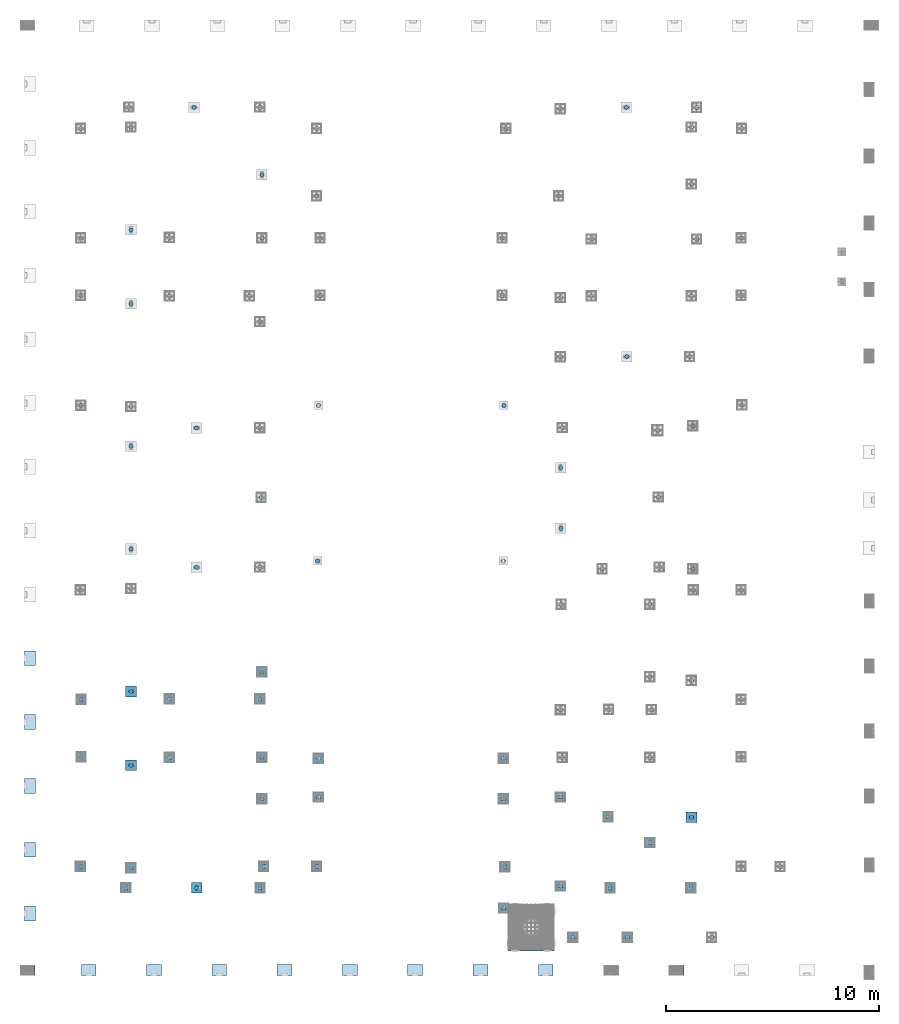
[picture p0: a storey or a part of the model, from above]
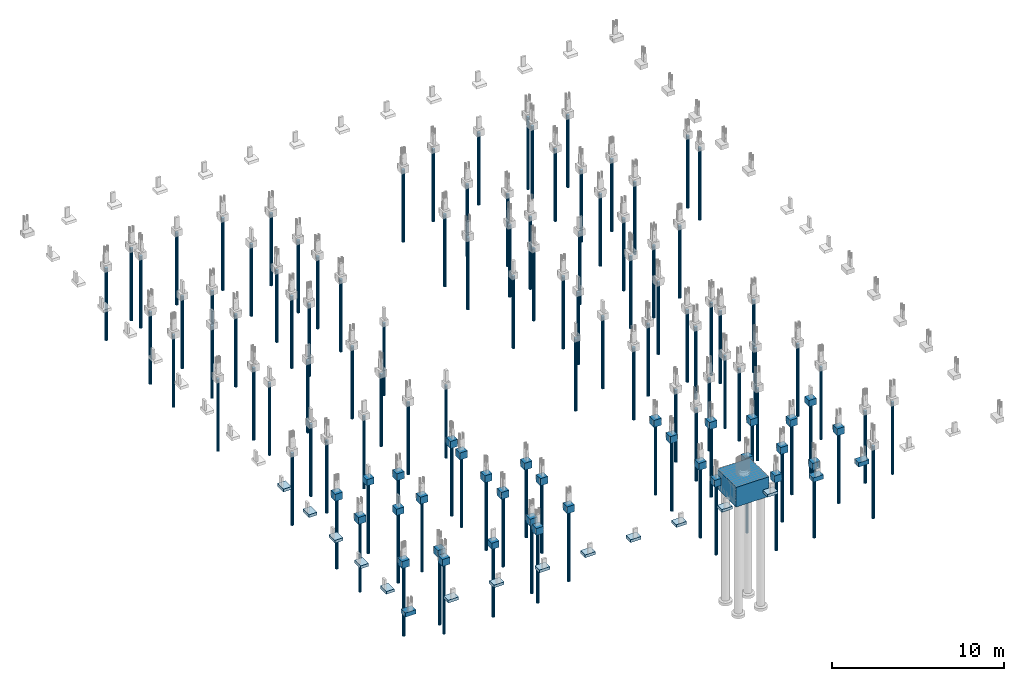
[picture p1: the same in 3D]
Properties of the parts of a building model (IFC4), part 1 of 9

# File
Description: ViewDefinition[]
File name: TIPO2-SCO-MOD_R03.IFC
Time: 2026-01-27T16:08:47+00:00
Organization: FUNDO NACIONAL DE DESENVOLVIMENTO DA EDUCAÇAO - FNDE
Written by: IfcOpenShell 0.8.3-post1
Made in: Bonsai 0.8.3-post1

# IfcProject, PROJETO PADRÃO - FNDE
Description: CRECHE PRÉ-ESCOLA TIPO 2; LongName: PROJETO DE ESTRUTURA DE CONCRETO; Phase: PROJETO PADRÃO

# IfcBuildingStorey (4)
In: CRECHE PRÉ-ESCOLA TIPO 2
Name | Elevation (cm)
FUNDAÇÃO | -14
VIGA BALDRAME | 16
TERREO | 326
COBERTURA | 456

# IfcBeam (614)
Material: Concreto
Pset_ConcreteElementGeneral - ConcreteCover: 2 cm; ConstructionMethod: InSitu; ExposureClass: 1; StrengthClass: C-30
AltoQi_Eberick_Elemento - Elemento: Viga; Tipo: retangular
AltoQi_Eberick_Padrão - Ambiente: Interno; Cobrimento: 2 cm; Classe de concreto: C-30
AltoQi_Eberick-Item_01 - Status_01: Dimensionado
AltoQi_Eberick-Item_02 - Status_02: Dimensionado
AltoQi_Eberick-Item_03 - Status_03: Dimensionado
AltoQi_Eberick_Cargas - Solo (S): 0; Acidental (Q): 0; Água (A): 0; Subpressão (AS): 0
Pset_BeamCommon - IsExternal: no; LoadBearing: yes
Name | In | Seção_bw (cm) | Seção_h (cm) | Elevação (cm) | Taxa de armadura | Descrição_01 | AltoQi_Eberick-Item_01, Quantidade_01 (m3) | Descrição_02 | AltoQi_Eberick-Item_02, Quantidade_02 (m2) | Descrição_03 | Quantidade_03 (kg) | Descrição_04 | AltoQi_Eberick-Item_04, Quantidade_04 (kg) | Status_04 | Cargas de parede (G2) | Adicional (G2) | Reference
V101 | VIGA BALDRAME | 15 | 30 | 0 | 0.22 % | Concreto - C-30 - Abatimento 12 cm | 0.137556 | Forma - Estrutura - Concreto | 2.29259 | Armadura - Aço CA50 - ø 8.0 mm | 5.03846 | Armadura - Aço CA60 - ø 5.0 mm | 1.91215 | Dimensionado | 567 | 0 | Viga C-30 - Seção Retangular 15 X 30
7 x V101 | VIGA BALDRAME | 15 | 30 | 0 | 0.22 % | Concreto - C-30 - Abatimento 12 cm | 0.137104 | Forma - Estrutura - Concreto | 2.28507 | Armadura - Aço CA50 - ø 8.0 mm | 5.02194 | Armadura - Aço CA60 - ø 5.0 mm | 1.90588 | Dimensionado | 567 | 0 | Viga C-30 - Seção Retangular 15 X 30
V101 | VIGA BALDRAME | 15 | 30 | 0 | 0.22 % | Concreto - C-30 - Abatimento 12 cm | 0.136653 | Forma - Estrutura - Concreto | 2.27756 | Armadura - Aço CA50 - ø 8.0 mm | 5.00541 | Armadura - Aço CA60 - ø 5.0 mm | 1.89961 | Dimensionado | 567 | 0 | Viga C-30 - Seção Retangular 15 X 30
V101 | VIGA BALDRAME | 15 | 30 | 0 | 0.22 % | Concreto - C-30 - Abatimento 12 cm | 0.139337 | Forma - Estrutura - Concreto | 2.32229 | Armadura - Aço CA50 - ø 8.0 mm | 5.10372 | Armadura - Aço CA60 - ø 5.0 mm | 1.93692 | Dimensionado | 567 | 0 | Viga C-30 - Seção Retangular 15 X 30
V101 | VIGA BALDRAME | 15 | 30 | 0 | 0.22 % | Concreto - C-30 - Abatimento 12 cm | 0.137105 | Forma - Estrutura - Concreto | 2.28508 | Armadura - Aço CA50 - ø 8.0 mm | 5.02194 | Armadura - Aço CA60 - ø 5.0 mm | 1.90588 | Dimensionado | 567 | 0 | Viga C-30 - Seção Retangular 15 X 30
V101 | VIGA BALDRAME | 15 | 30 | 0 | 0.22 % | Concreto - C-30 - Abatimento 12 cm | 0.137116 | Forma - Estrutura - Concreto | 2.28527 | Armadura - Aço CA50 - ø 8.0 mm | 5.02237 | Armadura - Aço CA60 - ø 5.0 mm | 1.90604 | Dimensionado | 567 | 0 | Viga C-30 - Seção Retangular 15 X 30
V101 | VIGA BALDRAME | 15 | 30 | 0 | 0.22 % | Concreto - C-30 - Abatimento 12 cm | 0.124377 | Forma - Estrutura - Concreto | 2.07294 | Armadura - Aço CA50 - ø 8.0 mm | 4.55573 | Armadura - Aço CA60 - ø 5.0 mm | 1.72895 | Dimensionado | 567 | 0 | Viga C-30 - Seção Retangular 15 X 30
V102 | VIGA BALDRAME | 20 | 30 | 0 | 0.17 % | Concreto - C-30 - Abatimento 12 cm | 0.183687 | Forma - Estrutura - Concreto | 2.44916 | Armadura - Aço CA50 - ø 8.0 mm | 2.60127 | Armadura - Aço CA50 - ø 10.0 mm | 4.11844 | Dimensionado | 1116 | 0 | Viga C-30 - Seção Retangular 20 X 30 | AltoQi_Eberick-Item_05 - Descrição_05: Armadura - Aço CA60 - ø 5.0 mm; Quantidade_05: 3.10681 kg; Status_05: Dimensionado
V102 | VIGA BALDRAME | 20 | 30 | 0 | 0.17 % | Concreto - C-30 - Abatimento 12 cm | 0.180913 | Forma - Estrutura - Concreto | 2.41217 | Armadura - Aço CA50 - ø 8.0 mm | 2.56198 | Armadura - Aço CA50 - ø 10.0 mm | 4.05624 | Dimensionado | 1116 | 0 | Viga C-30 - Seção Retangular 20 X 30 | AltoQi_Eberick-Item_05 - Descrição_05: Armadura - Aço CA60 - ø 5.0 mm; Quantidade_05: 3.05989 kg; Status_05: Dimensionado
V102 | VIGA BALDRAME | 20 | 30 | 0 | 0.17 % | Concreto - C-30 - Abatimento 12 cm | 0.013226 | Forma - Estrutura - Concreto | 0.176353 | Armadura - Aço CA50 - ø 8.0 mm | 0.187306 | Armadura - Aço CA50 - ø 10.0 mm | 0.29655 | Dimensionado | 1116 | 0 | Viga C-30 - Seção Retangular 20 X 30 | AltoQi_Eberick-Item_05 - Descrição_05: Armadura - Aço CA60 - ø 5.0 mm; Quantidade_05: 0.223708 kg; Status_05: Dimensionado
V103 | VIGA BALDRAME | 20 | 30 | 0 | 0.26 % | Concreto - C-30 - Abatimento 12 cm | 0.201368 | Forma - Estrutura - Concreto | 2.72628 | Armadura - Aço CA50 - ø 10.0 mm | 8.57005 | Armadura - Aço CA60 - ø 5.0 mm | 3.02885 | Dimensionado | 1116 | 0 | Viga C-30 - Seção Retangular 20 X 30
V103 | VIGA BALDRAME | 20 | 30 | 0 | 0.26 % | Concreto - C-30 - Abatimento 12 cm | 0.188032 | Forma - Estrutura - Concreto | 2.54572 | Armadura - Aço CA50 - ø 10.0 mm | 8.00248 | Armadura - Aço CA60 - ø 5.0 mm | 2.82826 | Dimensionado | 1116 | 0 | Viga C-30 - Seção Retangular 20 X 30
V104 | VIGA BALDRAME | 20 | 30 | 0 | 0.17 % | Concreto - C-30 - Abatimento 12 cm | 0.020966 | Forma - Estrutura - Concreto | 0.279542 | Armadura - Aço CA50 - ø 8.0 mm | 0.294816 | Armadura - Aço CA50 - ø 10.0 mm | 0.512554 | Dimensionado | 1116 | 0 | Viga C-30 - Seção Retangular 20 X 30 | AltoQi_Eberick-Item_05 - Descrição_05: Armadura - Aço CA60 - ø 5.0 mm; Quantidade_05: 0.465111 kg; Status_05: Dimensionado
V104 | VIGA BALDRAME | 20 | 30 | 0 | 0.17 % | Concreto - C-30 - Abatimento 12 cm | 0.138418 | Forma - Estrutura - Concreto | 1.84558 | Armadura - Aço CA50 - ø 8.0 mm | 1.94642 | Armadura - Aço CA50 - ø 10.0 mm | 3.38396 | Dimensionado | 1116 | 0 | Viga C-30 - Seção Retangular 20 X 30 | AltoQi_Eberick-Item_05 - Descrição_05: Armadura - Aço CA60 - ø 5.0 mm; Quantidade_05: 3.07073 kg; Status_05: Dimensionado
V105 | VIGA BALDRAME | 20 | 30 | 0 | 0.17 % | Concreto - C-30 - Abatimento 12 cm | 0.147504 | Forma - Estrutura - Concreto | 1.96672 | Armadura - Aço CA50 - ø 8.0 mm | 4.70344 | Armadura - Aço CA60 - ø 5.0 mm | 2.34284 | Dimensionado | 1116 | 0 | Viga C-30 - Seção Retangular 20 X 30
V106 | VIGA BALDRAME | 20 | 30 | 0 | 0.17 % | Concreto - C-30 - Abatimento 12 cm | 0.157662 | Forma - Estrutura - Concreto | 2.10216 | Armadura - Aço CA50 - ø 8.0 mm | 2.20178 | Armadura - Aço CA50 - ø 10.0 mm | 3.84719 | Dimensionado | 1116 | 0 | Viga C-30 - Seção Retangular 20 X 30 | AltoQi_Eberick-Item_05 - Descrição_05: Armadura - Aço CA60 - ø 5.0 mm; Quantidade_05: 2.34284 kg; Status_05: Dimensionado
V107 | VIGA BALDRAME | 20 | 30 | 0 | 0.17 % | Concreto - C-30 - Abatimento 12 cm | 0.138302 | Forma - Estrutura - Concreto | 1.84403 | Armadura - Aço CA50 - ø 8.0 mm | 1.88429 | Armadura - Aço CA50 - ø 10.0 mm | 3.37245 | Dimensionado | 1116 | 0 | Viga C-30 - Seção Retangular 20 X 30 | AltoQi_Eberick-Item_05 - Descrição_05: Armadura - Aço CA60 - ø 5.0 mm; Quantidade_05: 3.07 kg; Status_05: Dimensionado
V107 | VIGA BALDRAME | 20 | 30 | 0 | 0.17 % | Concreto - C-30 - Abatimento 12 cm | 0.020986 | Forma - Estrutura - Concreto | 0.279813 | Armadura - Aço CA50 - ø 8.0 mm | 0.285923 | Armadura - Aço CA50 - ø 10.0 mm | 0.511736 | Dimensionado | 1116 | 0 | Viga C-30 - Seção Retangular 20 X 30 | AltoQi_Eberick-Item_05 - Descrição_05: Armadura - Aço CA60 - ø 5.0 mm; Quantidade_05: 0.465843 kg; Status_05: Dimensionado
V108 | VIGA BALDRAME | 20 | 30 | 0 | 0.17 % | Concreto - C-30 - Abatimento 12 cm | 0.165504 | Forma - Estrutura - Concreto | 2.20672 | Armadura - Aço CA50 - ø 8.0 mm | 4.70344 | Armadura - Aço CA60 - ø 5.0 mm | 2.48927 | Dimensionado | 1116 | 0 | Viga C-30 - Seção Retangular 20 X 30
V109 | VIGA BALDRAME | 20 | 30 | 0 | 0.17 % | Concreto - C-30 - Abatimento 12 cm | 0.168445 | Forma - Estrutura - Concreto | 2.2461 | Armadura - Aço CA50 - ø 8.0 mm | 2.186 | Armadura - Aço CA50 - ø 12.5 mm | 6.53144 | Dimensionado | 1116 | 0 | Viga C-30 - Seção Retangular 20 X 30 | AltoQi_Eberick-Item_05 - Descrição_05: Armadura - Aço CA60 - ø 5.0 mm; Quantidade_05: 2.34284 kg; Status_05: Dimensionado
V110 | VIGA BALDRAME | 20 | 30 | 0 | 0.41 % | Concreto - C-30 - Abatimento 12 cm | 0.014043 | Forma - Estrutura - Concreto | 0.191987 | Armadura - Aço CA50 - ø 8.0 mm | 0.125344 | Armadura - Aço CA50 - ø 12.5 mm | 0.65757 | Dimensionado | 1116 | 0 | Viga C-30 - Seção Retangular 20 X 30 | AltoQi_Eberick-Item_05 - Descrição_05: Armadura - Aço CA50 - ø 16.0 mm; Quantidade_05: 0.282218 kg; Status_05: Dimensionado; AltoQi_Eberick-Item_06 - Descrição_06: Armadura - Aço CA60 - ø 5.0 mm; Quantidade_06: 0.258866 kg; Status_06: Dimensionado
V110 | VIGA BALDRAME | 20 | 30 | 0 | 0.17 % | Concreto - C-30 - Abatimento 12 cm | 0.252038 | Forma - Estrutura - Concreto | 3.4457 | Armadura - Aço CA50 - ø 8.0 mm | 2.24961 | Armadura - Aço CA50 - ø 12.5 mm | 11.8018 | Dimensionado | 1116 | 0 | Viga C-30 - Seção Retangular 20 X 30 | AltoQi_Eberick-Item_05 - Descrição_05: Armadura - Aço CA50 - ø 16.0 mm; Quantidade_05: 5.06513 kg; Status_05: Dimensionado; AltoQi_Eberick-Item_06 - Descrição_06: Armadura - Aço CA60 - ø 5.0 mm; Quantidade_06: 4.64602 kg; Status_06: Dimensionado
V110 | VIGA BALDRAME | 20 | 30 | 0 | 0.67 % | Concreto - C-30 - Abatimento 12 cm | 0.261612 | Forma - Estrutura - Concreto | 3.5766 | Armadura - Aço CA50 - ø 8.0 mm | 2.33507 | Armadura - Aço CA50 - ø 12.5 mm | 12.2501 | Dimensionado | 1116 | 0 | Viga C-30 - Seção Retangular 20 X 30 | AltoQi_Eberick-Item_05 - Descrição_05: Armadura - Aço CA50 - ø 16.0 mm; Quantidade_05: 5.25755 kg; Status_05: Dimensionado; AltoQi_Eberick-Item_06 - Descrição_06: Armadura - Aço CA60 - ø 5.0 mm; Quantidade_06: 4.82252 kg; Status_06: Dimensionado
V110 | VIGA BALDRAME | 20 | 30 | 0 | 0.17 % | Concreto - C-30 - Abatimento 12 cm | 0.165274 | Forma - Estrutura - Concreto | 2.25952 | Armadura - Aço CA50 - ø 8.0 mm | 1.47518 | Armadura - Aço CA50 - ø 12.5 mm | 7.73901 | Dimensionado | 1116 | 0 | Viga C-30 - Seção Retangular 20 X 30 | AltoQi_Eberick-Item_05 - Descrição_05: Armadura - Aço CA50 - ø 16.0 mm; Quantidade_05: 3.32146 kg; Status_05: Dimensionado; AltoQi_Eberick-Item_06 - Descrição_06: Armadura - Aço CA60 - ø 5.0 mm; Quantidade_06: 3.04663 kg; Status_06: Dimensionado
V110 | VIGA BALDRAME | 20 | 30 | 0 | 0.17 % | Concreto - C-30 - Abatimento 12 cm | 0.017008 | Forma - Estrutura - Concreto | 0.232517 | Armadura - Aço CA50 - ø 8.0 mm | 0.151804 | Armadura - Aço CA50 - ø 12.5 mm | 0.796387 | Dimensionado | 1116 | 0 | Viga C-30 - Seção Retangular 20 X 30 | AltoQi_Eberick-Item_05 - Descrição_05: Armadura - Aço CA50 - ø 16.0 mm; Quantidade_05: 0.341796 kg; Status_05: Dimensionado; AltoQi_Eberick-Item_06 - Descrição_06: Armadura - Aço CA60 - ø 5.0 mm; Quantidade_06: 0.313515 kg; Status_06: Dimensionado
V111 | VIGA BALDRAME | 20 | 30 | 0 | 0.67 % | Concreto - C-30 - Abatimento 12 cm | 0.302538 | Forma - Estrutura - Concreto | 4.06756 | Armadura - Aço CA50 - ø 8.0 mm | 0.931239 | Armadura - Aço CA50 - ø 12.5 mm | 17.6361 | Dimensionado | 1116 | 0 | Viga C-30 - Seção Retangular 20 X 30 | AltoQi_Eberick-Item_05 - Descrição_05: Armadura - Aço CA50 - ø 16.0 mm; Quantidade_05: 6.94438 kg; Status_05: Dimensionado; AltoQi_Eberick-Item_06 - Descrição_06: Armadura - Aço CA60 - ø 5.0 mm; Quantidade_06: 5.76243 kg; Status_06: Dimensionado
V111 | VIGA BALDRAME | 20 | 30 | 0 | 0.17 % | Concreto - C-30 - Abatimento 12 cm | 0.127486 | Forma - Estrutura - Concreto | 1.71402 | Armadura - Aço CA50 - ø 8.0 mm | 0.392414 | Armadura - Aço CA50 - ø 12.5 mm | 7.43167 | Dimensionado | 1116 | 0 | Viga C-30 - Seção Retangular 20 X 30 | AltoQi_Eberick-Item_05 - Descrição_05: Armadura - Aço CA50 - ø 16.0 mm; Quantidade_05: 2.92629 kg; Status_05: Dimensionado; AltoQi_Eberick-Item_06 - Descrição_06: Armadura - Aço CA60 - ø 5.0 mm; Quantidade_06: 2.42823 kg; Status_06: Dimensionado
V111 | VIGA BALDRAME | 20 | 30 | 0 | 0.17 % | Concreto - C-30 - Abatimento 12 cm | 0.017366 | Forma - Estrutura - Concreto | 0.233488 | Armadura - Aço CA50 - ø 8.0 mm | 0.053455 | Armadura - Aço CA50 - ø 12.5 mm | 1.01236 | Dimensionado | 1116 | 0 | Viga C-30 - Seção Retangular 20 X 30 | AltoQi_Eberick-Item_05 - Descrição_05: Armadura - Aço CA50 - ø 16.0 mm; Quantidade_05: 0.398624 kg; Status_05: Dimensionado; AltoQi_Eberick-Item_06 - Descrição_06: Armadura - Aço CA60 - ø 5.0 mm; Quantidade_06: 0.330777 kg; Status_06: Dimensionado
V111 | VIGA BALDRAME | 20 | 30 | 0 | 0.41 % | Concreto - C-30 - Abatimento 12 cm | 0.014775 | Forma - Estrutura - Concreto | 0.198645 | Armadura - Aço CA50 - ø 8.0 mm | 0.045478 | Armadura - Aço CA50 - ø 12.5 mm | 0.861284 | Dimensionado | 1116 | 0 | Viga C-30 - Seção Retangular 20 X 30 | AltoQi_Eberick-Item_05 - Descrição_05: Armadura - Aço CA50 - ø 16.0 mm; Quantidade_05: 0.339139 kg; Status_05: Dimensionado; AltoQi_Eberick-Item_06 - Descrição_06: Armadura - Aço CA60 - ø 5.0 mm; Quantidade_06: 0.281416 kg; Status_06: Dimensionado
V111 | VIGA BALDRAME | 20 | 30 | 0 | 0.41 % | Concreto - C-30 - Abatimento 12 cm | 0.255705 | Forma - Estrutura - Concreto | 3.4379 | Armadura - Aço CA50 - ø 8.0 mm | 0.787084 | Armadura - Aço CA50 - ø 12.5 mm | 14.9061 | Dimensionado | 1116 | 0 | Viga C-30 - Seção Retangular 20 X 30 | AltoQi_Eberick-Item_05 - Descrição_05: Armadura - Aço CA50 - ø 16.0 mm; Quantidade_05: 5.86939 kg; Status_05: Dimensionado; AltoQi_Eberick-Item_06 - Descrição_06: Armadura - Aço CA60 - ø 5.0 mm; Quantidade_06: 4.87041 kg; Status_06: Dimensionado
V112 | VIGA BALDRAME | 15 | 30 | 0 | 0.22 % | Concreto - C-30 - Abatimento 12 cm | 0.05985 | Forma - Estrutura - Concreto | 0.9975 | Armadura - Aço CA50 - ø 8.0 mm | 2.82522 | Armadura - Aço CA60 - ø 5.0 mm | 0.786085 | Dimensionado | 837 | 0 | Viga C-30 - Seção Retangular 15 X 30
V113 | VIGA BALDRAME | 20 | 30 | 0 | 0.17 % | Concreto - C-30 - Abatimento 12 cm | 0.25504 | Forma - Estrutura - Concreto | 3.48574 | Armadura - Aço CA50 - ø 8.0 mm | 1.33923 | Armadura - Aço CA50 - ø 10.0 mm | 10.2307 | Dimensionado | 1116 | 0 | Viga C-30 - Seção Retangular 20 X 30 | AltoQi_Eberick-Item_05 - Descrição_05: Armadura - Aço CA60 - ø 5.0 mm; Quantidade_05: 4.59441 kg; Status_05: Dimensionado
V113 | VIGA BALDRAME | 20 | 30 | 0 | 0.26 % | Concreto - C-30 - Abatimento 12 cm | 0.202747 | Forma - Estrutura - Concreto | 2.77102 | Armadura - Aço CA50 - ø 8.0 mm | 1.06463 | Armadura - Aço CA50 - ø 10.0 mm | 8.13301 | Dimensionado | 1116 | 0 | Viga C-30 - Seção Retangular 20 X 30 | AltoQi_Eberick-Item_05 - Descrição_05: Armadura - Aço CA60 - ø 5.0 mm; Quantidade_05: 3.65237 kg; Status_05: Dimensionado
V113 | VIGA BALDRAME | 20 | 30 | 0 | 0.26 % | Concreto - C-30 - Abatimento 12 cm | 0.016949 | Forma - Estrutura - Concreto | 0.23165 | Armadura - Aço CA50 - ø 8.0 mm | 0.089 | Armadura - Aço CA50 - ø 10.0 mm | 0.679896 | Dimensionado | 1116 | 0 | Viga C-30 - Seção Retangular 20 X 30 | AltoQi_Eberick-Item_05 - Descrição_05: Armadura - Aço CA60 - ø 5.0 mm; Quantidade_05: 0.305328 kg; Status_05: Dimensionado
V113 | VIGA BALDRAME | 20 | 30 | 0 | 0.17 % | Concreto - C-30 - Abatimento 12 cm | 0.014194 | Forma - Estrutura - Concreto | 0.194 | Armadura - Aço CA50 - ø 8.0 mm | 0.074535 | Armadura - Aço CA50 - ø 10.0 mm | 0.569394 | Dimensionado | 1116 | 0 | Viga C-30 - Seção Retangular 20 X 30 | AltoQi_Eberick-Item_05 - Descrição_05: Armadura - Aço CA60 - ø 5.0 mm; Quantidade_05: 0.255703 kg; Status_05: Dimensionado
V113 | VIGA BALDRAME | 20 | 30 | 0 | 0.26 % | Concreto - C-30 - Abatimento 12 cm | 0.229444 | Forma - Estrutura - Concreto | 3.13591 | Armadura - Aço CA50 - ø 8.0 mm | 1.20482 | Armadura - Aço CA50 - ø 10.0 mm | 9.20395 | Dimensionado | 1116 | 0 | Viga C-30 - Seção Retangular 20 X 30 | AltoQi_Eberick-Item_05 - Descrição_05: Armadura - Aço CA60 - ø 5.0 mm; Quantidade_05: 4.13331 kg; Status_05: Dimensionado
V114 | VIGA BALDRAME | 20 | 30 | 0 | 0.41 % | Concreto - C-30 - Abatimento 12 cm | 0.014778 | Forma - Estrutura - Concreto | 0.19539 | Armadura - Aço CA50 - ø 10.0 mm | 0.524931 | Armadura - Aço CA50 - ø 12.5 mm | 0.590365 | Dimensionado | 1116 | 0 | Viga C-30 - Seção Retangular 20 X 30 | AltoQi_Eberick-Item_05 - Descrição_05: Armadura - Aço CA60 - ø 5.0 mm; Quantidade_05: 0.305586 kg; Status_05: Dimensionado
V114 | VIGA BALDRAME | 20 | 30 | 0 | 0.41 % | Concreto - C-30 - Abatimento 12 cm | 0.167685 | Forma - Estrutura - Concreto | 2.21711 | Armadura - Aço CA50 - ø 10.0 mm | 5.95645 | Armadura - Aço CA50 - ø 12.5 mm | 6.69893 | Dimensionado | 1116 | 0 | Viga C-30 - Seção Retangular 20 X 30 | AltoQi_Eberick-Item_05 - Descrição_05: Armadura - Aço CA60 - ø 5.0 mm; Quantidade_05: 3.46751 kg; Status_05: Dimensionado
V114 | VIGA BALDRAME | 20 | 30 | 0 | 0.41 % | Concreto - C-30 - Abatimento 12 cm | 0.088265 | Forma - Estrutura - Concreto | 1.16702 | Armadura - Aço CA50 - ø 10.0 mm | 3.13531 | Armadura - Aço CA50 - ø 12.5 mm | 3.52614 | Dimensionado | 1116 | 0 | Viga C-30 - Seção Retangular 20 X 30 | AltoQi_Eberick-Item_05 - Descrição_05: Armadura - Aço CA60 - ø 5.0 mm; Quantidade_05: 1.8252 kg; Status_05: Dimensionado
V114 | VIGA BALDRAME | 20 | 30 | 0 | 0.61 % | Concreto - C-30 - Abatimento 12 cm | 0.286984 | Forma - Estrutura - Concreto | 3.79447 | Armadura - Aço CA50 - ø 10.0 mm | 10.1942 | Armadura - Aço CA50 - ø 12.5 mm | 11.4649 | Dimensionado | 1116 | 0 | Viga C-30 - Seção Retangular 20 X 30 | AltoQi_Eberick-Item_05 - Descrição_05: Armadura - Aço CA60 - ø 5.0 mm; Quantidade_05: 5.93447 kg; Status_05: Dimensionado
V114 | VIGA BALDRAME | 20 | 30 | 0 | 0.41 % | Concreto - C-30 - Abatimento 12 cm | 0.01737 | Forma - Estrutura - Concreto | 0.229661 | Armadura - Aço CA50 - ø 10.0 mm | 0.617005 | Armadura - Aço CA50 - ø 12.5 mm | 0.693916 | Dimensionado | 1116 | 0 | Viga C-30 - Seção Retangular 20 X 30 | AltoQi_Eberick-Item_05 - Descrição_05: Armadura - Aço CA60 - ø 5.0 mm; Quantidade_05: 0.359186 kg; Status_05: Dimensionado
V114 | VIGA BALDRAME | 20 | 30 | 0 | 0.41 % | Concreto - C-30 - Abatimento 12 cm | 0.14279 | Forma - Estrutura - Concreto | 1.88795 | Armadura - Aço CA50 - ø 10.0 mm | 5.07214 | Armadura - Aço CA50 - ø 12.5 mm | 5.70439 | Dimensionado | 1116 | 0 | Viga C-30 - Seção Retangular 20 X 30 | AltoQi_Eberick-Item_05 - Descrição_05: Armadura - Aço CA60 - ø 5.0 mm; Quantidade_05: 2.95272 kg; Status_05: Dimensionado
V115 | VIGA BALDRAME | 20 | 30 | 0 | 0.26 % | Concreto - C-30 - Abatimento 12 cm | 0.047112 | Forma - Estrutura - Concreto | 0.62816 | Armadura - Aço CA50 - ø 10.0 mm | 2.50314 | Armadura - Aço CA60 - ø 5.0 mm | 1.02499 | Dimensionado | 1116 | 0 | Viga C-30 - Seção Retangular 20 X 30
V116 | VIGA BALDRAME | 20 | 30 | 0 | 0.26 % | Concreto - C-30 - Abatimento 12 cm | 0.180244 | Forma - Estrutura - Concreto | 2.40325 | Armadura - Aço CA50 - ø 8.0 mm | 2.94893 | Armadura - Aço CA50 - ø 10.0 mm | 3.76446 | Dimensionado | 1116 | 0 | Viga C-30 - Seção Retangular 20 X 30 | AltoQi_Eberick-Item_05 - Descrição_05: Armadura - Aço CA60 - ø 5.0 mm; Quantidade_05: 2.64642 kg; Status_05: Dimensionado
V116 | VIGA BALDRAME | 20 | 30 | 0 | 0.26 % | Concreto - C-30 - Abatimento 12 cm | 0.188756 | Forma - Estrutura - Concreto | 2.51675 | Armadura - Aço CA50 - ø 8.0 mm | 3.08821 | Armadura - Aço CA50 - ø 10.0 mm | 3.94226 | Dimensionado | 1116 | 0 | Viga C-30 - Seção Retangular 20 X 30 | AltoQi_Eberick-Item_05 - Descrição_05: Armadura - Aço CA60 - ø 5.0 mm; Quantidade_05: 2.77141 kg; Status_05: Dimensionado
V117 | VIGA BALDRAME | 20 | 30 | 0 | 0.17 % | Concreto - C-30 - Abatimento 12 cm | 0.021576 | Forma - Estrutura - Concreto | 0.287681 | Armadura - Aço CA50 - ø 8.0 mm | 0.638849 | Armadura - Aço CA60 - ø 5.0 mm | 0.356798 | Dimensionado | 1116 | 0 | Viga C-30 - Seção Retangular 20 X 30
V117 | VIGA BALDRAME | 20 | 30 | 0 | 0.17 % | Concreto - C-30 - Abatimento 12 cm | 0.137808 | Forma - Estrutura - Concreto | 1.83744 | Armadura - Aço CA50 - ø 8.0 mm | 4.08038 | Armadura - Aço CA60 - ø 5.0 mm | 2.2789 | Dimensionado | 1116 | 0 | Viga C-30 - Seção Retangular 20 X 30
V118 | VIGA BALDRAME | 20 | 30 | 0 | 0.17 % | Concreto - C-30 - Abatimento 12 cm | 0.021 | Forma - Estrutura - Concreto | 0.28 | Armadura - Aço CA50 - ø 8.0 mm | 0.282797 | Armadura - Aço CA50 - ø 10.0 mm | 0.516308 | Dimensionado | 1116 | 0 | Viga C-30 - Seção Retangular 20 X 30 | AltoQi_Eberick-Item_05 - Descrição_05: Armadura - Aço CA60 - ø 5.0 mm; Quantidade_05: 0.433754 kg; Status_05: Dimensionado
V118 | VIGA BALDRAME | 20 | 30 | 0 | 0.17 % | Concreto - C-30 - Abatimento 12 cm | 0.1425 | Forma - Estrutura - Concreto | 1.9 | Armadura - Aço CA50 - ø 8.0 mm | 1.91898 | Armadura - Aço CA50 - ø 10.0 mm | 3.50352 | Dimensionado | 1116 | 0 | Viga C-30 - Seção Retangular 20 X 30 | AltoQi_Eberick-Item_05 - Descrição_05: Armadura - Aço CA60 - ø 5.0 mm; Quantidade_05: 2.94333 kg; Status_05: Dimensionado
V119 | VIGA BALDRAME | 15 | 30 | 0 | 0.22 % | Concreto - C-30 - Abatimento 12 cm | 0.02529 | Forma - Estrutura - Concreto | 0.4215 | Armadura - Aço CA50 - ø 8.0 mm | 1.59412 | Armadura - Aço CA60 - ø 5.0 mm | 0.393043 | Dimensionado | 1116 | 0 | Viga C-30 - Seção Retangular 15 X 30
V120 | VIGA BALDRAME | 20 | 30 | 0 | 0.26 % | Concreto - C-30 - Abatimento 12 cm | 0.18919 | Forma - Estrutura - Concreto | 2.52253 | Armadura - Aço CA50 - ø 10.0 mm | 8.045 | Armadura - Aço CA60 - ø 5.0 mm | 2.7508 | Dimensionado | 1116 | 0 | Viga C-30 - Seção Retangular 20 X 30
V120 | VIGA BALDRAME | 20 | 30 | 0 | 0.26 % | Concreto - C-30 - Abatimento 12 cm | 0.183428 | Forma - Estrutura - Concreto | 2.44571 | Armadura - Aço CA50 - ø 10.0 mm | 7.80002 | Armadura - Aço CA60 - ø 5.0 mm | 2.66703 | Dimensionado | 1116 | 0 | Viga C-30 - Seção Retangular 20 X 30
V121 | VIGA BALDRAME | 15 | 30 | 0 | 0.22 % | Concreto - C-30 - Abatimento 12 cm | 0.020281 | Forma - Estrutura - Concreto | 0.338025 | Armadura - Aço CA50 - ø 8.0 mm | 1.24689 | Armadura - Aço CA60 - ø 5.0 mm | 0.262028 | Dimensionado | 1116 | 0 | Viga C-30 - Seção Retangular 15 X 30
V122 | VIGA BALDRAME | 15 | 30 | 0 | 0.55 % | Concreto - C-30 - Abatimento 12 cm | 0.071582 | Forma - Estrutura - Concreto | 1.19304 | Armadura - Aço CA50 - ø 12.5 mm | 6.75122 | Armadura - Aço CA60 - ø 5.0 mm | 1.03045 | Dimensionado | 1116 | 0 | Viga C-30 - Seção Retangular 15 X 30
V122 | VIGA BALDRAME | 15 | 30 | 0 | 0.55 % | Concreto - C-30 - Abatimento 12 cm | 0.192352 | Forma - Estrutura - Concreto | 3.20586 | Armadura - Aço CA50 - ø 12.5 mm | 18.1415 | Armadura - Aço CA60 - ø 5.0 mm | 2.76896 | Dimensionado | 1116 | 0 | Viga C-30 - Seção Retangular 15 X 30
V123 | VIGA BALDRAME | 14 | 30 | 0 | 0.24 % | Concreto - C-30 - Abatimento 12 cm | 0.070778 | Forma - Estrutura - Concreto | 1.24705 | Armadura - Aço CA50 - ø 8.0 mm | 3.19613 | Armadura - Aço CA60 - ø 5.0 mm | 1.02345 | Dimensionado | 0 | 0 | Viga C-30 - Seção Retangular 14 X 30
V124 | VIGA BALDRAME | 15 | 30 | 0 | 0.22 % | Concreto - C-30 - Abatimento 12 cm | 0.020281 | Forma - Estrutura - Concreto | 0.338025 | Armadura - Aço CA50 - ø 8.0 mm | 1.24689 | Armadura - Aço CA60 - ø 5.0 mm | 0.262028 | Dimensionado | 1116 | 0 | Viga C-30 - Seção Retangular 15 X 30
V125 | VIGA BALDRAME | 20 | 30 | 0 | 0.26 % | Concreto - C-30 - Abatimento 12 cm | 0.183428 | Forma - Estrutura - Concreto | 2.44571 | Armadura - Aço CA50 - ø 10.0 mm | 7.80002 | Armadura - Aço CA60 - ø 5.0 mm | 2.66703 | Dimensionado | 1116 | 0 | Viga C-30 - Seção Retangular 20 X 30
V125 | VIGA BALDRAME | 20 | 30 | 0 | 0.26 % | Concreto - C-30 - Abatimento 12 cm | 0.18919 | Forma - Estrutura - Concreto | 2.52253 | Armadura - Aço CA50 - ø 10.0 mm | 8.045 | Armadura - Aço CA60 - ø 5.0 mm | 2.7508 | Dimensionado | 1116 | 0 | Viga C-30 - Seção Retangular 20 X 30
V126 | VIGA BALDRAME | 12 | 40 | 0 | 0.21 % | Concreto - C-30 - Abatimento 12 cm | 0.04176 | Forma - Estrutura - Concreto | 0.8004 | Armadura - Aço CA50 - ø 8.0 mm | 1.12851 | Armadura - Aço CA50 - ø 10.0 mm | 2.17021 | Dimensionado | 1116 | 0 | Viga C-30 - Seção Retangular 12 X 40 | AltoQi_Eberick-Item_05 - Descrição_05: Armadura - Aço CA60 - ø 5.0 mm; Quantidade_05: 1.77409 kg; Status_05: Dimensionado
V127 | VIGA BALDRAME | 15 | 30 | 0 | 0.22 % | Concreto - C-30 - Abatimento 12 cm | 0.109013 | Forma - Estrutura - Concreto | 1.76438 | Armadura - Aço CA50 - ø 8.0 mm | 4.64031 | Armadura - Aço CA60 - ø 5.0 mm | 1.44116 | Dimensionado | 1116 | 0 | Viga C-30 - Seção Retangular 15 X 30
V128 | VIGA BALDRAME | 20 | 30 | 0 | 0.17 % | Concreto - C-30 - Abatimento 12 cm | 0.026292 | Forma - Estrutura - Concreto | 0.35056 | Armadura - Aço CA50 - ø 8.0 mm | 0.855101 | Armadura - Aço CA60 - ø 5.0 mm | 0.449647 | Dimensionado | 1116 | 0 | Viga C-30 - Seção Retangular 20 X 30
V128 | VIGA BALDRAME | 20 | 30 | 0 | 0.17 % | Concreto - C-30 - Abatimento 12 cm | 0.093576 | Forma - Estrutura - Concreto | 1.24768 | Armadura - Aço CA50 - ø 8.0 mm | 3.04339 | Armadura - Aço CA60 - ø 5.0 mm | 1.60034 | Dimensionado | 1116 | 0 | Viga C-30 - Seção Retangular 20 X 30
V129 | VIGA BALDRAME | 15 | 30 | 0 | 0.22 % | Concreto - C-30 - Abatimento 12 cm | 0.025969 | Forma - Estrutura - Concreto | 0.432825 | Armadura - Aço CA50 - ø 8.0 mm | 1.62569 | Armadura - Aço CA60 - ø 5.0 mm | 0.393043 | Dimensionado | 1116 | 0 | Viga C-30 - Seção Retangular 15 X 30
V130 | VIGA BALDRAME | 20 | 30 | 0 | 0.26 % | Concreto - C-30 - Abatimento 12 cm | 0.020384 | Forma - Estrutura - Concreto | 0.271786 | Armadura - Aço CA50 - ø 10.0 mm | 0.949501 | Armadura - Aço CA60 - ø 5.0 mm | 0.450698 | Dimensionado | 1116 | 0 | Viga C-30 - Seção Retangular 20 X 30
V130 | VIGA BALDRAME | 20 | 30 | 0 | 0.26 % | Concreto - C-30 - Abatimento 12 cm | 0.138976 | Forma - Estrutura - Concreto | 1.85301 | Armadura - Aço CA50 - ø 10.0 mm | 6.47361 | Armadura - Aço CA60 - ø 5.0 mm | 3.07281 | Dimensionado | 1116 | 0 | Viga C-30 - Seção Retangular 20 X 30
V131 | VIGA BALDRAME | 20 | 30 | 0 | 0.17 % | Concreto - C-30 - Abatimento 12 cm | 0.023471 | Forma - Estrutura - Concreto | 0.312947 | Armadura - Aço CA50 - ø 8.0 mm | 0.644166 | Armadura - Aço CA60 - ø 5.0 mm | 0.372217 | Dimensionado | 1116 | 0 | Viga C-30 - Seção Retangular 20 X 30
V131 | VIGA BALDRAME | 20 | 30 | 0 | 0.17 % | Concreto - C-30 - Abatimento 12 cm | 0.142729 | Forma - Estrutura - Concreto | 1.90305 | Armadura - Aço CA50 - ø 8.0 mm | 3.91723 | Armadura - Aço CA60 - ø 5.0 mm | 2.26348 | Dimensionado | 1116 | 0 | Viga C-30 - Seção Retangular 20 X 30
V132 | VIGA BALDRAME | 12 | 40 | 0 | 0.21 % | Concreto - C-30 - Abatimento 12 cm | 0.02496 | Forma - Estrutura - Concreto | 0.4784 | Armadura - Aço CA50 - ø 8.0 mm | 1.38104 | Armadura - Aço CA60 - ø 5.0 mm | 0.457779 | Dimensionado | 1116 | 0 | Viga C-30 - Seção Retangular 12 X 40
V133 | VIGA BALDRAME | 15 | 30 | 0 | 0.55 % | Concreto - C-30 - Abatimento 12 cm | 0.027387 | Forma - Estrutura - Concreto | 0.449573 | Armadura - Aço CA50 - ø 12.5 mm | 2.52863 | Armadura - Aço CA60 - ø 5.0 mm | 0.407968 | Dimensionado | 1116 | 0 | Viga C-30 - Seção Retangular 15 X 30
V133 | VIGA BALDRAME | 15 | 30 | 0 | 0.55 % | Concreto - C-30 - Abatimento 12 cm | 0.085838 | Forma - Estrutura - Concreto | 1.4091 | Armadura - Aço CA50 - ø 12.5 mm | 7.9255 | Armadura - Aço CA60 - ø 5.0 mm | 1.2787 | Dimensionado | 1116 | 0 | Viga C-30 - Seção Retangular 15 X 30
V133 | VIGA BALDRAME | 15 | 30 | 0 | 0.55 % | Concreto - C-30 - Abatimento 12 cm | 0.185801 | Forma - Estrutura - Concreto | 3.05008 | Armadura - Aço CA50 - ø 12.5 mm | 17.1552 | Armadura - Aço CA60 - ø 5.0 mm | 2.76782 | Dimensionado | 1116 | 0 | Viga C-30 - Seção Retangular 15 X 30
V134 | VIGA BALDRAME | 20 | 30 | 0 | 0.17 % | Concreto - C-30 - Abatimento 12 cm | 0.039432 | Forma - Estrutura - Concreto | 0.52576 | Armadura - Aço CA50 - ø 8.0 mm | 1.74406 | Armadura - Aço CA60 - ø 5.0 mm | 0.585711 | Dimensionado | 1116 | 0 | Viga C-30 - Seção Retangular 20 X 30
V135 | VIGA BALDRAME | 20 | 30 | 0 | 0.17 % | Concreto - C-30 - Abatimento 12 cm | 0.108756 | Forma - Estrutura - Concreto | 1.45008 | Armadura - Aço CA50 - ø 8.0 mm | 3.64596 | Armadura - Aço CA60 - ø 5.0 mm | 2.05769 | Dimensionado | 1116 | 0 | Viga C-30 - Seção Retangular 20 X 30
V136 | VIGA BALDRAME | 20 | 30 | 0 | 0.61 % | Concreto - C-30 - Abatimento 12 cm | 0.253362 | Forma - Estrutura - Concreto | 3.45663 | Armadura - Aço CA50 - ø 12.5 mm | 19.8002 | Armadura - Aço CA60 - ø 5.0 mm | 4.46291 | Dimensionado | 1116 | 0 | Viga C-30 - Seção Retangular 20 X 30
V136 | VIGA BALDRAME | 20 | 30 | 0 | 0.41 % | Concreto - C-30 - Abatimento 12 cm | 0.01542 | Forma - Estrutura - Concreto | 0.210378 | Armadura - Aço CA50 - ø 12.5 mm | 1.20508 | Armadura - Aço CA60 - ø 5.0 mm | 0.271623 | Dimensionado | 1116 | 0 | Viga C-30 - Seção Retangular 20 X 30
V136 | VIGA BALDRAME | 20 | 30 | 0 | 0.41 % | Concreto - C-30 - Abatimento 12 cm | 0.247836 | Forma - Estrutura - Concreto | 3.38123 | Armadura - Aço CA50 - ø 12.5 mm | 19.3683 | Armadura - Aço CA60 - ø 5.0 mm | 4.36556 | Dimensionado | 1116 | 0 | Viga C-30 - Seção Retangular 20 X 30
V137 | VIGA BALDRAME | 20 | 30 | 0 | 0.17 % | Concreto - C-30 - Abatimento 12 cm | 0.140544 | Forma - Estrutura - Concreto | 1.87392 | Armadura - Aço CA50 - ø 8.0 mm | 4.26151 | Armadura - Aço CA60 - ø 5.0 mm | 2.04999 | Dimensionado | 1116 | 0 | Viga C-30 - Seção Retangular 20 X 30
V138 | VIGA BALDRAME | 20 | 30 | 0 | 0.17 % | Concreto - C-30 - Abatimento 12 cm | 0.113856 | Forma - Estrutura - Concreto | 1.51808 | Armadura - Aço CA50 - ø 8.0 mm | 1.62569 | Armadura - Aço CA50 - ø 12.5 mm | 4.62403 | Dimensionado | 1116 | 0 | Viga C-30 - Seção Retangular 20 X 30 | AltoQi_Eberick-Item_05 - Descrição_05: Armadura - Aço CA60 - ø 5.0 mm; Quantidade_05: 1.75713 kg; Status_05: Dimensionado
V139 | VIGA BALDRAME | 20 | 30 | 0 | 0.26 % | Concreto - C-30 - Abatimento 12 cm | 0.028458 | Forma - Estrutura - Concreto | 0.379442 | Armadura - Aço CA50 - ø 10.0 mm | 1.61605 | Armadura - Aço CA60 - ø 5.0 mm | 1.15628 | Dimensionado | 1116 | 0 | Viga C-30 - Seção Retangular 20 X 30
V139 | VIGA BALDRAME | 20 | 30 | 0 | 0.26 % | Concreto - C-30 - Abatimento 12 cm | 0.01953 | Forma - Estrutura - Concreto | 0.260398 | Armadura - Aço CA50 - ø 10.0 mm | 1.10904 | Armadura - Aço CA60 - ø 5.0 mm | 0.793517 | Dimensionado | 1116 | 0 | Viga C-30 - Seção Retangular 20 X 30
V140 | VIGA BALDRAME | 20 | 30 | 0 | 0.41 % | Concreto - C-30 - Abatimento 12 cm | 0.250151 | Forma - Estrutura - Concreto | 3.41132 | Armadura - Aço CA50 - ø 12.5 mm | 20.7626 | Armadura - Aço CA60 - ø 5.0 mm | 4.2515 | Dimensionado | 1116 | 0 | Viga C-30 - Seção Retangular 20 X 30
V140 | VIGA BALDRAME | 20 | 30 | 0 | 0.61 % | Concreto - C-30 - Abatimento 12 cm | 0.261127 | Forma - Estrutura - Concreto | 3.561 | Armadura - Aço CA50 - ø 12.5 mm | 21.6736 | Armadura - Aço CA60 - ø 5.0 mm | 4.43804 | Dimensionado | 1116 | 0 | Viga C-30 - Seção Retangular 20 X 30
V140 | VIGA BALDRAME | 20 | 30 | 0 | 0.41 % | Concreto - C-30 - Abatimento 12 cm | 0.01554 | Forma - Estrutura - Concreto | 0.211926 | Armadura - Aço CA50 - ø 12.5 mm | 1.28986 | Armadura - Aço CA60 - ø 5.0 mm | 0.264122 | Dimensionado | 1116 | 0 | Viga C-30 - Seção Retangular 20 X 30
V141 | VIGA BALDRAME | 20 | 30 | 0 | 0.17 % | Concreto - C-30 - Abatimento 12 cm | 0.01611 | Forma - Estrutura - Concreto | 0.2148 | Armadura - Aço CA50 - ø 8.0 mm | 0.947002 | Armadura - Aço CA60 - ø 5.0 mm | 0.439283 | Dimensionado | 1116 | 0 | Viga C-30 - Seção Retangular 20 X 30
V142 | VIGA BALDRAME | 20 | 30 | 0 | 0.17 % | Concreto - C-30 - Abatimento 12 cm | 0.171006 | Forma - Estrutura - Concreto | 2.28008 | Armadura - Aço CA50 - ø 8.0 mm | 2.39118 | Armadura - Aço CA50 - ø 10.0 mm | 3.95817 | Dimensionado | 1116 | 0 | Viga C-30 - Seção Retangular 20 X 30 | AltoQi_Eberick-Item_05 - Descrição_05: Armadura - Aço CA60 - ø 5.0 mm; Quantidade_05: 3.22912 kg; Status_05: Dimensionado
V143 | VIGA BALDRAME | 20 | 30 | 0 | 0.41 % | Concreto - C-30 - Abatimento 12 cm | 0.120439 | Forma - Estrutura - Concreto | 1.58034 | Armadura - Aço CA50 - ø 12.5 mm | 10.4013 | Armadura - Aço CA60 - ø 5.0 mm | 2.19452 | Dimensionado | 1116 | 0 | Viga C-30 - Seção Retangular 20 X 30
V143 | VIGA BALDRAME | 20 | 30 | 0 | 0.41 % | Concreto - C-30 - Abatimento 12 cm | 0.257261 | Forma - Estrutura - Concreto | 3.37566 | Armadura - Aço CA50 - ø 12.5 mm | 22.2174 | Armadura - Aço CA60 - ø 5.0 mm | 4.68758 | Dimensionado | 1116 | 0 | Viga C-30 - Seção Retangular 20 X 30
V144 | VIGA BALDRAME | 20 | 30 | 0 | 0.17 % | Concreto - C-30 - Abatimento 12 cm | 0.028452 | Forma - Estrutura - Concreto | 0.379356 | Armadura - Aço CA50 - ø 8.0 mm | 0.458593 | Armadura - Aço CA50 - ø 10.0 mm | 0.899345 | Dimensionado | 1116 | 0 | Viga C-30 - Seção Retangular 20 X 30 | AltoQi_Eberick-Item_05 - Descrição_05: Armadura - Aço CA60 - ø 5.0 mm; Quantidade_05: 1.06934 kg; Status_05: Dimensionado
V144 | VIGA BALDRAME | 20 | 30 | 0 | 0.17 % | Concreto - C-30 - Abatimento 12 cm | 0.01953 | Forma - Estrutura - Concreto | 0.260402 | Armadura - Aço CA50 - ø 8.0 mm | 0.314792 | Armadura - Aço CA50 - ø 10.0 mm | 0.617338 | Dimensionado | 1116 | 0 | Viga C-30 - Seção Retangular 20 X 30 | AltoQi_Eberick-Item_05 - Descrição_05: Armadura - Aço CA60 - ø 5.0 mm; Quantidade_05: 0.73403 kg; Status_05: Dimensionado
V145 | VIGA BALDRAME | 20 | 30 | 0 | 0.17 % | Concreto - C-30 - Abatimento 12 cm | 0.15134 | Forma - Estrutura - Concreto | 2.01787 | Armadura - Aço CA50 - ø 8.0 mm | 4.70344 | Armadura - Aço CA60 - ø 5.0 mm | 2.34284 | Dimensionado | 1116 | 0 | Viga C-30 - Seção Retangular 20 X 30
V146 | VIGA BALDRAME | 20 | 30 | 0 | 0.17 % | Concreto - C-30 - Abatimento 12 cm | 0.153006 | Forma - Estrutura - Concreto | 2.04008 | Armadura - Aço CA50 - ø 8.0 mm | 4.81393 | Armadura - Aço CA60 - ø 5.0 mm | 2.34284 | Dimensionado | 1116 | 0 | Viga C-30 - Seção Retangular 20 X 30
V147 | VIGA BALDRAME | 20 | 30 | 0 | 0.17 % | Concreto - C-30 - Abatimento 12 cm | 0.122712 | Forma - Estrutura - Concreto | 1.63616 | Armadura - Aço CA50 - ø 8.0 mm | 4.07211 | Armadura - Aço CA60 - ø 5.0 mm | 1.90356 | Dimensionado | 1116 | 0 | Viga C-30 - Seção Retangular 20 X 30
V148 | VIGA BALDRAME | 20 | 30 | 0 | 0.17 % | Concreto - C-30 - Abatimento 12 cm | 0.113975 | Forma - Estrutura - Concreto | 1.51967 | Armadura - Aço CA50 - ø 8.0 mm | 1.60416 | Armadura - Aço CA50 - ø 10.0 mm | 2.79809 | Dimensionado | 1116 | 0 | Viga C-30 - Seção Retangular 20 X 30 | AltoQi_Eberick-Item_05 - Descrição_05: Armadura - Aço CA60 - ø 5.0 mm; Quantidade_05: 1.62085 kg; Status_05: Dimensionado
V148 | VIGA BALDRAME | 20 | 30 | 0 | 0.17 % | Concreto - C-30 - Abatimento 12 cm | 0.112549 | Forma - Estrutura - Concreto | 1.50065 | Armadura - Aço CA50 - ø 8.0 mm | 1.58408 | Armadura - Aço CA50 - ø 10.0 mm | 2.76308 | Dimensionado | 1116 | 0 | Viga C-30 - Seção Retangular 20 X 30 | AltoQi_Eberick-Item_05 - Descrição_05: Armadura - Aço CA60 - ø 5.0 mm; Quantidade_05: 1.60056 kg; Status_05: Dimensionado
V149 | VIGA BALDRAME | 20 | 30 | 0 | 0.17 % | Concreto - C-30 - Abatimento 12 cm | 0.019546 | Forma - Estrutura - Concreto | 0.260611 | Armadura - Aço CA50 - ø 8.0 mm | 0.26675 | Armadura - Aço CA50 - ø 10.0 mm | 0.477642 | Dimensionado | 1116 | 0 | Viga C-30 - Seção Retangular 20 X 30 | AltoQi_Eberick-Item_05 - Descrição_05: Armadura - Aço CA60 - ø 5.0 mm; Quantidade_05: 0.413564 kg; Status_05: Dimensionado
V149 | VIGA BALDRAME | 20 | 30 | 0 | 0.17 % | Concreto - C-30 - Abatimento 12 cm | 0.138896 | Forma - Estrutura - Concreto | 1.85195 | Armadura - Aço CA50 - ø 8.0 mm | 1.89557 | Armadura - Aço CA50 - ø 10.0 mm | 3.39421 | Dimensionado | 1116 | 0 | Viga C-30 - Seção Retangular 20 X 30 | AltoQi_Eberick-Item_05 - Descrição_05: Armadura - Aço CA60 - ø 5.0 mm; Quantidade_05: 2.93886 kg; Status_05: Dimensionado
V150 | VIGA BALDRAME | 20 | 30 | 0 | 0.17 % | Concreto - C-30 - Abatimento 12 cm | 0.131472 | Forma - Estrutura - Concreto | 1.75296 | Armadura - Aço CA50 - ø 8.0 mm | 4.46669 | Armadura - Aço CA60 - ø 5.0 mm | 2.48927 | Dimensionado | 1116 | 0 | Viga C-30 - Seção Retangular 20 X 30
V151 | VIGA BALDRAME | 20 | 30 | 0 | 0.17 % | Concreto - C-30 - Abatimento 12 cm | 0.167112 | Forma - Estrutura - Concreto | 2.22816 | Armadura - Aço CA50 - ø 8.0 mm | 2.24913 | Armadura - Aço CA50 - ø 10.0 mm | 3.89652 | Dimensionado | 1116 | 0 | Viga C-30 - Seção Retangular 20 X 30 | AltoQi_Eberick-Item_05 - Descrição_05: Armadura - Aço CA60 - ø 5.0 mm; Quantidade_05: 2.34284 kg; Status_05: Dimensionado
V152 | VIGA BALDRAME | 20 | 30 | 0 | 0.17 % | Concreto - C-30 - Abatimento 12 cm | 0.1569 | Forma - Estrutura - Concreto | 2.092 | Armadura - Aço CA50 - ø 8.0 mm | 2.03605 | Armadura - Aço CA50 - ø 12.5 mm | 5.62591 | Dimensionado | 1116 | 0 | Viga C-30 - Seção Retangular 20 X 30 | AltoQi_Eberick-Item_05 - Descrição_05: Armadura - Aço CA60 - ø 5.0 mm; Quantidade_05: 2.34284 kg; Status_05: Dimensionado
V153 | VIGA BALDRAME | 15 | 30 | -20 | 0.35 % | Concreto - C-30 - Abatimento 12 cm | 0.079638 | Forma - Estrutura - Concreto | 1.3273 | Armadura - Aço CA50 - ø 10.0 mm | 4.82385 | Armadura - Aço CA60 - ø 5.0 mm | 1.08929 | Dimensionado | 567 | 0 | Viga C-30 - Seção Retangular 15 X 30
V153 | VIGA BALDRAME | 15 | 30 | -20 | 0.35 % | Concreto - C-30 - Abatimento 12 cm | 0.189687 | Forma - Estrutura - Concreto | 3.16145 | Armadura - Aço CA50 - ø 10.0 mm | 11.4897 | Armadura - Aço CA60 - ø 5.0 mm | 2.59453 | Dimensionado | 567 | 0 | Viga C-30 - Seção Retangular 15 X 30
V154 | VIGA BALDRAME | 20 | 30 | 0 | 0.26 % | Concreto - C-30 - Abatimento 12 cm | 0.199088 | Forma - Estrutura - Concreto | 2.69659 | Armadura - Aço CA50 - ø 8.0 mm | 3.25494 | Armadura - Aço CA50 - ø 10.0 mm | 4.26848 | Dimensionado | 1116 | 0 | Viga C-30 - Seção Retangular 20 X 30 | AltoQi_Eberick-Item_05 - Descrição_05: Armadura - Aço CA60 - ø 5.0 mm; Quantidade_05: 3.08135 kg; Status_05: Dimensionado
V154 | VIGA BALDRAME | 20 | 30 | 0 | 0.26 % | Concreto - C-30 - Abatimento 12 cm | 0.179344 | Forma - Estrutura - Concreto | 2.42916 | Armadura - Aço CA50 - ø 8.0 mm | 2.93214 | Armadura - Aço CA50 - ø 10.0 mm | 3.84516 | Dimensionado | 1116 | 0 | Viga C-30 - Seção Retangular 20 X 30 | AltoQi_Eberick-Item_05 - Descrição_05: Armadura - Aço CA60 - ø 5.0 mm; Quantidade_05: 2.77576 kg; Status_05: Dimensionado
V155 | VIGA BALDRAME | 20 | 30 | 0 | 0.41 % | Concreto - C-30 - Abatimento 12 cm | 0.139938 | Forma - Estrutura - Concreto | 1.86584 | Armadura - Aço CA50 - ø 12.5 mm | 10.2679 | Armadura - Aço CA60 - ø 5.0 mm | 2.76205 | Dimensionado | 1116 | 0 | Viga C-30 - Seção Retangular 20 X 30
V155 | VIGA BALDRAME | 20 | 30 | 0 | 0.41 % | Concreto - C-30 - Abatimento 12 cm | 0.016497 | Forma - Estrutura - Concreto | 0.219964 | Armadura - Aço CA50 - ø 12.5 mm | 1.21048 | Armadura - Aço CA60 - ø 5.0 mm | 0.325619 | Dimensionado | 1116 | 0 | Viga C-30 - Seção Retangular 20 X 30
V155 | VIGA BALDRAME | 20 | 30 | 0 | 0.41 % | Concreto - C-30 - Abatimento 12 cm | 0.227853 | Forma - Estrutura - Concreto | 3.03804 | Armadura - Aço CA50 - ø 12.5 mm | 16.7186 | Armadura - Aço CA60 - ø 5.0 mm | 4.49729 | Dimensionado | 1116 | 0 | Viga C-30 - Seção Retangular 20 X 30
V156 | VIGA BALDRAME | 30 | 30 | 0 | 0.17 % | Concreto - C-30 - Abatimento 12 cm | 0.089747 | Forma - Estrutura - Concreto | 0.897471 | Armadura - Aço CA50 - ø 10.0 mm | 4.14313 | Armadura - Aço CA60 - ø 5.0 mm | 1.41804 | Dimensionado | 1116 | 0 | Viga C-30 - Seção Retangular 30 X 30
V157 | VIGA BALDRAME | 15 | 30 | 0 | 0.22 % | Concreto - C-30 - Abatimento 12 cm | 0.108914 | Forma - Estrutura - Concreto | 1.81523 | Armadura - Aço CA50 - ø 8.0 mm | 4.57718 | Armadura - Aço CA60 - ø 5.0 mm | 1.44116 | Dimensionado | 0 | 0 | Viga C-30 - Seção Retangular 15 X 30
V158 | VIGA BALDRAME | 15 | 30 | 0 | 0.22 % | Concreto - C-30 - Abatimento 12 cm | 0.128879 | Forma - Estrutura - Concreto | 2.16157 | Armadura - Aço CA50 - ø 8.0 mm | 4.5249 | Armadura - Aço CA50 - ø 10.0 mm | 0.307282 | Dimensionado | 567 | 0 | Viga C-30 - Seção Retangular 15 X 30 | AltoQi_Eberick-Item_05 - Descrição_05: Armadura - Aço CA60 - ø 5.0 mm; Quantidade_05: 1.74632 kg; Status_05: Dimensionado
7 x V158 | VIGA BALDRAME | 15 | 30 | 0 | 0.22 % | Concreto - C-30 - Abatimento 12 cm | 0.137382 | Forma - Estrutura - Concreto | 2.30417 | Armadura - Aço CA50 - ø 8.0 mm | 4.82342 | Armadura - Aço CA50 - ø 10.0 mm | 0.327554 | Dimensionado | 567 | 0 | Viga C-30 - Seção Retangular 15 X 30 | AltoQi_Eberick-Item_05 - Descrição_05: Armadura - Aço CA60 - ø 5.0 mm; Quantidade_05: 1.86153 kg; Status_05: Dimensionado
V158 | VIGA BALDRAME | 15 | 30 | 0 | 0.22 % | Concreto - C-30 - Abatimento 12 cm | 0.137382 | Forma - Estrutura - Concreto | 2.30419 | Armadura - Aço CA50 - ø 8.0 mm | 4.82345 | Armadura - Aço CA50 - ø 10.0 mm | 0.327556 | Dimensionado | 567 | 0 | Viga C-30 - Seção Retangular 15 X 30 | AltoQi_Eberick-Item_05 - Descrição_05: Armadura - Aço CA60 - ø 5.0 mm; Quantidade_05: 1.86154 kg; Status_05: Dimensionado
V158 | VIGA BALDRAME | 15 | 30 | 0 | 0.22 % | Concreto - C-30 - Abatimento 12 cm | 0.137383 | Forma - Estrutura - Concreto | 2.3042 | Armadura - Aço CA50 - ø 8.0 mm | 4.82347 | Armadura - Aço CA50 - ø 10.0 mm | 0.327557 | Dimensionado | 567 | 0 | Viga C-30 - Seção Retangular 15 X 30 | AltoQi_Eberick-Item_05 - Descrição_05: Armadura - Aço CA60 - ø 5.0 mm; Quantidade_05: 1.86155 kg; Status_05: Dimensionado
V158 | VIGA BALDRAME | 15 | 30 | 0 | 0.35 % | Concreto - C-30 - Abatimento 12 cm | 0.137382 | Forma - Estrutura - Concreto | 2.30418 | Armadura - Aço CA50 - ø 8.0 mm | 4.82344 | Armadura - Aço CA50 - ø 10.0 mm | 0.327555 | Dimensionado | 567 | 0 | Viga C-30 - Seção Retangular 15 X 30 | AltoQi_Eberick-Item_05 - Descrição_05: Armadura - Aço CA60 - ø 5.0 mm; Quantidade_05: 1.86154 kg; Status_05: Dimensionado
V158 | VIGA BALDRAME | 15 | 30 | 0 | 0.22 % | Concreto - C-30 - Abatimento 12 cm | 0.137382 | Forma - Estrutura - Concreto | 2.30418 | Armadura - Aço CA50 - ø 8.0 mm | 4.82344 | Armadura - Aço CA50 - ø 10.0 mm | 0.327555 | Dimensionado | 567 | 0 | Viga C-30 - Seção Retangular 15 X 30 | AltoQi_Eberick-Item_05 - Descrição_05: Armadura - Aço CA60 - ø 5.0 mm; Quantidade_05: 1.86154 kg; Status_05: Dimensionado
V158 | VIGA BALDRAME | 15 | 30 | 0 | 0.22 % | Concreto - C-30 - Abatimento 12 cm | 0.138994 | Forma - Estrutura - Concreto | 2.33121 | Armadura - Aço CA50 - ø 8.0 mm | 4.88003 | Armadura - Aço CA50 - ø 10.0 mm | 0.331398 | Dimensionado | 567 | 0 | Viga C-30 - Seção Retangular 15 X 30 | AltoQi_Eberick-Item_05 - Descrição_05: Armadura - Aço CA60 - ø 5.0 mm; Quantidade_05: 1.88338 kg; Status_05: Dimensionado
13 x V159 | VIGA BALDRAME | 15 | 30 | 0 | 0.22 % | Concreto - C-30 - Abatimento 12 cm | 0.134571 | Forma - Estrutura - Concreto | 2.24286 | Armadura - Aço CA50 - ø 8.0 mm | 4.91552 | Armadura - Aço CA60 - ø 5.0 mm | 2.13204 | Dimensionado | 567 | 0 | Viga C-30 - Seção Retangular 15 X 30
V159 | VIGA BALDRAME | 15 | 30 | 0 | 0.22 % | Concreto - C-30 - Abatimento 12 cm | 0.131929 | Forma - Estrutura - Concreto | 2.19881 | Armadura - Aço CA50 - ø 8.0 mm | 4.81899 | Armadura - Aço CA60 - ø 5.0 mm | 2.09017 | Dimensionado | 567 | 0 | Viga C-30 - Seção Retangular 15 X 30
V159 | VIGA BALDRAME | 15 | 30 | 0 | 0.22 % | Concreto - C-30 - Abatimento 12 cm | 0.128117 | Forma - Estrutura - Concreto | 2.13529 | Armadura - Aço CA50 - ø 8.0 mm | 4.67977 | Armadura - Aço CA60 - ø 5.0 mm | 2.02979 | Dimensionado | 567 | 0 | Viga C-30 - Seção Retangular 15 X 30
V160 | VIGA BALDRAME | 20 | 30 | 0 | 0.61 % | Concreto - C-30 - Abatimento 12 cm | 0.3 | Forma - Estrutura - Concreto | 4 | Armadura - Aço CA50 - ø 12.5 mm | 25.0565 | Armadura - Aço CA60 - ø 5.0 mm | 4.68569 | Dimensionado | 1116 | 0 | Viga C-30 - Seção Retangular 20 X 30
V161 | VIGA BALDRAME | 20 | 30 | 0 | 0.17 % | Concreto - C-30 - Abatimento 12 cm | 0.1494 | Forma - Estrutura - Concreto | 1.992 | Armadura - Aço CA50 - ø 8.0 mm | 4.84549 | Armadura - Aço CA60 - ø 5.0 mm | 2.19642 | Dimensionado | 1116 | 0 | Viga C-30 - Seção Retangular 20 X 30
V162 | VIGA BALDRAME | 20 | 30 | 0 | 0.61 % | Concreto - C-30 - Abatimento 12 cm | 0.2988 | Forma - Estrutura - Concreto | 3.984 | Armadura - Aço CA50 - ø 12.5 mm | 24.9794 | Armadura - Aço CA60 - ø 5.0 mm | 4.68569 | Dimensionado | 1116 | 0 | Viga C-30 - Seção Retangular 20 X 30
V163 | VIGA BALDRAME | 20 | 30 | 0 | 0.61 % | Concreto - C-30 - Abatimento 12 cm | 0.299994 | Forma - Estrutura - Concreto | 4 | Armadura - Aço CA50 - ø 12.5 mm | 25.2106 | Armadura - Aço CA60 - ø 5.0 mm | 4.68569 | Dimensionado | 1116 | 0 | Viga C-30 - Seção Retangular 20 X 30
V164 | VIGA BALDRAME | 20 | 30 | 0 | 0.26 % | Concreto - C-30 - Abatimento 12 cm | 0.149388 | Forma - Estrutura - Concreto | 1.99184 | Armadura - Aço CA50 - ø 8.0 mm | 2.61215 | Armadura - Aço CA50 - ø 10.0 mm | 3.51426 | Dimensionado | 1116 | 0 | Viga C-30 - Seção Retangular 20 X 30 | AltoQi_Eberick-Item_05 - Descrição_05: Armadura - Aço CA60 - ø 5.0 mm; Quantidade_05: 3.07498 kg; Status_05: Dimensionado
V165 | VIGA BALDRAME | 20 | 30 | 0 | 0.61 % | Concreto - C-30 - Abatimento 12 cm | 0.2997 | Forma - Estrutura - Concreto | 3.996 | Armadura - Aço CA50 - ø 12.5 mm | 26.54 | Armadura - Aço CA60 - ø 5.0 mm | 4.68569 | Dimensionado | 1116 | 0 | Viga C-30 - Seção Retangular 20 X 30
V166 | VIGA BALDRAME | 20 | 30 | 0 | 0.41 % | Concreto - C-30 - Abatimento 12 cm | 0.022922 | Forma - Estrutura - Concreto | 0.305621 | Armadura - Aço CA50 - ø 12.5 mm | 1.64943 | Armadura - Aço CA60 - ø 5.0 mm | 0.358162 | Dimensionado | 1116 | 0 | Viga C-30 - Seção Retangular 20 X 30
V166 | VIGA BALDRAME | 20 | 30 | 0 | 0.41 % | Concreto - C-30 - Abatimento 12 cm | 0.052826 | Forma - Estrutura - Concreto | 0.704345 | Armadura - Aço CA50 - ø 12.5 mm | 3.80133 | Armadura - Aço CA60 - ø 5.0 mm | 0.825432 | Dimensionado | 1116 | 0 | Viga C-30 - Seção Retangular 20 X 30
V166 | VIGA BALDRAME | 20 | 30 | 0 | 0.41 % | Concreto - C-30 - Abatimento 12 cm | 0.280353 | Forma - Estrutura - Concreto | 3.73803 | Armadura - Aço CA50 - ø 12.5 mm | 20.1741 | Armadura - Aço CA60 - ø 5.0 mm | 4.38066 | Dimensionado | 1116 | 0 | Viga C-30 - Seção Retangular 20 X 30
V167 | VIGA BALDRAME | 15 | 30 | 0 | 0.22 % | Concreto - C-30 - Abatimento 12 cm | 0.042525 | Forma - Estrutura - Concreto | 0.70875 | Armadura - Aço CA50 - ø 8.0 mm | 2.13075 | Armadura - Aço CA60 - ø 5.0 mm | 0.655071 | Dimensionado | 1116 | 0 | Viga C-30 - Seção Retangular 15 X 30
V168 | VIGA BALDRAME | 20 | 30 | 0 | 0.26 % | Concreto - C-30 - Abatimento 12 cm | 0.1614 | Forma - Estrutura - Concreto | 2.152 | Armadura - Aço CA50 - ø 10.0 mm | 3.51426 | Armadura - Aço CA60 - ø 5.0 mm | 3.07498 | Dimensionado | 1116 | 0 | Viga C-30 - Seção Retangular 20 X 30
V169 | VIGA BALDRAME | 15 | 30 | 0 | 0.22 % | Concreto - C-30 - Abatimento 12 cm | 0.02655 | Forma - Estrutura - Concreto | 0.4425 | Armadura - Aço CA50 - ø 8.0 mm | 1.46785 | Armadura - Aço CA60 - ø 5.0 mm | 0.393043 | Dimensionado | 1116 | 0 | Viga C-30 - Seção Retangular 15 X 30
V170 | VIGA BALDRAME | 15 | 30 | 0 | 0.22 % | Concreto - C-30 - Abatimento 12 cm | 0.025875 | Forma - Estrutura - Concreto | 0.43125 | Armadura - Aço CA50 - ø 8.0 mm | 1.45207 | Armadura - Aço CA60 - ø 5.0 mm | 0.393043 | Dimensionado | 1116 | 0 | Viga C-30 - Seção Retangular 15 X 30
V171 | VIGA BALDRAME | 20 | 30 | 0 | 0.41 % | Concreto - C-30 - Abatimento 12 cm | 0.286744 | Forma - Estrutura - Concreto | 3.82325 | Armadura - Aço CA50 - ø 12.5 mm | 19.6152 | Armadura - Aço CA60 - ø 5.0 mm | 4.28056 | Dimensionado | 1116 | 0 | Viga C-30 - Seção Retangular 20 X 30
V171 | VIGA BALDRAME | 20 | 30 | 0 | 0.41 % | Concreto - C-30 - Abatimento 12 cm | 0.022863 | Forma - Estrutura - Concreto | 0.304837 | Armadura - Aço CA50 - ø 12.5 mm | 1.56397 | Armadura - Aço CA60 - ø 5.0 mm | 0.3413 | Dimensionado | 1116 | 0 | Viga C-30 - Seção Retangular 20 X 30
V171 | VIGA BALDRAME | 20 | 30 | 0 | 0.41 % | Concreto - C-30 - Abatimento 12 cm | 0.111019 | Forma - Estrutura - Concreto | 1.48025 | Armadura - Aço CA50 - ø 12.5 mm | 7.59444 | Armadura - Aço CA60 - ø 5.0 mm | 1.65731 | Dimensionado | 1116 | 0 | Viga C-30 - Seção Retangular 20 X 30
V171 | VIGA BALDRAME | 20 | 30 | 0 | 0.41 % | Concreto - C-30 - Abatimento 12 cm | 0.28675 | Forma - Estrutura - Concreto | 3.82333 | Armadura - Aço CA50 - ø 12.5 mm | 19.6156 | Armadura - Aço CA60 - ø 5.0 mm | 4.28065 | Dimensionado | 1116 | 0 | Viga C-30 - Seção Retangular 20 X 30
V171 | VIGA BALDRAME | 20 | 30 | 0 | 0.41 % | Concreto - C-30 - Abatimento 12 cm | 0.110134 | Forma - Estrutura - Concreto | 1.46846 | Armadura - Aço CA50 - ø 12.5 mm | 7.53392 | Armadura - Aço CA60 - ø 5.0 mm | 1.64411 | Dimensionado | 1116 | 0 | Viga C-30 - Seção Retangular 20 X 30
V171 | VIGA BALDRAME | 20 | 30 | 0 | 0.41 % | Concreto - C-30 - Abatimento 12 cm | 0.287634 | Forma - Estrutura - Concreto | 3.83512 | Armadura - Aço CA50 - ø 12.5 mm | 19.6761 | Armadura - Aço CA60 - ø 5.0 mm | 4.29386 | Dimensionado | 1116 | 0 | Viga C-30 - Seção Retangular 20 X 30
V171 | VIGA BALDRAME | 20 | 30 | 0 | 0.41 % | Concreto - C-30 - Abatimento 12 cm | 0.022869 | Forma - Estrutura - Concreto | 0.304916 | Armadura - Aço CA50 - ø 12.5 mm | 1.56437 | Armadura - Aço CA60 - ø 5.0 mm | 0.341389 | Dimensionado | 1116 | 0 | Viga C-30 - Seção Retangular 20 X 30
V172 | VIGA BALDRAME | 20 | 30 | 0 | 0.26 % | Concreto - C-30 - Abatimento 12 cm | 0.161388 | Forma - Estrutura - Concreto | 2.15184 | Armadura - Aço CA50 - ø 10.0 mm | 3.51426 | Armadura - Aço CA60 - ø 5.0 mm | 3.07498 | Dimensionado | 1116 | 0 | Viga C-30 - Seção Retangular 20 X 30
V173 | VIGA BALDRAME | 20 | 30 | 0 | 0.41 % | Concreto - C-30 - Abatimento 12 cm | 0.023113 | Forma - Estrutura - Concreto | 0.308177 | Armadura - Aço CA50 - ø 12.5 mm | 1.64547 | Armadura - Aço CA60 - ø 5.0 mm | 0.357841 | Dimensionado | 1116 | 0 | Viga C-30 - Seção Retangular 20 X 30
V173 | VIGA BALDRAME | 20 | 30 | 0 | 0.41 % | Concreto - C-30 - Abatimento 12 cm | 0.281535 | Forma - Estrutura - Concreto | 3.7538 | Armadura - Aço CA50 - ø 12.5 mm | 20.043 | Armadura - Aço CA60 - ø 5.0 mm | 4.35874 | Dimensionado | 1116 | 0 | Viga C-30 - Seção Retangular 20 X 30
V173 | VIGA BALDRAME | 20 | 30 | 0 | 0.41 % | Concreto - C-30 - Abatimento 12 cm | 0.054752 | Forma - Estrutura - Concreto | 0.730026 | Armadura - Aço CA50 - ø 12.5 mm | 3.89788 | Armadura - Aço CA60 - ø 5.0 mm | 0.847672 | Dimensionado | 1116 | 0 | Viga C-30 - Seção Retangular 20 X 30
V174 | VIGA BALDRAME | 15 | 30 | 0 | 0.22 % | Concreto - C-30 - Abatimento 12 cm | 0.039933 | Forma - Estrutura - Concreto | 0.66555 | Armadura - Aço CA50 - ø 8.0 mm | 2.06762 | Armadura - Aço CA60 - ø 5.0 mm | 0.524057 | Dimensionado | 1116 | 0 | Viga C-30 - Seção Retangular 15 X 30
V175 | VIGA BALDRAME | 20 | 30 | 0 | 0.26 % | Concreto - C-30 - Abatimento 12 cm | 0.156594 | Forma - Estrutura - Concreto | 2.08792 | Armadura - Aço CA50 - ø 8.0 mm | 2.59636 | Armadura - Aço CA50 - ø 10.0 mm | 3.51426 | Dimensionado | 1116 | 0 | Viga C-30 - Seção Retangular 20 X 30 | AltoQi_Eberick-Item_05 - Descrição_05: Armadura - Aço CA60 - ø 5.0 mm; Quantidade_05: 2.48927 kg; Status_05: Dimensionado
V176 | VIGA BALDRAME | 20 | 30 | 0 | 0.26 % | Concreto - C-30 - Abatimento 12 cm | 0.1566 | Forma - Estrutura - Concreto | 2.088 | Armadura - Aço CA50 - ø 8.0 mm | 2.59636 | Armadura - Aço CA50 - ø 10.0 mm | 3.51426 | Dimensionado | 1116 | 0 | Viga C-30 - Seção Retangular 20 X 30 | AltoQi_Eberick-Item_05 - Descrição_05: Armadura - Aço CA60 - ø 5.0 mm; Quantidade_05: 2.48927 kg; Status_05: Dimensionado
V177 | VIGA BALDRAME | 20 | 30 | 0 | 0.17 % | Concreto - C-30 - Abatimento 12 cm | 0.0276 | Forma - Estrutura - Concreto | 0.368 | Armadura - Aço CA50 - ø 8.0 mm | 1.34159 | Armadura - Aço CA60 - ø 5.0 mm | 0.439283 | Dimensionado | 1116 | 0 | Viga C-30 - Seção Retangular 20 X 30
V178 | VIGA BALDRAME | 20 | 30 | 0 | 0.26 % | Concreto - C-30 - Abatimento 12 cm | 0.1494 | Forma - Estrutura - Concreto | 1.992 | Armadura - Aço CA50 - ø 10.0 mm | 3.51426 | Armadura - Aço CA60 - ø 5.0 mm | 3.07498 | Dimensionado | 1116 | 0 | Viga C-30 - Seção Retangular 20 X 30
V179 | VIGA BALDRAME | 20 | 30 | 0 | 0.26 % | Concreto - C-30 - Abatimento 12 cm | 0.149388 | Forma - Estrutura - Concreto | 1.99184 | Armadura - Aço CA50 - ø 10.0 mm | 3.51426 | Armadura - Aço CA60 - ø 5.0 mm | 3.07498 | Dimensionado | 1116 | 0 | Viga C-30 - Seção Retangular 20 X 30
V180 | VIGA BALDRAME | 20 | 30 | 0 | 0.17 % | Concreto - C-30 - Abatimento 12 cm | 0.069 | Forma - Estrutura - Concreto | 0.92 | Armadura - Aço CA50 - ø 8.0 mm | 2.57269 | Armadura - Aço CA60 - ø 5.0 mm | 1.02499 | Dimensionado | 1116 | 0 | Viga C-30 - Seção Retangular 20 X 30
V181 | VIGA BALDRAME | 20 | 30 | 0 | 0.17 % | Concreto - C-30 - Abatimento 12 cm | 0.063294 | Forma - Estrutura - Concreto | 0.84392 | Armadura - Aço CA50 - ø 8.0 mm | 2.47799 | Armadura - Aço CA60 - ø 5.0 mm | 1.02499 | Dimensionado | 1116 | 0 | Viga C-30 - Seção Retangular 20 X 30
V182 | VIGA BALDRAME | 20 | 30 | 0 | 0.26 % | Concreto - C-30 - Abatimento 12 cm | 0.059786 | Forma - Estrutura - Concreto | 0.797141 | Armadura - Aço CA50 - ø 8.0 mm | 0.847123 | Armadura - Aço CA50 - ø 10.0 mm | 1.27581 | Dimensionado | 1116 | 0 | Viga C-30 - Seção Retangular 20 X 30 | AltoQi_Eberick-Item_05 - Descrição_05: Armadura - Aço CA60 - ø 5.0 mm; Quantidade_05: 0.901995 kg; Status_05: Dimensionado
V182 | VIGA BALDRAME | 20 | 30 | 0 | 0.26 % | Concreto - C-30 - Abatimento 12 cm | 0.187793 | Forma - Estrutura - Concreto | 2.50391 | Armadura - Aço CA50 - ø 8.0 mm | 2.6609 | Armadura - Aço CA50 - ø 10.0 mm | 4.00744 | Dimensionado | 1116 | 0 | Viga C-30 - Seção Retangular 20 X 30 | AltoQi_Eberick-Item_05 - Descrição_05: Armadura - Aço CA60 - ø 5.0 mm; Quantidade_05: 2.83326 kg; Status_05: Dimensionado
V182 | VIGA BALDRAME | 20 | 30 | 0 | 0.26 % | Concreto - C-30 - Abatimento 12 cm | 0.114933 | Forma - Estrutura - Concreto | 1.53244 | Armadura - Aço CA50 - ø 8.0 mm | 1.62853 | Armadura - Aço CA50 - ø 10.0 mm | 2.45263 | Dimensionado | 1116 | 0 | Viga C-30 - Seção Retangular 20 X 30 | AltoQi_Eberick-Item_05 - Descrição_05: Armadura - Aço CA60 - ø 5.0 mm; Quantidade_05: 1.73401 kg; Status_05: Dimensionado
V182 | VIGA BALDRAME | 20 | 30 | 0 | 0.26 % | Concreto - C-30 - Abatimento 12 cm | 0.161583 | Forma - Estrutura - Concreto | 2.15443 | Armadura - Aço CA50 - ø 8.0 mm | 2.28952 | Armadura - Aço CA50 - ø 10.0 mm | 3.44812 | Dimensionado | 1116 | 0 | Viga C-30 - Seção Retangular 20 X 30 | AltoQi_Eberick-Item_05 - Descrição_05: Armadura - Aço CA60 - ø 5.0 mm; Quantidade_05: 2.43782 kg; Status_05: Dimensionado
V183 | VIGA BALDRAME | 20 | 30 | 0 | 0.41 % | Concreto - C-30 - Abatimento 12 cm | 0.193767 | Forma - Estrutura - Concreto | 2.58356 | Armadura - Aço CA50 - ø 12.5 mm | 14.5285 | Armadura - Aço CA60 - ø 5.0 mm | 3.66125 | Dimensionado | 1116 | 0 | Viga C-30 - Seção Retangular 20 X 30
V183 | VIGA BALDRAME | 20 | 30 | 0 | 0.41 % | Concreto - C-30 - Abatimento 12 cm | 0.29109 | Forma - Estrutura - Concreto | 3.8812 | Armadura - Aço CA50 - ø 12.5 mm | 21.8257 | Armadura - Aço CA60 - ø 5.0 mm | 5.50016 | Dimensionado | 1116 | 0 | Viga C-30 - Seção Retangular 20 X 30
V183 | VIGA BALDRAME | 20 | 30 | 0 | 0.41 % | Concreto - C-30 - Abatimento 12 cm | 0.194361 | Forma - Estrutura - Concreto | 2.59148 | Armadura - Aço CA50 - ø 12.5 mm | 14.573 | Armadura - Aço CA60 - ø 5.0 mm | 3.67246 | Dimensionado | 1116 | 0 | Viga C-30 - Seção Retangular 20 X 30
V183 | VIGA BALDRAME | 20 | 30 | 0 | 0.61 % | Concreto - C-30 - Abatimento 12 cm | 0.295182 | Forma - Estrutura - Concreto | 3.93576 | Armadura - Aço CA50 - ø 12.5 mm | 22.1325 | Armadura - Aço CA60 - ø 5.0 mm | 5.57748 | Dimensionado | 1116 | 0 | Viga C-30 - Seção Retangular 20 X 30
V184 | VIGA BALDRAME | 15 | 30 | 0 | 0.22 % | Concreto - C-30 - Abatimento 12 cm | 0.0279 | Forma - Estrutura - Concreto | 0.465 | Armadura - Aço CA50 - ø 8.0 mm | 1.76774 | Armadura - Aço CA60 - ø 5.0 mm | 0.393043 | Dimensionado | 1116 | 0 | Viga C-30 - Seção Retangular 15 X 30
V185 | VIGA BALDRAME | 20 | 30 | 0 | 0.41 % | Concreto - C-30 - Abatimento 12 cm | 0.18674 | Forma - Estrutura - Concreto | 2.48987 | Armadura - Aço CA50 - ø 10.0 mm | 4.14734 | Armadura - Aço CA50 - ø 12.5 mm | 6.28678 | Dimensionado | 1116 | 0 | Viga C-30 - Seção Retangular 20 X 30 | AltoQi_Eberick-Item_05 - Descrição_05: Armadura - Aço CA60 - ø 5.0 mm; Quantidade_05: 3.00108 kg; Status_05: Dimensionado
V185 | VIGA BALDRAME | 20 | 30 | 0 | 0.41 % | Concreto - C-30 - Abatimento 12 cm | 0.175213 | Forma - Estrutura - Concreto | 2.33618 | Armadura - Aço CA50 - ø 10.0 mm | 3.89133 | Armadura - Aço CA50 - ø 12.5 mm | 5.89871 | Dimensionado | 1116 | 0 | Viga C-30 - Seção Retangular 20 X 30 | AltoQi_Eberick-Item_05 - Descrição_05: Armadura - Aço CA60 - ø 5.0 mm; Quantidade_05: 2.81582 kg; Status_05: Dimensionado
V185 | VIGA BALDRAME | 20 | 30 | 0 | 0.41 % | Concreto - C-30 - Abatimento 12 cm | 0.158834 | Forma - Estrutura - Concreto | 2.11779 | Armadura - Aço CA50 - ø 10.0 mm | 3.52757 | Armadura - Aço CA50 - ø 12.5 mm | 5.34729 | Dimensionado | 1116 | 0 | Viga C-30 - Seção Retangular 20 X 30 | AltoQi_Eberick-Item_05 - Descrição_05: Armadura - Aço CA60 - ø 5.0 mm; Quantidade_05: 2.5526 kg; Status_05: Dimensionado
V186 | VIGA BALDRAME | 20 | 30 | 0 | 0.26 % | Concreto - C-30 - Abatimento 12 cm | 0.198754 | Forma - Estrutura - Concreto | 2.65005 | Armadura - Aço CA50 - ø 8.0 mm | 2.81915 | Armadura - Aço CA50 - ø 10.0 mm | 4.16767 | Dimensionado | 1116 | 0 | Viga C-30 - Seção Retangular 20 X 30 | AltoQi_Eberick-Item_05 - Descrição_05: Armadura - Aço CA60 - ø 5.0 mm; Quantidade_05: 2.91124 kg; Status_05: Dimensionado
V186 | VIGA BALDRAME | 20 | 30 | 0 | 0.26 % | Concreto - C-30 - Abatimento 12 cm | 0.111146 | Forma - Estrutura - Concreto | 1.48195 | Armadura - Aço CA50 - ø 8.0 mm | 1.57652 | Armadura - Aço CA50 - ø 10.0 mm | 2.33063 | Dimensionado | 1116 | 0 | Viga C-30 - Seção Retangular 20 X 30 | AltoQi_Eberick-Item_05 - Descrição_05: Armadura - Aço CA60 - ø 5.0 mm; Quantidade_05: 1.62802 kg; Status_05: Dimensionado
V187 | VIGA BALDRAME | 20 | 30 | 0 | 0.26 % | Concreto - C-30 - Abatimento 12 cm | 0.149388 | Forma - Estrutura - Concreto | 1.99184 | Armadura - Aço CA50 - ø 8.0 mm | 2.61215 | Armadura - Aço CA50 - ø 10.0 mm | 3.51426 | Dimensionado | 1116 | 0 | Viga C-30 - Seção Retangular 20 X 30 | AltoQi_Eberick-Item_05 - Descrição_05: Armadura - Aço CA60 - ø 5.0 mm; Quantidade_05: 2.19642 kg; Status_05: Dimensionado
V188 | VIGA BALDRAME | 20 | 30 | 0 | 0.26 % | Concreto - C-30 - Abatimento 12 cm | 0.115154 | Forma - Estrutura - Concreto | 1.53538 | Armadura - Aço CA50 - ø 8.0 mm | 1.72843 | Armadura - Aço CA50 - ø 10.0 mm | 2.53958 | Dimensionado | 1116 | 0 | Viga C-30 - Seção Retangular 20 X 30 | AltoQi_Eberick-Item_05 - Descrição_05: Armadura - Aço CA60 - ø 5.0 mm; Quantidade_05: 1.85671 kg; Status_05: Dimensionado
V188 | VIGA BALDRAME | 20 | 30 | 0 | 0.26 % | Concreto - C-30 - Abatimento 12 cm | 0.184534 | Forma - Estrutura - Concreto | 2.46046 | Armadura - Aço CA50 - ø 8.0 mm | 2.76982 | Armadura - Aço CA50 - ø 10.0 mm | 4.0697 | Dimensionado | 1116 | 0 | Viga C-30 - Seção Retangular 20 X 30 | AltoQi_Eberick-Item_05 - Descrição_05: Armadura - Aço CA60 - ø 5.0 mm; Quantidade_05: 2.9754 kg; Status_05: Dimensionado
V189 | VIGA BALDRAME | 15 | 30 | -20 | 0.22 % | Concreto - C-30 - Abatimento 12 cm | 0.13732 | Forma - Estrutura - Concreto | 2.35774 | Armadura - Aço CA50 - ø 8.0 mm | 5.18443 | Armadura - Aço CA60 - ø 5.0 mm | 2.09141 | Dimensionado | 0 | 0 | Viga C-30 - Seção Retangular 15 X 30
V189 | VIGA BALDRAME | 15 | 30 | -20 | 0.22 % | Concreto - C-30 - Abatimento 12 cm | 0.086339 | Forma - Estrutura - Concreto | 1.48241 | Armadura - Aço CA50 - ø 8.0 mm | 3.25967 | Armadura - Aço CA60 - ø 5.0 mm | 1.31496 | Dimensionado | 1116 | 0 | Viga C-30 - Seção Retangular 15 X 30
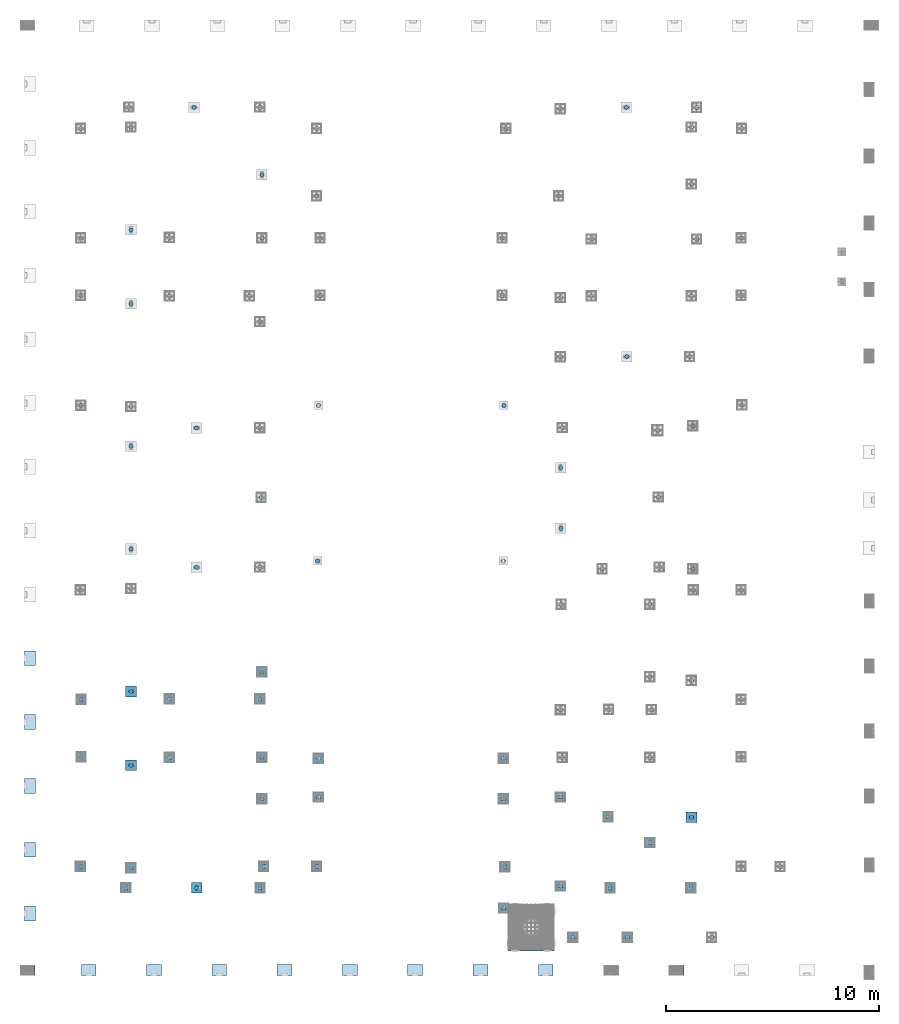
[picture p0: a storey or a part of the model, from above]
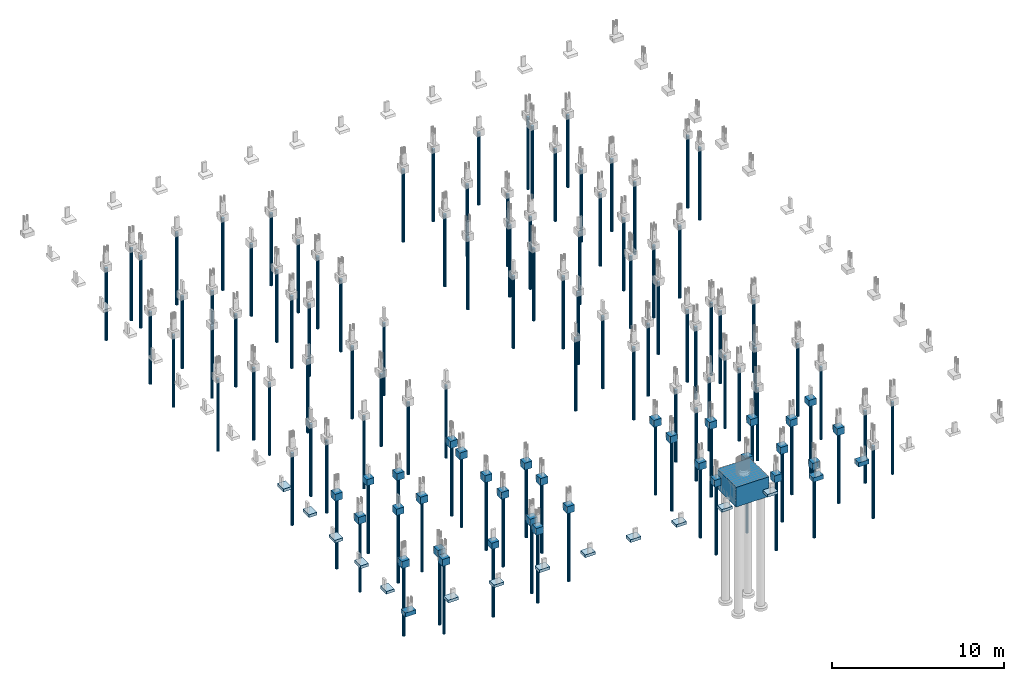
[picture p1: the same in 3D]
Properties of the parts of a building model (IFC4), part 2 of 9

# IfcBeam (614)
Name | In | Seção_bw (cm) | Seção_h (cm) | Elevação (cm) | Taxa de armadura | Descrição_01 | AltoQi_Eberick-Item_01, Quantidade_01 (m3) | Descrição_02 | AltoQi_Eberick-Item_02, Quantidade_02 (m2) | Descrição_03 | Quantidade_03 (kg) | Descrição_04 | AltoQi_Eberick-Item_04, Quantidade_04 (kg) | Status_04 | Cargas de parede (G2) | Adicional (G2) | Reference
V190 | VIGA BALDRAME | 20 | 30 | 0 | 0.26 % | Concreto - C-30 - Abatimento 12 cm | 0.194425 | Forma - Estrutura - Concreto | 2.59234 | Armadura - Aço CA50 - ø 8.0 mm | 2.75476 | Armadura - Aço CA50 - ø 10.0 mm | 4.0729 | Dimensionado | 1116 | 0 | Viga C-30 - Seção Retangular 20 X 30 | AltoQi_Eberick-Item_05 - Descrição_05: Armadura - Aço CA60 - ø 5.0 mm; Quantidade_05: 3.02285 kg; Status_05: Dimensionado
V190 | VIGA BALDRAME | 20 | 30 | 0 | 0.26 % | Concreto - C-30 - Abatimento 12 cm | 0.116369 | Forma - Estrutura - Concreto | 1.55158 | Armadura - Aço CA50 - ø 8.0 mm | 1.6488 | Armadura - Aço CA50 - ø 10.0 mm | 2.43774 | Dimensionado | 1116 | 0 | Viga C-30 - Seção Retangular 20 X 30 | AltoQi_Eberick-Item_05 - Descrição_05: Armadura - Aço CA60 - ø 5.0 mm; Quantidade_05: 1.80926 kg; Status_05: Dimensionado
V191 | VIGA BALDRAME | 20 | 30 | 0 | 0.26 % | Concreto - C-30 - Abatimento 12 cm | 0.15 | Forma - Estrutura - Concreto | 2 | Armadura - Aço CA50 - ø 8.0 mm | 2.62004 | Armadura - Aço CA50 - ø 10.0 mm | 3.52659 | Dimensionado | 1116 | 0 | Viga C-30 - Seção Retangular 20 X 30 | AltoQi_Eberick-Item_05 - Descrição_05: Armadura - Aço CA60 - ø 5.0 mm; Quantidade_05: 2.19642 kg; Status_05: Dimensionado
V192 | VIGA BALDRAME | 15 | 30 | 0 | 0.22 % | Concreto - C-30 - Abatimento 12 cm | 0.088978 | Forma - Estrutura - Concreto | 1.48297 | Armadura - Aço CA50 - ø 8.0 mm | 1.68882 | Armadura - Aço CA60 - ø 5.0 mm | 1.70781 | Dimensionado | 0 | 0 | Viga C-30 - Seção Retangular 15 X 30
V193 | VIGA BALDRAME | 15 | 30 | 0 | 0.89 % | Concreto - C-30 - Abatimento 12 cm | 0.224091 | Forma - Estrutura - Concreto | 3.65991 | Armadura - Aço CA50 - ø 16.0 mm | 36.649 | Armadura - Aço CA60 - ø 5.0 mm | 3.91964 | Dimensionado | 1116 | 0 | Viga C-30 - Seção Retangular 15 X 30
V194 | VIGA BALDRAME | 14 | 40 | 0 | 0.28 % | Concreto - C-30 - Abatimento 12 cm | 0.021745 | Forma - Estrutura - Concreto | 0.365002 | Armadura - Aço CA50 - ø 10.0 mm | 1.86194 | Armadura - Aço CA60 - ø 5.0 mm | 0.86007 | Dimensionado | 1116 | 0 | Viga C-30 - Seção Retangular 14 X 40
V195 | VIGA BALDRAME | 12 | 40 | 0 | 0.21 % | Concreto - C-30 - Abatimento 12 cm | 0.023198 | Forma - Estrutura - Concreto | 0.444636 | Armadura - Aço CA50 - ø 8.0 mm | 0.410367 | Armadura - Aço CA60 - ø 5.0 mm | 0.42387 | Dimensionado | 1116 | 0 | Viga C-30 - Seção Retangular 12 X 40
V196 | VIGA BALDRAME | 20 | 30 | 0 | 0.41 % | Concreto - C-30 - Abatimento 12 cm | 0.110748 | Forma - Estrutura - Concreto | 1.48549 | Armadura - Aço CA50 - ø 12.5 mm | 8.77927 | Armadura - Aço CA60 - ø 5.0 mm | 1.63607 | Dimensionado | 1116 | 0 | Viga C-30 - Seção Retangular 20 X 30
V196 | VIGA BALDRAME | 20 | 30 | 0 | 0.41 % | Concreto - C-30 - Abatimento 12 cm | 0.248992 | Forma - Estrutura - Concreto | 3.33979 | Armadura - Aço CA50 - ø 12.5 mm | 19.7383 | Armadura - Aço CA60 - ø 5.0 mm | 3.67835 | Dimensionado | 1116 | 0 | Viga C-30 - Seção Retangular 20 X 30
V196 | VIGA BALDRAME | 20 | 30 | 0 | 0.82 % | Concreto - C-30 - Abatimento 12 cm | 0.212777 | Forma - Estrutura - Concreto | 2.85403 | Armadura - Aço CA50 - ø 12.5 mm | 16.8674 | Armadura - Aço CA60 - ø 5.0 mm | 3.14334 | Dimensionado | 1116 | 0 | Viga C-30 - Seção Retangular 20 X 30
V196 | VIGA BALDRAME | 20 | 30 | 0 | 0.41 % | Concreto - C-30 - Abatimento 12 cm | 0.294915 | Forma - Estrutura - Concreto | 3.95577 | Armadura - Aço CA50 - ø 12.5 mm | 23.3787 | Armadura - Aço CA60 - ø 5.0 mm | 4.35677 | Dimensionado | 1116 | 0 | Viga C-30 - Seção Retangular 20 X 30
V196 | VIGA BALDRAME | 20 | 30 | 0 | 0.41 % | Concreto - C-30 - Abatimento 12 cm | 0.133668 | Forma - Estrutura - Concreto | 1.79292 | Armadura - Aço CA50 - ø 12.5 mm | 10.5962 | Armadura - Aço CA60 - ø 5.0 mm | 1.97467 | Dimensionado | 1116 | 0 | Viga C-30 - Seção Retangular 20 X 30
V197 | VIGA BALDRAME | 14 | 40 | 0 | 0.18 % | Concreto - C-30 - Abatimento 12 cm | 0.027065 | Forma - Estrutura - Concreto | 0.454302 | Armadura - Aço CA50 - ø 8.0 mm | 0.473501 | Armadura - Aço CA60 - ø 5.0 mm | 0.581087 | Dimensionado | 1116 | 0 | Viga C-30 - Seção Retangular 14 X 40
V198 | VIGA BALDRAME | 20 | 30 | 0 | 0.17 % | Concreto - C-30 - Abatimento 12 cm | 0.113024 | Forma - Estrutura - Concreto | 1.50699 | Armadura - Aço CA50 - ø 8.0 mm | 1.76292 | Armadura - Aço CA50 - ø 10.0 mm | 2.41064 | Dimensionado | 1116 | 0 | Viga C-30 - Seção Retangular 20 X 30 | AltoQi_Eberick-Item_05 - Descrição_05: Armadura - Aço CA60 - ø 5.0 mm; Quantidade_05: 1.70486 kg; Status_05: Dimensionado
V198 | VIGA BALDRAME | 20 | 30 | 0 | 0.17 % | Concreto - C-30 - Abatimento 12 cm | 0.170809 | Forma - Estrutura - Concreto | 2.27745 | Armadura - Aço CA50 - ø 8.0 mm | 2.66423 | Armadura - Aço CA50 - ø 10.0 mm | 3.64311 | Dimensionado | 1116 | 0 | Viga C-30 - Seção Retangular 20 X 30 | AltoQi_Eberick-Item_05 - Descrição_05: Armadura - Aço CA60 - ø 5.0 mm; Quantidade_05: 2.57649 kg; Status_05: Dimensionado
V198 | VIGA BALDRAME | 20 | 30 | 0 | 0.17 % | Concreto - C-30 - Abatimento 12 cm | 0.167059 | Forma - Estrutura - Concreto | 2.22745 | Armadura - Aço CA50 - ø 8.0 mm | 2.60574 | Armadura - Aço CA50 - ø 10.0 mm | 3.56312 | Dimensionado | 1116 | 0 | Viga C-30 - Seção Retangular 20 X 30 | AltoQi_Eberick-Item_05 - Descrição_05: Armadura - Aço CA60 - ø 5.0 mm; Quantidade_05: 2.51992 kg; Status_05: Dimensionado
V198 | VIGA BALDRAME | 20 | 30 | 0 | 0.25 % | Concreto - C-30 - Abatimento 12 cm | 0.199508 | Forma - Estrutura - Concreto | 2.66011 | Armadura - Aço CA50 - ø 8.0 mm | 3.11188 | Armadura - Aço CA50 - ø 10.0 mm | 4.25523 | Dimensionado | 1116 | 0 | Viga C-30 - Seção Retangular 20 X 30 | AltoQi_Eberick-Item_05 - Descrição_05: Armadura - Aço CA60 - ø 5.0 mm; Quantidade_05: 3.00939 kg; Status_05: Dimensionado
V199 | VIGA BALDRAME | 20 | 30 | 0 | 0.41 % | Concreto - C-30 - Abatimento 12 cm | 0.247517 | Forma - Estrutura - Concreto | 3.35415 | Armadura - Aço CA50 - ø 12.5 mm | 16.7533 | Armadura - Aço CA60 - ø 5.0 mm | 3.65197 | Dimensionado | 1116 | 0 | Viga C-30 - Seção Retangular 20 X 30
V199 | VIGA BALDRAME | 20 | 30 | 0 | 0.41 % | Concreto - C-30 - Abatimento 12 cm | 0.119683 | Forma - Estrutura - Concreto | 1.62185 | Armadura - Aço CA50 - ø 12.5 mm | 8.10084 | Armadura - Aço CA60 - ø 5.0 mm | 1.76586 | Dimensionado | 1116 | 0 | Viga C-30 - Seção Retangular 20 X 30
V200 | VIGA BALDRAME | 15 | 30 | -20 | 0.35 % | Concreto - C-30 - Abatimento 12 cm | 0.177516 | Forma - Estrutura - Concreto | 2.9586 | Armadura - Aço CA50 - ø 10.0 mm | 10.962 | Armadura - Aço CA60 - ø 5.0 mm | 2.62028 | Dimensionado | 567 | 0 | Viga C-30 - Seção Retangular 15 X 30
V201 | VIGA BALDRAME | 15 | 30 | 0 | 0.22 % | Concreto - C-30 - Abatimento 12 cm | 0.067725 | Forma - Estrutura - Concreto | 1.12875 | Armadura - Aço CA50 - ø 8.0 mm | 3.15667 | Armadura - Aço CA60 - ø 5.0 mm | 1.04811 | Dimensionado | 0 | 0 | Viga C-30 - Seção Retangular 15 X 30
V202 | VIGA BALDRAME | 20 | 30 | 0 | 0.17 % | Concreto - C-30 - Abatimento 12 cm | 0.165036 | Forma - Estrutura - Concreto | 2.20048 | Armadura - Aço CA50 - ø 8.0 mm | 4.73501 | Armadura - Aço CA60 - ø 5.0 mm | 2.48927 | Dimensionado | 1116 | 0 | Viga C-30 - Seção Retangular 20 X 30
V203 | VIGA BALDRAME | 20 | 30 | 0 | 0.41 % | Concreto - C-30 - Abatimento 12 cm | 0.197158 | Forma - Estrutura - Concreto | 2.69166 | Armadura - Aço CA50 - ø 10.0 mm | 4.53662 | Armadura - Aço CA50 - ø 12.5 mm | 6.66437 | Dimensionado | 1116 | 0 | Viga C-30 - Seção Retangular 20 X 30 | AltoQi_Eberick-Item_05 - Descrição_05: Armadura - Aço CA60 - ø 5.0 mm; Quantidade_05: 3.10802 kg; Status_05: Dimensionado
V203 | VIGA BALDRAME | 20 | 30 | 0 | 0.41 % | Concreto - C-30 - Abatimento 12 cm | 0.053636 | Forma - Estrutura - Concreto | 0.73226 | Armadura - Aço CA50 - ø 10.0 mm | 1.23418 | Armadura - Aço CA50 - ø 12.5 mm | 1.81303 | Dimensionado | 1116 | 0 | Viga C-30 - Seção Retangular 20 X 30 | AltoQi_Eberick-Item_05 - Descrição_05: Armadura - Aço CA60 - ø 5.0 mm; Quantidade_05: 0.845529 kg; Status_05: Dimensionado
V204 | VIGA BALDRAME | 20 | 30 | 0 | 0.17 % | Concreto - C-30 - Abatimento 12 cm | 0.0267 | Forma - Estrutura - Concreto | 0.356 | Armadura - Aço CA50 - ø 8.0 mm | 1.2311 | Armadura - Aço CA60 - ø 5.0 mm | 0.585711 | Dimensionado | 1116 | 0 | Viga C-30 - Seção Retangular 20 X 30
V205 | VIGA BALDRAME | 20 | 30 | 0 | 0.17 % | Concreto - C-30 - Abatimento 12 cm | 0.095508 | Forma - Estrutura - Concreto | 1.27344 | Armadura - Aço CA50 - ø 8.0 mm | 1.45996 | Armadura - Aço CA50 - ø 10.0 mm | 2.6881 | Dimensionado | 1116 | 0 | Viga C-30 - Seção Retangular 20 X 30 | AltoQi_Eberick-Item_05 - Descrição_05: Armadura - Aço CA60 - ø 5.0 mm; Quantidade_05: 1.6107 kg; Status_05: Dimensionado
V206 | VIGA BALDRAME | 15 | 30 | 0 | 0.22 % | Concreto - C-30 - Abatimento 12 cm | 0.067725 | Forma - Estrutura - Concreto | 1.12875 | Armadura - Aço CA50 - ø 8.0 mm | 3.15667 | Armadura - Aço CA60 - ø 5.0 mm | 1.04811 | Dimensionado | 0 | 0 | Viga C-30 - Seção Retangular 15 X 30
V207 | VIGA BALDRAME | 20 | 30 | 0 | 0.17 % | Concreto - C-30 - Abatimento 12 cm | 0.039 | Forma - Estrutura - Concreto | 0.52 | Armadura - Aço CA50 - ø 8.0 mm | 1.3258 | Armadura - Aço CA60 - ø 5.0 mm | 0.439283 | Dimensionado | 1116 | 0 | Viga C-30 - Seção Retangular 20 X 30
V208 | VIGA BALDRAME | 20 | 30 | 0 | 0.17 % | Concreto - C-30 - Abatimento 12 cm | 0.042 | Forma - Estrutura - Concreto | 0.56 | Armadura - Aço CA50 - ø 8.0 mm | 1.40472 | Armadura - Aço CA60 - ø 5.0 mm | 0.439283 | Dimensionado | 837 | 0 | Viga C-30 - Seção Retangular 20 X 30
V209 | VIGA BALDRAME | 20 | 30 | 0 | 0.17 % | Concreto - C-30 - Abatimento 12 cm | 0.123342 | Forma - Estrutura - Concreto | 1.64456 | Armadura - Aço CA50 - ø 8.0 mm | 3.93006 | Armadura - Aço CA60 - ø 5.0 mm | 1.75713 | Dimensionado | 1116 | 0 | Viga C-30 - Seção Retangular 20 X 30
V210 | VIGA BALDRAME | 20 | 30 | 0 | 0.17 % | Concreto - C-30 - Abatimento 12 cm | 0.1266 | Forma - Estrutura - Concreto | 1.688 | Armadura - Aço CA50 - ø 8.0 mm | 4.11946 | Armadura - Aço CA60 - ø 5.0 mm | 2.04999 | Dimensionado | 1116 | 0 | Viga C-30 - Seção Retangular 20 X 30
V211 | VIGA BALDRAME | 20 | 30 | 0 | 0.26 % | Concreto - C-30 - Abatimento 12 cm | 0.101497 | Forma - Estrutura - Concreto | 1.3533 | Armadura - Aço CA50 - ø 10.0 mm | 4.52315 | Armadura - Aço CA60 - ø 5.0 mm | 1.52201 | Dimensionado | 1116 | 0 | Viga C-30 - Seção Retangular 20 X 30
V211 | VIGA BALDRAME | 20 | 30 | 0 | 0.26 % | Concreto - C-30 - Abatimento 12 cm | 0.201209 | Forma - Estrutura - Concreto | 2.68278 | Armadura - Aço CA50 - ø 10.0 mm | 8.96669 | Armadura - Aço CA60 - ø 5.0 mm | 3.01724 | Dimensionado | 1116 | 0 | Viga C-30 - Seção Retangular 20 X 30
V212 | VIGA BALDRAME | 20 | 30 | 0 | 0.26 % | Concreto - C-30 - Abatimento 12 cm | 0.181368 | Forma - Estrutura - Concreto | 2.41825 | Armadura - Aço CA50 - ø 10.0 mm | 8.14115 | Armadura - Aço CA60 - ø 5.0 mm | 2.78874 | Dimensionado | 1116 | 0 | Viga C-30 - Seção Retangular 20 X 30
V212 | VIGA BALDRAME | 20 | 30 | 0 | 0.26 % | Concreto - C-30 - Abatimento 12 cm | 0.190032 | Forma - Estrutura - Concreto | 2.53375 | Armadura - Aço CA50 - ø 10.0 mm | 8.53002 | Armadura - Aço CA60 - ø 5.0 mm | 2.92194 | Dimensionado | 1116 | 0 | Viga C-30 - Seção Retangular 20 X 30
V213 | VIGA BALDRAME | 20 | 30 | 0 | 0.17 % | Concreto - C-30 - Abatimento 12 cm | 0.042 | Forma - Estrutura - Concreto | 0.56 | Armadura - Aço CA50 - ø 8.0 mm | 1.40472 | Armadura - Aço CA60 - ø 5.0 mm | 0.439283 | Dimensionado | 837 | 0 | Viga C-30 - Seção Retangular 20 X 30
V214 | VIGA BALDRAME | 15 | 30 | 0 | 0.22 % | Concreto - C-30 - Abatimento 12 cm | 0.04095 | Forma - Estrutura - Concreto | 0.6825 | Armadura - Aço CA50 - ø 8.0 mm | 2.0834 | Armadura - Aço CA60 - ø 5.0 mm | 0.655071 | Dimensionado | 837 | 0 | Viga C-30 - Seção Retangular 15 X 30
V215 | VIGA BALDRAME | 15 | 30 | 0 | 0.22 % | Concreto - C-30 - Abatimento 12 cm | 0.0405 | Forma - Estrutura - Concreto | 0.675 | Armadura - Aço CA50 - ø 8.0 mm | 2.14654 | Armadura - Aço CA60 - ø 5.0 mm | 0.524057 | Dimensionado | 837 | 0 | Viga C-30 - Seção Retangular 15 X 30
V216 | VIGA BALDRAME | 20 | 30 | 0 | 0.61 % | Concreto - C-30 - Abatimento 12 cm | 0.381228 | Forma - Estrutura - Concreto | 5.04633 | Armadura - Aço CA50 - ø 12.5 mm | 36.274 | Armadura - Aço CA60 - ø 5.0 mm | 5.64469 | Dimensionado | 1116 | 0 | Viga C-30 - Seção Retangular 20 X 30
V216 | VIGA BALDRAME | 20 | 30 | 0 | 0.41 % | Concreto - C-30 - Abatimento 12 cm | 0.25287 | Forma - Estrutura - Concreto | 3.34724 | Armadura - Aço CA50 - ø 12.5 mm | 24.0606 | Armadura - Aço CA60 - ø 5.0 mm | 3.74414 | Dimensionado | 1116 | 0 | Viga C-30 - Seção Retangular 20 X 30
V216 | VIGA BALDRAME | 20 | 30 | 0 | 0.41 % | Concreto - C-30 - Abatimento 12 cm | 0.196608 | Forma - Estrutura - Concreto | 2.60251 | Armadura - Aço CA50 - ø 12.5 mm | 18.7074 | Armadura - Aço CA60 - ø 5.0 mm | 2.9111 | Dimensionado | 1116 | 0 | Viga C-30 - Seção Retangular 20 X 30
V217 | VIGA BALDRAME | 20 | 30 | 0 | 0.17 % | Concreto - C-30 - Abatimento 12 cm | 0.045 | Forma - Estrutura - Concreto | 0.6 | Armadura - Aço CA50 - ø 8.0 mm | 2.09919 | Armadura - Aço CA60 - ø 5.0 mm | 0.732138 | Dimensionado | 1116 | 0 | Viga C-30 - Seção Retangular 20 X 30
V218 | VIGA BALDRAME | 12 | 30 | 0 | 0.28 % | Forma - Estrutura - Concreto |  | Armadura - Aço CA50 - ø 8.0 mm |  | Armadura - Aço CA60 - ø 5.0 mm | 0.400749 |  |  |  | 0 | 0 | Viga C-30 - Seção Retangular 12 X 30 | AltoQi_Eberick-Item_01 - Quantidade_01: 0.0792 m2; AltoQi_Eberick-Item_02 - Quantidade_02: 0.497176 kg
V219 | VIGA BALDRAME | 20 | 30 | 0 | 0.39 % | Concreto - C-30 - Abatimento 12 cm | 0.188619 | Forma - Estrutura - Concreto | 2.51491 | Armadura - Aço CA50 - ø 10.0 mm | 9.6086 | Armadura - Aço CA60 - ø 5.0 mm | 2.96978 | Dimensionado | 1116 | 0 | Viga C-30 - Seção Retangular 20 X 30
V219 | VIGA BALDRAME | 20 | 30 | 0 | 0.26 % | Concreto - C-30 - Abatimento 12 cm | 0.164781 | Forma - Estrutura - Concreto | 2.19709 | Armadura - Aço CA50 - ø 10.0 mm | 8.39429 | Armadura - Aço CA60 - ø 5.0 mm | 2.59447 | Dimensionado | 1116 | 0 | Viga C-30 - Seção Retangular 20 X 30
V220 | VIGA BALDRAME | 20 | 30 | 0 | 0.41 % | Concreto - C-30 - Abatimento 12 cm | 0.161736 | Forma - Estrutura - Concreto | 2.15648 | Armadura - Aço CA50 - ø 10.0 mm | 3.99516 | Armadura - Aço CA50 - ø 12.5 mm | 5.5103 | Dimensionado | 1116 | 0 | Viga C-30 - Seção Retangular 20 X 30 | AltoQi_Eberick-Item_05 - Descrição_05: Armadura - Aço CA60 - ø 5.0 mm; Quantidade_05: 4.39283 kg; Status_05: Dimensionado
V221 | VIGA BALDRAME | 20 | 30 | 0 | 0.17 % | Concreto - C-30 - Abatimento 12 cm | 0.158332 | Forma - Estrutura - Concreto | 2.1111 | Armadura - Aço CA50 - ø 8.0 mm | 4.50917 | Armadura - Aço CA60 - ø 5.0 mm | 2.29922 | Dimensionado | 1116 | 0 | Viga C-30 - Seção Retangular 20 X 30
V221 | VIGA BALDRAME | 20 | 30 | 0 | 0.17 % | Concreto - C-30 - Abatimento 12 cm | 0.149478 | Forma - Estrutura - Concreto | 1.99304 | Armadura - Aço CA50 - ø 8.0 mm | 4.257 | Armadura - Aço CA60 - ø 5.0 mm | 2.17064 | Dimensionado | 1116 | 0 | Viga C-30 - Seção Retangular 20 X 30
V221 | VIGA BALDRAME | 20 | 30 | 0 | 0.17 % | Concreto - C-30 - Abatimento 12 cm | 0.055196 | Forma - Estrutura - Concreto | 0.735945 | Armadura - Aço CA50 - ø 8.0 mm | 1.57193 | Armadura - Aço CA60 - ø 5.0 mm | 0.801528 | Dimensionado | 1116 | 0 | Viga C-30 - Seção Retangular 20 X 30
V222 | VIGA BALDRAME | 15 | 30 | 0 | 0.22 % | Concreto - C-30 - Abatimento 12 cm | 0.041405 | Forma - Estrutura - Concreto | 0.690075 | Armadura - Aço CA50 - ø 8.0 mm | 2.0834 | Armadura - Aço CA60 - ø 5.0 mm | 0.655071 | Dimensionado | 1116 | 0 | Viga C-30 - Seção Retangular 15 X 30
V223 | VIGA BALDRAME | 20 | 30 | -20 | 0.17 % | Concreto - C-30 - Abatimento 12 cm | 0.1173 | Forma - Estrutura - Concreto | 1.564 | Armadura - Aço CA50 - ø 8.0 mm | 3.28294 | Armadura - Aço CA60 - ø 5.0 mm | 1.6107 | Dimensionado | 567 | 0 | Viga C-30 - Seção Retangular 20 X 30
V224 | VIGA BALDRAME | 20 | 30 | 0 | 0.61 % | Concreto - C-30 - Abatimento 12 cm | 0.299742 | Forma - Estrutura - Concreto | 3.99656 | Armadura - Aço CA50 - ø 12.5 mm | 25.1335 | Armadura - Aço CA60 - ø 5.0 mm | 4.68569 | Dimensionado | 1116 | 0 | Viga C-30 - Seção Retangular 20 X 30
V225 | VIGA BALDRAME | 20 | 30 | 0 | 0.26 % | Concreto - C-30 - Abatimento 12 cm | 0.150006 | Forma - Estrutura - Concreto | 2.00008 | Armadura - Aço CA50 - ø 8.0 mm | 2.62004 | Armadura - Aço CA50 - ø 10.0 mm | 3.52659 | Dimensionado | 1116 | 0 | Viga C-30 - Seção Retangular 20 X 30 | AltoQi_Eberick-Item_05 - Descrição_05: Armadura - Aço CA60 - ø 5.0 mm; Quantidade_05: 2.92855 kg; Status_05: Dimensionado
V226 | VIGA BALDRAME | 20 | 30 | 0 | 0.61 % | Concreto - C-30 - Abatimento 12 cm | 0.298758 | Forma - Estrutura - Concreto | 3.98344 | Armadura - Aço CA50 - ø 12.5 mm | 25.1335 | Armadura - Aço CA60 - ø 5.0 mm | 4.68569 | Dimensionado | 1116 | 0 | Viga C-30 - Seção Retangular 20 X 30
V227 | VIGA BALDRAME | 20 | 30 | 0 | 0.61 % | Concreto - C-30 - Abatimento 12 cm | 0.2997 | Forma - Estrutura - Concreto | 3.996 | Armadura - Aço CA50 - ø 12.5 mm | 25.0565 | Armadura - Aço CA60 - ø 5.0 mm | 4.68569 | Dimensionado | 1116 | 0 | Viga C-30 - Seção Retangular 20 X 30
V228 | VIGA BALDRAME | 20 | 30 | 0 | 0.26 % | Concreto - C-30 - Abatimento 12 cm | 0.15 | Forma - Estrutura - Concreto | 2 | Armadura - Aço CA50 - ø 8.0 mm | 2.25702 | Armadura - Aço CA50 - ø 10.0 mm | 3.52659 | Dimensionado | 1116 | 0 | Viga C-30 - Seção Retangular 20 X 30 | AltoQi_Eberick-Item_05 - Descrição_05: Armadura - Aço CA60 - ø 5.0 mm; Quantidade_05: 2.92855 kg; Status_05: Dimensionado
V229 | VIGA BALDRAME | 20 | 30 | 0 | 0.61 % | Concreto - C-30 - Abatimento 12 cm | 0.299694 | Forma - Estrutura - Concreto | 3.99592 | Armadura - Aço CA50 - ø 12.5 mm | 25.0179 | Armadura - Aço CA60 - ø 5.0 mm | 4.68569 | Dimensionado | 1116 | 0 | Viga C-30 - Seção Retangular 20 X 30
2 x V230 | VIGA BALDRAME | 15 | 30 | -15 | 0.52 % | Concreto - C-30 - Abatimento 12 cm | 0.137019 | Forma - Estrutura - Concreto | 2.28365 | Armadura - Aço CA50 - ø 10.0 mm | 9.9459 | Armadura - Aço CA60 - ø 5.0 mm | 5.00333 | Dimensionado | 567 | 0 | Viga C-30 - Seção Retangular 15 X 30
V230 | VIGA BALDRAME | 15 | 30 | -15 | 0.35 % | Concreto - C-30 - Abatimento 12 cm | 0.111273 | Forma - Estrutura - Concreto | 1.85455 | Armadura - Aço CA50 - ø 10.0 mm | 8.07704 | Armadura - Aço CA60 - ø 5.0 mm | 4.06319 | Dimensionado | 567 | 0 | Viga C-30 - Seção Retangular 15 X 30
V230 | VIGA BALDRAME | 15 | 30 | -15 | 0.35 % | Concreto - C-30 - Abatimento 12 cm | 0.101233 | Forma - Estrutura - Concreto | 1.68722 | Armadura - Aço CA50 - ø 10.0 mm | 7.34826 | Armadura - Aço CA60 - ø 5.0 mm | 3.69658 | Dimensionado | 567 | 0 | Viga C-30 - Seção Retangular 15 X 30
V230 | VIGA BALDRAME | 15 | 30 | -15 | 0.35 % | Concreto - C-30 - Abatimento 12 cm | 0.101234 | Forma - Estrutura - Concreto | 1.68723 | Armadura - Aço CA50 - ø 10.0 mm | 7.34833 | Armadura - Aço CA60 - ø 5.0 mm | 3.69661 | Dimensionado | 567 | 0 | Viga C-30 - Seção Retangular 15 X 30
V230 | VIGA BALDRAME | 15 | 30 | -15 | 0.35 % | Concreto - C-30 - Abatimento 12 cm | 0.201378 | Forma - Estrutura - Concreto | 3.35631 | Armadura - Aço CA50 - ø 10.0 mm | 14.6176 | Armadura - Aço CA60 - ø 5.0 mm | 7.35344 | Dimensionado | 567 | 0 | Viga C-30 - Seção Retangular 15 X 30
V230 | VIGA BALDRAME | 15 | 30 | -15 | 0.35 % | Concreto - C-30 - Abatimento 12 cm | 0.1449 | Forma - Estrutura - Concreto | 2.415 | Armadura - Aço CA50 - ø 10.0 mm | 10.5179 | Armadura - Aço CA60 - ø 5.0 mm | 5.2911 | Dimensionado | 567 | 0 | Viga C-30 - Seção Retangular 15 X 30
2 x V230 | VIGA BALDRAME | 15 | 30 | -15 | 0.35 % | Concreto - C-30 - Abatimento 12 cm | 0.140377 | Forma - Estrutura - Concreto | 2.33962 | Armadura - Aço CA50 - ø 10.0 mm | 10.1897 | Armadura - Aço CA60 - ø 5.0 mm | 5.12596 | Dimensionado | 567 | 0 | Viga C-30 - Seção Retangular 15 X 30
V230 | VIGA BALDRAME | 15 | 30 | -15 | 0.35 % | Concreto - C-30 - Abatimento 12 cm | 0.137019 | Forma - Estrutura - Concreto | 2.28365 | Armadura - Aço CA50 - ø 10.0 mm | 9.9459 | Armadura - Aço CA60 - ø 5.0 mm | 5.00333 | Dimensionado | 567 | 0 | Viga C-30 - Seção Retangular 15 X 30
2 x V230 | VIGA BALDRAME | 15 | 30 | -15 | 0.52 % | Concreto - C-30 - Abatimento 12 cm | 0.140377 | Forma - Estrutura - Concreto | 2.33962 | Armadura - Aço CA50 - ø 10.0 mm | 10.1897 | Armadura - Aço CA60 - ø 5.0 mm | 5.12596 | Dimensionado | 567 | 0 | Viga C-30 - Seção Retangular 15 X 30
V230 | VIGA BALDRAME | 15 | 30 | -15 | 0.52 % | Concreto - C-30 - Abatimento 12 cm | 0.143109 | Forma - Estrutura - Concreto | 2.38515 | Armadura - Aço CA50 - ø 10.0 mm | 10.3879 | Armadura - Aço CA60 - ø 5.0 mm | 5.2257 | Dimensionado | 567 | 0 | Viga C-30 - Seção Retangular 15 X 30
V230 | VIGA BALDRAME | 15 | 30 | -15 | 0.35 % | Concreto - C-30 - Abatimento 12 cm | 0.226355 | Forma - Estrutura - Concreto | 3.77259 | Armadura - Aço CA50 - ø 10.0 mm | 16.4306 | Armadura - Aço CA60 - ø 5.0 mm | 8.26548 | Dimensionado | 567 | 0 | Viga C-30 - Seção Retangular 15 X 30
2 x VM1 | VIGA BALDRAME | 20 | 20 | 0 | 0.39 % | Concreto - C-30 - Abatimento 12 cm | 0.025862 | Forma - Estrutura - Concreto | 0.387931 | Armadura - Aço CA50 - ø 10.0 mm | 1.97717 | Armadura - Aço CA60 - ø 5.0 mm | 0.538142 | Dimensionado | 0 | 0 | Viga C-30 - Seção Retangular 20 X 20
VM1 | VIGA BALDRAME | 20 | 20 | 0 | 0.39 % | Concreto - C-30 - Abatimento 12 cm | 0.048276 | Forma - Estrutura - Concreto | 0.724138 | Armadura - Aço CA50 - ø 10.0 mm | 3.69072 | Armadura - Aço CA60 - ø 5.0 mm | 1.00453 | Dimensionado | 0 | 0 | Viga C-30 - Seção Retangular 20 X 20
V201 | TERREO | 14 | 40 | 0 | 0.18 % | Concreto - C-30 - Abatimento 12 cm | 0.323899 | Forma - Estrutura - Concreto | 5.43687 | Armadura - Aço CA50 - ø 8.0 mm | 8.1972 | Armadura - Aço CA50 - ø 10.0 mm | 6.24351 | Dimensionado | 405 | 0 | Viga C-30 - Seção Retangular 14 X 40 | AltoQi_Eberick-Item_05 - Descrição_05: Armadura - Aço CA60 - ø 5.0 mm; Quantidade_05: 5.54186 kg; Status_05: Dimensionado
V201 | TERREO | 14 | 40 | 0 | 0.18 % | Concreto - C-30 - Abatimento 12 cm | 0.011939 | Forma - Estrutura - Concreto | 0.2004 | Armadura - Aço CA50 - ø 8.0 mm | 0.302144 | Armadura - Aço CA50 - ø 10.0 mm | 0.230132 | Dimensionado | 405 | 0 | Viga C-30 - Seção Retangular 14 X 40 | AltoQi_Eberick-Item_05 - Descrição_05: Armadura - Aço CA60 - ø 5.0 mm; Quantidade_05: 0.20427 kg; Status_05: Dimensionado
V202 | TERREO | 14 | 40 | 0 | 0.28 % | Concreto - C-30 - Abatimento 12 cm | 0.34664 | Forma - Estrutura - Concreto | 5.8844 | Armadura - Aço CA50 - ø 8.0 mm | 3.33029 | Armadura - Aço CA50 - ø 10.0 mm | 14.1804 | Dimensionado | 405 | 0 | Viga C-30 - Seção Retangular 14 X 40 | AltoQi_Eberick-Item_05 - Descrição_05: Armadura - Aço CA60 - ø 5.0 mm; Quantidade_05: 5.21282 kg; Status_05: Dimensionado
V203 | TERREO | 14 | 40 | 0 | 0.18 % | Concreto - C-30 - Abatimento 12 cm | 0.12914 | Forma - Estrutura - Concreto | 2.22515 | Armadura - Aço CA50 - ø 8.0 mm | 1.94278 | Armadura - Aço CA50 - ø 10.0 mm | 3.47694 | Dimensionado | 405 | 0 | Viga C-30 - Seção Retangular 14 X 40 | AltoQi_Eberick-Item_05 - Descrição_05: Armadura - Aço CA60 - ø 5.0 mm; Quantidade_05: 2.5337 kg; Status_05: Dimensionado
V203 | TERREO | 14 | 40 | 0 | 0.18 % | Concreto - C-30 - Abatimento 12 cm | 0.01879 | Forma - Estrutura - Concreto | 0.323756 | Armadura - Aço CA50 - ø 8.0 mm | 0.282672 | Armadura - Aço CA50 - ø 10.0 mm | 0.50589 | Dimensionado | 405 | 0 | Viga C-30 - Seção Retangular 14 X 40 | AltoQi_Eberick-Item_05 - Descrição_05: Armadura - Aço CA60 - ø 5.0 mm; Quantidade_05: 0.36865 kg; Status_05: Dimensionado
V204 | TERREO | 14 | 40 | 0 | 0.18 % | Concreto - C-30 - Abatimento 12 cm | 0.136147 | Forma - Estrutura - Concreto | 2.28533 | Armadura - Aço CA50 - ø 8.0 mm | 4.68766 | Armadura - Aço CA60 - ø 5.0 mm | 1.74634 | Dimensionado | 405 | 0 | Viga C-30 - Seção Retangular 14 X 40
V205 | TERREO | 17 | 40 | 0 | 0.15 % | Concreto - C-30 - Abatimento 12 cm | 0.168463 | Forma - Estrutura - Concreto | 2.40308 | Armadura - Aço CA50 - ø 8.0 mm | 4.65609 | Armadura - Aço CA60 - ø 5.0 mm | 2.01608 | Dimensionado | 405 | 0 | Viga C-30 - Seção Retangular 17 X 40
V206 | TERREO | 14 | 40 | 0 | 0.18 % | Concreto - C-30 - Abatimento 12 cm | 0.114397 | Forma - Estrutura - Concreto | 1.97767 | Armadura - Aço CA50 - ø 8.0 mm | 1.88769 | Armadura - Aço CA50 - ø 10.0 mm | 3.47698 | Dimensionado | 405 | 0 | Viga C-30 - Seção Retangular 14 X 40 | AltoQi_Eberick-Item_05 - Descrição_05: Armadura - Aço CA60 - ø 5.0 mm; Quantidade_05: 2.25654 kg; Status_05: Dimensionado
V206 | TERREO | 14 | 40 | 0 | 0.18 % | Concreto - C-30 - Abatimento 12 cm | 0.016643 | Forma - Estrutura - Concreto | 0.287726 | Armadura - Aço CA50 - ø 8.0 mm | 0.274634 | Armadura - Aço CA50 - ø 10.0 mm | 0.505856 | Dimensionado | 405 | 0 | Viga C-30 - Seção Retangular 14 X 40 | AltoQi_Eberick-Item_05 - Descrição_05: Armadura - Aço CA60 - ø 5.0 mm; Quantidade_05: 0.328297 kg; Status_05: Dimensionado
V207 | TERREO | 14 | 40 | 0 | 0.18 % | Concreto - C-30 - Abatimento 12 cm | 0.136147 | Forma - Estrutura - Concreto | 2.28533 | Armadura - Aço CA50 - ø 8.0 mm | 4.78236 | Armadura - Aço CA60 - ø 5.0 mm | 1.74634 | Dimensionado | 405 | 0 | Viga C-30 - Seção Retangular 14 X 40
V208 | TERREO | 14 | 30 | 0 | 0.24 % | Forma - Estrutura - Concreto |  | Armadura - Aço CA50 - ø 8.0 mm |  | Armadura - Aço CA60 - ø 5.0 mm | 1.27931 | Concreto - C-30 - Abatimento 12 cm |  | Dimensionado | 0 | 0 | Viga C-30 - Seção Retangular 14 X 30 | AltoQi_Eberick-Item_01 - Quantidade_01: 1.84068 m2; AltoQi_Eberick-Item_02 - Quantidade_02: 4.6482 kg; AltoQi_Eberick-Item_04 - Quantidade_04: 0.091747 m3
V209 | TERREO | 17 | 40 | 0 | 0.15 % | Concreto - C-30 - Abatimento 12 cm | 0.011549 | Forma - Estrutura - Concreto | 0.164747 | Armadura - Aço CA50 - ø 8.0 mm | 0.285115 | Armadura - Aço CA50 - ø 10.0 mm | 0.640395 | Dimensionado | 405 | 0 | Viga C-30 - Seção Retangular 17 X 40 | AltoQi_Eberick-Item_05 - Descrição_05: Armadura - Aço CA60 - ø 5.0 mm; Quantidade_05: 0.50756 kg; Status_05: Dimensionado
V209 | TERREO | 17 | 40 | 0 | 0.15 % | Concreto - C-30 - Abatimento 12 cm | 0.019139 | Forma - Estrutura - Concreto | 0.273014 | Armadura - Aço CA50 - ø 8.0 mm | 0.472486 | Armadura - Aço CA50 - ø 10.0 mm | 1.06125 | Dimensionado | 405 | 0 | Viga C-30 - Seção Retangular 17 X 40 | AltoQi_Eberick-Item_05 - Descrição_05: Armadura - Aço CA60 - ø 5.0 mm; Quantidade_05: 0.841116 kg; Status_05: Dimensionado
V210 | TERREO | 14 | 40 | 0 | 0.18 % | Concreto - C-30 - Abatimento 12 cm | 0.109846 | Forma - Estrutura - Concreto | 1.86503 | Armadura - Aço CA50 - ø 8.0 mm | 1.70155 | Armadura - Aço CA50 - ø 10.0 mm | 2.77375 | Dimensionado | 405 | 0 | Viga C-30 - Seção Retangular 14 X 40 | AltoQi_Eberick-Item_05 - Descrição_05: Armadura - Aço CA60 - ø 5.0 mm; Quantidade_05: 1.77129 kg; Status_05: Dimensionado
V210 | TERREO | 14 | 40 | 0 | 0.18 % | Concreto - C-30 - Abatimento 12 cm | 0.231491 | Forma - Estrutura - Concreto | 3.9304 | Armadura - Aço CA50 - ø 8.0 mm | 3.58588 | Armadura - Aço CA50 - ø 10.0 mm | 5.84544 | Dimensionado | 405 | 0 | Viga C-30 - Seção Retangular 14 X 40 | AltoQi_Eberick-Item_05 - Descrição_05: Armadura - Aço CA60 - ø 5.0 mm; Quantidade_05: 3.73285 kg; Status_05: Dimensionado
V211 | TERREO | 17 | 40 | 0 | 0.15 % | Concreto - C-30 - Abatimento 12 cm | 0.018835 | Forma - Estrutura - Concreto | 0.268675 | Armadura - Aço CA50 - ø 8.0 mm | 0.455231 | Armadura - Aço CA50 - ø 10.0 mm | 1.01614 | Dimensionado | 405 | 0 | Viga C-30 - Seção Retangular 17 X 40 | AltoQi_Eberick-Item_05 - Descrição_05: Armadura - Aço CA60 - ø 5.0 mm; Quantidade_05: 0.943559 kg; Status_05: Dimensionado
V211 | TERREO | 17 | 40 | 0 | 0.15 % | Concreto - C-30 - Abatimento 12 cm | 0.013163 | Forma - Estrutura - Concreto | 0.187773 | Armadura - Aço CA50 - ø 8.0 mm | 0.318154 | Armadura - Aço CA50 - ø 10.0 mm | 0.710165 | Dimensionado | 405 | 0 | Viga C-30 - Seção Retangular 17 X 40 | AltoQi_Eberick-Item_05 - Descrição_05: Armadura - Aço CA60 - ø 5.0 mm; Quantidade_05: 0.659439 kg; Status_05: Dimensionado
V212 | TERREO | 17 | 40 | 0 | 0.15 % | Concreto - C-30 - Abatimento 12 cm | 0.013657 | Forma - Estrutura - Concreto | 0.194817 | Armadura - Aço CA50 - ø 8.0 mm | 0.426468 | Armadura - Aço CA50 - ø 10.0 mm | 0.759976 | Dimensionado | 405 | 0 | Viga C-30 - Seção Retangular 17 X 40 | AltoQi_Eberick-Item_05 - Descrição_05: Armadura - Aço CA60 - ø 5.0 mm; Quantidade_05: 0.607843 kg; Status_05: Dimensionado
V212 | TERREO | 17 | 40 | 0 | 0.15 % | Concreto - C-30 - Abatimento 12 cm | 0.016922 | Forma - Estrutura - Concreto | 0.241392 | Armadura - Aço CA50 - ø 8.0 mm | 0.528425 | Armadura - Aço CA50 - ø 10.0 mm | 0.941667 | Dimensionado | 405 | 0 | Viga C-30 - Seção Retangular 17 X 40 | AltoQi_Eberick-Item_05 - Descrição_05: Armadura - Aço CA60 - ø 5.0 mm; Quantidade_05: 0.753163 kg; Status_05: Dimensionado
V213 | TERREO | 14 | 40 | 0 | 0.28 % | Concreto - C-30 - Abatimento 12 cm | 0.27149 | Forma - Estrutura - Concreto | 4.55715 | Armadura - Aço CA50 - ø 8.0 mm | 5.42462 | Armadura - Aço CA50 - ø 10.0 mm | 4.90062 | Dimensionado | 405 | 0 | Viga C-30 - Seção Retangular 14 X 40 | AltoQi_Eberick-Item_05 - Descrição_05: Armadura - Aço CA60 - ø 5.0 mm; Quantidade_05: 3.55986 kg; Status_05: Dimensionado
V213 | TERREO | 14 | 40 | 0 | 0.18 % | Concreto - C-30 - Abatimento 12 cm | 0.07963 | Forma - Estrutura - Concreto | 1.33665 | Armadura - Aço CA50 - ø 8.0 mm | 1.59108 | Armadura - Aço CA50 - ø 10.0 mm | 1.43738 | Dimensionado | 405 | 0 | Viga C-30 - Seção Retangular 14 X 40 | AltoQi_Eberick-Item_05 - Descrição_05: Armadura - Aço CA60 - ø 5.0 mm; Quantidade_05: 1.04413 kg; Status_05: Dimensionado
V214 | TERREO | 17 | 40 | 0 | 0.15 % | Concreto - C-30 - Abatimento 12 cm | 0.01866 | Forma - Estrutura - Concreto | 0.266183 | Armadura - Aço CA50 - ø 8.0 mm | 0.451743 | Armadura - Aço CA50 - ø 10.0 mm | 1.00835 | Dimensionado | 405 | 0 | Viga C-30 - Seção Retangular 17 X 40 | AltoQi_Eberick-Item_05 - Descrição_05: Armadura - Aço CA60 - ø 5.0 mm; Quantidade_05: 0.93633 kg; Status_05: Dimensionado
V214 | TERREO | 17 | 40 | 0 | 0.15 % | Concreto - C-30 - Abatimento 12 cm | 0.013286 | Forma - Estrutura - Concreto | 0.189523 | Armadura - Aço CA50 - ø 8.0 mm | 0.321642 | Armadura - Aço CA50 - ø 10.0 mm | 0.71795 | Dimensionado | 405 | 0 | Viga C-30 - Seção Retangular 17 X 40 | AltoQi_Eberick-Item_05 - Descrição_05: Armadura - Aço CA60 - ø 5.0 mm; Quantidade_05: 0.666668 kg; Status_05: Dimensionado
V215 | TERREO | 17 | 40 | 0 | 0.15 % | Concreto - C-30 - Abatimento 12 cm | 0.019144 | Forma - Estrutura - Concreto | 0.273079 | Armadura - Aço CA50 - ø 8.0 mm | 0.472597 | Armadura - Aço CA50 - ø 10.0 mm | 1.0615 | Dimensionado | 405 | 0 | Viga C-30 - Seção Retangular 17 X 40 | AltoQi_Eberick-Item_05 - Descrição_05: Armadura - Aço CA60 - ø 5.0 mm; Quantidade_05: 0.841314 kg; Status_05: Dimensionado
V215 | TERREO | 17 | 40 | 0 | 0.15 % | Concreto - C-30 - Abatimento 12 cm | 0.011545 | Forma - Estrutura - Concreto | 0.164682 | Armadura - Aço CA50 - ø 8.0 mm | 0.285004 | Armadura - Aço CA50 - ø 10.0 mm | 0.640146 | Dimensionado | 405 | 0 | Viga C-30 - Seção Retangular 17 X 40 | AltoQi_Eberick-Item_05 - Descrição_05: Armadura - Aço CA60 - ø 5.0 mm; Quantidade_05: 0.507362 kg; Status_05: Dimensionado
V216 | TERREO | 14 | 40 | 0 | 0.18 % | Concreto - C-30 - Abatimento 12 cm | 0.195415 | Forma - Estrutura - Concreto | 3.31886 | Armadura - Aço CA50 - ø 8.0 mm | 3.20144 | Armadura - Aço CA50 - ø 10.0 mm | 5.19799 | Dimensionado | 405 | 0 | Viga C-30 - Seção Retangular 14 X 40 | AltoQi_Eberick-Item_05 - Descrição_05: Armadura - Aço CA60 - ø 5.0 mm; Quantidade_05: 3.23606 kg; Status_05: Dimensionado
V216 | TERREO | 14 | 40 | 0 | 0.18 % | Concreto - C-30 - Abatimento 12 cm | 0.029998 | Forma - Estrutura - Concreto | 0.509481 | Armadura - Aço CA50 - ø 8.0 mm | 0.491455 | Armadura - Aço CA50 - ø 10.0 mm | 0.797947 | Dimensionado | 405 | 0 | Viga C-30 - Seção Retangular 14 X 40 | AltoQi_Eberick-Item_05 - Descrição_05: Armadura - Aço CA60 - ø 5.0 mm; Quantidade_05: 0.496769 kg; Status_05: Dimensionado
V216 | TERREO | 14 | 40 | 0 | 0.18 % | Concreto - C-30 - Abatimento 12 cm | 0.106964 | Forma - Estrutura - Concreto | 1.81664 | Armadura - Aço CA50 - ø 8.0 mm | 1.75236 | Armadura - Aço CA50 - ø 10.0 mm | 2.84521 | Dimensionado | 405 | 0 | Viga C-30 - Seção Retangular 14 X 40 | AltoQi_Eberick-Item_05 - Descrição_05: Armadura - Aço CA60 - ø 5.0 mm; Quantidade_05: 1.77131 kg; Status_05: Dimensionado
V217 | TERREO | 17 | 40 | 0 | 0.15 % | Concreto - C-30 - Abatimento 12 cm | 0.019 | Forma - Estrutura - Concreto | 0.271029 | Armadura - Aço CA50 - ø 8.0 mm | 0.459673 | Armadura - Aço CA50 - ø 10.0 mm | 1.02606 | Dimensionado | 405 | 0 | Viga C-30 - Seção Retangular 17 X 40 | AltoQi_Eberick-Item_05 - Descrição_05: Armadura - Aço CA60 - ø 5.0 mm; Quantidade_05: 0.960096 kg; Status_05: Dimensionado
V217 | TERREO | 17 | 40 | 0 | 0.15 % | Concreto - C-30 - Abatimento 12 cm | 0.012967 | Forma - Estrutura - Concreto | 0.184968 | Armadura - Aço CA50 - ø 8.0 mm | 0.313711 | Armadura - Aço CA50 - ø 10.0 mm | 0.700248 | Dimensionado | 405 | 0 | Viga C-30 - Seção Retangular 17 X 40 | AltoQi_Eberick-Item_05 - Descrição_05: Armadura - Aço CA60 - ø 5.0 mm; Quantidade_05: 0.655232 kg; Status_05: Dimensionado
V218 | TERREO | 17 | 40 | 0 | 0.15 % | Concreto - C-30 - Abatimento 12 cm | 0.018329 | Forma - Estrutura - Concreto | 0.261456 | Armadura - Aço CA50 - ø 8.0 mm | 0.454093 | Armadura - Aço CA50 - ø 10.0 mm | 1.01994 | Dimensionado | 405 | 0 | Viga C-30 - Seção Retangular 17 X 40 | AltoQi_Eberick-Item_05 - Descrição_05: Armadura - Aço CA60 - ø 5.0 mm; Quantidade_05: 0.815763 kg; Status_05: Dimensionado
V218 | TERREO | 17 | 40 | 0 | 0.15 % | Concreto - C-30 - Abatimento 12 cm | 0.012251 | Forma - Estrutura - Concreto | 0.174753 | Armadura - Aço CA50 - ø 8.0 mm | 0.303509 | Armadura - Aço CA50 - ø 10.0 mm | 0.681709 | Dimensionado | 405 | 0 | Viga C-30 - Seção Retangular 17 X 40 | AltoQi_Eberick-Item_05 - Descrição_05: Armadura - Aço CA60 - ø 5.0 mm; Quantidade_05: 0.545244 kg; Status_05: Dimensionado
V219 | TERREO | 14 | 40 | 0 | 0.18 % | Concreto - C-30 - Abatimento 12 cm | 0.012683 | Forma - Estrutura - Concreto | 0.212895 | Armadura - Aço CA50 - ø 8.0 mm | 0.45269 | Armadura - Aço CA60 - ø 5.0 mm | 0.211019 | Dimensionado | 405 | 0 | Viga C-30 - Seção Retangular 14 X 40
V219 | TERREO | 14 | 40 | 0 | 0.18 % | Concreto - C-30 - Abatimento 12 cm | 0.073421 | Forma - Estrutura - Concreto | 1.23242 | Armadura - Aço CA50 - ø 8.0 mm | 2.62056 | Armadura - Aço CA60 - ø 5.0 mm | 1.22156 | Dimensionado | 405 | 0 | Viga C-30 - Seção Retangular 14 X 40
V219 | TERREO | 14 | 40 | 0 | 0.18 % | Concreto - C-30 - Abatimento 12 cm | 0.238696 | Forma - Estrutura - Concreto | 4.00669 | Armadura - Aço CA50 - ø 8.0 mm | 8.51963 | Armadura - Aço CA60 - ø 5.0 mm | 3.97138 | Dimensionado | 405 | 0 | Viga C-30 - Seção Retangular 14 X 40
V220 | TERREO | 17 | 40 | 0 | 0.15 % | Concreto - C-30 - Abatimento 12 cm | 0.018663 | Forma - Estrutura - Concreto | 0.266219 | Armadura - Aço CA50 - ø 8.0 mm | 0.451743 | Armadura - Aço CA50 - ø 10.0 mm | 1.00836 | Dimensionado | 405 | 0 | Viga C-30 - Seção Retangular 17 X 40 | AltoQi_Eberick-Item_05 - Descrição_05: Armadura - Aço CA60 - ø 5.0 mm; Quantidade_05: 0.93633 kg; Status_05: Dimensionado
V220 | TERREO | 17 | 40 | 0 | 0.15 % | Concreto - C-30 - Abatimento 12 cm | 0.013288 | Forma - Estrutura - Concreto | 0.189548 | Armadura - Aço CA50 - ø 8.0 mm | 0.321641 | Armadura - Aço CA50 - ø 10.0 mm | 0.71795 | Dimensionado | 405 | 0 | Viga C-30 - Seção Retangular 17 X 40 | AltoQi_Eberick-Item_05 - Descrição_05: Armadura - Aço CA60 - ø 5.0 mm; Quantidade_05: 0.666668 kg; Status_05: Dimensionado
V221 | TERREO | 14 | 40 | 0 | 0.18 % | Concreto - C-30 - Abatimento 12 cm | 0.024203 | Forma - Estrutura - Concreto | 0.406268 | Armadura - Aço CA50 - ø 8.0 mm | 1.67304 | Armadura - Aço CA60 - ø 5.0 mm | 0.317517 | Dimensionado | 405 | 0 | Viga C-30 - Seção Retangular 14 X 40
V222 | TERREO | 14 | 40 | 0 | 0.18 % | Concreto - C-30 - Abatimento 12 cm | 0.151815 | Forma - Estrutura - Concreto | 2.54832 | Armadura - Aço CA50 - ø 8.0 mm | 4.9727 | Armadura - Aço CA60 - ø 5.0 mm | 2.09379 | Dimensionado | 405 | 0 | Viga C-30 - Seção Retangular 14 X 40
V222 | TERREO | 14 | 40 | 0 | 0.18 % | Concreto - C-30 - Abatimento 12 cm | 0.158985 | Forma - Estrutura - Concreto | 2.66868 | Armadura - Aço CA50 - ø 8.0 mm | 5.20756 | Armadura - Aço CA60 - ø 5.0 mm | 2.19268 | Dimensionado | 405 | 0 | Viga C-30 - Seção Retangular 14 X 40
V223 | TERREO | 17 | 40 | 0 | 0.15 % | Concreto - C-30 - Abatimento 12 cm | 0.13841 | Forma - Estrutura - Concreto | 1.97437 | Armadura - Aço CA50 - ø 8.0 mm | 1.93423 | Armadura - Aço CA50 - ø 10.0 mm | 3.5045 | Dimensionado | 405 | 0 | Viga C-30 - Seção Retangular 17 X 40 | AltoQi_Eberick-Item_05 - Descrição_05: Armadura - Aço CA60 - ø 5.0 mm; Quantidade_05: 2.65383 kg; Status_05: Dimensionado
V223 | TERREO | 17 | 40 | 0 | 0.15 % | Concreto - C-30 - Abatimento 12 cm | 0.02084 | Forma - Estrutura - Concreto | 0.29727 | Armadura - Aço CA50 - ø 8.0 mm | 0.291226 | Armadura - Aço CA50 - ø 10.0 mm | 0.527653 | Dimensionado | 405 | 0 | Viga C-30 - Seção Retangular 17 X 40 | AltoQi_Eberick-Item_05 - Descrição_05: Armadura - Aço CA60 - ø 5.0 mm; Quantidade_05: 0.399572 kg; Status_05: Dimensionado
V224 | TERREO | 14 | 30 | 0 | 0.24 % | Concreto - C-30 - Abatimento 12 cm | 0.023394 | Forma - Estrutura - Concreto | 0.41218 | Armadura - Aço CA50 - ø 8.0 mm | 1.57834 | Armadura - Aço CA60 - ø 5.0 mm | 0.383795 | Dimensionado | 405 | 0 | Viga C-30 - Seção Retangular 14 X 30
V225 | TERREO | 14 | 40 | 0 | 0.18 % | Concreto - C-30 - Abatimento 12 cm | 0.017442 | Forma - Estrutura - Concreto | 0.29278 | Armadura - Aço CA50 - ø 8.0 mm | 0.279756 | Armadura - Aço CA50 - ø 10.0 mm | 0.543232 | Dimensionado | 405 | 0 | Viga C-30 - Seção Retangular 14 X 40 | AltoQi_Eberick-Item_05 - Descrição_05: Armadura - Aço CA60 - ø 5.0 mm; Quantidade_05: 0.333581 kg; Status_05: Dimensionado
V225 | TERREO | 14 | 40 | 0 | 0.18 % | Concreto - C-30 - Abatimento 12 cm | 0.118358 | Forma - Estrutura - Concreto | 1.98672 | Armadura - Aço CA50 - ø 8.0 mm | 1.89835 | Armadura - Aço CA50 - ø 10.0 mm | 3.68622 | Dimensionado | 405 | 0 | Viga C-30 - Seção Retangular 14 X 40 | AltoQi_Eberick-Item_05 - Descrição_05: Armadura - Aço CA60 - ø 5.0 mm; Quantidade_05: 2.26358 kg; Status_05: Dimensionado
V226 | TERREO | 14 | 40 | 0 | 0.18 % | Concreto - C-30 - Abatimento 12 cm | 0.159517 | Forma - Estrutura - Concreto | 2.67761 | Armadura - Aço CA50 - ø 8.0 mm | 5.21692 | Armadura - Aço CA60 - ø 5.0 mm | 2.09577 | Dimensionado | 405 | 0 | Viga C-30 - Seção Retangular 14 X 40
V226 | TERREO | 14 | 40 | 0 | 0.18 % | Concreto - C-30 - Abatimento 12 cm | 0.15466 | Forma - Estrutura - Concreto | 2.59607 | Armadura - Aço CA50 - ø 8.0 mm | 5.05805 | Armadura - Aço CA60 - ø 5.0 mm | 2.03195 | Dimensionado | 405 | 0 | Viga C-30 - Seção Retangular 14 X 40
V227 | TERREO | 14 | 30 | 0 | 0.24 % | Concreto - C-30 - Abatimento 12 cm | 0.017577 | Forma - Estrutura - Concreto | 0.30969 | Armadura - Aço CA50 - ø 8.0 mm | 1.1364 | Armadura - Aço CA60 - ø 5.0 mm | 0.255863 | Dimensionado | 405 | 0 | Viga C-30 - Seção Retangular 14 X 30
V228 | TERREO | 14 | 40 | 0 | 0.18 % | Concreto - C-30 - Abatimento 12 cm | 0.239371 | Forma - Estrutura - Concreto | 4.01802 | Armadura - Aço CA50 - ø 8.0 mm | 7.55728 | Armadura - Aço CA60 - ø 5.0 mm | 3.12393 | Dimensionado | 405 | 0 | Viga C-30 - Seção Retangular 14 X 40
V228 | TERREO | 14 | 40 | 0 | 0.18 % | Concreto - C-30 - Abatimento 12 cm | 0.08908 | Forma - Estrutura - Concreto | 1.49527 | Armadura - Aço CA50 - ø 8.0 mm | 2.81238 | Armadura - Aço CA60 - ø 5.0 mm | 1.16255 | Dimensionado | 405 | 0 | Viga C-30 - Seção Retangular 14 X 40
V229 | TERREO | 14 | 40 | 0 | 0.18 % | Concreto - C-30 - Abatimento 12 cm | 0.090171 | Forma - Estrutura - Concreto | 1.51359 | Armadura - Aço CA50 - ø 8.0 mm | 3.40921 | Armadura - Aço CA60 - ø 5.0 mm | 1.42883 | Dimensionado | 0 | 0 | Viga C-30 - Seção Retangular 14 X 40
V230 | TERREO | 14 | 30 | 0 | 0.24 % | Concreto - C-30 - Abatimento 12 cm | 0.017577 | Forma - Estrutura - Concreto | 0.30969 | Armadura - Aço CA50 - ø 8.0 mm | 1.1364 | Armadura - Aço CA60 - ø 5.0 mm | 0.255863 | Dimensionado | 405 | 0 | Viga C-30 - Seção Retangular 14 X 30
V231 | TERREO | 14 | 40 | 0 | 0.18 % | Concreto - C-30 - Abatimento 12 cm | 0.159517 | Forma - Estrutura - Concreto | 2.67761 | Armadura - Aço CA50 - ø 8.0 mm | 5.21692 | Armadura - Aço CA60 - ø 5.0 mm | 2.09577 | Dimensionado | 405 | 0 | Viga C-30 - Seção Retangular 14 X 40
V231 | TERREO | 14 | 40 | 0 | 0.18 % | Concreto - C-30 - Abatimento 12 cm | 0.15466 | Forma - Estrutura - Concreto | 2.59607 | Armadura - Aço CA50 - ø 8.0 mm | 5.05805 | Armadura - Aço CA60 - ø 5.0 mm | 2.03195 | Dimensionado | 405 | 0 | Viga C-30 - Seção Retangular 14 X 40
V232 | TERREO | 14 | 40 | 0 | 0.18 % | Concreto - C-30 - Abatimento 12 cm | 0.134541 | Forma - Estrutura - Concreto | 2.12678 | Armadura - Aço CA50 - ø 8.0 mm | 4.75079 | Armadura - Aço CA60 - ø 5.0 mm | 1.9051 | Dimensionado | 405 | 0 | Viga C-30 - Seção Retangular 14 X 40
V233 | TERREO | 14 | 40 | 0 | 0.18 % | Concreto - C-30 - Abatimento 12 cm | 0.0476 | Forma - Estrutura - Concreto | 0.7332 | Armadura - Aço CA50 - ø 8.0 mm | 2.57269 | Armadura - Aço CA60 - ø 5.0 mm | 0.793792 | Dimensionado | 0 | 0 | Viga C-30 - Seção Retangular 14 X 40
V234 | TERREO | 14 | 40 | 0 | 0.18 % | Concreto - C-30 - Abatimento 12 cm | 0.02046 | Forma - Estrutura - Concreto | 0.343441 | Armadura - Aço CA50 - ø 8.0 mm | 0.878241 | Armadura - Aço CA60 - ø 5.0 mm | 0.34779 | Dimensionado | 405 | 0 | Viga C-30 - Seção Retangular 14 X 40
V234 | TERREO | 14 | 40 | 0 | 0.18 % | Concreto - C-30 - Abatimento 12 cm | 0.072936 | Forma - Estrutura - Concreto | 1.22429 | Armadura - Aço CA50 - ø 8.0 mm | 3.13073 | Armadura - Aço CA60 - ø 5.0 mm | 1.23979 | Dimensionado | 405 | 0 | Viga C-30 - Seção Retangular 14 X 40
V235 | TERREO | 14 | 40 | 0 | 0.18 % | Concreto - C-30 - Abatimento 12 cm | 0.032038 | Forma - Estrutura - Concreto | 0.537774 | Armadura - Aço CA50 - ø 8.0 mm | 1.65725 | Armadura - Aço CA60 - ø 5.0 mm | 0.621162 | Dimensionado | 405 | 0 | Viga C-30 - Seção Retangular 14 X 40
V236 | TERREO | 17 | 40 | 0 | 0.15 % | Concreto - C-30 - Abatimento 12 cm | 0.019648 | Forma - Estrutura - Concreto | 0.280276 | Armadura - Aço CA50 - ø 8.0 mm | 0.274577 | Armadura - Aço CA50 - ø 10.0 mm | 0.497489 | Dimensionado | 405 | 0 | Viga C-30 - Seção Retangular 17 X 40 | AltoQi_Eberick-Item_05 - Descrição_05: Armadura - Aço CA60 - ø 5.0 mm; Quantidade_05: 0.352958 kg; Status_05: Dimensionado
V236 | TERREO | 17 | 40 | 0 | 0.15 % | Concreto - C-30 - Abatimento 12 cm | 0.139601 | Forma - Estrutura - Concreto | 1.99137 | Armadura - Aço CA50 - ø 8.0 mm | 1.95088 | Armadura - Aço CA50 - ø 10.0 mm | 3.53467 | Dimensionado | 405 | 0 | Viga C-30 - Seção Retangular 17 X 40 | AltoQi_Eberick-Item_05 - Descrição_05: Armadura - Aço CA60 - ø 5.0 mm; Quantidade_05: 2.50778 kg; Status_05: Dimensionado
V237 | TERREO | 17 | 40 | 0 | 0.15 % | Concreto - C-30 - Abatimento 12 cm | 0.020839 | Forma - Estrutura - Concreto | 0.297257 | Armadura - Aço CA50 - ø 8.0 mm | 0.304251 | Armadura - Aço CA50 - ø 10.0 mm | 0.546789 | Dimensionado | 405 | 0 | Viga C-30 - Seção Retangular 17 X 40 | AltoQi_Eberick-Item_05 - Descrição_05: Armadura - Aço CA60 - ø 5.0 mm; Quantidade_05: 0.410962 kg; Status_05: Dimensionado
V237 | TERREO | 17 | 40 | 0 | 0.15 % | Concreto - C-30 - Abatimento 12 cm | 0.126721 | Forma - Estrutura - Concreto | 1.80764 | Armadura - Aço CA50 - ø 8.0 mm | 1.85018 | Armadura - Aço CA50 - ø 10.0 mm | 3.32507 | Dimensionado | 405 | 0 | Viga C-30 - Seção Retangular 17 X 40 | AltoQi_Eberick-Item_05 - Descrição_05: Armadura - Aço CA60 - ø 5.0 mm; Quantidade_05: 2.4991 kg; Status_05: Dimensionado
V238 | TERREO | 14 | 40 | 0 | 0.18 % | Concreto - C-30 - Abatimento 12 cm | 0.208001 | Forma - Estrutura - Concreto | 3.45071 | Armadura - Aço CA50 - ø 8.0 mm | 7.11307 | Armadura - Aço CA60 - ø 5.0 mm | 2.85011 | Dimensionado | 405 | 0 | Viga C-30 - Seção Retangular 14 X 40
V238 | TERREO | 14 | 40 | 0 | 0.18 % | Concreto - C-30 - Abatimento 12 cm | 0.09734 | Forma - Estrutura - Concreto | 1.61486 | Armadura - Aço CA50 - ø 8.0 mm | 3.32877 | Armadura - Aço CA60 - ø 5.0 mm | 1.33379 | Dimensionado | 405 | 0 | Viga C-30 - Seção Retangular 14 X 40
V238 | TERREO | 14 | 40 | 0 | 0.18 % | Concreto - C-30 - Abatimento 12 cm | 0.030659 | Forma - Estrutura - Concreto | 0.508625 | Armadura - Aço CA50 - ø 8.0 mm | 1.04845 | Armadura - Aço CA60 - ø 5.0 mm | 0.420097 | Dimensionado | 405 | 0 | Viga C-30 - Seção Retangular 14 X 40
V239 | TERREO | 14 | 40 | 0 | 0.18 % | Concreto - C-30 - Abatimento 12 cm | 0.0252 | Forma - Estrutura - Concreto | 0.423 | Armadura - Aço CA50 - ø 8.0 mm | 1.40472 | Armadura - Aço CA60 - ø 5.0 mm | 0.476275 | Dimensionado | 0 | 0 | Viga C-30 - Seção Retangular 14 X 40
V240 | TERREO | 14 | 40 | 0 | 0.18 % | Concreto - C-30 - Abatimento 12 cm | 0.033723 | Forma - Estrutura - Concreto | 0.566068 | Armadura - Aço CA50 - ø 8.0 mm | 1.68882 | Armadura - Aço CA60 - ø 5.0 mm | 0.635034 | Dimensionado | 405 | 0 | Viga C-30 - Seção Retangular 14 X 40
V241 | TERREO | 14 | 40 | 0 | 0.18 % | Forma - Estrutura - Concreto |  | Armadura - Aço CA50 - ø 8.0 mm |  | Armadura - Aço CA50 - ø 10.0 mm | 1.02098 | Armadura - Aço CA60 - ø 5.0 mm | 0.797872 | Dimensionado | 405 | 0 | Viga C-30 - Seção Retangular 14 X 40 | AltoQi_Eberick-Item_01 - Quantidade_01: 0.160423 m2; AltoQi_Eberick-Item_02 - Quantidade_02: 0.432485 kg
V241 | TERREO | 14 | 40 | 0 | 0.18 % | Forma - Estrutura - Concreto |  | Armadura - Aço CA50 - ø 8.0 mm |  | Armadura - Aço CA50 - ø 10.0 mm | 0.692992 | Armadura - Aço CA60 - ø 5.0 mm | 0.541556 | Dimensionado | 405 | 0 | Viga C-30 - Seção Retangular 14 X 40 | AltoQi_Eberick-Item_01 - Quantidade_01: 0.108887 m2; AltoQi_Eberick-Item_02 - Quantidade_02: 0.293549 kg
V242 | TERREO | 14 | 40 | 0 | 0.18 % | Concreto - C-30 - Abatimento 12 cm | 0.223521 | Forma - Estrutura - Concreto | 3.84053 | Armadura - Aço CA50 - ø 8.0 mm | 3.55343 | Armadura - Aço CA50 - ø 10.0 mm | 5.79292 | Dimensionado | 405 | 0 | Viga C-30 - Seção Retangular 14 X 40 | AltoQi_Eberick-Item_05 - Descrição_05: Armadura - Aço CA60 - ø 5.0 mm; Quantidade_05: 3.60605 kg; Status_05: Dimensionado
V242 | TERREO | 14 | 40 | 0 | 0.18 % | Concreto - C-30 - Abatimento 12 cm | 0.108576 | Forma - Estrutura - Concreto | 1.86556 | Armadura - Aço CA50 - ø 8.0 mm | 1.7261 | Armadura - Aço CA50 - ø 10.0 mm | 2.81394 | Dimensionado | 405 | 0 | Viga C-30 - Seção Retangular 14 X 40 | AltoQi_Eberick-Item_05 - Descrição_05: Armadura - Aço CA60 - ø 5.0 mm; Quantidade_05: 1.75166 kg; Status_05: Dimensionado
V243 | TERREO | 14 | 40 | 0 | 0.18 % | Concreto - C-30 - Abatimento 12 cm | 0.092546 | Forma - Estrutura - Concreto | 1.55344 | Armadura - Aço CA50 - ø 8.0 mm | 3.66174 | Armadura - Aço CA60 - ø 5.0 mm | 1.27007 | Dimensionado | 405 | 0 | Viga C-30 - Seção Retangular 14 X 40
V244 | TERREO | 17 | 40 | 0 | 0.15 % | Concreto - C-30 - Abatimento 12 cm | 0.019732 | Forma - Estrutura - Concreto | 0.28147 | Armadura - Aço CA50 - ø 8.0 mm | 0.462759 | Armadura - Aço CA50 - ø 10.0 mm | 1.02374 | Dimensionado | 405 | 0 | Viga C-30 - Seção Retangular 17 X 40 | AltoQi_Eberick-Item_05 - Descrição_05: Armadura - Aço CA60 - ø 5.0 mm; Quantidade_05: 0.937831 kg; Status_05: Dimensionado
V244 | TERREO | 17 | 40 | 0 | 0.15 % | Concreto - C-30 - Abatimento 12 cm | 0.014255 | Forma - Estrutura - Concreto | 0.203336 | Armadura - Aço CA50 - ø 8.0 mm | 0.334301 | Armadura - Aço CA50 - ø 10.0 mm | 0.739559 | Dimensionado | 405 | 0 | Viga C-30 - Seção Retangular 17 X 40 | AltoQi_Eberick-Item_05 - Descrição_05: Armadura - Aço CA60 - ø 5.0 mm; Quantidade_05: 0.677498 kg; Status_05: Dimensionado
V245 | TERREO | 17 | 40 | 0 | 0.15 % | Concreto - C-30 - Abatimento 12 cm | 0.018491 | Forma - Estrutura - Concreto | 0.263771 | Armadura - Aço CA50 - ø 8.0 mm | 0.45599 | Armadura - Aço CA50 - ø 10.0 mm | 1.02098 | Dimensionado | 405 | 0 | Viga C-30 - Seção Retangular 17 X 40 | AltoQi_Eberick-Item_05 - Descrição_05: Armadura - Aço CA60 - ø 5.0 mm; Quantidade_05: 0.925495 kg; Status_05: Dimensionado
V245 | TERREO | 17 | 40 | 0 | 0.15 % | Concreto - C-30 - Abatimento 12 cm | 0.012551 | Forma - Estrutura - Concreto | 0.179034 | Armadura - Aço CA50 - ø 8.0 mm | 0.309503 | Armadura - Aço CA50 - ø 10.0 mm | 0.692992 | Dimensionado | 405 | 0 | Viga C-30 - Seção Retangular 17 X 40 | AltoQi_Eberick-Item_05 - Descrição_05: Armadura - Aço CA60 - ø 5.0 mm; Quantidade_05: 0.62818 kg; Status_05: Dimensionado
V246 | TERREO | 14 | 40 | 0 | 0.18 % | Concreto - C-30 - Abatimento 12 cm | 0.110118 | Forma - Estrutura - Concreto | 1.86962 | Armadura - Aço CA50 - ø 8.0 mm | 1.70437 | Armadura - Aço CA50 - ø 10.0 mm | 2.77834 | Dimensionado | 405 | 0 | Viga C-30 - Seção Retangular 14 X 40 | AltoQi_Eberick-Item_05 - Descrição_05: Armadura - Aço CA60 - ø 5.0 mm; Quantidade_05: 1.7782 kg; Status_05: Dimensionado
V246 | TERREO | 14 | 40 | 0 | 0.18 % | Concreto - C-30 - Abatimento 12 cm | 0.231499 | Forma - Estrutura - Concreto | 3.93046 | Armadura - Aço CA50 - ø 8.0 mm | 3.58306 | Armadura - Aço CA50 - ø 10.0 mm | 5.84085 | Dimensionado | 405 | 0 | Viga C-30 - Seção Retangular 14 X 40 | AltoQi_Eberick-Item_05 - Descrição_05: Armadura - Aço CA60 - ø 5.0 mm; Quantidade_05: 3.73827 kg; Status_05: Dimensionado
V247 | TERREO | 17 | 40 | 0 | 0.15 % | Concreto - C-30 - Abatimento 12 cm | 0.171442 | Forma - Estrutura - Concreto | 2.44556 | Armadura - Aço CA50 - ø 8.0 mm | 4.81393 | Armadura - Aço CA60 - ø 5.0 mm | 2.18408 | Dimensionado | 405 | 0 | Viga C-30 - Seção Retangular 17 X 40
V248 | TERREO | 14 | 40 | 0 | 0.18 % | Concreto - C-30 - Abatimento 12 cm | 0.100189 | Forma - Estrutura - Concreto | 1.68175 | Armadura - Aço CA50 - ø 8.0 mm | 1.6071 | Armadura - Aço CA50 - ø 10.0 mm | 2.56828 | Dimensionado | 405 | 0 | Viga C-30 - Seção Retangular 14 X 40 | AltoQi_Eberick-Item_05 - Descrição_05: Armadura - Aço CA60 - ø 5.0 mm; Quantidade_05: 1.36755 kg; Status_05: Dimensionado
V248 | TERREO | 14 | 40 | 0 | 0.18 % | Concreto - C-30 - Abatimento 12 cm | 0.211266 | Forma - Estrutura - Concreto | 3.54625 | Armadura - Aço CA50 - ø 8.0 mm | 3.38885 | Armadura - Aço CA50 - ø 10.0 mm | 5.41568 | Dimensionado | 405 | 0 | Viga C-30 - Seção Retangular 14 X 40 | AltoQi_Eberick-Item_05 - Descrição_05: Armadura - Aço CA60 - ø 5.0 mm; Quantidade_05: 2.88372 kg; Status_05: Dimensionado
V248 | TERREO | 14 | 40 | 0 | 0.18 % | Concreto - C-30 - Abatimento 12 cm | 0.14215 | Forma - Estrutura - Concreto | 2.3861 | Armadura - Aço CA50 - ø 8.0 mm | 2.28018 | Armadura - Aço CA50 - ø 10.0 mm | 3.64394 | Dimensionado | 405 | 0 | Viga C-30 - Seção Retangular 14 X 40 | AltoQi_Eberick-Item_05 - Descrição_05: Armadura - Aço CA60 - ø 5.0 mm; Quantidade_05: 1.94031 kg; Status_05: Dimensionado
V249 | TERREO | 17 | 40 | 0 | 0.15 % | Concreto - C-30 - Abatimento 12 cm | 0.014254 | Forma - Estrutura - Concreto | 0.203323 | Armadura - Aço CA50 - ø 8.0 mm | 0.334348 | Armadura - Aço CA50 - ø 10.0 mm | 0.739662 | Dimensionado | 405 | 0 | Viga C-30 - Seção Retangular 17 X 40 | AltoQi_Eberick-Item_05 - Descrição_05: Armadura - Aço CA60 - ø 5.0 mm; Quantidade_05: 0.677593 kg; Status_05: Dimensionado
V249 | TERREO | 17 | 40 | 0 | 0.15 % | Concreto - C-30 - Abatimento 12 cm | 0.019726 | Forma - Estrutura - Concreto | 0.281384 | Armadura - Aço CA50 - ø 8.0 mm | 0.462712 | Armadura - Aço CA50 - ø 10.0 mm | 1.02364 | Dimensionado | 405 | 0 | Viga C-30 - Seção Retangular 17 X 40 | AltoQi_Eberick-Item_05 - Descrição_05: Armadura - Aço CA60 - ø 5.0 mm; Quantidade_05: 0.937736 kg; Status_05: Dimensionado
V250 | TERREO | 14 | 40 | 0 | 0.18 % | Concreto - C-30 - Abatimento 12 cm | 0.142806 | Forma - Estrutura - Concreto | 2.39709 | Armadura - Aço CA50 - ø 8.0 mm | 4.78236 | Armadura - Aço CA60 - ø 5.0 mm | 1.9051 | Dimensionado | 0 | 0 | Viga C-30 - Seção Retangular 14 X 40
V251 | TERREO | 14 | 40 | 0 | 0.18 % | Concreto - C-30 - Abatimento 12 cm | 0.117611 | Forma - Estrutura - Concreto | 1.97419 | Armadura - Aço CA50 - ø 8.0 mm | 4.11946 | Armadura - Aço CA60 - ø 5.0 mm | 1.58758 | Dimensionado | 405 | 0 | Viga C-30 - Seção Retangular 14 X 40
V252 | TERREO | 14 | 40 | 0 | 0.18 % | Concreto - C-30 - Abatimento 12 cm | 0.098866 | Forma - Estrutura - Concreto | 1.65954 | Armadura - Aço CA50 - ø 8.0 mm | 3.42552 | Armadura - Aço CA60 - ø 5.0 mm | 1.27026 | Dimensionado | 405 | 0 | Viga C-30 - Seção Retangular 14 X 40
V252 | TERREO | 14 | 40 | 0 | 0.18 % | Concreto - C-30 - Abatimento 12 cm | 0.098836 | Forma - Estrutura - Concreto | 1.65903 | Armadura - Aço CA50 - ø 8.0 mm | 3.42446 | Armadura - Aço CA60 - ø 5.0 mm | 1.26987 | Dimensionado | 405 | 0 | Viga C-30 - Seção Retangular 14 X 40
V253 | TERREO | 14 | 40 | 0 | 0.18 % | Concreto - C-30 - Abatimento 12 cm | 0.114919 | Forma - Estrutura - Concreto | 1.98669 | Armadura - Aço CA50 - ø 8.0 mm | 1.89574 | Armadura - Aço CA50 - ø 10.0 mm | 3.49181 | Dimensionado | 405 | 0 | Viga C-30 - Seção Retangular 14 X 40 | AltoQi_Eberick-Item_05 - Descrição_05: Armadura - Aço CA60 - ø 5.0 mm; Quantidade_05: 2.25535 kg; Status_05: Dimensionado
V253 | TERREO | 14 | 40 | 0 | 0.18 % | Concreto - C-30 - Abatimento 12 cm | 0.01616 | Forma - Estrutura - Concreto | 0.279369 | Armadura - Aço CA50 - ø 8.0 mm | 0.26658 | Armadura - Aço CA50 - ø 10.0 mm | 0.49102 | Dimensionado | 405 | 0 | Viga C-30 - Seção Retangular 14 X 40 | AltoQi_Eberick-Item_05 - Descrição_05: Armadura - Aço CA60 - ø 5.0 mm; Quantidade_05: 0.317149 kg; Status_05: Dimensionado
V254 | TERREO | 14 | 40 | 0 | 0.18 % | Concreto - C-30 - Abatimento 12 cm | 0.122707 | Forma - Estrutura - Concreto | 2.05973 | Armadura - Aço CA50 - ø 8.0 mm | 4.46669 | Armadura - Aço CA60 - ø 5.0 mm | 1.58758 | Dimensionado | 405 | 0 | Viga C-30 - Seção Retangular 14 X 40
V255 | TERREO | 14 | 40 | 0 | 0.18 % | Concreto - C-30 - Abatimento 12 cm | 0.137772 | Forma - Estrutura - Concreto | 2.31259 | Armadura - Aço CA50 - ø 8.0 mm | 4.73501 | Armadura - Aço CA60 - ø 5.0 mm | 1.74634 | Dimensionado | 405 | 0 | Viga C-30 - Seção Retangular 14 X 40
V256 | TERREO | 14 | 40 | 0 | 0.18 % | Concreto - C-30 - Abatimento 12 cm | 0.119919 | Forma - Estrutura - Concreto | 2.06973 | Armadura - Aço CA50 - ø 8.0 mm | 1.8671 | Armadura - Aço CA50 - ø 10.0 mm | 3.6307 | Dimensionado | 405 | 0 | Viga C-30 - Seção Retangular 14 X 40 | AltoQi_Eberick-Item_05 - Descrição_05: Armadura - Aço CA60 - ø 5.0 mm; Quantidade_05: 2.26386 kg; Status_05: Dimensionado
V256 | TERREO | 14 | 40 | 0 | 0.18 % | Concreto - C-30 - Abatimento 12 cm | 0.018961 | Forma - Estrutura - Concreto | 0.327266 | Armadura - Aço CA50 - ø 8.0 mm | 0.295225 | Armadura - Aço CA50 - ø 10.0 mm | 0.574085 | Dimensionado | 405 | 0 | Viga C-30 - Seção Retangular 14 X 40 | AltoQi_Eberick-Item_05 - Descrição_05: Armadura - Aço CA60 - ø 5.0 mm; Quantidade_05: 0.357961 kg; Status_05: Dimensionado
V257 | TERREO | 14 | 40 | 0 | 0.28 % | Concreto - C-30 - Abatimento 12 cm | 0.336403 | Forma - Estrutura - Concreto | 5.71257 | Armadura - Aço CA50 - ø 10.0 mm | 11.8745 | Armadura - Aço CA60 - ø 5.0 mm | 5.85865 | Dimensionado | 405 | 0 | Viga C-30 - Seção Retangular 14 X 40
V258 | TERREO | 14 | 40 | 0 | 0.18 % | Concreto - C-30 - Abatimento 12 cm | 0.014198 | Forma - Estrutura - Concreto | 0.238322 | Armadura - Aço CA50 - ø 8.0 mm | 0.233694 | Armadura - Aço CA50 - ø 10.0 mm | 0.376457 | Dimensionado | 405 | 0 | Viga C-30 - Seção Retangular 14 X 40 | AltoQi_Eberick-Item_05 - Descrição_05: Armadura - Aço CA60 - ø 5.0 mm; Quantidade_05: 0.230708 kg; Status_05: Dimensionado
V258 | TERREO | 14 | 40 | 0 | 0.18 % | Concreto - C-30 - Abatimento 12 cm | 0.118281 | Forma - Estrutura - Concreto | 1.98543 | Armadura - Aço CA50 - ø 8.0 mm | 1.94688 | Armadura - Aço CA50 - ø 10.0 mm | 3.13621 | Dimensionado | 405 | 0 | Viga C-30 - Seção Retangular 14 X 40 | AltoQi_Eberick-Item_05 - Descrição_05: Armadura - Aço CA60 - ø 5.0 mm; Quantidade_05: 1.922 kg; Status_05: Dimensionado
V258 | TERREO | 14 | 40 | 0 | 0.18 % | Concreto - C-30 - Abatimento 12 cm | 0.19259 | Forma - Estrutura - Concreto | 3.23276 | Armadura - Aço CA50 - ø 8.0 mm | 3.16999 | Armadura - Aço CA50 - ø 10.0 mm | 5.10652 | Dimensionado | 405 | 0 | Viga C-30 - Seção Retangular 14 X 40 | AltoQi_Eberick-Item_05 - Descrição_05: Armadura - Aço CA60 - ø 5.0 mm; Quantidade_05: 3.12948 kg; Status_05: Dimensionado
V259 | TERREO | 14 | 40 | 0 | 0.18 % | Concreto - C-30 - Abatimento 12 cm | 0.28 | Forma - Estrutura - Concreto | 4.7 | Armadura - Aço CA50 - ø 8.0 mm | 8.6335 | Armadura - Aço CA60 - ø 5.0 mm | 3.8102 | Dimensionado | 405 | 0 | Viga C-30 - Seção Retangular 14 X 40
V260 | TERREO | 17 | 40 | 0 | 0.15 % | Concreto - C-30 - Abatimento 12 cm | 0.18326 | Forma - Estrutura - Concreto | 2.61415 | Armadura - Aço CA50 - ø 8.0 mm | 4.9323 | Armadura - Aço CA60 - ø 5.0 mm | 2.18408 | Dimensionado | 405 | 0 | Viga C-30 - Seção Retangular 17 X 40
V261 | TERREO | 14 | 40 | 0 | 0.18 % | Concreto - C-30 - Abatimento 12 cm | 0.27888 | Forma - Estrutura - Concreto | 4.6812 | Armadura - Aço CA50 - ø 8.0 mm | 8.60193 | Armadura - Aço CA60 - ø 5.0 mm | 3.8102 | Dimensionado | 405 | 0 | Viga C-30 - Seção Retangular 14 X 40
V262 | TERREO | 14 | 40 | 0 | 0.18 % | Concreto - C-30 - Abatimento 12 cm | 0.279994 | Forma - Estrutura - Concreto | 4.69991 | Armadura - Aço CA50 - ø 8.0 mm | 8.68085 | Armadura - Aço CA60 - ø 5.0 mm | 3.8102 | Dimensionado | 405 | 0 | Viga C-30 - Seção Retangular 14 X 40
V263 | TERREO | 14 | 40 | 0 | 0.18 % | Concreto - C-30 - Abatimento 12 cm | 0.1414 | Forma - Estrutura - Concreto | 2.3735 | Armadura - Aço CA50 - ø 8.0 mm | 4.89284 | Armadura - Aço CA60 - ø 5.0 mm | 1.9051 | Dimensionado | 405 | 0 | Viga C-30 - Seção Retangular 14 X 40
V264 | TERREO | 14 | 40 | 0 | 0.18 % | Concreto - C-30 - Abatimento 12 cm | 0.27972 | Forma - Estrutura - Concreto | 4.6953 | Armadura - Aço CA50 - ø 8.0 mm | 8.6335 | Armadura - Aço CA60 - ø 5.0 mm | 3.65144 | Dimensionado | 405 | 0 | Viga C-30 - Seção Retangular 14 X 40
V265 | TERREO | 14 | 40 | 0 | 0.18 % | Concreto - C-30 - Abatimento 12 cm | 0.237802 | Forma - Estrutura - Concreto | 3.99168 | Armadura - Aço CA50 - ø 8.0 mm | 4.12588 | Armadura - Aço CA50 - ø 10.0 mm | 6.70923 | Dimensionado | 405 | 0 | Viga C-30 - Seção Retangular 14 X 40 | AltoQi_Eberick-Item_05 - Descrição_05: Armadura - Aço CA60 - ø 5.0 mm; Quantidade_05: 4.12885 kg; Status_05: Dimensionado
V265 | TERREO | 14 | 40 | 0 | 0.18 % | Concreto - C-30 - Abatimento 12 cm | 0.017724 | Forma - Estrutura - Concreto | 0.297516 | Armadura - Aço CA50 - ø 8.0 mm | 0.307519 | Armadura - Aço CA50 - ø 10.0 mm | 0.500067 | Dimensionado | 405 | 0 | Viga C-30 - Seção Retangular 14 X 40 | AltoQi_Eberick-Item_05 - Descrição_05: Armadura - Aço CA60 - ø 5.0 mm; Quantidade_05: 0.30774 kg; Status_05: Dimensionado
V265 | TERREO | 14 | 40 | 0 | 0.18 % | Concreto - C-30 - Abatimento 12 cm | 0.046039 | Forma - Estrutura - Concreto | 0.772799 | Armadura - Aço CA50 - ø 8.0 mm | 0.798781 | Armadura - Aço CA50 - ø 10.0 mm | 1.29892 | Dimensionado | 405 | 0 | Viga C-30 - Seção Retangular 14 X 40 | AltoQi_Eberick-Item_05 - Descrição_05: Armadura - Aço CA60 - ø 5.0 mm; Quantidade_05: 0.799355 kg; Status_05: Dimensionado
V266 | TERREO | 14 | 40 | 0 | 0.18 % | Concreto - C-30 - Abatimento 12 cm | 0.0476 | Forma - Estrutura - Concreto | 0.799 | Armadura - Aço CA50 - ø 8.0 mm | 2.14654 | Armadura - Aço CA60 - ø 5.0 mm | 0.635034 | Dimensionado | 405 | 0 | Viga C-30 - Seção Retangular 14 X 40
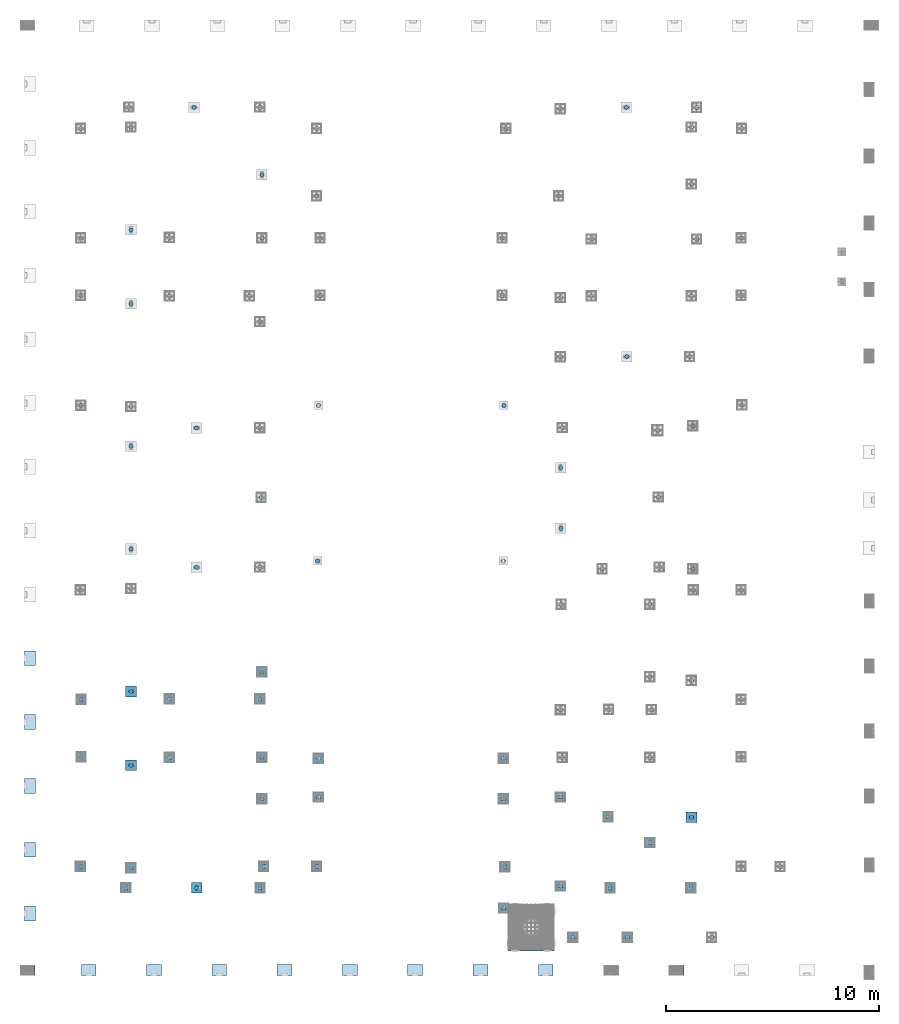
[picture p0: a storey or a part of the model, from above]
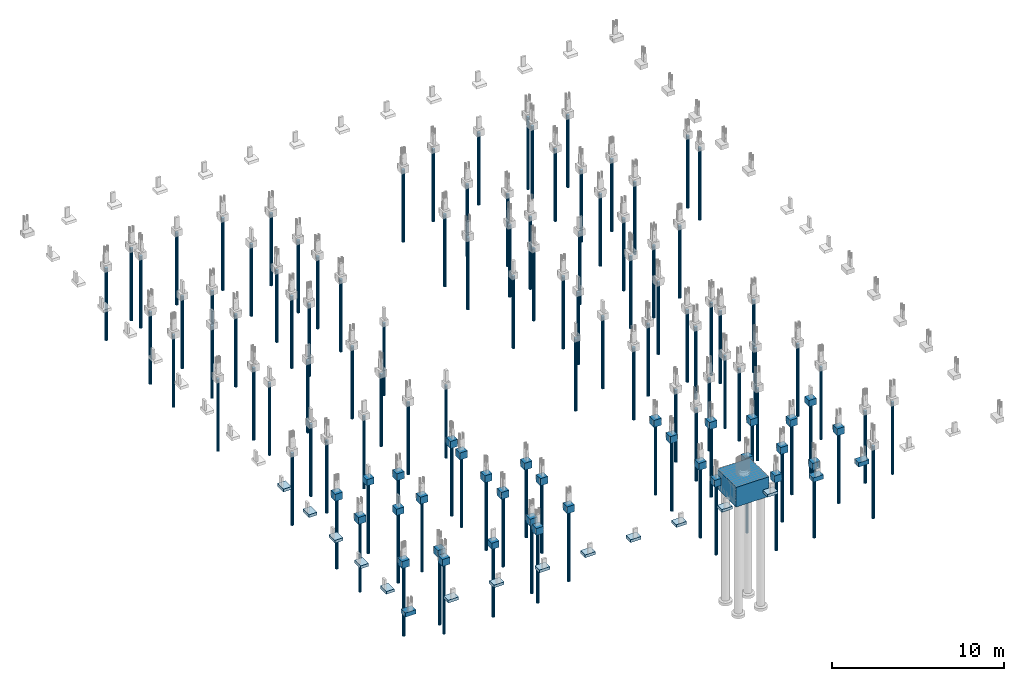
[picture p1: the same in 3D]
Properties of the parts of a building model (IFC4), part 3 of 9

# IfcBeam (614)
Name | In | Seção_bw (cm) | Seção_h (cm) | Elevação (cm) | Taxa de armadura | Descrição_01 | AltoQi_Eberick-Item_01, Quantidade_01 (m3) | Descrição_02 | AltoQi_Eberick-Item_02, Quantidade_02 (m2) | Descrição_03 | Quantidade_03 (kg) | Descrição_04 | AltoQi_Eberick-Item_04, Quantidade_04 (kg) | Status_04 | Cargas de parede (G2) | Adicional (G2) | Reference
V267 | TERREO | 14 | 40 | 0 | 0.18 % | Concreto - C-30 - Abatimento 12 cm | 0.146154 | Forma - Estrutura - Concreto | 2.45331 | Armadura - Aço CA50 - ø 8.0 mm | 2.24913 | Armadura - Aço CA60 - ø 5.0 mm | 2.78367 | Dimensionado | 405 | 0 | Viga C-30 - Seção Retangular 14 X 40
V268 | TERREO | 14 | 40 | 0 | 0.18 % | Concreto - C-30 - Abatimento 12 cm | 0.0322 | Forma - Estrutura - Concreto | 0.5405 | Armadura - Aço CA50 - ø 8.0 mm | 1.56255 | Armadura - Aço CA60 - ø 5.0 mm | 0.476275 | Dimensionado | 405 | 0 | Viga C-30 - Seção Retangular 14 X 40
V269 | TERREO | 14 | 30 | 0 | 0.24 % | Concreto - C-30 - Abatimento 12 cm | 0.02352 | Forma - Estrutura - Concreto | 0.4144 | Armadura - Aço CA50 - ø 8.0 mm | 1.12851 | Armadura - Aço CA60 - ø 5.0 mm | 0.255863 | Dimensionado | 405 | 0 | Viga C-30 - Seção Retangular 14 X 30
V270 | TERREO | 14 | 40 | 0 | 0.18 % | Concreto - C-30 - Abatimento 12 cm | 0.243539 | Forma - Estrutura - Concreto | 4.08797 | Armadura - Aço CA50 - ø 8.0 mm | 3.66003 | Armadura - Aço CA50 - ø 10.0 mm | 7.00505 | Dimensionado | 405 | 0 | Viga C-30 - Seção Retangular 14 X 40 | AltoQi_Eberick-Item_05 - Descrição_05: Armadura - Aço CA60 - ø 5.0 mm; Quantidade_05: 3.9762 kg; Status_05: Dimensionado
V270 | TERREO | 14 | 40 | 0 | 0.18 % | Concreto - C-30 - Abatimento 12 cm | 0.018091 | Forma - Estrutura - Concreto | 0.303672 | Armadura - Aço CA50 - ø 8.0 mm | 0.271883 | Armadura - Aço CA50 - ø 10.0 mm | 0.520366 | Dimensionado | 405 | 0 | Viga C-30 - Seção Retangular 14 X 40 | AltoQi_Eberick-Item_05 - Descrição_05: Armadura - Aço CA60 - ø 5.0 mm; Quantidade_05: 0.295369 kg; Status_05: Dimensionado
V270 | TERREO | 14 | 40 | 0 | 0.18 % | Concreto - C-30 - Abatimento 12 cm | 0.242785 | Forma - Estrutura - Concreto | 4.07531 | Armadura - Aço CA50 - ø 8.0 mm | 3.6487 | Armadura - Aço CA50 - ø 10.0 mm | 6.98337 | Dimensionado | 405 | 0 | Viga C-30 - Seção Retangular 14 X 40 | AltoQi_Eberick-Item_05 - Descrição_05: Armadura - Aço CA60 - ø 5.0 mm; Quantidade_05: 3.96389 kg; Status_05: Dimensionado
V270 | TERREO | 14 | 40 | 0 | 0.18 % | Concreto - C-30 - Abatimento 12 cm | 0.093999 | Forma - Estrutura - Concreto | 1.57784 | Armadura - Aço CA50 - ø 8.0 mm | 1.41267 | Armadura - Aço CA50 - ø 10.0 mm | 2.70376 | Dimensionado | 405 | 0 | Viga C-30 - Seção Retangular 14 X 40 | AltoQi_Eberick-Item_05 - Descrição_05: Armadura - Aço CA60 - ø 5.0 mm; Quantidade_05: 1.53471 kg; Status_05: Dimensionado
V270 | TERREO | 14 | 40 | 0 | 0.18 % | Concreto - C-30 - Abatimento 12 cm | 0.24279 | Forma - Estrutura - Concreto | 4.0754 | Armadura - Aço CA50 - ø 8.0 mm | 3.64877 | Armadura - Aço CA50 - ø 10.0 mm | 6.98351 | Dimensionado | 405 | 0 | Viga C-30 - Seção Retangular 14 X 40 | AltoQi_Eberick-Item_05 - Descrição_05: Armadura - Aço CA60 - ø 5.0 mm; Quantidade_05: 3.96398 kg; Status_05: Dimensionado
V270 | TERREO | 14 | 40 | 0 | 0.28 % | Concreto - C-30 - Abatimento 12 cm | 0.09325 | Forma - Estrutura - Concreto | 1.56527 | Armadura - Aço CA50 - ø 8.0 mm | 1.40142 | Armadura - Aço CA50 - ø 10.0 mm | 2.68222 | Dimensionado | 405 | 0 | Viga C-30 - Seção Retangular 14 X 40 | AltoQi_Eberick-Item_05 - Descrição_05: Armadura - Aço CA60 - ø 5.0 mm; Quantidade_05: 1.52248 kg; Status_05: Dimensionado
V270 | TERREO | 14 | 40 | 0 | 0.18 % | Concreto - C-30 - Abatimento 12 cm | 0.018101 | Forma - Estrutura - Concreto | 0.303841 | Armadura - Aço CA50 - ø 8.0 mm | 0.272034 | Armadura - Aço CA50 - ø 10.0 mm | 0.520655 | Dimensionado | 405 | 0 | Viga C-30 - Seção Retangular 14 X 40 | AltoQi_Eberick-Item_05 - Descrição_05: Armadura - Aço CA60 - ø 5.0 mm; Quantidade_05: 0.295534 kg; Status_05: Dimensionado
V271 | TERREO | 14 | 40 | 0 | 0.18 % | Concreto - C-30 - Abatimento 12 cm | 0.146167 | Forma - Estrutura - Concreto | 2.45352 | Armadura - Aço CA50 - ø 8.0 mm | 4.92441 | Armadura - Aço CA60 - ø 5.0 mm | 1.9051 | Dimensionado | 405 | 0 | Viga C-30 - Seção Retangular 14 X 40
V272 | TERREO | 14 | 40 | 0 | 0.18 % | Concreto - C-30 - Abatimento 12 cm | 0.046215 | Forma - Estrutura - Concreto | 0.775744 | Armadura - Aço CA50 - ø 8.0 mm | 0.801822 | Armadura - Aço CA50 - ø 10.0 mm | 1.30387 | Dimensionado | 405 | 0 | Viga C-30 - Seção Retangular 14 X 40 | AltoQi_Eberick-Item_05 - Descrição_05: Armadura - Aço CA60 - ø 5.0 mm; Quantidade_05: 0.802398 kg; Status_05: Dimensionado
V272 | TERREO | 14 | 40 | 0 | 0.18 % | Concreto - C-30 - Abatimento 12 cm | 0.237636 | Forma - Estrutura - Concreto | 3.98888 | Armadura - Aço CA50 - ø 8.0 mm | 4.12298 | Armadura - Aço CA50 - ø 10.0 mm | 6.7045 | Dimensionado | 405 | 0 | Viga C-30 - Seção Retangular 14 X 40 | AltoQi_Eberick-Item_05 - Descrição_05: Armadura - Aço CA60 - ø 5.0 mm; Quantidade_05: 4.12594 kg; Status_05: Dimensionado
V272 | TERREO | 14 | 40 | 0 | 0.18 % | Concreto - C-30 - Abatimento 12 cm | 0.017717 | Forma - Estrutura - Concreto | 0.297391 | Armadura - Aço CA50 - ø 8.0 mm | 0.307388 | Armadura - Aço CA50 - ø 10.0 mm | 0.499853 | Dimensionado | 405 | 0 | Viga C-30 - Seção Retangular 14 X 40 | AltoQi_Eberick-Item_05 - Descrição_05: Armadura - Aço CA60 - ø 5.0 mm; Quantidade_05: 0.307609 kg; Status_05: Dimensionado
V273 | TERREO | 14 | 40 | 0 | 0.18 % | Concreto - C-30 - Abatimento 12 cm | 0.0476 | Forma - Estrutura - Concreto | 0.799 | Armadura - Aço CA50 - ø 8.0 mm | 2.14654 | Armadura - Aço CA60 - ø 5.0 mm | 0.635034 | Dimensionado | 405 | 0 | Viga C-30 - Seção Retangular 14 X 40
V274 | TERREO | 14 | 40 | 0 | 0.18 % | Concreto - C-30 - Abatimento 12 cm | 0.0588 | Forma - Estrutura - Concreto | 0.987 | Armadura - Aço CA50 - ø 8.0 mm | 2.52534 | Armadura - Aço CA60 - ø 5.0 mm | 0.938678 | Dimensionado | 405 | 0 | Viga C-30 - Seção Retangular 14 X 40
V275 | TERREO | 14 | 40 | 0 | 0.18 % | Concreto - C-30 - Abatimento 12 cm | 0.059914 | Forma - Estrutura - Concreto | 1.00571 | Armadura - Aço CA50 - ø 8.0 mm | 2.44642 | Armadura - Aço CA60 - ø 5.0 mm | 0.793792 | Dimensionado | 405 | 0 | Viga C-30 - Seção Retangular 14 X 40
V276 | TERREO | 14 | 40 | 0 | 0.18 % | Concreto - C-30 - Abatimento 12 cm | 0.09969 | Forma - Estrutura - Concreto | 1.67337 | Armadura - Aço CA50 - ø 8.0 mm | 3.27766 | Armadura - Aço CA60 - ø 5.0 mm | 1.40495 | Dimensionado | 405 | 0 | Viga C-30 - Seção Retangular 14 X 40
V276 | TERREO | 14 | 40 | 0 | 0.18 % | Concreto - C-30 - Abatimento 12 cm | 0.162887 | Forma - Estrutura - Concreto | 2.73418 | Armadura - Aço CA50 - ø 8.0 mm | 5.35548 | Armadura - Aço CA60 - ø 5.0 mm | 2.29559 | Dimensionado | 405 | 0 | Viga C-30 - Seção Retangular 14 X 40
V276 | TERREO | 14 | 40 | 0 | 0.18 % | Concreto - C-30 - Abatimento 12 cm | 0.051857 | Forma - Estrutura - Concreto | 0.870452 | Armadura - Aço CA50 - ø 8.0 mm | 1.70497 | Armadura - Aço CA60 - ø 5.0 mm | 0.730823 | Dimensionado | 405 | 0 | Viga C-30 - Seção Retangular 14 X 40
V277 | TERREO | 14 | 40 | 0 | 0.18 % | Concreto - C-30 - Abatimento 12 cm | 0.144505 | Forma - Estrutura - Concreto | 2.42562 | Armadura - Aço CA50 - ø 8.0 mm | 4.71613 | Armadura - Aço CA60 - ø 5.0 mm | 1.94616 | Dimensionado | 405 | 0 | Viga C-30 - Seção Retangular 14 X 40
V277 | TERREO | 14 | 40 | 0 | 0.18 % | Concreto - C-30 - Abatimento 12 cm | 0.067636 | Forma - Estrutura - Concreto | 1.13532 | Armadura - Aço CA50 - ø 8.0 mm | 2.20741 | Armadura - Aço CA60 - ø 5.0 mm | 0.910909 | Dimensionado | 405 | 0 | Viga C-30 - Seção Retangular 14 X 40
V277 | TERREO | 14 | 40 | 0 | 0.18 % | Concreto - C-30 - Abatimento 12 cm | 0.259379 | Forma - Estrutura - Concreto | 4.35386 | Armadura - Aço CA50 - ø 8.0 mm | 8.46524 | Armadura - Aço CA60 - ø 5.0 mm | 3.49327 | Dimensionado | 405 | 0 | Viga C-30 - Seção Retangular 14 X 40
V278 | TERREO | 14 | 40 | 0 | 0.18 % | Concreto - C-30 - Abatimento 12 cm | 0.217049 | Forma - Estrutura - Concreto | 3.62661 | Armadura - Aço CA50 - ø 8.0 mm | 2.72087 | Armadura - Aço CA50 - ø 12.5 mm | 9.27634 | Dimensionado | 405 | 0 | Viga C-30 - Seção Retangular 14 X 40 | AltoQi_Eberick-Item_05 - Descrição_05: Armadura - Aço CA60 - ø 5.0 mm; Quantidade_05: 3.20261 kg; Status_05: Dimensionado
V278 | TERREO | 14 | 40 | 0 | 0.44 % | Concreto - C-30 - Abatimento 12 cm | 0.362223 | Forma - Estrutura - Concreto | 6.05227 | Armadura - Aço CA50 - ø 8.0 mm | 4.54072 | Armadura - Aço CA50 - ø 12.5 mm | 15.4808 | Dimensionado | 405 | 0 | Viga C-30 - Seção Retangular 14 X 40 | AltoQi_Eberick-Item_05 - Descrição_05: Armadura - Aço CA60 - ø 5.0 mm; Quantidade_05: 5.34469 kg; Status_05: Dimensionado
V278 | TERREO | 14 | 40 | 0 | 0.18 % | Concreto - C-30 - Abatimento 12 cm | 0.275008 | Forma - Estrutura - Concreto | 4.59502 | Armadura - Aço CA50 - ø 8.0 mm | 3.44742 | Armadura - Aço CA50 - ø 12.5 mm | 11.7534 | Dimensionado | 405 | 0 | Viga C-30 - Seção Retangular 14 X 40 | AltoQi_Eberick-Item_05 - Descrição_05: Armadura - Aço CA60 - ø 5.0 mm; Quantidade_05: 4.05781 kg; Status_05: Dimensionado
V279 | TERREO | 14 | 30 | 0 | 0.24 % | Concreto - C-30 - Abatimento 12 cm | 0.02667 | Forma - Estrutura - Concreto | 0.4699 | Armadura - Aço CA50 - ø 8.0 mm | 1.75985 | Armadura - Aço CA60 - ø 5.0 mm | 0.383795 | Dimensionado | 405 | 0 | Viga C-30 - Seção Retangular 14 X 30
V280 | TERREO | 14 | 40 | 0 | 0.18 % | Concreto - C-30 - Abatimento 12 cm | 0.162723 | Forma - Estrutura - Concreto | 2.73143 | Armadura - Aço CA50 - ø 8.0 mm | 5.31945 | Armadura - Aço CA60 - ø 5.0 mm | 2.21235 | Dimensionado | 405 | 0 | Viga C-30 - Seção Retangular 14 X 40
V280 | TERREO | 14 | 40 | 0 | 0.18 % | Concreto - C-30 - Abatimento 12 cm | 0.152557 | Forma - Estrutura - Concreto | 2.56077 | Armadura - Aço CA50 - ø 8.0 mm | 4.98709 | Armadura - Aço CA60 - ø 5.0 mm | 2.07412 | Dimensionado | 405 | 0 | Viga C-30 - Seção Retangular 14 X 40
V281 | TERREO | 14 | 40 | 0 | 0.18 % | Concreto - C-30 - Abatimento 12 cm | 0.17029 | Forma - Estrutura - Concreto | 2.85845 | Armadura - Aço CA50 - ø 8.0 mm | 5.65044 | Armadura - Aço CA60 - ø 5.0 mm | 2.22262 | Dimensionado | 405 | 0 | Viga C-30 - Seção Retangular 14 X 40
V282 | TERREO | 14 | 60 | 20 | 0.19 % | Concreto - C-30 - Abatimento 12 cm | 0.128024 | Forma - Estrutura - Concreto | 2.04229 | Armadura - Aço CA50 - ø 10.0 mm | 6.19004 | Armadura - Aço CA60 - ø 5.0 mm | 1.7633 | Dimensionado | 0 | 500 | Viga C-30 - Seção Retangular 14 X 60
V283 | TERREO | 14 | 60 | 20 | 0.29 % | Concreto - C-30 - Abatimento 12 cm | 0.759352 | Forma - Estrutura - Concreto | 12.1135 | Armadura - Aço CA50 - ø 8.0 mm | 4.53772 | Armadura - Aço CA50 - ø 10.0 mm | 2.73743 | Dimensionado | 0 | 500 | Viga C-30 - Seção Retangular 14 X 60 | AltoQi_Eberick-Item_05 - Descrição_05: Armadura - Aço CA50 - ø 12.5 mm; Quantidade_05: 27.3781 kg; Status_05: Dimensionado; AltoQi_Eberick-Item_06 - Descrição_06: Armadura - Aço CA60 - ø 5.0 mm; Quantidade_06: 8.79491 kg; Status_06: Dimensionado
V284 | TERREO | 14 | 60 | 20 | 0.19 % | Concreto - C-30 - Abatimento 12 cm | 0.60492 | Forma - Estrutura - Concreto | 9.64991 | Armadura - Aço CA50 - ø 8.0 mm | 1.99762 | Armadura - Aço CA50 - ø 10.0 mm | 11.0545 | Dimensionado | 0 | 500 | Viga C-30 - Seção Retangular 14 X 60 | AltoQi_Eberick-Item_05 - Descrição_05: Armadura - Aço CA50 - ø 12.5 mm; Quantidade_05: 10.3975 kg; Status_05: Dimensionado; AltoQi_Eberick-Item_06 - Descrição_06: Armadura - Aço CA60 - ø 5.0 mm; Quantidade_06: 6.83232 kg; Status_06: Dimensionado
V284 | TERREO | 14 | 60 | 20 | 0.19 % | Concreto - C-30 - Abatimento 12 cm | 0.427457 | Forma - Estrutura - Concreto | 6.81895 | Armadura - Aço CA50 - ø 8.0 mm | 1.41159 | Armadura - Aço CA50 - ø 10.0 mm | 7.81151 | Dimensionado | 0 | 500 | Viga C-30 - Seção Retangular 14 X 60 | AltoQi_Eberick-Item_05 - Descrição_05: Armadura - Aço CA50 - ø 12.5 mm; Quantidade_05: 7.34722 kg; Status_05: Dimensionado; AltoQi_Eberick-Item_06 - Descrição_06: Armadura - Aço CA60 - ø 5.0 mm; Quantidade_06: 4.82795 kg; Status_06: Dimensionado
V285 | TERREO | 17 | 40 | 0 | 0.15 % | Concreto - C-30 - Abatimento 12 cm | 0.172051 | Forma - Estrutura - Concreto | 2.45426 | Armadura - Aço CA50 - ø 8.0 mm | 4.86128 | Armadura - Aço CA60 - ø 5.0 mm | 2.18408 | Dimensionado | 405 | 0 | Viga C-30 - Seção Retangular 17 X 40
V286 | TERREO | 14 | 40 | 0 | 0.18 % | Concreto - C-30 - Abatimento 12 cm | 0.107477 | Forma - Estrutura - Concreto | 1.80407 | Armadura - Aço CA50 - ø 8.0 mm | 3.31131 | Armadura - Aço CA60 - ø 5.0 mm | 1.46405 | Dimensionado | 405 | 0 | Viga C-30 - Seção Retangular 14 X 40
V286 | TERREO | 14 | 40 | 0 | 0.18 % | Concreto - C-30 - Abatimento 12 cm | 0.172232 | Forma - Estrutura - Concreto | 2.89104 | Armadura - Aço CA50 - ø 8.0 mm | 5.3064 | Armadura - Aço CA60 - ø 5.0 mm | 2.34615 | Dimensionado | 405 | 0 | Viga C-30 - Seção Retangular 14 X 40
V287 | TERREO | 14 | 40 | 0 | 0.18 % | Concreto - C-30 - Abatimento 12 cm | 0.16632 | Forma - Estrutura - Concreto | 2.7918 | Armadura - Aço CA50 - ø 8.0 mm | 5.53996 | Armadura - Aço CA60 - ø 5.0 mm | 2.22262 | Dimensionado | 405 | 0 | Viga C-30 - Seção Retangular 14 X 40
V288 | TERREO | 14 | 60 | 20 | 0.19 % | Concreto - C-30 - Abatimento 12 cm | 0.135232 | Forma - Estrutura - Concreto | 2.15727 | Armadura - Aço CA50 - ø 10.0 mm | 6.41199 | Armadura - Aço CA60 - ø 5.0 mm | 1.7633 | Dimensionado | 0 | 500 | Viga C-30 - Seção Retangular 14 X 60
V289 | TERREO | 14 | 60 | 20 | 0.29 % | Concreto - C-30 - Abatimento 12 cm | 0.759352 | Forma - Estrutura - Concreto | 12.1135 | Armadura - Aço CA50 - ø 8.0 mm | 4.69555 | Armadura - Aço CA50 - ø 10.0 mm | 2.73743 | Dimensionado | 0 | 500 | Viga C-30 - Seção Retangular 14 X 60 | AltoQi_Eberick-Item_05 - Descrição_05: Armadura - Aço CA50 - ø 12.5 mm; Quantidade_05: 26.9928 kg; Status_05: Dimensionado; AltoQi_Eberick-Item_06 - Descrição_06: Armadura - Aço CA60 - ø 5.0 mm; Quantidade_06: 9.01532 kg; Status_06: Dimensionado
V290 | TERREO | 14 | 60 | 20 | 0.19 % | Concreto - C-30 - Abatimento 12 cm | 0.595075 | Forma - Estrutura - Concreto | 9.49286 | Armadura - Aço CA50 - ø 8.0 mm | 1.99762 | Armadura - Aço CA50 - ø 10.0 mm | 10.9606 | Dimensionado | 0 | 500 | Viga C-30 - Seção Retangular 14 X 60 | AltoQi_Eberick-Item_05 - Descrição_05: Armadura - Aço CA50 - ø 12.5 mm; Quantidade_05: 10.3975 kg; Status_05: Dimensionado; AltoQi_Eberick-Item_06 - Descrição_06: Armadura - Aço CA60 - ø 5.0 mm; Quantidade_06: 6.70315 kg; Status_06: Dimensionado
V290 | TERREO | 14 | 60 | 20 | 0.19 % | Concreto - C-30 - Abatimento 12 cm | 0.420502 | Forma - Estrutura - Concreto | 6.70801 | Armadura - Aço CA50 - ø 8.0 mm | 1.41159 | Armadura - Aço CA50 - ø 10.0 mm | 7.74516 | Dimensionado | 0 | 500 | Viga C-30 - Seção Retangular 14 X 60 | AltoQi_Eberick-Item_05 - Descrição_05: Armadura - Aço CA50 - ø 12.5 mm; Quantidade_05: 7.34725 kg; Status_05: Dimensionado; AltoQi_Eberick-Item_06 - Descrição_06: Armadura - Aço CA60 - ø 5.0 mm; Quantidade_06: 4.7367 kg; Status_06: Dimensionado
V291 | TERREO | 14 | 40 | 0 | 0.18 % | Concreto - C-30 - Abatimento 12 cm | 0.14168 | Forma - Estrutura - Concreto | 2.3782 | Armadura - Aço CA50 - ø 8.0 mm | 4.78236 | Armadura - Aço CA60 - ø 5.0 mm | 1.9051 | Dimensionado | 405 | 0 | Viga C-30 - Seção Retangular 14 X 40
V292 | TERREO | 14 | 30 | 0 | 0.24 % | Concreto - C-30 - Abatimento 12 cm | 0.076537 | Forma - Estrutura - Concreto | 1.3485 | Armadura - Aço CA50 - ø 8.0 mm | 1.64936 | Armadura - Aço CA60 - ø 5.0 mm | 1.66773 | Dimensionado | 0 | 0 | Viga C-30 - Seção Retangular 14 X 30
V293 | TERREO | 14 | 40 | 0 | 0.18 % | Concreto - C-30 - Abatimento 12 cm | 0.278869 | Forma - Estrutura - Concreto | 4.68101 | Armadura - Aço CA50 - ø 8.0 mm | 8.64928 | Armadura - Aço CA60 - ø 5.0 mm | 3.96896 | Dimensionado | 405 | 0 | Viga C-30 - Seção Retangular 14 X 40
V294 | TERREO | 14 | 40 | 0 | 0.18 % | Concreto - C-30 - Abatimento 12 cm | 0.021465 | Forma - Estrutura - Concreto | 0.360302 | Armadura - Aço CA50 - ø 8.0 mm | 0.852302 | Armadura - Aço CA60 - ø 5.0 mm | 0.158758 | Dimensionado | 0 | 0 | Viga C-30 - Seção Retangular 14 X 40
V295 | TERREO | 14 | 40 | 0 | 0.18 % | Concreto - C-30 - Abatimento 12 cm | 0.027384 | Forma - Estrutura - Concreto | 0.45966 | Armadura - Aço CA50 - ø 8.0 mm | 0.355126 | Armadura - Aço CA60 - ø 5.0 mm | 0.297479 | Dimensionado | 0 | 0 | Viga C-30 - Seção Retangular 14 X 40
V296 | TERREO | 14 | 40 | 0 | 0.18 % | Concreto - C-30 - Abatimento 12 cm | 0.257489 | Forma - Estrutura - Concreto | 4.37137 | Armadura - Aço CA50 - ø 8.0 mm | 8.17663 | Armadura - Aço CA60 - ø 5.0 mm | 3.44545 | Dimensionado | 405 | 0 | Viga C-30 - Seção Retangular 14 X 40
V296 | TERREO | 14 | 40 | 0 | 0.18 % | Concreto - C-30 - Abatimento 12 cm | 0.096669 | Forma - Estrutura - Concreto | 1.64115 | Armadura - Aço CA50 - ø 8.0 mm | 3.06976 | Armadura - Aço CA60 - ø 5.0 mm | 1.29353 | Dimensionado | 405 | 0 | Viga C-30 - Seção Retangular 14 X 40
V296 | TERREO | 14 | 40 | 0 | 0.18 % | Concreto - C-30 - Abatimento 12 cm | 0.217305 | Forma - Estrutura - Concreto | 3.68918 | Armadura - Aço CA50 - ø 8.0 mm | 6.90059 | Armadura - Aço CA60 - ø 5.0 mm | 2.90776 | Dimensionado | 405 | 0 | Viga C-30 - Seção Retangular 14 X 40
V296 | TERREO | 14 | 40 | 0 | 0.18 % | Concreto - C-30 - Abatimento 12 cm | 0.116676 | Forma - Estrutura - Concreto | 1.98081 | Armadura - Aço CA50 - ø 8.0 mm | 3.70509 | Armadura - Aço CA60 - ø 5.0 mm | 1.56124 | Dimensionado | 405 | 0 | Viga C-30 - Seção Retangular 14 X 40
V297 | TERREO | 14 | 40 | 0 | 0.18 % | Concreto - C-30 - Abatimento 12 cm | 0.145546 | Forma - Estrutura - Concreto | 2.46851 | Armadura - Aço CA50 - ø 8.0 mm | 4.59543 | Armadura - Aço CA60 - ø 5.0 mm | 1.93173 | Dimensionado | 405 | 0 | Viga C-30 - Seção Retangular 14 X 40
V297 | TERREO | 14 | 40 | 0 | 0.18 % | Concreto - C-30 - Abatimento 12 cm | 0.098469 | Forma - Estrutura - Concreto | 1.67007 | Armadura - Aço CA50 - ø 8.0 mm | 3.10905 | Armadura - Aço CA60 - ø 5.0 mm | 1.30692 | Dimensionado | 405 | 0 | Viga C-30 - Seção Retangular 14 X 40
V297 | TERREO | 14 | 40 | 0 | 0.18 % | Concreto - C-30 - Abatimento 12 cm | 0.148813 | Forma - Estrutura - Concreto | 2.52392 | Armadura - Aço CA50 - ø 8.0 mm | 4.69859 | Armadura - Aço CA60 - ø 5.0 mm | 1.97509 | Dimensionado | 405 | 0 | Viga C-30 - Seção Retangular 14 X 40
V297 | TERREO | 14 | 40 | 0 | 0.18 % | Concreto - C-30 - Abatimento 12 cm | 0.186937 | Forma - Estrutura - Concreto | 3.17051 | Armadura - Aço CA50 - ø 8.0 mm | 5.9023 | Armadura - Aço CA60 - ø 5.0 mm | 2.48109 | Dimensionado | 405 | 0 | Viga C-30 - Seção Retangular 14 X 40
V297 | TERREO | 14 | 40 | 0 | 0.18 % | Concreto - C-30 - Abatimento 12 cm | 0.173817 | Forma - Estrutura - Concreto | 2.94799 | Armadura - Aço CA50 - ø 8.0 mm | 5.48805 | Armadura - Aço CA60 - ø 5.0 mm | 2.30695 | Dimensionado | 405 | 0 | Viga C-30 - Seção Retangular 14 X 40
V298 | TERREO | 14 | 40 | 0 | 0.18 % | Concreto - C-30 - Abatimento 12 cm | 0.027379 | Forma - Estrutura - Concreto | 0.459582 | Armadura - Aço CA50 - ø 8.0 mm | 0.410367 | Armadura - Aço CA60 - ø 5.0 mm | 0.294397 | Dimensionado | 0 | 0 | Viga C-30 - Seção Retangular 14 X 40
V299 | TERREO | 14 | 40 | 0 | 0.18 % | Concreto - C-30 - Abatimento 12 cm | 0.215499 | Forma - Estrutura - Concreto | 3.56322 | Armadura - Aço CA50 - ø 8.0 mm | 6.87043 | Armadura - Aço CA60 - ø 5.0 mm | 2.90184 | Dimensionado | 405 | 0 | Viga C-30 - Seção Retangular 14 X 40
V299 | TERREO | 14 | 40 | 0 | 0.18 % | Concreto - C-30 - Abatimento 12 cm | 0.102827 | Forma - Estrutura - Concreto | 1.70021 | Armadura - Aço CA50 - ø 8.0 mm | 3.27827 | Armadura - Aço CA60 - ø 5.0 mm | 1.38463 | Dimensionado | 405 | 0 | Viga C-30 - Seção Retangular 14 X 40
V300 | TERREO | 14 | 40 | 0 | 0.18 % | Concreto - C-30 - Abatimento 12 cm | 0.137234 | Forma - Estrutura - Concreto | 2.30356 | Armadura - Aço CA50 - ø 8.0 mm | 4.81393 | Armadura - Aço CA60 - ø 5.0 mm | 1.9051 | Dimensionado | 405 | 0 | Viga C-30 - Seção Retangular 14 X 40
V301 | TERREO | 14 | 40 | 0 | 0.18 % | Concreto - C-30 - Abatimento 12 cm | 0.174759 | Forma - Estrutura - Concreto | 2.99926 | Armadura - Aço CA50 - ø 8.0 mm | 5.87141 | Armadura - Aço CA60 - ø 5.0 mm | 2.38138 | Dimensionado | 405 | 0 | Viga C-30 - Seção Retangular 14 X 40
V302 | TERREO | 14 | 40 | 0 | 0.18 % | Concreto - C-30 - Abatimento 12 cm | 0.088861 | Forma - Estrutura - Concreto | 1.49159 | Armadura - Aço CA50 - ø 8.0 mm | 3.34607 | Armadura - Aço CA60 - ø 5.0 mm | 1.11131 | Dimensionado | 405 | 0 | Viga C-30 - Seção Retangular 14 X 40
V303 | TERREO | 14 | 40 | 0 | 0.18 % | Concreto - C-30 - Abatimento 12 cm | 0.089325 | Forma - Estrutura - Concreto | 1.49938 | Armadura - Aço CA50 - ø 8.0 mm | 2.9125 | Armadura - Aço CA60 - ø 5.0 mm | 1.27549 | Dimensionado | 405 | 0 | Viga C-30 - Seção Retangular 14 X 40
V303 | TERREO | 14 | 40 | 0 | 0.18 % | Concreto - C-30 - Abatimento 12 cm | 0.174544 | Forma - Estrutura - Concreto | 2.92984 | Armadura - Aço CA50 - ø 8.0 mm | 5.69112 | Armadura - Aço CA60 - ø 5.0 mm | 2.49235 | Dimensionado | 405 | 0 | Viga C-30 - Seção Retangular 14 X 40
V303 | TERREO | 14 | 40 | 0 | 0.18 % | Concreto - C-30 - Abatimento 12 cm | 0.078851 | Forma - Estrutura - Concreto | 1.32357 | Armadura - Aço CA50 - ø 8.0 mm | 2.57099 | Armadura - Aço CA60 - ø 5.0 mm | 1.12593 | Dimensionado | 405 | 0 | Viga C-30 - Seção Retangular 14 X 40
V304 | TERREO | 14 | 40 | 0 | 0.18 % | Concreto - C-30 - Abatimento 12 cm | 0.04816 | Forma - Estrutura - Concreto | 0.8084 | Armadura - Aço CA50 - ø 8.0 mm | 2.22545 | Armadura - Aço CA60 - ø 5.0 mm | 0.635034 | Dimensionado | 405 | 0 | Viga C-30 - Seção Retangular 14 X 40
V305 | TERREO | 14 | 40 | 0 | 0.28 % | Concreto - C-30 - Abatimento 12 cm | 0.339121 | Forma - Estrutura - Concreto | 5.75345 | Armadura - Aço CA50 - ø 8.0 mm | 2.82196 | Armadura - Aço CA50 - ø 10.0 mm | 9.85444 | Dimensionado | 405 | 0 | Viga C-30 - Seção Retangular 14 X 40 | AltoQi_Eberick-Item_05 - Descrição_05: Armadura - Aço CA60 - ø 5.0 mm; Quantidade_05: 5.22721 kg; Status_05: Dimensionado
V305 | TERREO | 14 | 40 | 0 | 0.18 % | Concreto - C-30 - Abatimento 12 cm | 0.225646 | Forma - Estrutura - Concreto | 3.81303 | Armadura - Aço CA50 - ø 8.0 mm | 1.87022 | Armadura - Aço CA50 - ø 10.0 mm | 6.5309 | Dimensionado | 405 | 0 | Viga C-30 - Seção Retangular 14 X 40 | AltoQi_Eberick-Item_05 - Descrição_05: Armadura - Aço CA60 - ø 5.0 mm; Quantidade_05: 3.46427 kg; Status_05: Dimensionado
V305 | TERREO | 14 | 40 | 0 | 0.18 % | Concreto - C-30 - Abatimento 12 cm | 0.175603 | Forma - Estrutura - Concreto | 2.96739 | Armadura - Aço CA50 - ø 8.0 mm | 1.45545 | Armadura - Aço CA50 - ø 10.0 mm | 5.0825 | Dimensionado | 405 | 0 | Viga C-30 - Seção Retangular 14 X 40 | AltoQi_Eberick-Item_05 - Descrição_05: Armadura - Aço CA60 - ø 5.0 mm; Quantidade_05: 2.69597 kg; Status_05: Dimensionado
V306 | TERREO | 14 | 40 | 0 | 0.18 % | Concreto - C-30 - Abatimento 12 cm | 0.042 | Forma - Estrutura - Concreto | 0.705 | Armadura - Aço CA50 - ø 8.0 mm | 2.0834 | Armadura - Aço CA60 - ø 5.0 mm | 0.635034 | Dimensionado | 405 | 0 | Viga C-30 - Seção Retangular 14 X 40
V307 | TERREO | 15 | 40 | 95 | 0.17 % | Concreto - C-30 - Abatimento 12 cm | 0.3858 | Forma - Estrutura - Concreto | 6.1085 | Armadura - Aço CA50 - ø 8.0 mm | 11.1588 | Armadura - Aço CA60 - ø 5.0 mm | 4.85523 | Dimensionado | 0 | 0 | Viga C-30 - Seção Retangular 15 X 40
V308 | TERREO | 14 | 40 | 0 | 0.18 % | Concreto - C-30 - Abatimento 12 cm | 0.17186 | Forma - Estrutura - Concreto | 2.88478 | Armadura - Aço CA50 - ø 8.0 mm | 5.46716 | Armadura - Aço CA60 - ø 5.0 mm | 2.45727 | Dimensionado | 405 | 0 | Viga C-30 - Seção Retangular 14 X 40
V308 | TERREO | 14 | 40 | 0 | 0.18 % | Concreto - C-30 - Abatimento 12 cm | 0.15014 | Forma - Estrutura - Concreto | 2.52021 | Armadura - Aço CA50 - ø 8.0 mm | 4.77624 | Armadura - Aço CA60 - ø 5.0 mm | 2.14673 | Dimensionado | 405 | 0 | Viga C-30 - Seção Retangular 14 X 40
V309 | TERREO | 14 | 40 | 0 | 0.18 % | Concreto - C-30 - Abatimento 12 cm | 0.137234 | Forma - Estrutura - Concreto | 2.30356 | Armadura - Aço CA50 - ø 8.0 mm | 4.92441 | Armadura - Aço CA60 - ø 5.0 mm | 1.9051 | Dimensionado | 405 | 0 | Viga C-30 - Seção Retangular 14 X 40
V310 | TERREO | 14 | 40 | 0 | 0.28 % | Concreto - C-30 - Abatimento 12 cm | 0.273044 | Forma - Estrutura - Concreto | 4.58324 | Armadura - Aço CA50 - ø 8.0 mm | 1.82548 | Armadura - Aço CA50 - ø 10.0 mm | 6.66585 | Dimensionado | 405 | 0 | Viga C-30 - Seção Retangular 14 X 40 | AltoQi_Eberick-Item_05 - Descrição_05: Armadura - Aço CA60 - ø 5.0 mm; Quantidade_05: 4.68725 kg; Status_05: Dimensionado
V310 | TERREO | 14 | 40 | 0 | 0.28 % | Concreto - C-30 - Abatimento 12 cm | 0.049202 | Forma - Estrutura - Concreto | 0.82589 | Armadura - Aço CA50 - ø 8.0 mm | 0.328948 | Armadura - Aço CA50 - ø 10.0 mm | 1.20117 | Dimensionado | 405 | 0 | Viga C-30 - Seção Retangular 14 X 40 | AltoQi_Eberick-Item_05 - Descrição_05: Armadura - Aço CA60 - ø 5.0 mm; Quantidade_05: 0.844632 kg; Status_05: Dimensionado
V311 | TERREO | 14 | 40 | 0 | 0.18 % | Concreto - C-30 - Abatimento 12 cm | 0.047606 | Forma - Estrutura - Concreto | 0.799094 | Armadura - Aço CA50 - ø 8.0 mm | 2.20967 | Armadura - Aço CA60 - ø 5.0 mm | 0.77992 | Dimensionado | 405 | 0 | Viga C-30 - Seção Retangular 14 X 40
V312 | TERREO | 17 | 40 | 0 | 0.15 % | Concreto - C-30 - Abatimento 12 cm | 0.339708 | Forma - Estrutura - Concreto | 4.84583 | Armadura - Aço CA50 - ø 8.0 mm | 8.71242 | Armadura - Aço CA60 - ø 5.0 mm | 4.20016 | Dimensionado | 405 | 0 | Viga C-30 - Seção Retangular 17 X 40
V313 | TERREO | 17 | 40 | 0 | 0.15 % | Concreto - C-30 - Abatimento 12 cm | 0.17204 | Forma - Estrutura - Concreto | 2.4541 | Armadura - Aço CA50 - ø 8.0 mm | 4.86128 | Armadura - Aço CA60 - ø 5.0 mm | 2.18408 | Dimensionado | 405 | 0 | Viga C-30 - Seção Retangular 17 X 40
V314 | TERREO | 14 | 40 | 0 | 0.18 % | Concreto - C-30 - Abatimento 12 cm | 0.278841 | Forma - Estrutura - Concreto | 4.68054 | Armadura - Aço CA50 - ø 8.0 mm | 8.64928 | Armadura - Aço CA60 - ø 5.0 mm | 3.65144 | Dimensionado | 405 | 0 | Viga C-30 - Seção Retangular 14 X 40
V315 | TERREO | 14 | 40 | 0 | 0.18 % | Concreto - C-30 - Abatimento 12 cm | 0.27972 | Forma - Estrutura - Concreto | 4.6953 | Armadura - Aço CA50 - ø 8.0 mm | 8.6335 | Armadura - Aço CA60 - ø 5.0 mm | 3.8102 | Dimensionado | 405 | 0 | Viga C-30 - Seção Retangular 14 X 40
V316 | TERREO | 17 | 40 | 0 | 0.15 % | Concreto - C-30 - Abatimento 12 cm | 0.172051 | Forma - Estrutura - Concreto | 2.45426 | Armadura - Aço CA50 - ø 8.0 mm | 4.86128 | Armadura - Aço CA60 - ø 5.0 mm | 2.18408 | Dimensionado | 405 | 0 | Viga C-30 - Seção Retangular 17 X 40
V317 | TERREO | 14 | 40 | 0 | 0.18 % | Concreto - C-30 - Abatimento 12 cm | 0.279714 | Forma - Estrutura - Concreto | 4.69521 | Armadura - Aço CA50 - ø 8.0 mm | 8.61772 | Armadura - Aço CA60 - ø 5.0 mm | 3.8102 | Dimensionado | 405 | 0 | Viga C-30 - Seção Retangular 14 X 40
9 x V318 | TERREO | 14 | 20 | 0 | 0.36 % | Concreto - C-30 - Abatimento 12 cm | 0.080435 | Forma - Estrutura - Concreto | 1.55125 | Armadura - Aço CA50 - ø 8.0 mm | 5.07082 | Armadura - Aço CA60 - ø 5.0 mm | 1.84089 | Dimensionado | 0 | 0 | Viga C-30 - Seção Retangular 14 X 20
V318 | TERREO | 14 | 20 | 0 | 0.36 % | Concreto - C-30 - Abatimento 12 cm | 0.081745 | Forma - Estrutura - Concreto | 1.57651 | Armadura - Aço CA50 - ø 8.0 mm | 5.15341 | Armadura - Aço CA60 - ø 5.0 mm | 1.87087 | Dimensionado | 0 | 0 | Viga C-30 - Seção Retangular 14 X 20
V318 | TERREO | 14 | 20 | 0 | 0.36 % | Concreto - C-30 - Abatimento 12 cm | 0.080171 | Forma - Estrutura - Concreto | 1.54615 | Armadura - Aço CA50 - ø 8.0 mm | 5.05414 | Armadura - Aço CA60 - ø 5.0 mm | 1.83483 | Dimensionado | 0 | 0 | Viga C-30 - Seção Retangular 14 X 20
V318 | TERREO | 14 | 20 | 0 | 0.36 % | Concreto - C-30 - Abatimento 12 cm | 0.0807 | Forma - Estrutura - Concreto | 1.55635 | Armadura - Aço CA50 - ø 8.0 mm | 5.08751 | Armadura - Aço CA60 - ø 5.0 mm | 1.84695 | Dimensionado | 0 | 0 | Viga C-30 - Seção Retangular 14 X 20
V318 | TERREO | 14 | 20 | 0 | 0.36 % | Concreto - C-30 - Abatimento 12 cm | 0.072968 | Forma - Estrutura - Concreto | 1.40724 | Armadura - Aço CA50 - ø 8.0 mm | 4.60008 | Armadura - Aço CA60 - ø 5.0 mm | 1.66999 | Dimensionado | 0 | 0 | Viga C-30 - Seção Retangular 14 X 20
V319 | TERREO | 14 | 20 | -40 | 0.36 % | Concreto - C-30 - Abatimento 12 cm | 0.077114 | Forma - Estrutura - Concreto | 1.48721 | Armadura - Aço CA50 - ø 8.0 mm | 5.08273 | Armadura - Aço CA60 - ø 5.0 mm | 1.83095 | Dimensionado | 0 | 0 | Viga C-30 - Seção Retangular 14 X 20
V319 | TERREO | 14 | 20 | -40 | 0.36 % | Concreto - C-30 - Abatimento 12 cm | 0.078297 | Forma - Estrutura - Concreto | 1.51001 | Armadura - Aço CA50 - ø 8.0 mm | 5.16067 | Armadura - Aço CA60 - ø 5.0 mm | 1.85903 | Dimensionado | 0 | 0 | Viga C-30 - Seção Retangular 14 X 20
V320 | TERREO | 14 | 20 | -40 | 0.36 % | Concreto - C-30 - Abatimento 12 cm | 0.079638 | Forma - Estrutura - Concreto | 1.53588 | Armadura - Aço CA50 - ø 8.0 mm | 5.08363 | Armadura - Aço CA60 - ø 5.0 mm | 2.01631 | Dimensionado | 0 | 0 | Viga C-30 - Seção Retangular 14 X 20
V320 | TERREO | 14 | 20 | -40 | 0.36 % | Concreto - C-30 - Abatimento 12 cm | 0.085282 | Forma - Estrutura - Concreto | 1.64472 | Armadura - Aço CA50 - ø 8.0 mm | 5.44387 | Armadura - Aço CA60 - ø 5.0 mm | 2.15919 | Dimensionado | 0 | 0 | Viga C-30 - Seção Retangular 14 X 20
V321 | TERREO | 14 | 20 | -40 | 0.36 % | Concreto - C-30 - Abatimento 12 cm | 0.084064 | Forma - Estrutura - Concreto | 1.62123 | Armadura - Aço CA50 - ø 8.0 mm | 5.52139 | Armadura - Aço CA60 - ø 5.0 mm | 2.09436 | Dimensionado | 0 | 0 | Viga C-30 - Seção Retangular 14 X 20
V321 | TERREO | 14 | 20 | -40 | 0.36 % | Concreto - C-30 - Abatimento 12 cm | 0.075738 | Forma - Estrutura - Concreto | 1.46066 | Armadura - Aço CA50 - ø 8.0 mm | 4.97454 | Armadura - Aço CA60 - ø 5.0 mm | 1.88693 | Dimensionado | 0 | 0 | Viga C-30 - Seção Retangular 14 X 20
V322 | TERREO | 20 | 20 | 0 | 0.25 % | Concreto - C-30 - Abatimento 12 cm | 0.098018 | Forma - Estrutura - Concreto | 0.882158 | Armadura - Aço CA50 - ø 8.0 mm | 4.22971 | Armadura - Aço CA60 - ø 5.0 mm | 2.31324 | Dimensionado | 0 | 0 | Viga C-30 - Seção Retangular 20 X 20
V322 | TERREO | 20 | 20 | 0 | 0.25 % | Concreto - C-30 - Abatimento 12 cm | 0.151794 | Forma - Estrutura - Concreto | 1.36615 | Armadura - Aço CA50 - ø 8.0 mm | 6.55033 | Armadura - Aço CA60 - ø 5.0 mm | 3.5824 | Dimensionado | 0 | 0 | Viga C-30 - Seção Retangular 20 X 20
10 x V323 | TERREO | 14 | 20 | 0 | 0.36 % | Concreto - C-30 - Abatimento 12 cm | 0.077698 | Forma - Estrutura - Concreto | 1.43971 | Armadura - Aço CA50 - ø 8.0 mm | 5.03306 | Armadura - Aço CA60 - ø 5.0 mm | 1.85213 | Dimensionado | 0 | 0 | Viga C-30 - Seção Retangular 14 X 20
V323 | TERREO | 14 | 20 | 0 | 0.36 % | Concreto - C-30 - Abatimento 12 cm | 0.06884 | Forma - Estrutura - Concreto | 1.43971 | Armadura - Aço CA50 - ø 8.0 mm | 5.03306 | Armadura - Aço CA60 - ø 5.0 mm | 1.85213 | Dimensionado | 0 | 0 | Viga C-30 - Seção Retangular 14 X 20
V323 | TERREO | 14 | 20 | 0 | 0.36 % | Concreto - C-30 - Abatimento 12 cm | 0.07289 | Forma - Estrutura - Concreto | 1.35061 | Armadura - Aço CA50 - ø 8.0 mm | 4.72157 | Armadura - Aço CA60 - ø 5.0 mm | 1.73751 | Dimensionado | 0 | 0 | Viga C-30 - Seção Retangular 14 X 20
V323 | TERREO | 14 | 20 | 0 | 0.36 % | Concreto - C-30 - Abatimento 12 cm | 0.07861 | Forma - Estrutura - Concreto | 1.45661 | Armadura - Aço CA50 - ø 8.0 mm | 5.09213 | Armadura - Aço CA60 - ø 5.0 mm | 1.87387 | Dimensionado | 0 | 0 | Viga C-30 - Seção Retangular 14 X 20
13 x V324 | TERREO | 14 | 20 | 0 | 0.36 % | Concreto - C-30 - Abatimento 12 cm | 0.075858 | Forma - Estrutura - Concreto | 1.46297 | Armadura - Aço CA50 - ø 8.0 mm | 4.89597 | Armadura - Aço CA60 - ø 5.0 mm | 1.7623 | Dimensionado | 0 | 0 | Viga C-30 - Seção Retangular 14 X 20
V324 | TERREO | 14 | 20 | 0 | 0.36 % | Concreto - C-30 - Abatimento 12 cm | 0.074368 | Forma - Estrutura - Concreto | 1.43424 | Armadura - Aço CA50 - ø 8.0 mm | 4.79982 | Armadura - Aço CA60 - ø 5.0 mm | 1.72769 | Dimensionado | 0 | 0 | Viga C-30 - Seção Retangular 14 X 20
V324 | TERREO | 14 | 20 | 0 | 0.36 % | Concreto - C-30 - Abatimento 12 cm | 0.07222 | Forma - Estrutura - Concreto | 1.39281 | Armadura - Aço CA50 - ø 8.0 mm | 4.66116 | Armadura - Aço CA60 - ø 5.0 mm | 1.67778 | Dimensionado | 0 | 0 | Viga C-30 - Seção Retangular 14 X 20
V325 | TERREO | 20 | 20 | 0 | 0.25 % | Concreto - C-30 - Abatimento 12 cm | 0.0662 | Forma - Estrutura - Concreto | 0.5958 | Armadura - Aço CA50 - ø 8.0 mm | 3.25137 | Armadura - Aço CA60 - ø 5.0 mm | 1.50281 | Dimensionado | 0 | 0 | Viga C-30 - Seção Retangular 20 X 20
V326 | TERREO | 14 | 20 | 0 | 0.36 % | Concreto - C-30 - Abatimento 12 cm | 0.04242 | Forma - Estrutura - Concreto | 0.4545 | Armadura - Aço CA50 - ø 8.0 mm | 3.21191 | Armadura - Aço CA60 - ø 5.0 mm | 1.06815 | Dimensionado | 0 | 0 | Viga C-30 - Seção Retangular 14 X 20
V327 | TERREO | 14 | 20 | 0 | 0.36 % | Concreto - C-30 - Abatimento 12 cm | 0.04438 | Forma - Estrutura - Concreto | 0.6657 | Armadura - Aço CA50 - ø 8.0 mm | 3.21191 | Armadura - Aço CA60 - ø 5.0 mm | 1.06815 | Dimensionado | 0 | 0 | Viga C-30 - Seção Retangular 14 X 20
V328 | TERREO | 14 | 20 | 0 | 0.36 % | Concreto - C-30 - Abatimento 12 cm | 0.1162 | Forma - Estrutura - Concreto | 2.241 | Armadura - Aço CA50 - ø 8.0 mm | 7.32348 | Armadura - Aço CA60 - ø 5.0 mm | 2.71893 | Dimensionado | 0 | 0 | Viga C-30 - Seção Retangular 14 X 20
V329 | TERREO | 14 | 20 | 0 | 0.36 % | Concreto - C-30 - Abatimento 12 cm | 0.07756 | Forma - Estrutura - Concreto | 1.4958 | Armadura - Aço CA50 - ø 8.0 mm | 5.38213 | Armadura - Aço CA60 - ø 5.0 mm | 2.23341 | Dimensionado | 0 | 0 | Viga C-30 - Seção Retangular 14 X 20
V330 | TERREO | 14 | 20 | 0 | 0.36 % | Concreto - C-30 - Abatimento 12 cm | 0.082886 | Forma - Estrutura - Concreto | 1.59851 | Armadura - Aço CA50 - ø 8.0 mm | 5.37423 | Armadura - Aço CA60 - ø 5.0 mm | 1.94209 | Dimensionado | 0 | 0 | Viga C-30 - Seção Retangular 14 X 20
V331 | TERREO | 14 | 20 | 0 | 0.56 % | Concreto - C-30 - Abatimento 12 cm | 0.062693 | Forma - Estrutura - Concreto | 1.20908 | Armadura - Aço CA50 - ø 8.0 mm | 4.07657 | Armadura - Aço CA50 - ø 10.0 mm | 0.600463 | Dimensionado | 0 | 0 | Viga C-30 - Seção Retangular 14 X 20 | AltoQi_Eberick-Item_05 - Descrição_05: Armadura - Aço CA60 - ø 5.0 mm; Quantidade_05: 2.93111 kg; Status_05: Dimensionado
3 x V331 | TERREO | 14 | 20 | 0 | 0.36 % | Concreto - C-30 - Abatimento 12 cm | 0.077199 | Forma - Estrutura - Concreto | 1.48883 | Armadura - Aço CA50 - ø 8.0 mm | 5.0198 | Armadura - Aço CA50 - ø 10.0 mm | 0.739397 | Dimensionado | 0 | 0 | Viga C-30 - Seção Retangular 14 X 20 | AltoQi_Eberick-Item_05 - Descrição_05: Armadura - Aço CA60 - ø 5.0 mm; Quantidade_05: 3.60931 kg; Status_05: Dimensionado
V331 | TERREO | 14 | 20 | 0 | 0.36 % | Concreto - C-30 - Abatimento 12 cm | 0.081639 | Forma - Estrutura - Concreto | 1.57447 | Armadura - Aço CA50 - ø 8.0 mm | 5.30852 | Armadura - Aço CA50 - ø 10.0 mm | 0.781925 | Dimensionado | 0 | 0 | Viga C-30 - Seção Retangular 14 X 20 | AltoQi_Eberick-Item_05 - Descrição_05: Armadura - Aço CA60 - ø 5.0 mm; Quantidade_05: 3.8169 kg; Status_05: Dimensionado
V332 | TERREO | 14 | 20 | 0 | 0.36 % | Concreto - C-30 - Abatimento 12 cm | 0.081987 | Forma - Estrutura - Concreto | 1.58118 | Armadura - Aço CA50 - ø 8.0 mm | 5.21681 | Armadura - Aço CA60 - ø 5.0 mm | 3.45114 | Dimensionado | 0 | 0 | Viga C-30 - Seção Retangular 14 X 20
4 x V332 | TERREO | 14 | 20 | 0 | 0.36 % | Concreto - C-30 - Abatimento 12 cm | 0.080422 | Forma - Estrutura - Concreto | 1.551 | Armadura - Aço CA50 - ø 8.0 mm | 5.11724 | Armadura - Aço CA60 - ø 5.0 mm | 3.38527 | Dimensionado | 0 | 0 | Viga C-30 - Seção Retangular 14 X 20
V332 | TERREO | 14 | 20 | 0 | 0.36 % | Concreto - C-30 - Abatimento 12 cm | 0.115369 | Forma - Estrutura - Concreto | 2.22498 | Armadura - Aço CA50 - ø 8.0 mm | 7.34093 | Armadura - Aço CA60 - ø 5.0 mm | 4.85633 | Dimensionado | 0 | 0 | Viga C-30 - Seção Retangular 14 X 20
V301 | COBERTURA | 14 | 30 | 0 | 0.24 % | Forma - Estrutura - Concreto |  | Armadura - Aço CA50 - ø 8.0 mm |  | Armadura - Aço CA60 - ø 5.0 mm | 0.167739 |  |  |  | 0 | 0 | Viga C-30 - Seção Retangular 14 X 30 | AltoQi_Eberick-Item_01 - Quantidade_01: 0.13998 m2; AltoQi_Eberick-Item_02 - Quantidade_02: 0.279268 kg
V301 | COBERTURA | 14 | 30 | 0 | 0.24 % | Concreto - C-30 - Abatimento 12 cm | 0.115594 | Forma - Estrutura - Concreto | 2.03665 | Armadura - Aço CA50 - ø 8.0 mm | 4.06323 | Armadura - Aço CA60 - ø 5.0 mm | 2.44053 | Dimensionado | 0 | 0 | Viga C-30 - Seção Retangular 14 X 30
V301 | COBERTURA | 14 | 30 | 0 | 0.24 % | Concreto - C-30 - Abatimento 12 cm | 0.115114 | Forma - Estrutura - Concreto | 2.02819 | Armadura - Aço CA50 - ø 8.0 mm | 4.04636 | Armadura - Aço CA60 - ø 5.0 mm | 2.43039 | Dimensionado | 0 | 0 | Viga C-30 - Seção Retangular 14 X 30
V302 | COBERTURA | 14 | 30 | 0 | 0.24 % | Concreto - C-30 - Abatimento 12 cm | 0.121237 | Forma - Estrutura - Concreto | 2.13609 | Armadura - Aço CA50 - ø 8.0 mm | 3.90024 | Armadura - Aço CA60 - ø 5.0 mm | 2.17219 | Dimensionado | 0 | 0 | Viga C-30 - Seção Retangular 14 X 30
V302 | COBERTURA | 14 | 30 | 0 | 0.24 % | Concreto - C-30 - Abatimento 12 cm | 0.128243 | Forma - Estrutura - Concreto | 2.25951 | Armadura - Aço CA50 - ø 8.0 mm | 4.1256 | Armadura - Aço CA60 - ø 5.0 mm | 2.29771 | Dimensionado | 0 | 0 | Viga C-30 - Seção Retangular 14 X 30
V303 | COBERTURA | 14 | 30 | 0 | 0.24 % | Concreto - C-30 - Abatimento 12 cm | 0.014483 | Forma - Estrutura - Concreto | 0.255185 | Armadura - Aço CA50 - ø 8.0 mm | 0.640425 | Armadura - Aço CA60 - ø 5.0 mm | 0.331368 | Dimensionado | 0 | 0 | Viga C-30 - Seção Retangular 14 X 30
V303 | COBERTURA | 14 | 30 | 0 | 0.24 % | Concreto - C-30 - Abatimento 12 cm | 0.084212 | Forma - Estrutura - Concreto | 1.48374 | Armadura - Aço CA50 - ø 8.0 mm | 3.72368 | Armadura - Aço CA60 - ø 5.0 mm | 1.9267 | Dimensionado | 0 | 0 | Viga C-30 - Seção Retangular 14 X 30
V304 | COBERTURA | 14 | 30 | 0 | 0.24 % | Concreto - C-30 - Abatimento 12 cm | 0.099595 | Forma - Estrutura - Concreto | 1.75476 | Armadura - Aço CA50 - ø 8.0 mm | 4.67977 | Armadura - Aço CA60 - ø 5.0 mm | 1.27931 | Dimensionado | 0 | 0 | Viga C-30 - Seção Retangular 14 X 30
V305 | COBERTURA | 17 | 30 | 0 | 0.20 % | Concreto - C-30 - Abatimento 12 cm | 0.126347 | Forma - Estrutura - Concreto | 1.9076 | Armadura - Aço CA50 - ø 8.0 mm | 4.60874 | Armadura - Aço CA60 - ø 5.0 mm | 1.64616 | Dimensionado | 0 | 0 | Viga C-30 - Seção Retangular 17 X 30
V306 | COBERTURA | 14 | 30 | 0 | 0.24 % | Concreto - C-30 - Abatimento 12 cm | 0.072183 | Forma - Estrutura - Concreto | 1.27179 | Armadura - Aço CA50 - ø 8.0 mm | 3.67751 | Armadura - Aço CA60 - ø 5.0 mm | 1.81081 | Dimensionado | 0 | 0 | Viga C-30 - Seção Retangular 14 X 30
V306 | COBERTURA | 14 | 30 | 0 | 0.24 % | Concreto - C-30 - Abatimento 12 cm | 0.012237 | Forma - Estrutura - Concreto | 0.215611 | Armadura - Aço CA50 - ø 8.0 mm | 0.623459 | Armadura - Aço CA60 - ø 5.0 mm | 0.306993 | Dimensionado | 0 | 0 | Viga C-30 - Seção Retangular 14 X 30
V307 | COBERTURA | 14 | 40 | 20 | 0.18 % | Concreto - C-30 - Abatimento 12 cm | 0.012046 | Forma - Estrutura - Concreto | 0.202194 | Armadura - Aço CA50 - ø 8.0 mm | 1.34159 | Armadura - Aço CA60 - ø 5.0 mm | 0.158758 | Dimensionado | 0 | 0 | Viga C-30 - Seção Retangular 14 X 40
V308 | COBERTURA | 17 | 40 | 20 | 0.15 % | Concreto - C-30 - Abatimento 12 cm | 0.01476 | Forma - Estrutura - Concreto | 0.210553 | Armadura - Aço CA50 - ø 8.0 mm | 0.576093 | Armadura - Aço CA50 - ø 10.0 mm | 1.36871 | Dimensionado | 0 | 0 | Viga C-30 - Seção Retangular 17 X 40 | AltoQi_Eberick-Item_05 - Descrição_05: Armadura - Aço CA60 - ø 5.0 mm; Quantidade_05: 1.07586 kg; Status_05: Dimensionado
V309 | COBERTURA | 17 | 40 | 20 | 0.15 % | Concreto - C-30 - Abatimento 12 cm | 0.013076 | Forma - Estrutura - Concreto | 0.186531 | Armadura - Aço CA50 - ø 8.0 mm | 1.37315 | Armadura - Aço CA60 - ø 5.0 mm | 0.168006 | Dimensionado | 0 | 0 | Viga C-30 - Seção Retangular 17 X 40
V310 | COBERTURA | 14 | 40 | 20 | 0.18 % | Concreto - C-30 - Abatimento 12 cm | 0.011469 | Forma - Estrutura - Concreto | 0.192512 | Armadura - Aço CA50 - ø 8.0 mm | 1.31002 | Armadura - Aço CA60 - ø 5.0 mm | 0.158758 | Dimensionado | 0 | 0 | Viga C-30 - Seção Retangular 14 X 40
V311 | COBERTURA | 14 | 40 | 20 | 0.18 % | Concreto - C-30 - Abatimento 12 cm | 0.01204 | Forma - Estrutura - Concreto | 0.2021 | Armadura - Aço CA50 - ø 8.0 mm | 1.34159 | Armadura - Aço CA60 - ø 5.0 mm | 0.158758 | Dimensionado | 0 | 0 | Viga C-30 - Seção Retangular 14 X 40
V312 | COBERTURA | 17 | 40 | 20 | 0.15 % | Concreto - C-30 - Abatimento 12 cm | 0.014477 | Forma - Estrutura - Concreto | 0.206513 | Armadura - Aço CA50 - ø 8.0 mm | 0.568201 | Armadura - Aço CA50 - ø 10.0 mm | 1.35638 | Dimensionado | 0 | 0 | Viga C-30 - Seção Retangular 17 X 40 | AltoQi_Eberick-Item_05 - Descrição_05: Armadura - Aço CA60 - ø 5.0 mm; Quantidade_05: 1.06353 kg; Status_05: Dimensionado
V313 | COBERTURA | 17 | 40 | 20 | 0.15 % | Concreto - C-30 - Abatimento 12 cm | 0.013076 | Forma - Estrutura - Concreto | 0.186531 | Armadura - Aço CA50 - ø 8.0 mm | 1.37315 | Armadura - Aço CA60 - ø 5.0 mm | 0.168006 | Dimensionado | 0 | 0 | Viga C-30 - Seção Retangular 17 X 40
V314 | COBERTURA | 14 | 40 | 20 | 0.18 % | Concreto - C-30 - Abatimento 12 cm | 0.011472 | Forma - Estrutura - Concreto | 0.192561 | Armadura - Aço CA50 - ø 8.0 mm | 1.31002 | Armadura - Aço CA60 - ø 5.0 mm | 0.158758 | Dimensionado | 0 | 0 | Viga C-30 - Seção Retangular 14 X 40
V315 | COBERTURA | 17 | 30 | 55 | 0.20 % | Concreto - C-30 - Abatimento 12 cm | 0.103868 | Forma - Estrutura - Concreto | 1.5682 | Armadura - Aço CA50 - ø 8.0 mm | 4.10027 | Armadura - Aço CA60 - ø 5.0 mm | 1.67374 | Dimensionado | 0 | 0 | Viga C-30 - Seção Retangular 17 X 30
V315 | COBERTURA | 17 | 30 | 55 | 0.20 % | Concreto - C-30 - Abatimento 12 cm | 0.016079 | Forma - Estrutura - Concreto | 0.242766 | Armadura - Aço CA50 - ø 8.0 mm | 0.634744 | Armadura - Aço CA60 - ø 5.0 mm | 0.259104 | Dimensionado | 0 | 0 | Viga C-30 - Seção Retangular 17 X 30
V316 | COBERTURA | 14 | 40 | 55 | 0.18 % | Concreto - C-30 - Abatimento 12 cm | 0.108504 | Forma - Estrutura - Concreto | 1.82131 | Armadura - Aço CA50 - ø 8.0 mm | 3.9725 | Armadura - Aço CA60 - ø 5.0 mm | 1.52088 | Dimensionado | 0 | 0 | Viga C-30 - Seção Retangular 14 X 40
V316 | COBERTURA | 14 | 40 | 55 | 0.18 % | Concreto - C-30 - Abatimento 12 cm | 0.016085 | Forma - Estrutura - Concreto | 0.269997 | Armadura - Aço CA50 - ø 8.0 mm | 0.588896 | Armadura - Aço CA60 - ø 5.0 mm | 0.22546 | Dimensionado | 0 | 0 | Viga C-30 - Seção Retangular 14 X 40
V317 | COBERTURA | 14 | 40 | 55 | 0.18 % | Concreto - C-30 - Abatimento 12 cm | 0.087653 | Forma - Estrutura - Concreto | 1.47131 | Armadura - Aço CA50 - ø 8.0 mm | 3.34607 | Armadura - Aço CA60 - ø 5.0 mm | 1.41495 | Dimensionado | 0 | 0 | Viga C-30 - Seção Retangular 14 X 40
V318 | COBERTURA | 14 | 40 | 55 | 0.18 % | Concreto - C-30 - Abatimento 12 cm | 0.078691 | Forma - Estrutura - Concreto | 1.32089 | Armadura - Aço CA50 - ø 8.0 mm | 3.23559 | Armadura - Aço CA60 - ø 5.0 mm | 1.27007 | Dimensionado | 0 | 0 | Viga C-30 - Seção Retangular 14 X 40
V319 | COBERTURA | 17 | 30 | 55 | 0.20 % | Concreto - C-30 - Abatimento 12 cm | 0.104773 | Forma - Estrutura - Concreto | 1.58187 | Armadura - Aço CA50 - ø 8.0 mm | 4.14259 | Armadura - Aço CA60 - ø 5.0 mm | 1.56578 | Dimensionado | 0 | 0 | Viga C-30 - Seção Retangular 17 X 30
V319 | COBERTURA | 17 | 30 | 55 | 0.20 % | Concreto - C-30 - Abatimento 12 cm | 0.015383 | Forma - Estrutura - Concreto | 0.232246 | Armadura - Aço CA50 - ø 8.0 mm | 0.608203 | Armadura - Aço CA60 - ø 5.0 mm | 0.229884 | Dimensionado | 0 | 0 | Viga C-30 - Seção Retangular 17 X 30
V320 | COBERTURA | 17 | 40 | 55 | 0.15 % | Concreto - C-30 - Abatimento 12 cm | 0.020549 | Forma - Estrutura - Concreto | 0.293124 | Armadura - Aço CA50 - ø 8.0 mm | 0.300714 | Armadura - Aço CA50 - ø 10.0 mm | 0.561085 | Dimensionado | 0 | 0 | Viga C-30 - Seção Retangular 17 X 40 | AltoQi_Eberick-Item_05 - Descrição_05: Armadura - Aço CA60 - ø 5.0 mm; Quantidade_05: 0.404463 kg; Status_05: Dimensionado
V320 | COBERTURA | 17 | 40 | 55 | 0.15 % | Concreto - C-30 - Abatimento 12 cm | 0.126671 | Forma - Estrutura - Concreto | 1.80693 | Armadura - Aço CA50 - ø 8.0 mm | 1.85372 | Armadura - Aço CA50 - ø 10.0 mm | 3.45874 | Dimensionado | 0 | 0 | Viga C-30 - Seção Retangular 17 X 40 | AltoQi_Eberick-Item_05 - Descrição_05: Armadura - Aço CA60 - ø 5.0 mm; Quantidade_05: 2.49326 kg; Status_05: Dimensionado
V321 | COBERTURA | 14 | 40 | 20 | 0.18 % | Concreto - C-30 - Abatimento 12 cm | 0.01204 | Forma - Estrutura - Concreto | 0.2021 | Armadura - Aço CA50 - ø 8.0 mm | 1.34159 | Armadura - Aço CA60 - ø 5.0 mm | 0.158758 | Dimensionado | 0 | 0 | Viga C-30 - Seção Retangular 14 X 40
V322 | COBERTURA | 14 | 40 | 20 | 0.18 % | Concreto - C-30 - Abatimento 12 cm | 0.012326 | Forma - Estrutura - Concreto | 0.206894 | Armadura - Aço CA50 - ø 8.0 mm | 1.34159 | Armadura - Aço CA60 - ø 5.0 mm | 0.317517 | Dimensionado | 0 | 0 | Viga C-30 - Seção Retangular 14 X 40
V323 | COBERTURA | 17 | 40 | 20 | 0.15 % | Concreto - C-30 - Abatimento 12 cm | 0.01462 | Forma - Estrutura - Concreto | 0.20855 | Armadura - Aço CA50 - ø 8.0 mm | 1.4205 | Armadura - Aço CA60 - ø 5.0 mm | 0.336013 | Dimensionado | 0 | 0 | Viga C-30 - Seção Retangular 17 X 40
V324 | COBERTURA | 14 | 40 | 20 | 0.18 % | Concreto - C-30 - Abatimento 12 cm | 0.012326 | Forma - Estrutura - Concreto | 0.206893 | Armadura - Aço CA50 - ø 8.0 mm | 1.34159 | Armadura - Aço CA60 - ø 5.0 mm | 0.317517 | Dimensionado | 0 | 0 | Viga C-30 - Seção Retangular 14 X 40
V325 | COBERTURA | 14 | 30 | 0 | 0.24 % | Concreto - C-30 - Abatimento 12 cm | 0.073209 | Forma - Estrutura - Concreto | 1.28988 | Armadura - Aço CA50 - ø 8.0 mm | 3.72454 | Armadura - Aço CA60 - ø 5.0 mm | 1.81401 | Dimensionado | 0 | 0 | Viga C-30 - Seção Retangular 14 X 30
V325 | COBERTURA | 14 | 30 | 0 | 0.24 % | Concreto - C-30 - Abatimento 12 cm | 0.012261 | Forma - Estrutura - Concreto | 0.216023 | Armadura - Aço CA50 - ø 8.0 mm | 0.623771 | Armadura - Aço CA60 - ø 5.0 mm | 0.303802 | Dimensionado | 0 | 0 | Viga C-30 - Seção Retangular 14 X 30
V326 | COBERTURA | 14 | 30 | 0 | 0.24 % | Concreto - C-30 - Abatimento 12 cm | 0.09203 | Forma - Estrutura - Concreto | 1.62149 | Armadura - Aço CA50 - ø 8.0 mm | 4.57718 | Armadura - Aço CA60 - ø 5.0 mm | 1.27931 | Dimensionado | 0 | 0 | Viga C-30 - Seção Retangular 14 X 30
V327 | COBERTURA | 14 | 30 | 0 | 0.24 % | Concreto - C-30 - Abatimento 12 cm | 0.100389 | Forma - Estrutura - Concreto | 1.76875 | Armadura - Aço CA50 - ø 8.0 mm | 4.71133 | Armadura - Aço CA60 - ø 5.0 mm | 1.27931 | Dimensionado | 0 | 0 | Viga C-30 - Seção Retangular 14 X 30
V328 | COBERTURA | 14 | 30 | 0 | 0.24 % | Concreto - C-30 - Abatimento 12 cm | 0.013088 | Forma - Estrutura - Concreto | 0.230606 | Armadura - Aço CA50 - ø 8.0 mm | 0.666887 | Armadura - Aço CA60 - ø 5.0 mm | 0.198364 | Dimensionado | 0 | 0 | Viga C-30 - Seção Retangular 14 X 30
V328 | COBERTURA | 14 | 30 | 0 | 0.24 % | Concreto - C-30 - Abatimento 12 cm | 0.071323 | Forma - Estrutura - Concreto | 1.25665 | Armadura - Aço CA50 - ø 8.0 mm | 3.63408 | Armadura - Aço CA60 - ø 5.0 mm | 1.08095 | Dimensionado | 0 | 0 | Viga C-30 - Seção Retangular 14 X 30
V329 | COBERTURA | 14 | 30 | 0 | 0.24 % | Concreto - C-30 - Abatimento 12 cm | 0.252302 | Forma - Estrutura - Concreto | 4.44533 | Armadura - Aço CA50 - ø 8.0 mm | 8.15211 | Armadura - Aço CA60 - ø 5.0 mm | 4.53618 | Dimensionado | 0 | 0 | Viga C-30 - Seção Retangular 14 X 30
V330 | COBERTURA | 14 | 30 | 0 | 0.24 % | Concreto - C-30 - Abatimento 12 cm | 0.013496 | Forma - Estrutura - Concreto | 0.237785 | Armadura - Aço CA50 - ø 8.0 mm | 0.594366 | Armadura - Aço CA60 - ø 5.0 mm | 0.233016 | Dimensionado | 0 | 0 | Viga C-30 - Seção Retangular 14 X 30
V330 | COBERTURA | 14 | 30 | 0 | 0.24 % | Concreto - C-30 - Abatimento 12 cm | 0.088816 | Forma - Estrutura - Concreto | 1.56486 | Armadura - Aço CA50 - ø 8.0 mm | 3.9115 | Armadura - Aço CA60 - ø 5.0 mm | 1.53347 | Dimensionado | 0 | 0 | Viga C-30 - Seção Retangular 14 X 30
V330 | COBERTURA | 14 | 30 | 0 | 0.24 % | Concreto - C-30 - Abatimento 12 cm | 0.144614 | Forma - Estrutura - Concreto | 2.54797 | Armadura - Aço CA50 - ø 8.0 mm | 6.36887 | Armadura - Aço CA60 - ø 5.0 mm | 2.49687 | Dimensionado | 0 | 0 | Viga C-30 - Seção Retangular 14 X 30
V331 | COBERTURA | 14 | 30 | 0 | 0.24 % | Concreto - C-30 - Abatimento 12 cm | 0.21 | Forma - Estrutura - Concreto | 3.7 | Armadura - Aço CA50 - ø 8.0 mm | 8.55458 | Armadura - Aço CA60 - ø 5.0 mm | 2.81449 | Dimensionado | 0 | 0 | Viga C-30 - Seção Retangular 14 X 30
V332 | COBERTURA | 14 | 40 | 20 | 0.18 % | Concreto - C-30 - Abatimento 12 cm | 0.14336 | Forma - Estrutura - Concreto | 2.4064 | Armadura - Aço CA50 - ø 8.0 mm | 4.78236 | Armadura - Aço CA60 - ø 5.0 mm | 1.9051 | Dimensionado | 0 | 0 | Viga C-30 - Seção Retangular 14 X 40
V333 | COBERTURA | 14 | 30 | 0 | 0.24 % | Concreto - C-30 - Abatimento 12 cm | 0.20916 | Forma - Estrutura - Concreto | 3.6852 | Armadura - Aço CA50 - ø 8.0 mm | 8.52301 | Armadura - Aço CA60 - ø 5.0 mm | 2.81449 | Dimensionado | 0 | 0 | Viga C-30 - Seção Retangular 14 X 30
V334 | COBERTURA | 14 | 30 | 0 | 0.24 % | Concreto - C-30 - Abatimento 12 cm | 0.209996 | Forma - Estrutura - Concreto | 3.69993 | Armadura - Aço CA50 - ø 8.0 mm | 8.60193 | Armadura - Aço CA60 - ø 5.0 mm | 2.94243 | Dimensionado | 0 | 0 | Viga C-30 - Seção Retangular 14 X 30
V335 | COBERTURA | 14 | 40 | 20 | 0.18 % | Concreto - C-30 - Abatimento 12 cm | 0.14308 | Forma - Estrutura - Concreto | 2.4017 | Armadura - Aço CA50 - ø 8.0 mm | 4.73501 | Armadura - Aço CA60 - ø 5.0 mm | 1.9051 | Dimensionado | 0 | 0 | Viga C-30 - Seção Retangular 14 X 40
V336 | COBERTURA | 14 | 30 | 0 | 0.24 % | Concreto - C-30 - Abatimento 12 cm | 0.20979 | Forma - Estrutura - Concreto | 3.6963 | Armadura - Aço CA50 - ø 8.0 mm | 8.55458 | Armadura - Aço CA60 - ø 5.0 mm | 2.94243 | Dimensionado | 0 | 0 | Viga C-30 - Seção Retangular 14 X 30
V337 | COBERTURA | 14 | 30 | 0 | 0.24 % | Concreto - C-30 - Abatimento 12 cm | 0.04158 | Forma - Estrutura - Concreto | 0.7326 | Armadura - Aço CA50 - ø 8.0 mm | 2.14654 | Armadura - Aço CA60 - ø 5.0 mm | 0.639658 | Dimensionado | 0 | 0 | Viga C-30 - Seção Retangular 14 X 30
V338 | COBERTURA | 14 | 30 | 55 | 0.24 % | Concreto - C-30 - Abatimento 12 cm | 0.069718 | Forma - Estrutura - Concreto | 1.22836 | Armadura - Aço CA50 - ø 8.0 mm | 3.15211 | Armadura - Aço CA60 - ø 5.0 mm | 0.97093 | Dimensionado | 0 | 0 | Viga C-30 - Seção Retangular 14 X 30
V338 | COBERTURA | 14 | 30 | 55 | 0.24 % | Concreto - C-30 - Abatimento 12 cm | 0.181519 | Forma - Estrutura - Concreto | 3.19819 | Armadura - Aço CA50 - ø 8.0 mm | 8.20694 | Armadura - Aço CA60 - ø 5.0 mm | 2.52795 | Dimensionado | 0 | 0 | Viga C-30 - Seção Retangular 14 X 30
V338 | COBERTURA | 14 | 30 | 55 | 0.24 % | Concreto - C-30 - Abatimento 12 cm | 0.070278 | Forma - Estrutura - Concreto | 1.23822 | Armadura - Aço CA50 - ø 8.0 mm | 3.17743 | Armadura - Aço CA60 - ø 5.0 mm | 0.978728 | Dimensionado | 0 | 0 | Viga C-30 - Seção Retangular 14 X 30
V339 | COBERTURA | 14 | 30 | 0 | 0.24 % | Concreto - C-30 - Abatimento 12 cm | 0.04158 | Forma - Estrutura - Concreto | 0.7326 | Armadura - Aço CA50 - ø 8.0 mm | 2.14654 | Armadura - Aço CA60 - ø 5.0 mm | 0.639658 | Dimensionado | 0 | 0 | Viga C-30 - Seção Retangular 14 X 30
V340 | COBERTURA | 14 | 30 | 0 | 0.24 % | Concreto - C-30 - Abatimento 12 cm | 0.03612 | Forma - Estrutura - Concreto | 0.6364 | Armadura - Aço CA50 - ø 8.0 mm | 2.16232 | Armadura - Aço CA60 - ø 5.0 mm | 0.639658 | Dimensionado | 0 | 0 | Viga C-30 - Seção Retangular 14 X 30
V341 | COBERTURA | 14 | 30 | 0 | 0.24 % | Concreto - C-30 - Abatimento 12 cm | 0.042 | Forma - Estrutura - Concreto | 0.74 | Armadura - Aço CA50 - ø 8.0 mm | 2.16232 | Armadura - Aço CA60 - ø 5.0 mm | 0.639658 | Dimensionado | 0 | 0 | Viga C-30 - Seção Retangular 14 X 30
V342 | COBERTURA | 14 | 30 | 0 | 0.24 % | Concreto - C-30 - Abatimento 12 cm | 0.125455 | Forma - Estrutura - Concreto | 2.21041 | Armadura - Aço CA50 - ø 8.0 mm | 5.40547 | Armadura - Aço CA60 - ø 5.0 mm | 1.71315 | Dimensionado | 0 | 0 | Viga C-30 - Seção Retangular 14 X 30
V342 | COBERTURA | 14 | 30 | 0 | 0.24 % | Concreto - C-30 - Abatimento 12 cm | 0.070157 | Forma - Estrutura - Concreto | 1.2361 | Armadura - Aço CA50 - ø 8.0 mm | 3.02283 | Armadura - Aço CA60 - ø 5.0 mm | 0.958024 | Dimensionado | 0 | 0 | Viga C-30 - Seção Retangular 14 X 30
V342 | COBERTURA | 14 | 30 | 0 | 0.24 % | Concreto - C-30 - Abatimento 12 cm | 0.179129 | Forma - Estrutura - Concreto | 3.15607 | Armadura - Aço CA50 - ø 8.0 mm | 7.71807 | Armadura - Aço CA60 - ø 5.0 mm | 2.44609 | Dimensionado | 0 | 0 | Viga C-30 - Seção Retangular 14 X 30
V343 | COBERTURA | 14 | 30 | 0 | 0.24 % | Concreto - C-30 - Abatimento 12 cm | 0.187522 | Forma - Estrutura - Concreto | 3.30396 | Armadura - Aço CA50 - ø 8.0 mm | 7.88721 | Armadura - Aço CA60 - ø 5.0 mm | 2.57434 | Dimensionado | 0 | 0 | Viga C-30 - Seção Retangular 14 X 30
V343 | COBERTURA | 14 | 30 | 0 | 0.24 % | Concreto - C-30 - Abatimento 12 cm | 0.147957 | Forma - Estrutura - Concreto | 2.60687 | Armadura - Aço CA50 - ø 8.0 mm | 6.22311 | Armadura - Aço CA60 - ø 5.0 mm | 2.03119 | Dimensionado | 0 | 0 | Viga C-30 - Seção Retangular 14 X 30
V344 | COBERTURA | 14 | 30 | 0 | 0.24 % | Concreto - C-30 - Abatimento 12 cm | 0.145929 | Forma - Estrutura - Concreto | 2.57113 | Armadura - Aço CA50 - ø 8.0 mm | 6.07573 | Armadura - Aço CA60 - ø 5.0 mm | 1.96138 | Dimensionado | 0 | 0 | Viga C-30 - Seção Retangular 14 X 30
V344 | COBERTURA | 14 | 30 | 0 | 0.24 % | Concreto - C-30 - Abatimento 12 cm | 0.206245 | Forma - Estrutura - Concreto | 3.63385 | Armadura - Aço CA50 - ø 8.0 mm | 8.58701 | Armadura - Aço CA60 - ø 5.0 mm | 2.77208 | Dimensionado | 0 | 0 | Viga C-30 - Seção Retangular 14 X 30
V345 | COBERTURA | 17 | 40 | 20 | 0.15 % | Concreto - C-30 - Abatimento 12 cm | 0.172051 | Forma - Estrutura - Concreto | 2.45426 | Armadura - Aço CA50 - ø 8.0 mm | 4.98754 | Armadura - Aço CA60 - ø 5.0 mm | 2.5016 | Dimensionado | 0 | 0 | Viga C-30 - Seção Retangular 17 X 40
V346 | COBERTURA | 14 | 30 | 0 | 0.24 % | Concreto - C-30 - Abatimento 12 cm | 0.125687 | Forma - Estrutura - Concreto | 2.21448 | Armadura - Aço CA50 - ø 8.0 mm | 5.2634 | Armadura - Aço CA60 - ø 5.0 mm | 1.65602 | Dimensionado | 0 | 0 | Viga C-30 - Seção Retangular 14 X 30
V346 | COBERTURA | 14 | 30 | 0 | 0.24 % | Concreto - C-30 - Abatimento 12 cm | 0.078215 | Forma - Estrutura - Concreto | 1.37807 | Armadura - Aço CA50 - ø 8.0 mm | 3.2754 | Armadura - Aço CA60 - ø 5.0 mm | 1.03054 | Dimensionado | 0 | 0 | Viga C-30 - Seção Retangular 14 X 30
V347 | COBERTURA | 14 | 30 | 0 | 0.24 % | Concreto - C-30 - Abatimento 12 cm | 0.191181 | Forma - Estrutura - Concreto | 3.36843 | Armadura - Aço CA50 - ø 8.0 mm | 7.72135 | Armadura - Aço CA60 - ø 5.0 mm | 2.56447 | Dimensionado | 0 | 0 | Viga C-30 - Seção Retangular 14 X 30
V347 | COBERTURA | 14 | 30 | 0 | 0.24 % | Concreto - C-30 - Abatimento 12 cm | 0.130987 | Forma - Estrutura - Concreto | 2.30786 | Armadura - Aço CA50 - ø 8.0 mm | 5.29024 | Armadura - Aço CA60 - ø 5.0 mm | 1.75703 | Dimensionado | 0 | 0 | Viga C-30 - Seção Retangular 14 X 30
V347 | COBERTURA | 14 | 30 | 0 | 0.24 % | Concreto - C-30 - Abatimento 12 cm | 0.078399 | Forma - Estrutura - Concreto | 1.38132 | Armadura - Aço CA50 - ø 8.0 mm | 3.16635 | Armadura - Aço CA60 - ø 5.0 mm | 1.05163 | Dimensionado | 0 | 0 | Viga C-30 - Seção Retangular 14 X 30
V348 | COBERTURA | 14 | 30 | 0 | 0.24 % | Concreto - C-30 - Abatimento 12 cm | 0.182827 | Forma - Estrutura - Concreto | 3.22123 | Armadura - Aço CA50 - ø 8.0 mm | 7.88722 | Armadura - Aço CA60 - ø 5.0 mm | 2.57435 | Dimensionado | 0 | 0 | Viga C-30 - Seção Retangular 14 X 30
V348 | COBERTURA | 14 | 30 | 0 | 0.24 % | Concreto - C-30 - Abatimento 12 cm | 0.144253 | Forma - Estrutura - Concreto | 2.54159 | Armadura - Aço CA50 - ø 8.0 mm | 6.22311 | Armadura - Aço CA60 - ø 5.0 mm | 2.03119 | Dimensionado | 0 | 0 | Viga C-30 - Seção Retangular 14 X 30
V349 | COBERTURA | 14 | 30 | 0 | 0.24 % | Concreto - C-30 - Abatimento 12 cm | 0.145935 | Forma - Estrutura - Concreto | 2.57124 | Armadura - Aço CA50 - ø 8.0 mm | 6.07601 | Armadura - Aço CA60 - ø 5.0 mm | 1.96147 | Dimensionado | 0 | 0 | Viga C-30 - Seção Retangular 14 X 30
V349 | COBERTURA | 14 | 30 | 0 | 0.24 % | Concreto - C-30 - Abatimento 12 cm | 0.206239 | Forma - Estrutura - Concreto | 3.63373 | Armadura - Aço CA50 - ø 8.0 mm | 8.58673 | Armadura - Aço CA60 - ø 5.0 mm | 2.77199 | Dimensionado | 0 | 0 | Viga C-30 - Seção Retangular 14 X 30
V350 | COBERTURA | 14 | 40 | 20 | 0.18 % | Concreto - C-30 - Abatimento 12 cm | 0.14168 | Forma - Estrutura - Concreto | 2.3782 | Armadura - Aço CA50 - ø 8.0 mm | 4.84549 | Armadura - Aço CA60 - ø 5.0 mm | 1.9051 | Dimensionado | 0 | 0 | Viga C-30 - Seção Retangular 14 X 40
V351 | COBERTURA | 14 | 30 | 0 | 0.24 % | Concreto - C-30 - Abatimento 12 cm | 0.209152 | Forma - Estrutura - Concreto | 3.68505 | Armadura - Aço CA50 - ø 8.0 mm | 8.57037 | Armadura - Aço CA60 - ø 5.0 mm | 2.81449 | Dimensionado | 0 | 0 | Viga C-30 - Seção Retangular 14 X 30
V352 | COBERTURA | 14 | 30 | 0 | 0.24 % | Concreto - C-30 - Abatimento 12 cm | 0.03423 | Forma - Estrutura - Concreto | 0.6031 | Armadura - Aço CA50 - ø 8.0 mm | 2.13075 | Armadura - Aço CA60 - ø 5.0 mm | 0.511726 | Dimensionado | 0 | 0 | Viga C-30 - Seção Retangular 14 X 30
V353 | COBERTURA | 14 | 30 | 0 | 0.24 % | Concreto - C-30 - Abatimento 12 cm | 0.028778 | Forma - Estrutura - Concreto | 0.507048 | Armadura - Aço CA50 - ø 8.0 mm | 2.19389 | Armadura - Aço CA60 - ø 5.0 mm | 0.511726 | Dimensionado | 0 | 0 | Viga C-30 - Seção Retangular 14 X 30
V354 | COBERTURA | 14 | 30 | 0 | 0.24 % | Concreto - C-30 - Abatimento 12 cm | 0.042 | Forma - Estrutura - Concreto | 0.74 | Armadura - Aço CA50 - ø 8.0 mm | 0.931218 | Armadura - Aço CA60 - ø 5.0 mm | 0.850822 | Dimensionado | 0 | 0 | Viga C-30 - Seção Retangular 14 X 30
V355 | COBERTURA | 14 | 40 | 55 | 0.18 % | Concreto - C-30 - Abatimento 12 cm | 0.051276 | Forma - Estrutura - Concreto | 0.868152 | Armadura - Aço CA50 - ø 8.0 mm | 1.33437 | Armadura - Aço CA60 - ø 5.0 mm | 0.865125 | Dimensionado | 0 | 0 | Viga C-30 - Seção Retangular 14 X 40
V355 | COBERTURA | 14 | 40 | 55 | 0.18 % | Concreto - C-30 - Abatimento 12 cm | 0.350225 | Forma - Estrutura - Concreto | 5.9297 | Armadura - Aço CA50 - ø 8.0 mm | 9.11411 | Armadura - Aço CA60 - ø 5.0 mm | 5.90902 | Dimensionado | 0 | 0 | Viga C-30 - Seção Retangular 14 X 40
V355 | COBERTURA | 14 | 40 | 55 | 0.18 % | Concreto - C-30 - Abatimento 12 cm | 0.051254 | Forma - Estrutura - Concreto | 0.86778 | Armadura - Aço CA50 - ø 8.0 mm | 1.3338 | Armadura - Aço CA60 - ø 5.0 mm | 0.864754 | Dimensionado | 0 | 0 | Viga C-30 - Seção Retangular 14 X 40
V356 | COBERTURA | 14 | 30 | 0 | 0.24 % | Concreto - C-30 - Abatimento 12 cm | 0.041584 | Forma - Estrutura - Concreto | 0.732674 | Armadura - Aço CA50 - ø 8.0 mm | 2.14654 | Armadura - Aço CA60 - ø 5.0 mm | 0.639658 | Dimensionado | 0 | 0 | Viga C-30 - Seção Retangular 14 X 30
V357 | COBERTURA | 14 | 30 | 0 | 0.24 % | Concreto - C-30 - Abatimento 12 cm | 0.209819 | Forma - Estrutura - Concreto | 3.69682 | Armadura - Aço CA50 - ø 8.0 mm | 8.55458 | Armadura - Aço CA60 - ø 5.0 mm | 2.68656 | Dimensionado | 0 | 0 | Viga C-30 - Seção Retangular 14 X 30
V358 | COBERTURA | 14 | 40 | 20 | 0.18 % | Concreto - C-30 - Abatimento 12 cm | 0.14336 | Forma - Estrutura - Concreto | 2.4064 | Armadura - Aço CA50 - ø 8.0 mm | 4.73501 | Armadura - Aço CA60 - ø 5.0 mm | 1.9051 | Dimensionado | 0 | 0 | Viga C-30 - Seção Retangular 14 X 40
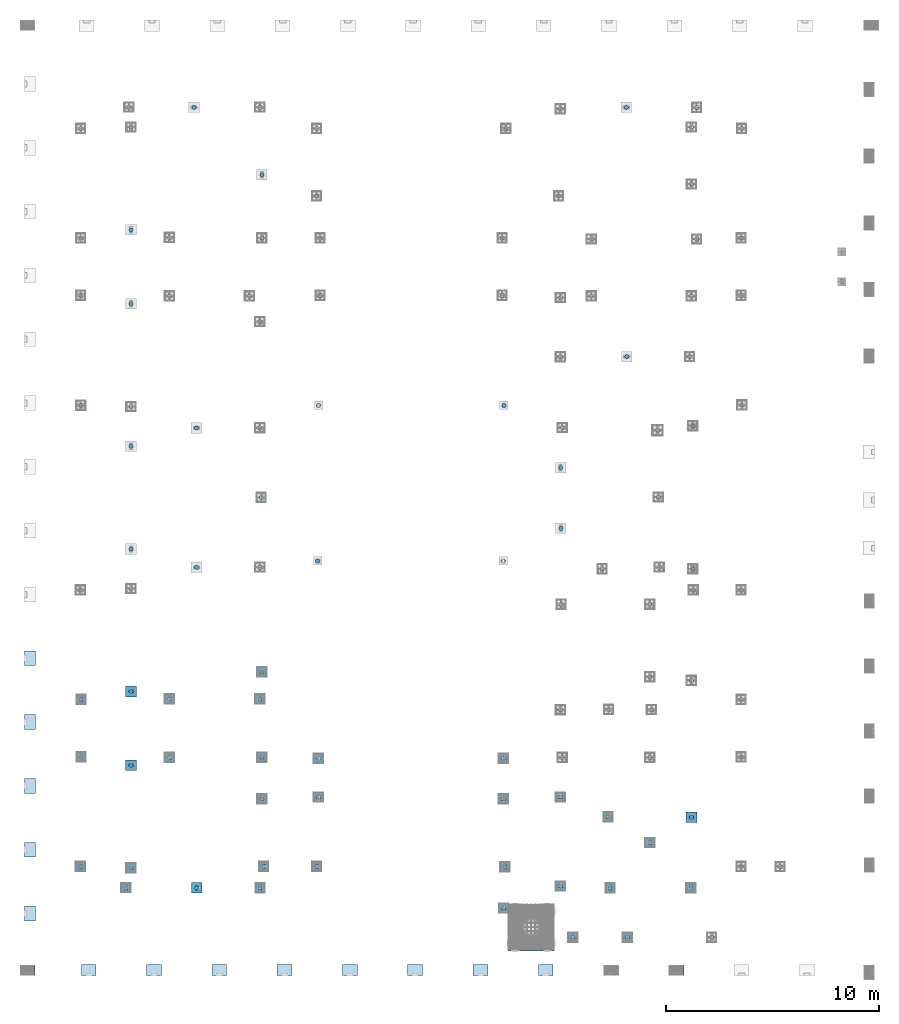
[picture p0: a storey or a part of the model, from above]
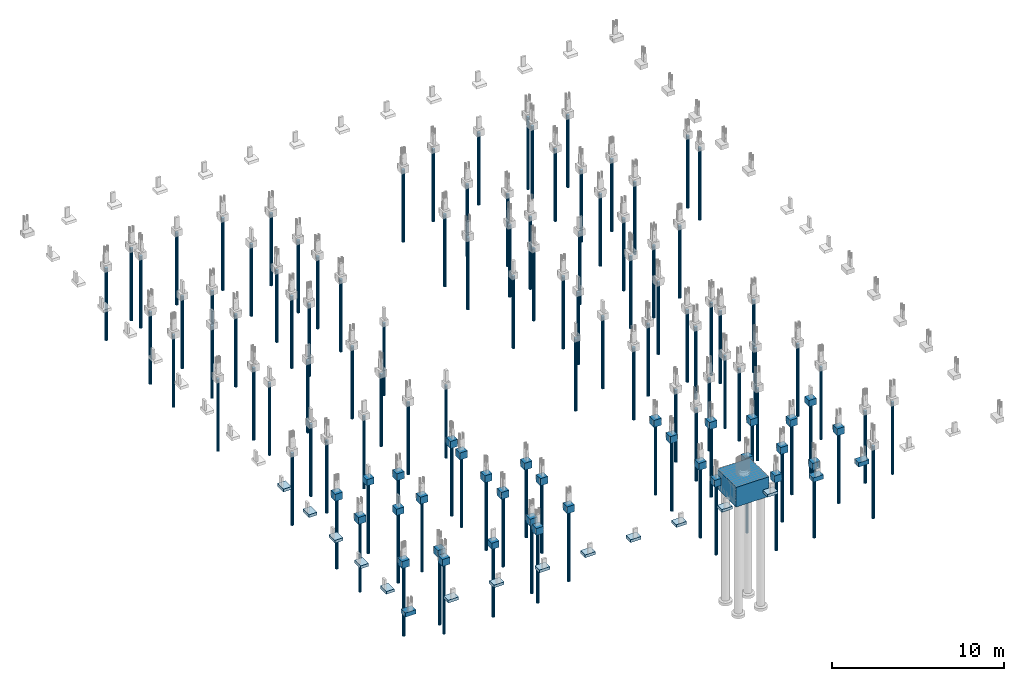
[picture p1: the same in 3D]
Properties of the parts of a building model (IFC4), part 4 of 9

# IfcBeam (614)
Name | In | Seção_bw (cm) | Seção_h (cm) | Elevação (cm) | Taxa de armadura | Descrição_01 | AltoQi_Eberick-Item_01, Quantidade_01 (m3) | Descrição_02 | AltoQi_Eberick-Item_02, Quantidade_02 (m2) | Descrição_03 | Quantidade_03 (kg) | Descrição_04 | AltoQi_Eberick-Item_04, Quantidade_04 (kg) | Status_04 | Cargas de parede (G2) | Adicional (G2) | Reference
V359 | COBERTURA | 14 | 30 | 0 | 0.24 % | Concreto - C-30 - Abatimento 12 cm | 0.209131 | Forma - Estrutura - Concreto | 3.68468 | Armadura - Aço CA50 - ø 8.0 mm | 8.57037 | Armadura - Aço CA60 - ø 5.0 mm | 2.68656 | Dimensionado | 0 | 0 | Viga C-30 - Seção Retangular 14 X 30
V360 | COBERTURA | 14 | 30 | 0 | 0.24 % | Concreto - C-30 - Abatimento 12 cm | 0.20979 | Forma - Estrutura - Concreto | 3.6963 | Armadura - Aço CA50 - ø 8.0 mm | 8.55458 | Armadura - Aço CA60 - ø 5.0 mm | 2.81449 | Dimensionado | 0 | 0 | Viga C-30 - Seção Retangular 14 X 30
V361 | COBERTURA | 14 | 40 | 20 | 0.18 % | Concreto - C-30 - Abatimento 12 cm | 0.143368 | Forma - Estrutura - Concreto | 2.40654 | Armadura - Aço CA50 - ø 8.0 mm | 4.73501 | Armadura - Aço CA60 - ø 5.0 mm | 1.9051 | Dimensionado | 0 | 0 | Viga C-30 - Seção Retangular 14 X 40
V362 | COBERTURA | 14 | 30 | 0 | 0.24 % | Concreto - C-30 - Abatimento 12 cm | 0.209786 | Forma - Estrutura - Concreto | 3.69623 | Armadura - Aço CA50 - ø 8.0 mm | 8.5388 | Armadura - Aço CA60 - ø 5.0 mm | 2.81449 | Dimensionado | 0 | 0 | Viga C-30 - Seção Retangular 14 X 30

# IfcColumn (561)
Material: Concreto
Pset_ConcreteElementGeneral - ConcreteCover: 2 cm; ConstructionMethod: InSitu; ExposureClass: 1; StrengthClass: C-30
AltoQi_Eberick_Elemento - Elemento: Pilar
AltoQi_Eberick_Padrão - Ambiente: Externo; Cobrimento: 2 cm; Classe de concreto: C-30
Pset_ColumnCommon - IsExternal: yes; LoadBearing: yes
Name | In | Tipo | Seção_b (cm) | Seção_h (cm) | Elevação (cm) | Taxa de armadura | Taxa de compressão bruta | Taxa de compressão homogeneizada | Descrição_01 | Quantidade_01 (m3) | Status_01 | Descrição_02 | Quantidade_02 (m2) | Status_02 = Status_03 = Status_04 | Descrição_03 | Quantidade_03 (kg) | Descrição_04 | Quantidade_04 (kg) | Reference
P1 | FUNDAÇÃO | retangular | 14 | 30 | 0 | 0.75 % | 0.04 | 0.03 | Concreto - C-30 - Abatimento 12 cm | 0.02478 | Dimensionado | Forma - Estrutura - Concreto | 0.5192 | Dimensionado | Armadura - Aço CA50 - ø 10.0 mm | 3.6499 | Armadura - Aço CA60 - ø 5.0 mm | 1.02345 | Pilar C-30 - Retangular 14x30
P10 | FUNDAÇÃO | retangular | 14 | 30 | 0 | Não calculado | Não calculado | Não calculado |  |  | Não dimensionado |  |  |  |  |  |  |  | Pilar C-30 - Retangular 14x30
P100 | FUNDAÇÃO | retangular | 14 | 30 | 0 | 0.75 % | 0.04 | 0.03 | Concreto - C-30 - Abatimento 12 cm | 0.02478 | Dimensionado | Forma - Estrutura - Concreto | 0.5192 | Dimensionado | Armadura - Aço CA50 - ø 10.0 mm | 3.6499 | Armadura - Aço CA60 - ø 5.0 mm | 1.02345 | Pilar C-30 - Retangular 14x30
P101 | FUNDAÇÃO | retangular | 14 | 30 | 0 | Não calculado | Não calculado | Não calculado |  |  | Não dimensionado |  |  |  |  |  |  |  | Pilar C-30 - Retangular 14x30
P102 | FUNDAÇÃO | retangular | 14 | 30 | 0 | 0.75 % | 0.11 | 0.1 | Concreto - C-30 - Abatimento 12 cm | 0.0336 | Dimensionado | Forma - Estrutura - Concreto | 0.704 | Dimensionado | Armadura - Aço CA50 - ø 10.0 mm | 4.40208 | Armadura - Aço CA60 - ø 5.0 mm | 1.27931 | Pilar C-30 - Retangular 14x30
P103 | FUNDAÇÃO | retangular | 14 | 30 | 0 | 0.75 % | 0.04 | 0.03 | Concreto - C-30 - Abatimento 12 cm | 0.02478 | Dimensionado | Forma - Estrutura - Concreto | 0.5192 | Dimensionado | Armadura - Aço CA50 - ø 10.0 mm | 3.6499 | Armadura - Aço CA60 - ø 5.0 mm | 1.02345 | Pilar C-30 - Retangular 14x30
P104 | FUNDAÇÃO | retangular | 14 | 30 | 0 | 0.75 % | 0.08 | 0.07 | Concreto - C-30 - Abatimento 12 cm | 0.0336 | Dimensionado | Forma - Estrutura - Concreto | 0.704 | Dimensionado | Armadura - Aço CA50 - ø 10.0 mm | 3.57592 | Armadura - Aço CA60 - ø 5.0 mm | 1.27931 | Pilar C-30 - Retangular 14x30
P105 | FUNDAÇÃO | retangular | 14 | 30 | 0 | 0.75 % | 0.19 | 0.17 | Concreto - C-30 - Abatimento 12 cm | 0.0336 | Dimensionado | Forma - Estrutura - Concreto | 0.704 | Dimensionado | Armadura - Aço CA50 - ø 10.0 mm | 3.57592 | Armadura - Aço CA60 - ø 5.0 mm | 1.27931 | Pilar C-30 - Retangular 14x30
P106 | FUNDAÇÃO | retangular | 14 | 30 | 0 | 0.75 % | 0.16 | 0.14 | Concreto - C-30 - Abatimento 12 cm | 0.0336 | Dimensionado | Forma - Estrutura - Concreto | 0.704 | Dimensionado | Armadura - Aço CA50 - ø 10.0 mm | 4.40208 | Armadura - Aço CA60 - ø 5.0 mm | 1.27931 | Pilar C-30 - Retangular 14x30
P107 | FUNDAÇÃO | retangular | 14 | 30 | 0 | Não calculado | Não calculado | Não calculado |  |  | Não dimensionado |  |  |  |  |  |  |  | Pilar C-30 - Retangular 14x30
P108 | FUNDAÇÃO | retangular | 14 | 30 | 0 | 0.75 % | 0.13 | 0.11 | Concreto - C-30 - Abatimento 12 cm | 0.0336 | Dimensionado | Forma - Estrutura - Concreto | 0.704 | Dimensionado | Armadura - Aço CA50 - ø 10.0 mm | 3.57592 | Armadura - Aço CA60 - ø 5.0 mm | 1.27931 | Pilar C-30 - Retangular 14x30
P109 | FUNDAÇÃO | retangular | 14 | 30 | 0 | 0.75 % | 0.14 | 0.12 | Concreto - C-30 - Abatimento 12 cm | 0.0336 | Dimensionado | Forma - Estrutura - Concreto | 0.704 | Dimensionado | Armadura - Aço CA50 - ø 10.0 mm | 3.57592 | Armadura - Aço CA60 - ø 5.0 mm | 1.27931 | Pilar C-30 - Retangular 14x30
P11 | FUNDAÇÃO | retangular | 14 | 30 | 0 | Não calculado | Não calculado | Não calculado |  |  | Não dimensionado |  |  |  |  |  |  |  | Pilar C-30 - Retangular 14x30
P110 | FUNDAÇÃO | retangular | 14 | 30 | 0 | 0.75 % | 0.13 | 0.12 | Concreto - C-30 - Abatimento 12 cm | 0.0336 | Dimensionado | Forma - Estrutura - Concreto | 0.704 | Dimensionado | Armadura - Aço CA50 - ø 10.0 mm | 3.57592 | Armadura - Aço CA60 - ø 5.0 mm | 1.27931 | Pilar C-30 - Retangular 14x30
P111 | FUNDAÇÃO | retangular | 14 | 30 | 0 | 0.75 % | 0.04 | 0.03 | Concreto - C-30 - Abatimento 12 cm | 0.0336 | Dimensionado | Forma - Estrutura - Concreto | 0.704 | Dimensionado | Armadura - Aço CA50 - ø 10.0 mm | 3.57592 | Armadura - Aço CA60 - ø 5.0 mm | 1.27931 | Pilar C-30 - Retangular 14x30
P112 | FUNDAÇÃO | retangular | 14 | 30 | 0 | 0.75 % | 0.07 | 0.07 | Concreto - C-30 - Abatimento 12 cm | 0.0336 | Dimensionado | Forma - Estrutura - Concreto | 0.704 | Dimensionado | Armadura - Aço CA50 - ø 10.0 mm | 3.57592 | Armadura - Aço CA60 - ø 5.0 mm | 1.27931 | Pilar C-30 - Retangular 14x30
P113 | FUNDAÇÃO | retangular | 17 | 30 | 0 | 0.62 % | 0.12 | 0.11 | Concreto - C-30 - Abatimento 12 cm | 0.0408 | Dimensionado | Forma - Estrutura - Concreto | 0.752 | Dimensionado | Armadura - Aço CA50 - ø 10.0 mm | 3.57592 | Armadura - Aço CA60 - ø 5.0 mm | 1.3718 | Pilar C-30 - Retangular 17x30
P114 | FUNDAÇÃO | retangular | 14 | 30 | 0 | Não calculado | Não calculado | Não calculado |  |  | Não dimensionado |  |  |  |  |  |  |  | Pilar C-30 - Retangular 14x30
P115 | FUNDAÇÃO | retangular | 14 | 30 | 0 | 0.75 % | 0.04 | 0.03 | Concreto - C-30 - Abatimento 12 cm | 0.02478 | Dimensionado | Forma - Estrutura - Concreto | 0.5192 | Dimensionado | Armadura - Aço CA50 - ø 10.0 mm | 3.6499 | Armadura - Aço CA60 - ø 5.0 mm | 1.02345 | Pilar C-30 - Retangular 14x30
P116 | FUNDAÇÃO | retangular | 17 | 30 | 0 | 0.62 % | 0.14 | 0.12 | Concreto - C-30 - Abatimento 12 cm | 0.0408 | Dimensionado | Forma - Estrutura - Concreto | 0.752 | Dimensionado | Armadura - Aço CA50 - ø 10.0 mm | 3.57592 | Armadura - Aço CA60 - ø 5.0 mm | 1.3718 | Pilar C-30 - Retangular 17x30
P117 | FUNDAÇÃO | retangular | 14 | 30 | 0 | Não calculado | Não calculado | Não calculado |  |  | Não dimensionado |  |  |  |  |  |  |  | Pilar C-30 - Retangular 14x30
P118 | FUNDAÇÃO | retangular | 14 | 30 | 0 | 0.75 % | 0.13 | 0.12 | Concreto - C-30 - Abatimento 12 cm | 0.0336 | Dimensionado | Forma - Estrutura - Concreto | 0.704 | Dimensionado | Armadura - Aço CA50 - ø 10.0 mm | 3.57592 | Armadura - Aço CA60 - ø 5.0 mm | 1.27931 | Pilar C-30 - Retangular 14x30
P119 | FUNDAÇÃO | retangular | 14 | 30 | 0 | 0.75 % | 0.16 | 0.14 | Concreto - C-30 - Abatimento 12 cm | 0.0336 | Dimensionado | Forma - Estrutura - Concreto | 0.704 | Dimensionado | Armadura - Aço CA50 - ø 10.0 mm | 4.40208 | Armadura - Aço CA60 - ø 5.0 mm | 1.27931 | Pilar C-30 - Retangular 14x30
P12 | FUNDAÇÃO | retangular | 14 | 30 | 0 | Não calculado | Não calculado | Não calculado |  |  | Não dimensionado |  |  |  |  |  |  |  | Pilar C-30 - Retangular 14x30
P120 | FUNDAÇÃO | retangular | 14 | 30 | 0 | 0.75 % | 0.13 | 0.11 | Concreto - C-30 - Abatimento 12 cm | 0.0336 | Dimensionado | Forma - Estrutura - Concreto | 0.704 | Dimensionado | Armadura - Aço CA50 - ø 10.0 mm | 3.57592 | Armadura - Aço CA60 - ø 5.0 mm | 1.27931 | Pilar C-30 - Retangular 14x30
P121 | FUNDAÇÃO | retangular | 14 | 30 | 0 | 0.75 % | 0.14 | 0.12 | Concreto - C-30 - Abatimento 12 cm | 0.0336 | Dimensionado | Forma - Estrutura - Concreto | 0.704 | Dimensionado | Armadura - Aço CA50 - ø 10.0 mm | 3.57592 | Armadura - Aço CA60 - ø 5.0 mm | 1.27931 | Pilar C-30 - Retangular 14x30
P122 | FUNDAÇÃO | retangular | 14 | 30 | 0 | 0.75 % | 0.15 | 0.13 | Concreto - C-30 - Abatimento 12 cm | 0.0336 | Dimensionado | Forma - Estrutura - Concreto | 0.704 | Dimensionado | Armadura - Aço CA50 - ø 10.0 mm | 3.57592 | Armadura - Aço CA60 - ø 5.0 mm | 1.27931 | Pilar C-30 - Retangular 14x30
P123 | FUNDAÇÃO | retangular | 14 | 30 | 0 | 0.75 % | 0.16 | 0.14 | Concreto - C-30 - Abatimento 12 cm | 0.0336 | Dimensionado | Forma - Estrutura - Concreto | 0.704 | Dimensionado | Armadura - Aço CA50 - ø 10.0 mm | 3.57592 | Armadura - Aço CA60 - ø 5.0 mm | 1.27931 | Pilar C-30 - Retangular 14x30
P124 | FUNDAÇÃO | retangular | 17 | 30 | 0 | 0.62 % | 0.12 | 0.11 | Concreto - C-30 - Abatimento 12 cm | 0.0408 | Dimensionado | Forma - Estrutura - Concreto | 0.751997 | Dimensionado | Armadura - Aço CA50 - ø 10.0 mm | 4.40208 | Armadura - Aço CA60 - ø 5.0 mm | 1.3718 | Pilar C-30 - Retangular 17x30
P125 | FUNDAÇÃO | retangular | 14 | 30 | 0 | Não calculado | Não calculado | Não calculado |  |  | Não dimensionado |  |  |  |  |  |  |  | Pilar C-30 - Retangular 14x30
P126 | FUNDAÇÃO | retangular | 14 | 30 | 0 | 0.75 % | 0.11 | 0.09 | Concreto - C-30 - Abatimento 12 cm | 0.0336 | Dimensionado | Forma - Estrutura - Concreto | 0.704 | Dimensionado | Armadura - Aço CA50 - ø 10.0 mm | 3.57592 | Armadura - Aço CA60 - ø 5.0 mm | 1.27931 | Pilar C-30 - Retangular 14x30
P127 | FUNDAÇÃO | retangular | 14 | 30 | 0 | 0.75 % | 0.1 | 0.09 | Concreto - C-30 - Abatimento 12 cm | 0.0336 | Dimensionado | Forma - Estrutura - Concreto | 0.704 | Dimensionado | Armadura - Aço CA50 - ø 10.0 mm | 3.57592 | Armadura - Aço CA60 - ø 5.0 mm | 1.27931 | Pilar C-30 - Retangular 14x30
P128 | FUNDAÇÃO | retangular | 14 | 30 | 0 | 0.75 % | 0.1 | 0.09 | Concreto - C-30 - Abatimento 12 cm | 0.0336 | Dimensionado | Forma - Estrutura - Concreto | 0.704 | Dimensionado | Armadura - Aço CA50 - ø 10.0 mm | 3.57592 | Armadura - Aço CA60 - ø 5.0 mm | 1.27931 | Pilar C-30 - Retangular 14x30
P129 | FUNDAÇÃO | retangular | 14 | 30 | 0 | 0.75 % | 0.16 | 0.14 | Concreto - C-30 - Abatimento 12 cm | 0.0336 | Dimensionado | Forma - Estrutura - Concreto | 0.704 | Dimensionado | Armadura - Aço CA50 - ø 10.0 mm | 3.57592 | Armadura - Aço CA60 - ø 5.0 mm | 1.27931 | Pilar C-30 - Retangular 14x30
P13 | FUNDAÇÃO | retangular | 14 | 30 | 0 | Não calculado | Não calculado | Não calculado |  |  | Não dimensionado |  |  |  |  |  |  |  | Pilar C-30 - Retangular 14x30
P130 | FUNDAÇÃO | retangular | 14 | 30 | 0 | 0.75 % | 0.04 | 0.03 | Concreto - C-30 - Abatimento 12 cm | 0.02478 | Dimensionado | Forma - Estrutura - Concreto | 0.5192 | Dimensionado | Armadura - Aço CA50 - ø 10.0 mm | 3.6499 | Armadura - Aço CA60 - ø 5.0 mm | 1.02345 | Pilar C-30 - Retangular 14x30
P131 | FUNDAÇÃO | retangular | 14 | 30 | 0 | 0.75 % | 0.12 | 0.1 | Concreto - C-30 - Abatimento 12 cm | 0.0336 | Dimensionado | Forma - Estrutura - Concreto | 0.704 | Dimensionado | Armadura - Aço CA50 - ø 10.0 mm | 3.57592 | Armadura - Aço CA60 - ø 5.0 mm | 1.27931 | Pilar C-30 - Retangular 14x30
P132 | FUNDAÇÃO | retangular | 14 | 30 | 0 | Não calculado | Não calculado | Não calculado |  |  | Não dimensionado |  |  |  |  |  |  |  | Pilar C-30 - Retangular 14x30
P133 | FUNDAÇÃO | retangular | 14 | 30 | 0 | Não calculado | Não calculado | Não calculado |  |  | Não dimensionado |  |  |  |  |  |  |  | Pilar C-30 - Retangular 14x30
P134 | FUNDAÇÃO | retangular | 14 | 30 | 0 | 0.75 % | 0.1 | 0.09 | Concreto - C-30 - Abatimento 12 cm | 0.0336 | Dimensionado | Forma - Estrutura - Concreto | 0.704 | Dimensionado | Armadura - Aço CA50 - ø 10.0 mm | 3.57592 | Armadura - Aço CA60 - ø 5.0 mm | 1.27931 | Pilar C-30 - Retangular 14x30
P135 | FUNDAÇÃO | retangular | 14 | 30 | 0 | 0.75 % | 0.13 | 0.11 | Concreto - C-30 - Abatimento 12 cm | 0.0336 | Dimensionado | Forma - Estrutura - Concreto | 0.704 | Dimensionado | Armadura - Aço CA50 - ø 10.0 mm | 5.22824 | Armadura - Aço CA60 - ø 5.0 mm | 1.27931 | Pilar C-30 - Retangular 14x30
P136 | FUNDAÇÃO | retangular | 14 | 30 | 0 | 0.75 % | 0.15 | 0.13 | Concreto - C-30 - Abatimento 12 cm | 0.0336 | Dimensionado | Forma - Estrutura - Concreto | 0.704 | Dimensionado | Armadura - Aço CA50 - ø 10.0 mm | 3.57592 | Armadura - Aço CA60 - ø 5.0 mm | 1.27931 | Pilar C-30 - Retangular 14x30
P137 | FUNDAÇÃO | retangular | 14 | 30 | 0 | 0.75 % | 0.11 | 0.1 | Concreto - C-30 - Abatimento 12 cm | 0.0336 | Dimensionado | Forma - Estrutura - Concreto | 0.704 | Dimensionado | Armadura - Aço CA50 - ø 10.0 mm | 3.57592 | Armadura - Aço CA60 - ø 5.0 mm | 1.27931 | Pilar C-30 - Retangular 14x30
P138 | FUNDAÇÃO | retangular | 14 | 30 | 0 | 0.75 % | 0.09 | 0.08 | Concreto - C-30 - Abatimento 12 cm | 0.0336 | Dimensionado | Forma - Estrutura - Concreto | 0.704 | Dimensionado | Armadura - Aço CA50 - ø 10.0 mm | 3.57592 | Armadura - Aço CA60 - ø 5.0 mm | 1.27931 | Pilar C-30 - Retangular 14x30
P139 | FUNDAÇÃO | retangular | 14 | 30 | 0 | 0.75 % | 0.12 | 0.1 | Concreto - C-30 - Abatimento 12 cm | 0.0336 | Dimensionado | Forma - Estrutura - Concreto | 0.704002 | Dimensionado | Armadura - Aço CA50 - ø 10.0 mm | 3.57592 | Armadura - Aço CA60 - ø 5.0 mm | 1.27931 | Pilar C-30 - Retangular 14x30
P14 | FUNDAÇÃO | retangular | 14 | 30 | 0 | 0.75 % | 0.04 | 0.03 | Concreto - C-30 - Abatimento 12 cm | 0.02478 | Dimensionado | Forma - Estrutura - Concreto | 0.5192 | Dimensionado | Armadura - Aço CA50 - ø 10.0 mm | 3.6499 | Armadura - Aço CA60 - ø 5.0 mm | 1.02345 | Pilar C-30 - Retangular 14x30
P140 | FUNDAÇÃO | retangular | 14 | 30 | 0 | 0.75 % | 0.15 | 0.13 | Concreto - C-30 - Abatimento 12 cm | 0.0336 | Dimensionado | Forma - Estrutura - Concreto | 0.704 | Dimensionado | Armadura - Aço CA50 - ø 10.0 mm | 5.22824 | Armadura - Aço CA60 - ø 5.0 mm | 1.27931 | Pilar C-30 - Retangular 14x30
P141 | FUNDAÇÃO | retangular | 14 | 30 | 0 | 0.75 % | 0.03 | 0.03 | Concreto - C-30 - Abatimento 12 cm | 0.0336 | Dimensionado | Forma - Estrutura - Concreto | 0.704002 | Dimensionado | Armadura - Aço CA50 - ø 10.0 mm | 3.57592 | Armadura - Aço CA60 - ø 5.0 mm | 1.27931 | Pilar C-30 - Retangular 14x30
P142 | FUNDAÇÃO | retangular | 14 | 30 | 0 | 0.75 % | 0.07 | 0.06 | Concreto - C-30 - Abatimento 12 cm | 0.02478 | Dimensionado | Forma - Estrutura - Concreto | 0.5192 | Dimensionado | Armadura - Aço CA50 - ø 10.0 mm | 3.6499 | Armadura - Aço CA60 - ø 5.0 mm | 1.02345 | Pilar C-30 - Retangular 14x30
P143 | FUNDAÇÃO | retangular | 14 | 30 | 0 | 0.75 % | 0.08 | 0.07 | Concreto - C-30 - Abatimento 12 cm | 0.0336 | Dimensionado | Forma - Estrutura - Concreto | 0.704 | Dimensionado | Armadura - Aço CA50 - ø 10.0 mm | 3.57592 | Armadura - Aço CA60 - ø 5.0 mm | 1.27931 | Pilar C-30 - Retangular 14x30
P144 | FUNDAÇÃO | retangular | 14 | 30 | 0 | Não calculado | Não calculado | Não calculado |  |  | Não dimensionado |  |  |  |  |  |  |  | Pilar C-30 - Retangular 14x30
P145 | FUNDAÇÃO | retangular | 14 | 30 | 0 | 0.75 % | 0.08 | 0.07 | Concreto - C-30 - Abatimento 12 cm | 0.0336 | Dimensionado | Forma - Estrutura - Concreto | 0.704 | Dimensionado | Armadura - Aço CA50 - ø 10.0 mm | 3.57592 | Armadura - Aço CA60 - ø 5.0 mm | 1.27931 | Pilar C-30 - Retangular 14x30
P146 | FUNDAÇÃO | retangular | 14 | 30 | 0 | 0.75 % | 0.13 | 0.11 | Concreto - C-30 - Abatimento 12 cm | 0.0336 | Dimensionado | Forma - Estrutura - Concreto | 0.704 | Dimensionado | Armadura - Aço CA50 - ø 10.0 mm | 3.57592 | Armadura - Aço CA60 - ø 5.0 mm | 1.27931 | Pilar C-30 - Retangular 14x30
P147 | FUNDAÇÃO | retangular | 14 | 30 | 0 | 0.75 % | 0.16 | 0.14 | Concreto - C-30 - Abatimento 12 cm | 0.0336 | Dimensionado | Forma - Estrutura - Concreto | 0.704 | Dimensionado | Armadura - Aço CA50 - ø 10.0 mm | 3.57592 | Armadura - Aço CA60 - ø 5.0 mm | 1.27931 | Pilar C-30 - Retangular 14x30
P148 | FUNDAÇÃO | retangular | 14 | 30 | 0 | 0.75 % | 0.16 | 0.14 | Concreto - C-30 - Abatimento 12 cm | 0.0336 | Dimensionado | Forma - Estrutura - Concreto | 0.704 | Dimensionado | Armadura - Aço CA50 - ø 10.0 mm | 3.57592 | Armadura - Aço CA60 - ø 5.0 mm | 1.27931 | Pilar C-30 - Retangular 14x30
P149 | FUNDAÇÃO | retangular | 14 | 30 | 0 | Não calculado | Não calculado | Não calculado |  |  | Não dimensionado |  |  |  |  |  |  |  | Pilar C-30 - Retangular 14x30
P15 | FUNDAÇÃO | retangular | 14 | 30 | 0 | Não calculado | Não calculado | Não calculado |  |  | Não dimensionado |  |  |  |  |  |  |  | Pilar C-30 - Retangular 14x30
P150 | FUNDAÇÃO | retangular | 14 | 30 | 0 | 0.75 % | 0.05 | 0.05 | Concreto - C-30 - Abatimento 12 cm | 0.0336 | Dimensionado | Forma - Estrutura - Concreto | 0.704 | Dimensionado | Armadura - Aço CA50 - ø 10.0 mm | 3.57592 | Armadura - Aço CA60 - ø 5.0 mm | 1.27931 | Pilar C-30 - Retangular 14x30
P151 | FUNDAÇÃO | seção circular | 0 | 80 | 0 | 1.60 % | 0.16 | 0.12 | Concreto - C-30 - Abatimento 12 cm | 0.195233 | Dimensionado | Forma - Estrutura - Concreto | 0.976167 | Dimensionado | Armadura - Aço CA50 - ø 16.0 mm | 135.737 | Armadura - Aço CA60 - ø 5.0 mm | 3.55126 | Pilar C-30 - Seção Circular 80
P152 | FUNDAÇÃO | retangular | 14 | 30 | 0 | 0.75 % | 0.02 | 0.02 | Concreto - C-30 - Abatimento 12 cm | 0.0336 | Dimensionado | Forma - Estrutura - Concreto | 0.704 | Dimensionado | Armadura - Aço CA50 - ø 10.0 mm | 3.57592 | Armadura - Aço CA60 - ø 5.0 mm | 1.27931 | Pilar C-30 - Retangular 14x30
P153 | FUNDAÇÃO | retangular | 14 | 30 | 0 | 0.75 % | 0.04 | 0.03 | Concreto - C-30 - Abatimento 12 cm | 0.0336 | Dimensionado | Forma - Estrutura - Concreto | 0.704 | Dimensionado | Armadura - Aço CA50 - ø 10.0 mm | 3.57592 | Armadura - Aço CA60 - ø 5.0 mm | 1.27931 | Pilar C-30 - Retangular 14x30
P154 | FUNDAÇÃO | retangular | 14 | 30 | 0 | 0.75 % | 0.03 | 0.02 | Concreto - C-30 - Abatimento 12 cm | 0.0336 | Dimensionado | Forma - Estrutura - Concreto | 0.704 | Dimensionado | Armadura - Aço CA50 - ø 10.0 mm | 3.57592 | Armadura - Aço CA60 - ø 5.0 mm | 1.27931 | Pilar C-30 - Retangular 14x30
P155 | FUNDAÇÃO | retangular | 14 | 30 | 0 | 0.75 % | 0.04 | 0.03 | Concreto - C-30 - Abatimento 12 cm | 0.02478 | Dimensionado | Forma - Estrutura - Concreto | 0.5192 | Dimensionado | Armadura - Aço CA50 - ø 10.0 mm | 3.6499 | Armadura - Aço CA60 - ø 5.0 mm | 1.02345 | Pilar C-30 - Retangular 14x30
P156 | FUNDAÇÃO | retangular | 14 | 30 | 0 | Não calculado | Não calculado | Não calculado |  |  | Não dimensionado |  |  |  |  |  |  |  | Pilar C-30 - Retangular 14x30
P157 | FUNDAÇÃO | retangular | 14 | 30 | 0 | Não calculado | Não calculado | Não calculado |  |  | Não dimensionado |  |  |  |  |  |  |  | Pilar C-30 - Retangular 14x30
P158 | FUNDAÇÃO | retangular | 14 | 30 | 0 | Não calculado | Não calculado | Não calculado |  |  | Não dimensionado |  |  |  |  |  |  |  | Pilar C-30 - Retangular 14x30
P159 | FUNDAÇÃO | retangular | 14 | 30 | 0 | Não calculado | Não calculado | Não calculado |  |  | Não dimensionado |  |  |  |  |  |  |  | Pilar C-30 - Retangular 14x30
P16 | FUNDAÇÃO | retangular | 14 | 30 | 0 | 0.75 % | 0.04 | 0.03 | Concreto - C-30 - Abatimento 12 cm | 0.02478 | Dimensionado | Forma - Estrutura - Concreto | 0.5192 | Dimensionado | Armadura - Aço CA50 - ø 10.0 mm | 3.6499 | Armadura - Aço CA60 - ø 5.0 mm | 1.02345 | Pilar C-30 - Retangular 14x30
P160 | FUNDAÇÃO | retangular | 14 | 30 | 0 | Não calculado | Não calculado | Não calculado |  |  | Não dimensionado |  |  |  |  |  |  |  | Pilar C-30 - Retangular 14x30
P161 | FUNDAÇÃO | retangular | 14 | 30 | 0 | Não calculado | Não calculado | Não calculado |  |  | Não dimensionado |  |  |  |  |  |  |  | Pilar C-30 - Retangular 14x30
P162 | FUNDAÇÃO | retangular | 14 | 30 | 0 | Não calculado | Não calculado | Não calculado |  |  | Não dimensionado |  |  |  |  |  |  |  | Pilar C-30 - Retangular 14x30
P163 | FUNDAÇÃO | retangular | 14 | 30 | 0 | Não calculado | Não calculado | Não calculado |  |  | Não dimensionado |  |  |  |  |  |  |  | Pilar C-30 - Retangular 14x30
P164 | FUNDAÇÃO | retangular | 14 | 30 | 0 | 0.75 % | 0.06 | 0.05 | Concreto - C-30 - Abatimento 12 cm | 0.02478 | Dimensionado | Forma - Estrutura - Concreto | 0.5192 | Dimensionado | Armadura - Aço CA50 - ø 10.0 mm | 3.6499 | Armadura - Aço CA60 - ø 5.0 mm | 1.02345 | Pilar C-30 - Retangular 14x30
P165 | FUNDAÇÃO | retangular | 14 | 30 | 0 | 0.75 % | 0.06 | 0.06 | Concreto - C-30 - Abatimento 12 cm | 0.02478 | Dimensionado | Forma - Estrutura - Concreto | 0.5192 | Dimensionado | Armadura - Aço CA50 - ø 10.0 mm | 3.6499 | Armadura - Aço CA60 - ø 5.0 mm | 1.02345 | Pilar C-30 - Retangular 14x30
P166 | FUNDAÇÃO | retangular | 14 | 30 | 0 | Não calculado | Não calculado | Não calculado |  |  | Não dimensionado |  |  |  |  |  |  |  | Pilar C-30 - Retangular 14x30
P167 | FUNDAÇÃO | retangular | 14 | 30 | 0 | Não calculado | Não calculado | Não calculado |  |  | Não dimensionado |  |  |  |  |  |  |  | Pilar C-30 - Retangular 14x30
P168 | FUNDAÇÃO | retangular | 14 | 30 | 0 | 0.75 % | 0.05 | 0.04 | Concreto - C-30 - Abatimento 12 cm | 0.02478 | Dimensionado | Forma - Estrutura - Concreto | 0.5192 | Dimensionado | Armadura - Aço CA50 - ø 10.0 mm | 3.6499 | Armadura - Aço CA60 - ø 5.0 mm | 1.02345 | Pilar C-30 - Retangular 14x30
P17 | FUNDAÇÃO | retangular | 14 | 30 | 0 | 0.75 % | 0.09 | 0.08 | Concreto - C-30 - Abatimento 12 cm | 0.0336 | Dimensionado | Forma - Estrutura - Concreto | 0.704 | Dimensionado | Armadura - Aço CA50 - ø 10.0 mm | 3.57592 | Armadura - Aço CA60 - ø 5.0 mm | 1.27931 | Pilar C-30 - Retangular 14x30
P18 | FUNDAÇÃO | retangular | 14 | 30 | 0 | Não calculado | Não calculado | Não calculado |  |  | Não dimensionado |  |  |  |  |  |  |  | Pilar C-30 - Retangular 14x30
P19 | FUNDAÇÃO | retangular | 14 | 30 | 0 | 0.75 % | 0.13 | 0.12 | Concreto - C-30 - Abatimento 12 cm | 0.0336 | Dimensionado | Forma - Estrutura - Concreto | 0.704 | Dimensionado | Armadura - Aço CA50 - ø 10.0 mm | 3.57592 | Armadura - Aço CA60 - ø 5.0 mm | 1.27931 | Pilar C-30 - Retangular 14x30
P2 | FUNDAÇÃO | retangular | 14 | 30 | 0 | Não calculado | Não calculado | Não calculado |  |  | Não dimensionado |  |  |  |  |  |  |  | Pilar C-30 - Retangular 14x30
P20 | FUNDAÇÃO | retangular | 14 | 30 | 0 | 0.75 % | 0.18 | 0.15 | Concreto - C-30 - Abatimento 12 cm | 0.0336 | Dimensionado | Forma - Estrutura - Concreto | 0.704 | Dimensionado | Armadura - Aço CA50 - ø 10.0 mm | 3.57592 | Armadura - Aço CA60 - ø 5.0 mm | 1.27931 | Pilar C-30 - Retangular 14x30
P21 | FUNDAÇÃO | retangular | 14 | 30 | 0 | Não calculado | Não calculado | Não calculado |  |  | Não dimensionado |  |  |  |  |  |  |  | Pilar C-30 - Retangular 14x30
P22 | FUNDAÇÃO | retangular | 14 | 30 | 0 | 0.75 % | 0.08 | 0.07 | Concreto - C-30 - Abatimento 12 cm | 0.0336 | Dimensionado | Forma - Estrutura - Concreto | 0.704 | Dimensionado | Armadura - Aço CA50 - ø 10.0 mm | 3.57592 | Armadura - Aço CA60 - ø 5.0 mm | 1.27931 | Pilar C-30 - Retangular 14x30
P23 | FUNDAÇÃO | retangular | 14 | 30 | 0 | 0.75 % | 0.13 | 0.11 | Concreto - C-30 - Abatimento 12 cm | 0.0336 | Dimensionado | Forma - Estrutura - Concreto | 0.704 | Dimensionado | Armadura - Aço CA50 - ø 10.0 mm | 3.57592 | Armadura - Aço CA60 - ø 5.0 mm | 1.27931 | Pilar C-30 - Retangular 14x30
P24 | FUNDAÇÃO | retangular | 14 | 30 | 0 | 0.75 % | 0.15 | 0.13 | Concreto - C-30 - Abatimento 12 cm | 0.0336 | Dimensionado | Forma - Estrutura - Concreto | 0.704 | Dimensionado | Armadura - Aço CA50 - ø 10.0 mm | 3.57592 | Armadura - Aço CA60 - ø 5.0 mm | 1.27931 | Pilar C-30 - Retangular 14x30
P25 | FUNDAÇÃO | retangular | 14 | 30 | 0 | 0.75 % | 0.1 | 0.09 | Concreto - C-30 - Abatimento 12 cm | 0.0336 | Dimensionado | Forma - Estrutura - Concreto | 0.704 | Dimensionado | Armadura - Aço CA50 - ø 10.0 mm | 3.57592 | Armadura - Aço CA60 - ø 5.0 mm | 1.27931 | Pilar C-30 - Retangular 14x30
P26 | FUNDAÇÃO | retangular | 17 | 30 | 0 | 0.62 % | 0.11 | 0.1 | Concreto - C-30 - Abatimento 12 cm | 0.0408 | Dimensionado | Forma - Estrutura - Concreto | 0.752 | Dimensionado | Armadura - Aço CA50 - ø 10.0 mm | 5.22824 | Armadura - Aço CA60 - ø 5.0 mm | 1.3718 | Pilar C-30 - Retangular 17x30
P27 | FUNDAÇÃO | retangular | 14 | 30 | 0 | 0.75 % | 0.13 | 0.12 | Concreto - C-30 - Abatimento 12 cm | 0.0336 | Dimensionado | Forma - Estrutura - Concreto | 0.704 | Dimensionado | Armadura - Aço CA50 - ø 10.0 mm | 3.57592 | Armadura - Aço CA60 - ø 5.0 mm | 1.27931 | Pilar C-30 - Retangular 14x30
P28 | FUNDAÇÃO | retangular | 14 | 30 | 0 | 0.75 % | 0.13 | 0.11 | Concreto - C-30 - Abatimento 12 cm | 0.0336 | Dimensionado | Forma - Estrutura - Concreto | 0.704 | Dimensionado | Armadura - Aço CA50 - ø 10.0 mm | 3.57592 | Armadura - Aço CA60 - ø 5.0 mm | 1.27931 | Pilar C-30 - Retangular 14x30
P29 | FUNDAÇÃO | retangular | 14 | 30 | 0 | Não calculado | Não calculado | Não calculado |  |  | Não dimensionado |  |  |  |  |  |  |  | Pilar C-30 - Retangular 14x30
P3 | FUNDAÇÃO | retangular | 14 | 30 | 0 | Não calculado | Não calculado | Não calculado |  |  | Não dimensionado |  |  |  |  |  |  |  | Pilar C-30 - Retangular 14x30
P30 | FUNDAÇÃO | retangular | 14 | 30 | 0 | 0.75 % | 0.04 | 0.03 | Concreto - C-30 - Abatimento 12 cm | 0.02478 | Dimensionado | Forma - Estrutura - Concreto | 0.5192 | Dimensionado | Armadura - Aço CA50 - ø 10.0 mm | 3.6499 | Armadura - Aço CA60 - ø 5.0 mm | 1.02345 | Pilar C-30 - Retangular 14x30
P31 | FUNDAÇÃO | retangular | 14 | 30 | 0 | Não calculado | Não calculado | Não calculado |  |  | Não dimensionado |  |  |  |  |  |  |  | Pilar C-30 - Retangular 14x30
P32 | FUNDAÇÃO | retangular | 14 | 30 | 0 | 0.75 % | 0.06 | 0.05 | Concreto - C-30 - Abatimento 12 cm | 0.0336 | Dimensionado | Forma - Estrutura - Concreto | 0.704 | Dimensionado | Armadura - Aço CA50 - ø 10.0 mm | 3.57592 | Armadura - Aço CA60 - ø 5.0 mm | 1.27931 | Pilar C-30 - Retangular 14x30
P33 | FUNDAÇÃO | retangular | 14 | 30 | 0 | 0.75 % | 0.13 | 0.11 | Concreto - C-30 - Abatimento 12 cm | 0.0336 | Dimensionado | Forma - Estrutura - Concreto | 0.704 | Dimensionado | Armadura - Aço CA50 - ø 10.0 mm | 3.57592 | Armadura - Aço CA60 - ø 5.0 mm | 1.27931 | Pilar C-30 - Retangular 14x30
P34 | FUNDAÇÃO | retangular | 14 | 30 | 0 | 0.75 % | 0.15 | 0.13 | Concreto - C-30 - Abatimento 12 cm | 0.0336 | Dimensionado | Forma - Estrutura - Concreto | 0.704 | Dimensionado | Armadura - Aço CA50 - ø 10.0 mm | 3.57592 | Armadura - Aço CA60 - ø 5.0 mm | 1.27931 | Pilar C-30 - Retangular 14x30
P35 | FUNDAÇÃO | retangular | 14 | 30 | 0 | Não calculado | Não calculado | Não calculado |  |  | Não dimensionado |  |  |  |  |  |  |  | Pilar C-30 - Retangular 14x30
P36 | FUNDAÇÃO | retangular | 17 | 30 | 0 | 0.62 % | 0.14 | 0.12 | Concreto - C-30 - Abatimento 12 cm | 0.0408 | Dimensionado | Forma - Estrutura - Concreto | 0.752 | Dimensionado | Armadura - Aço CA50 - ø 10.0 mm | 3.57592 | Armadura - Aço CA60 - ø 5.0 mm | 1.3718 | Pilar C-30 - Retangular 17x30
P37 | FUNDAÇÃO | retangular | 14 | 30 | 0 | Não calculado | Não calculado | Não calculado |  |  | Não dimensionado |  |  |  |  |  |  |  | Pilar C-30 - Retangular 14x30
P38 | FUNDAÇÃO | retangular | 14 | 30 | 0 | 0.75 % | 0.04 | 0.03 | Concreto - C-30 - Abatimento 12 cm | 0.02478 | Dimensionado | Forma - Estrutura - Concreto | 0.5192 | Dimensionado | Armadura - Aço CA50 - ø 10.0 mm | 3.6499 | Armadura - Aço CA60 - ø 5.0 mm | 1.02345 | Pilar C-30 - Retangular 14x30
P39 | FUNDAÇÃO | retangular | 14 | 30 | 0 | 0.75 % | 0.14 | 0.13 | Concreto - C-30 - Abatimento 12 cm | 0.0336 | Dimensionado | Forma - Estrutura - Concreto | 0.704 | Dimensionado | Armadura - Aço CA50 - ø 10.0 mm | 3.57592 | Armadura - Aço CA60 - ø 5.0 mm | 1.27931 | Pilar C-30 - Retangular 14x30
P4 | FUNDAÇÃO | retangular | 14 | 30 | 0 | Não calculado | Não calculado | Não calculado |  |  | Não dimensionado |  |  |  |  |  |  |  | Pilar C-30 - Retangular 14x30
P40 | FUNDAÇÃO | retangular | 14 | 30 | 0 | 0.75 % | 0.21 | 0.18 | Concreto - C-30 - Abatimento 12 cm | 0.0336 | Dimensionado | Forma - Estrutura - Concreto | 0.704 | Dimensionado | Armadura - Aço CA50 - ø 10.0 mm | 3.57592 | Armadura - Aço CA60 - ø 5.0 mm | 1.27931 | Pilar C-30 - Retangular 14x30
P41 | FUNDAÇÃO | retangular | 17 | 30 | 0 | 0.62 % | 0.09 | 0.08 | Concreto - C-30 - Abatimento 12 cm | 0.0408 | Dimensionado | Forma - Estrutura - Concreto | 0.752 | Dimensionado | Armadura - Aço CA50 - ø 10.0 mm | 3.57592 | Armadura - Aço CA60 - ø 5.0 mm | 1.3718 | Pilar C-30 - Retangular 17x30
P42 | FUNDAÇÃO | retangular | 17 | 30 | 0 | 0.62 % | 0.16 | 0.14 | Concreto - C-30 - Abatimento 12 cm | 0.0408 | Dimensionado | Forma - Estrutura - Concreto | 0.752 | Dimensionado | Armadura - Aço CA50 - ø 10.0 mm | 4.40208 | Armadura - Aço CA60 - ø 5.0 mm | 1.3718 | Pilar C-30 - Retangular 17x30
P43 | FUNDAÇÃO | retangular | 14 | 30 | 0 | 0.75 % | 0.19 | 0.17 | Concreto - C-30 - Abatimento 12 cm | 0.0336 | Dimensionado | Forma - Estrutura - Concreto | 0.704 | Dimensionado | Armadura - Aço CA50 - ø 10.0 mm | 3.57592 | Armadura - Aço CA60 - ø 5.0 mm | 1.27931 | Pilar C-30 - Retangular 14x30
P44 | FUNDAÇÃO | retangular | 14 | 30 | 0 | 0.75 % | 0.2 | 0.18 | Concreto - C-30 - Abatimento 12 cm | 0.0336 | Dimensionado | Forma - Estrutura - Concreto | 0.704 | Dimensionado | Armadura - Aço CA50 - ø 10.0 mm | 3.57592 | Armadura - Aço CA60 - ø 5.0 mm | 1.27931 | Pilar C-30 - Retangular 14x30
P45 | FUNDAÇÃO | retangular | 17 | 30 | 0 | 0.62 % | 0.12 | 0.11 | Concreto - C-30 - Abatimento 12 cm | 0.0408 | Dimensionado | Forma - Estrutura - Concreto | 0.752 | Dimensionado | Armadura - Aço CA50 - ø 10.0 mm | 4.40208 | Armadura - Aço CA60 - ø 5.0 mm | 1.3718 | Pilar C-30 - Retangular 17x30
P46 | FUNDAÇÃO | retangular | 14 | 30 | 0 | Não calculado | Não calculado | Não calculado |  |  | Não dimensionado |  |  |  |  |  |  |  | Pilar C-30 - Retangular 14x30
P47 | FUNDAÇÃO | retangular | 17 | 30 | 0 | 0.62 % | 0.13 | 0.12 | Concreto - C-30 - Abatimento 12 cm | 0.0408 | Dimensionado | Forma - Estrutura - Concreto | 0.752 | Dimensionado | Armadura - Aço CA50 - ø 10.0 mm | 4.40208 | Armadura - Aço CA60 - ø 5.0 mm | 1.3718 | Pilar C-30 - Retangular 17x30
P48 | FUNDAÇÃO | retangular | 14 | 30 | 0 | Não calculado | Não calculado | Não calculado |  |  | Não dimensionado |  |  |  |  |  |  |  | Pilar C-30 - Retangular 14x30
P49 | FUNDAÇÃO | retangular | 14 | 30 | 0 | 0.75 % | 0.11 | 0.1 | Concreto - C-30 - Abatimento 12 cm | 0.0336 | Dimensionado | Forma - Estrutura - Concreto | 0.704 | Dimensionado | Armadura - Aço CA50 - ø 10.0 mm | 3.57592 | Armadura - Aço CA60 - ø 5.0 mm | 1.27931 | Pilar C-30 - Retangular 14x30
P5 | FUNDAÇÃO | retangular | 14 | 30 | 0 | Não calculado | Não calculado | Não calculado |  |  | Não dimensionado |  |  |  |  |  |  |  | Pilar C-30 - Retangular 14x30
P50 | FUNDAÇÃO | retangular | 14 | 30 | 0 | 0.75 % | 0.17 | 0.15 | Concreto - C-30 - Abatimento 12 cm | 0.0336 | Dimensionado | Forma - Estrutura - Concreto | 0.704 | Dimensionado | Armadura - Aço CA50 - ø 10.0 mm | 3.57592 | Armadura - Aço CA60 - ø 5.0 mm | 1.27931 | Pilar C-30 - Retangular 14x30
P51 | FUNDAÇÃO | retangular | 17 | 30 | 0 | 0.62 % | 0.1 | 0.09 | Concreto - C-30 - Abatimento 12 cm | 0.0408 | Dimensionado | Forma - Estrutura - Concreto | 0.752 | Dimensionado | Armadura - Aço CA50 - ø 10.0 mm | 3.57592 | Armadura - Aço CA60 - ø 5.0 mm | 1.3718 | Pilar C-30 - Retangular 17x30
P52 | FUNDAÇÃO | retangular | 17 | 30 | 0 | 0.62 % | 0.09 | 0.08 | Concreto - C-30 - Abatimento 12 cm | 0.0408 | Dimensionado | Forma - Estrutura - Concreto | 0.752 | Dimensionado | Armadura - Aço CA50 - ø 10.0 mm | 3.57592 | Armadura - Aço CA60 - ø 5.0 mm | 1.3718 | Pilar C-30 - Retangular 17x30
P53 | FUNDAÇÃO | retangular | 14 | 30 | 0 | 0.75 % | 0.08 | 0.07 | Concreto - C-30 - Abatimento 12 cm | 0.0336 | Dimensionado | Forma - Estrutura - Concreto | 0.704 | Dimensionado | Armadura - Aço CA50 - ø 10.0 mm | 3.57592 | Armadura - Aço CA60 - ø 5.0 mm | 1.27931 | Pilar C-30 - Retangular 14x30
P54 | FUNDAÇÃO | retangular | 14 | 30 | 0 | 0.75 % | 0.14 | 0.12 | Concreto - C-30 - Abatimento 12 cm | 0.0336 | Dimensionado | Forma - Estrutura - Concreto | 0.704 | Dimensionado | Armadura - Aço CA50 - ø 10.0 mm | 3.57592 | Armadura - Aço CA60 - ø 5.0 mm | 1.27931 | Pilar C-30 - Retangular 14x30
P55 | FUNDAÇÃO | retangular | 14 | 30 | 0 | 0.75 % | 0.18 | 0.16 | Concreto - C-30 - Abatimento 12 cm | 0.0336 | Dimensionado | Forma - Estrutura - Concreto | 0.704 | Dimensionado | Armadura - Aço CA50 - ø 10.0 mm | 3.57592 | Armadura - Aço CA60 - ø 5.0 mm | 1.27931 | Pilar C-30 - Retangular 14x30
P56 | FUNDAÇÃO | retangular | 17 | 30 | 0 | 0.62 % | 0.13 | 0.12 | Concreto - C-30 - Abatimento 12 cm | 0.0408 | Dimensionado | Forma - Estrutura - Concreto | 0.752 | Dimensionado | Armadura - Aço CA50 - ø 10.0 mm | 3.57592 | Armadura - Aço CA60 - ø 5.0 mm | 1.3718 | Pilar C-30 - Retangular 17x30
P57 | FUNDAÇÃO | retangular | 14 | 30 | 0 | 0.75 % | 0.04 | 0.03 | Concreto - C-30 - Abatimento 12 cm | 0.02478 | Dimensionado | Forma - Estrutura - Concreto | 0.5192 | Dimensionado | Armadura - Aço CA50 - ø 10.0 mm | 3.6499 | Armadura - Aço CA60 - ø 5.0 mm | 1.02345 | Pilar C-30 - Retangular 14x30
P58 | FUNDAÇÃO | retangular | 14 | 30 | 0 | 0.75 % | 0.11 | 0.1 | Concreto - C-30 - Abatimento 12 cm | 0.0336 | Dimensionado | Forma - Estrutura - Concreto | 0.704 | Dimensionado | Armadura - Aço CA50 - ø 10.0 mm | 4.40208 | Armadura - Aço CA60 - ø 5.0 mm | 1.27931 | Pilar C-30 - Retangular 14x30
P59 | FUNDAÇÃO | retangular | 14 | 30 | 0 | Não calculado | Não calculado | Não calculado |  |  | Não dimensionado |  |  |  |  |  |  |  | Pilar C-30 - Retangular 14x30
P6 | FUNDAÇÃO | retangular | 14 | 30 | 0 | Não calculado | Não calculado | Não calculado |  |  | Não dimensionado |  |  |  |  |  |  |  | Pilar C-30 - Retangular 14x30
P60 | FUNDAÇÃO | retangular | 14 | 30 | 0 | 0.75 % | 0.13 | 0.12 | Concreto - C-30 - Abatimento 12 cm | 0.0336 | Dimensionado | Forma - Estrutura - Concreto | 0.704 | Dimensionado | Armadura - Aço CA50 - ø 10.0 mm | 3.57592 | Armadura - Aço CA60 - ø 5.0 mm | 1.27931 | Pilar C-30 - Retangular 14x30
P61 | FUNDAÇÃO | retangular | 14 | 30 | 0 | Não calculado | Não calculado | Não calculado |  |  | Não dimensionado |  |  |  |  |  |  |  | Pilar C-30 - Retangular 14x30
P62 | FUNDAÇÃO | retangular | 14 | 30 | 0 | 0.75 % | 0.14 | 0.12 | Concreto - C-30 - Abatimento 12 cm | 0.0336 | Dimensionado | Forma - Estrutura - Concreto | 0.704 | Dimensionado | Armadura - Aço CA50 - ø 10.0 mm | 3.57592 | Armadura - Aço CA60 - ø 5.0 mm | 1.27931 | Pilar C-30 - Retangular 14x30
P63 | FUNDAÇÃO | retangular | 14 | 30 | 0 | 0.75 % | 0.05 | 0.04 | Concreto - C-30 - Abatimento 12 cm | 0.02478 | Dimensionado | Forma - Estrutura - Concreto | 0.5192 | Dimensionado | Armadura - Aço CA50 - ø 10.0 mm | 3.6499 | Armadura - Aço CA60 - ø 5.0 mm | 1.02345 | Pilar C-30 - Retangular 14x30
P64 | FUNDAÇÃO | retangular | 14 | 30 | 0 | Não calculado | Não calculado | Não calculado |  |  | Não dimensionado |  |  |  |  |  |  |  | Pilar C-30 - Retangular 14x30
P65 | FUNDAÇÃO | retangular | 17 | 30 | 0 | 0.62 % | 0.11 | 0.1 | Concreto - C-30 - Abatimento 12 cm | 0.0408 | Dimensionado | Forma - Estrutura - Concreto | 0.752 | Dimensionado | Armadura - Aço CA50 - ø 10.0 mm | 4.40208 | Armadura - Aço CA60 - ø 5.0 mm | 1.3718 | Pilar C-30 - Retangular 17x30
P66 | FUNDAÇÃO | retangular | 14 | 30 | 0 | 0.75 % | 0.17 | 0.15 | Concreto - C-30 - Abatimento 12 cm | 0.0336 | Dimensionado | Forma - Estrutura - Concreto | 0.704 | Dimensionado | Armadura - Aço CA50 - ø 10.0 mm | 3.57592 | Armadura - Aço CA60 - ø 5.0 mm | 1.27931 | Pilar C-30 - Retangular 14x30
P67 | FUNDAÇÃO | retangular | 14 | 20 | 0 | Não calculado | Não calculado | Não calculado |  |  | Não dimensionado |  |  |  |  |  |  |  | Pilar C-30 - Retangular 14x20
P68 | FUNDAÇÃO | retangular | 20 | 20 | 30 | Não calculado | Não calculado | Não calculado |  |  | Não dimensionado |  |  |  |  |  |  |  | Pilar C-30 - Retangular 20x20
P69 | FUNDAÇÃO | retangular | 14 | 30 | 0 | 0.75 % | 0.13 | 0.12 | Concreto - C-30 - Abatimento 12 cm | 0.0336 | Dimensionado | Forma - Estrutura - Concreto | 0.704 | Dimensionado | Armadura - Aço CA50 - ø 10.0 mm | 5.22824 | Armadura - Aço CA60 - ø 5.0 mm | 1.27931 | Pilar C-30 - Retangular 14x30
P7 | FUNDAÇÃO | retangular | 14 | 30 | 0 | Não calculado | Não calculado | Não calculado |  |  | Não dimensionado |  |  |  |  |  |  |  | Pilar C-30 - Retangular 14x30
P70 | FUNDAÇÃO | retangular | 14 | 30 | 0 | Não calculado | Não calculado | Não calculado |  |  | Não dimensionado |  |  |  |  |  |  |  | Pilar C-30 - Retangular 14x30
P71 | FUNDAÇÃO | retangular | 14 | 30 | 0 | 0.75 % | 0.22 | 0.19 | Concreto - C-30 - Abatimento 12 cm | 0.0336 | Dimensionado | Forma - Estrutura - Concreto | 0.704 | Dimensionado | Armadura - Aço CA50 - ø 10.0 mm | 3.57592 | Armadura - Aço CA60 - ø 5.0 mm | 1.27931 | Pilar C-30 - Retangular 14x30
P72 | FUNDAÇÃO | retangular | 14 | 30 | 0 | 0.75 % | 0.14 | 0.12 | Concreto - C-30 - Abatimento 12 cm | 0.0336 | Dimensionado | Forma - Estrutura - Concreto | 0.704 | Dimensionado | Armadura - Aço CA50 - ø 10.0 mm | 3.57592 | Armadura - Aço CA60 - ø 5.0 mm | 1.27931 | Pilar C-30 - Retangular 14x30
P73 | FUNDAÇÃO | retangular | 14 | 35 | 0 | 0.96 % | 0.12 | 0.1 | Concreto - C-30 - Abatimento 12 cm | 0.0392 | Dimensionado | Forma - Estrutura - Concreto | 0.784 | Dimensionado | Armadura - Aço CA50 - ø 10.0 mm | 5.54884 | Armadura - Aço CA60 - ø 5.0 mm | 1.81879 | Pilar C-30 - Retangular 14x35
P74 | FUNDAÇÃO | retangular | 24 | 30 | 0 | 0.44 % | 0.07 | 0.06 | Concreto - C-30 - Abatimento 12 cm | 0.0576 | Dimensionado | Forma - Estrutura - Concreto | 0.864 | Dimensionado | Armadura - Aço CA50 - ø 10.0 mm | 3.57592 | Armadura - Aço CA60 - ø 5.0 mm | 1.58758 | Pilar C-30 - Retangular 24x30
P75 | FUNDAÇÃO | retangular | 14 | 30 | 0 | Não calculado | Não calculado | Não calculado |  |  | Não dimensionado |  |  |  |  |  |  |  | Pilar C-30 - Retangular 14x30
P76 | FUNDAÇÃO | retangular | 14 | 25 | 0 | Não calculado | Não calculado | Não calculado |  |  | Não dimensionado |  |  |  |  |  |  |  | Pilar C-30 - Retangular 14x25
P77 | FUNDAÇÃO | retangular | 14 | 30 | 0 | Não calculado | Não calculado | Não calculado |  |  | Não dimensionado |  |  |  |  |  |  |  | Pilar C-30 - Retangular 14x30
P78 | FUNDAÇÃO | retangular | 14 | 30 | 0 | Não calculado | Não calculado | Não calculado |  |  | Não dimensionado |  |  |  |  |  |  |  | Pilar C-30 - Retangular 14x30
P79 | FUNDAÇÃO | retangular | 14 | 30 | 0 | 0.75 % | 0.06 | 0.06 | Concreto - C-30 - Abatimento 12 cm | 0.0336 | Dimensionado | Forma - Estrutura - Concreto | 0.704 | Dimensionado | Armadura - Aço CA50 - ø 10.0 mm | 3.57592 | Armadura - Aço CA60 - ø 5.0 mm | 1.27931 | Pilar C-30 - Retangular 14x30
P8 | FUNDAÇÃO | retangular | 14 | 30 | 0 | Não calculado | Não calculado | Não calculado |  |  | Não dimensionado |  |  |  |  |  |  |  | Pilar C-30 - Retangular 14x30
P80 | FUNDAÇÃO | retangular | 14 | 30 | 0 | 0.75 % | 0.07 | 0.06 | Concreto - C-30 - Abatimento 12 cm | 0.0336 | Dimensionado | Forma - Estrutura - Concreto | 0.704 | Dimensionado | Armadura - Aço CA50 - ø 10.0 mm | 3.57592 | Armadura - Aço CA60 - ø 5.0 mm | 1.27931 | Pilar C-30 - Retangular 14x30
P81 | FUNDAÇÃO | retangular | 14 | 30 | 0 | Não calculado | Não calculado | Não calculado |  |  | Não dimensionado |  |  |  |  |  |  |  | Pilar C-30 - Retangular 14x30
P82 | FUNDAÇÃO | retangular | 14 | 30 | 0 | Não calculado | Não calculado | Não calculado |  |  | Não dimensionado |  |  |  |  |  |  |  | Pilar C-30 - Retangular 14x30
P83 | FUNDAÇÃO | retangular | 14 | 30 | 0 | Não calculado | Não calculado | Não calculado |  |  | Não dimensionado |  |  |  |  |  |  |  | Pilar C-30 - Retangular 14x30
P84 | FUNDAÇÃO | retangular | 14 | 30 | 0 | Não calculado | Não calculado | Não calculado |  |  | Não dimensionado |  |  |  |  |  |  |  | Pilar C-30 - Retangular 14x30
P85 | FUNDAÇÃO | retangular | 14 | 25 | 0 | Não calculado | Não calculado | Não calculado |  |  | Não dimensionado |  |  |  |  |  |  |  | Pilar C-30 - Retangular 14x25
P86 | FUNDAÇÃO | retangular | 14 | 30 | 0 | Não calculado | Não calculado | Não calculado |  |  | Não dimensionado |  |  |  |  |  |  |  | Pilar C-30 - Retangular 14x30
P87 | FUNDAÇÃO | retangular | 14 | 30 | 0 | 0.75 % | 0.18 | 0.16 | Concreto - C-30 - Abatimento 12 cm | 0.0336 | Dimensionado | Forma - Estrutura - Concreto | 0.704 | Dimensionado | Armadura - Aço CA50 - ø 10.0 mm | 3.57592 | Armadura - Aço CA60 - ø 5.0 mm | 1.27931 | Pilar C-30 - Retangular 14x30
P88 | FUNDAÇÃO | retangular | 20 | 20 | 0 | Não calculado | Não calculado | Não calculado |  |  | Não dimensionado |  |  |  |  |  |  |  | Pilar C-30 - Retangular 20x20
P89 | FUNDAÇÃO | retangular | 14 | 20 | 30 | Não calculado | Não calculado | Não calculado |  |  | Não dimensionado |  |  |  |  |  |  |  | Pilar C-30 - Retangular 14x20
P9 | FUNDAÇÃO | retangular | 14 | 30 | 0 | Não calculado | Não calculado | Não calculado |  |  | Não dimensionado |  |  |  |  |  |  |  | Pilar C-30 - Retangular 14x30
P90 | FUNDAÇÃO | retangular | 14 | 30 | 0 | 0.75 % | 0.07 | 0.06 | Concreto - C-30 - Abatimento 12 cm | 0.0336 | Dimensionado | Forma - Estrutura - Concreto | 0.704 | Dimensionado | Armadura - Aço CA50 - ø 10.0 mm | 3.57592 | Armadura - Aço CA60 - ø 5.0 mm | 1.27931 | Pilar C-30 - Retangular 14x30
P91 | FUNDAÇÃO | retangular | 14 | 30 | 0 | 0.75 % | 0.1 | 0.08 | Concreto - C-30 - Abatimento 12 cm | 0.0336 | Dimensionado | Forma - Estrutura - Concreto | 0.704 | Dimensionado | Armadura - Aço CA50 - ø 10.0 mm | 3.57592 | Armadura - Aço CA60 - ø 5.0 mm | 1.27931 | Pilar C-30 - Retangular 14x30
P92 | FUNDAÇÃO | retangular | 24 | 30 | 0 | 0.44 % | 0.03 | 0.03 | Concreto - C-30 - Abatimento 12 cm | 0.0576 | Dimensionado | Forma - Estrutura - Concreto | 0.864 | Dimensionado | Armadura - Aço CA50 - ø 10.0 mm | 3.57592 | Armadura - Aço CA60 - ø 5.0 mm | 1.58758 | Pilar C-30 - Retangular 24x30
P93 | FUNDAÇÃO | retangular | 14 | 30 | 0 | Não calculado | Não calculado | Não calculado |  |  | Não dimensionado |  |  |  |  |  |  |  | Pilar C-30 - Retangular 14x30
P94 | FUNDAÇÃO | retangular | 17 | 30 | 0 | 0.62 % | 0.11 | 0.1 | Concreto - C-30 - Abatimento 12 cm | 0.0408 | Dimensionado | Forma - Estrutura - Concreto | 0.752 | Dimensionado | Armadura - Aço CA50 - ø 10.0 mm | 4.40208 | Armadura - Aço CA60 - ø 5.0 mm | 1.3718 | Pilar C-30 - Retangular 17x30
P95 | FUNDAÇÃO | retangular | 14 | 30 | 0 | 0.75 % | 0.17 | 0.15 | Concreto - C-30 - Abatimento 12 cm | 0.0336 | Dimensionado | Forma - Estrutura - Concreto | 0.704 | Dimensionado | Armadura - Aço CA50 - ø 10.0 mm | 3.57592 | Armadura - Aço CA60 - ø 5.0 mm | 1.27931 | Pilar C-30 - Retangular 14x30
P96 | FUNDAÇÃO | retangular | 17 | 30 | 0 | 0.62 % | 0.11 | 0.1 | Concreto - C-30 - Abatimento 12 cm | 0.0408 | Dimensionado | Forma - Estrutura - Concreto | 0.752 | Dimensionado | Armadura - Aço CA50 - ø 10.0 mm | 3.57592 | Armadura - Aço CA60 - ø 5.0 mm | 1.3718 | Pilar C-30 - Retangular 17x30
P97 | FUNDAÇÃO | retangular | 17 | 30 | 0 | 0.62 % | 0.1 | 0.09 | Concreto - C-30 - Abatimento 12 cm | 0.0408 | Dimensionado | Forma - Estrutura - Concreto | 0.752 | Dimensionado | Armadura - Aço CA50 - ø 10.0 mm | 3.57592 | Armadura - Aço CA60 - ø 5.0 mm | 1.3718 | Pilar C-30 - Retangular 17x30
P98 | FUNDAÇÃO | retangular | 14 | 30 | 0 | 0.75 % | 0.26 | 0.23 | Concreto - C-30 - Abatimento 12 cm | 0.0336 | Dimensionado | Forma - Estrutura - Concreto | 0.704 | Dimensionado | Armadura - Aço CA50 - ø 10.0 mm | 3.57592 | Armadura - Aço CA60 - ø 5.0 mm | 1.27931 | Pilar C-30 - Retangular 14x30
P99 | FUNDAÇÃO | retangular | 14 | 30 | 0 | 0.75 % | 0.18 | 0.16 | Concreto - C-30 - Abatimento 12 cm | 0.0336 | Dimensionado | Forma - Estrutura - Concreto | 0.704 | Dimensionado | Armadura - Aço CA50 - ø 10.0 mm | 3.57592 | Armadura - Aço CA60 - ø 5.0 mm | 1.27931 | Pilar C-30 - Retangular 14x30
PM1 | FUNDAÇÃO | retangular | 20 | 20 | 0 | 0.79 % | 0.01 | 0.01 | Concreto - C-30 - Abatimento 12 cm | 0.016 | Dimensionado | Forma - Estrutura - Concreto | 0.32 | Dimensionado | Armadura - Aço CA50 - ø 10.0 mm | 2.58946 | Armadura - Aço CA60 - ø 5.0 mm | 0.809206 | Pilar C-30 - Retangular 20x20
PM2 | FUNDAÇÃO | retangular | 20 | 20 | 0 | 0.79 % | 0.01 | 0.01 | Concreto - C-30 - Abatimento 12 cm | 0.016 | Dimensionado | Forma - Estrutura - Concreto | 0.32 | Dimensionado | Armadura - Aço CA50 - ø 10.0 mm | 2.58946 | Armadura - Aço CA60 - ø 5.0 mm | 0.809206 | Pilar C-30 - Retangular 20x20
P1 | VIGA BALDRAME | retangular | 14 | 30 | 0 | 0.75 % | 0.03 | 0.03 | Concreto - C-30 - Abatimento 12 cm | 0.0126 | Dimensionado | Forma - Estrutura - Concreto | 0.264 | Dimensionado | Armadura - Aço CA50 - ø 10.0 mm | 1.55367 | Armadura - Aço CA60 - ø 5.0 mm | 0.383795 | Pilar C-30 - Retangular 14x30
P10 | VIGA BALDRAME | retangular | 14 | 30 | 0 | Não calculado | Não calculado | Não calculado |  |  | Não dimensionado |  |  |  |  |  |  |  | Pilar C-30 - Retangular 14x30
P100 | VIGA BALDRAME | retangular | 14 | 30 | 0 | 0.75 % | 0.04 | 0.03 | Concreto - C-30 - Abatimento 12 cm | 0.0126 | Dimensionado | Forma - Estrutura - Concreto | 0.264 | Dimensionado | Armadura - Aço CA50 - ø 10.0 mm | 1.55367 | Armadura - Aço CA60 - ø 5.0 mm | 0.383795 | Pilar C-30 - Retangular 14x30
P101 | VIGA BALDRAME | retangular | 14 | 30 | 0 | Não calculado | Não calculado | Não calculado |  |  | Não dimensionado |  |  |  |  |  |  |  | Pilar C-30 - Retangular 14x30
P102 | VIGA BALDRAME | retangular | 14 | 30 | 0 | 1.12 % | 0.11 | 0.1 | Concreto - C-30 - Abatimento 12 cm | 0.0126 | Dimensionado | Forma - Estrutura - Concreto | 0.264 | Dimensionado | Armadura - Aço CA50 - ø 10.0 mm | 2.33051 | Armadura - Aço CA60 - ø 5.0 mm | 0.499395 | Pilar C-30 - Retangular 14x30
P103 | VIGA BALDRAME | retangular | 14 | 30 | 0 | 0.75 % | 0.04 | 0.03 | Concreto - C-30 - Abatimento 12 cm | 0.0126 | Dimensionado | Forma - Estrutura - Concreto | 0.264 | Dimensionado | Armadura - Aço CA50 - ø 10.0 mm | 1.55367 | Armadura - Aço CA60 - ø 5.0 mm | 0.383795 | Pilar C-30 - Retangular 14x30
P104 | VIGA BALDRAME | retangular | 14 | 30 | 0 | 0.75 % | 0.08 | 0.07 | Concreto - C-30 - Abatimento 12 cm | 0.0126 | Dimensionado | Forma - Estrutura - Concreto | 0.264 | Dimensionado | Armadura - Aço CA50 - ø 10.0 mm | 1.55367 | Armadura - Aço CA60 - ø 5.0 mm | 0.383795 | Pilar C-30 - Retangular 14x30
P105 | VIGA BALDRAME | retangular | 14 | 30 | 0 | 0.75 % | 0.19 | 0.16 | Concreto - C-30 - Abatimento 12 cm | 0.0126 | Dimensionado | Forma - Estrutura - Concreto | 0.264 | Dimensionado | Armadura - Aço CA50 - ø 10.0 mm | 1.55367 | Armadura - Aço CA60 - ø 5.0 mm | 0.383795 | Pilar C-30 - Retangular 14x30
P106 | VIGA BALDRAME | retangular | 14 | 30 | 0 | 1.12 % | 0.16 | 0.14 | Concreto - C-30 - Abatimento 12 cm | 0.0126 | Dimensionado | Forma - Estrutura - Concreto | 0.264 | Dimensionado | Armadura - Aço CA50 - ø 10.0 mm | 1.89894 | Armadura - Aço CA60 - ø 5.0 mm | 0.499395 | Pilar C-30 - Retangular 14x30
P107 | VIGA BALDRAME | retangular | 14 | 30 | 0 | Não calculado | Não calculado | Não calculado |  |  | Não dimensionado |  |  |  |  |  |  |  | Pilar C-30 - Retangular 14x30
P108 | VIGA BALDRAME | retangular | 14 | 30 | 0 | 0.75 % | 0.13 | 0.11 | Concreto - C-30 - Abatimento 12 cm | 0.0126 | Dimensionado | Forma - Estrutura - Concreto | 0.264 | Dimensionado | Armadura - Aço CA50 - ø 10.0 mm | 1.55367 | Armadura - Aço CA60 - ø 5.0 mm | 0.383795 | Pilar C-30 - Retangular 14x30
P109 | VIGA BALDRAME | retangular | 14 | 30 | 0 | 0.75 % | 0.14 | 0.12 | Concreto - C-30 - Abatimento 12 cm | 0.0126 | Dimensionado | Forma - Estrutura - Concreto | 0.264 | Dimensionado | Armadura - Aço CA50 - ø 10.0 mm | 1.55367 | Armadura - Aço CA60 - ø 5.0 mm | 0.383795 | Pilar C-30 - Retangular 14x30
P11 | VIGA BALDRAME | retangular | 14 | 30 | 0 | Não calculado | Não calculado | Não calculado |  |  | Não dimensionado |  |  |  |  |  |  |  | Pilar C-30 - Retangular 14x30
P110 | VIGA BALDRAME | retangular | 14 | 30 | 0 | 0.75 % | 0.13 | 0.11 | Concreto - C-30 - Abatimento 12 cm | 0.0126 | Dimensionado | Forma - Estrutura - Concreto | 0.264 | Dimensionado | Armadura - Aço CA50 - ø 10.0 mm | 1.55367 | Armadura - Aço CA60 - ø 5.0 mm | 0.383795 | Pilar C-30 - Retangular 14x30
P111 | VIGA BALDRAME | retangular | 14 | 30 | 0 | 0.75 % | 0.03 | 0.03 | Concreto - C-30 - Abatimento 12 cm | 0.0126 | Dimensionado | Forma - Estrutura - Concreto | 0.264 | Dimensionado | Armadura - Aço CA50 - ø 10.0 mm | 0.690522 | Armadura - Aço CA60 - ø 5.0 mm | 0.383795 | Pilar C-30 - Retangular 14x30
P112 | VIGA BALDRAME | retangular | 14 | 30 | 0 | 0.75 % | 0.07 | 0.06 | Concreto - C-30 - Abatimento 12 cm | 0.0126 | Dimensionado | Forma - Estrutura - Concreto | 0.264 | Dimensionado | Armadura - Aço CA50 - ø 10.0 mm | 1.55367 | Armadura - Aço CA60 - ø 5.0 mm | 0.383795 | Pilar C-30 - Retangular 14x30
P113 | VIGA BALDRAME | retangular | 17 | 30 | 0 | 0.62 % | 0.12 | 0.11 | Concreto - C-30 - Abatimento 12 cm | 0.0153 | Dimensionado | Forma - Estrutura - Concreto | 0.282 | Dimensionado | Armadura - Aço CA50 - ø 10.0 mm | 1.55367 | Armadura - Aço CA60 - ø 5.0 mm | 0.411539 | Pilar C-30 - Retangular 17x30
P114 | VIGA BALDRAME | retangular | 14 | 30 | 0 | Não calculado | Não calculado | Não calculado |  |  | Não dimensionado |  |  |  |  |  |  |  | Pilar C-30 - Retangular 14x30
P115 | VIGA BALDRAME | retangular | 14 | 30 | 0 | 0.75 % | 0.04 | 0.03 | Concreto - C-30 - Abatimento 12 cm | 0.0126 | Dimensionado | Forma - Estrutura - Concreto | 0.264 | Dimensionado | Armadura - Aço CA50 - ø 10.0 mm | 1.55367 | Armadura - Aço CA60 - ø 5.0 mm | 0.383795 | Pilar C-30 - Retangular 14x30
P116 | VIGA BALDRAME | retangular | 17 | 30 | 0 | 0.62 % | 0.14 | 0.12 | Concreto - C-30 - Abatimento 12 cm | 0.0153 | Dimensionado | Forma - Estrutura - Concreto | 0.282 | Dimensionado | Armadura - Aço CA50 - ø 10.0 mm | 1.55367 | Armadura - Aço CA60 - ø 5.0 mm | 0.411539 | Pilar C-30 - Retangular 17x30
P117 | VIGA BALDRAME | retangular | 14 | 30 | 0 | Não calculado | Não calculado | Não calculado |  |  | Não dimensionado |  |  |  |  |  |  |  | Pilar C-30 - Retangular 14x30
P118 | VIGA BALDRAME | retangular | 14 | 30 | 0 | 0.75 % | 0.13 | 0.12 | Concreto - C-30 - Abatimento 12 cm | 0.0126 | Dimensionado | Forma - Estrutura - Concreto | 0.264 | Dimensionado | Armadura - Aço CA50 - ø 10.0 mm | 1.55367 | Armadura - Aço CA60 - ø 5.0 mm | 0.383795 | Pilar C-30 - Retangular 14x30
P119 | VIGA BALDRAME | retangular | 14 | 30 | 0 | 1.12 % | 0.16 | 0.14 | Concreto - C-30 - Abatimento 12 cm | 0.0126 | Dimensionado | Forma - Estrutura - Concreto | 0.264 | Dimensionado | Armadura - Aço CA50 - ø 10.0 mm | 1.89894 | Armadura - Aço CA60 - ø 5.0 mm | 0.499395 | Pilar C-30 - Retangular 14x30
P12 | VIGA BALDRAME | retangular | 14 | 30 | 0 | Não calculado | Não calculado | Não calculado |  |  | Não dimensionado |  |  |  |  |  |  |  | Pilar C-30 - Retangular 14x30
P120 | VIGA BALDRAME | retangular | 14 | 30 | 0 | 0.75 % | 0.13 | 0.11 | Concreto - C-30 - Abatimento 12 cm | 0.0126 | Dimensionado | Forma - Estrutura - Concreto | 0.264 | Dimensionado | Armadura - Aço CA50 - ø 10.0 mm | 1.55367 | Armadura - Aço CA60 - ø 5.0 mm | 0.383795 | Pilar C-30 - Retangular 14x30
P121 | VIGA BALDRAME | retangular | 14 | 30 | 0 | 0.75 % | 0.14 | 0.12 | Concreto - C-30 - Abatimento 12 cm | 0.0126 | Dimensionado | Forma - Estrutura - Concreto | 0.264 | Dimensionado | Armadura - Aço CA50 - ø 10.0 mm | 1.55367 | Armadura - Aço CA60 - ø 5.0 mm | 0.383795 | Pilar C-30 - Retangular 14x30
P122 | VIGA BALDRAME | retangular | 14 | 30 | 0 | 0.75 % | 0.15 | 0.13 | Concreto - C-30 - Abatimento 12 cm | 0.0126 | Dimensionado | Forma - Estrutura - Concreto | 0.264 | Dimensionado | Armadura - Aço CA50 - ø 10.0 mm | 1.55367 | Armadura - Aço CA60 - ø 5.0 mm | 0.383795 | Pilar C-30 - Retangular 14x30
P123 | VIGA BALDRAME | retangular | 14 | 30 | 0 | 0.75 % | 0.16 | 0.14 | Concreto - C-30 - Abatimento 12 cm | 0.0126 | Dimensionado | Forma - Estrutura - Concreto | 0.264 | Dimensionado | Armadura - Aço CA50 - ø 10.0 mm | 1.55367 | Armadura - Aço CA60 - ø 5.0 mm | 0.383795 | Pilar C-30 - Retangular 14x30
P124 | VIGA BALDRAME | retangular | 17 | 30 | 0 | 0.92 % | 0.12 | 0.11 | Concreto - C-30 - Abatimento 12 cm | 0.0153 | Dimensionado | Forma - Estrutura - Concreto | 0.281999 | Dimensionado | Armadura - Aço CA50 - ø 10.0 mm | 1.89894 | Armadura - Aço CA60 - ø 5.0 mm | 0.541012 | Pilar C-30 - Retangular 17x30
P125 | VIGA BALDRAME | retangular | 14 | 30 | 0 | Não calculado | Não calculado | Não calculado |  |  | Não dimensionado |  |  |  |  |  |  |  | Pilar C-30 - Retangular 14x30
P126 | VIGA BALDRAME | retangular | 14 | 30 | 0 | 0.75 % | 0.11 | 0.09 | Concreto - C-30 - Abatimento 12 cm | 0.0126 | Dimensionado | Forma - Estrutura - Concreto | 0.264 | Dimensionado | Armadura - Aço CA50 - ø 10.0 mm | 1.55367 | Armadura - Aço CA60 - ø 5.0 mm | 0.383795 | Pilar C-30 - Retangular 14x30
P127 | VIGA BALDRAME | retangular | 14 | 30 | 0 | 0.75 % | 0.1 | 0.09 | Concreto - C-30 - Abatimento 12 cm | 0.0126 | Dimensionado | Forma - Estrutura - Concreto | 0.264 | Dimensionado | Armadura - Aço CA50 - ø 10.0 mm | 1.55367 | Armadura - Aço CA60 - ø 5.0 mm | 0.383795 | Pilar C-30 - Retangular 14x30
P128 | VIGA BALDRAME | retangular | 14 | 30 | 0 | 0.75 % | 0.1 | 0.09 | Concreto - C-30 - Abatimento 12 cm | 0.0126 | Dimensionado | Forma - Estrutura - Concreto | 0.264 | Dimensionado | Armadura - Aço CA50 - ø 10.0 mm | 1.55367 | Armadura - Aço CA60 - ø 5.0 mm | 0.383795 | Pilar C-30 - Retangular 14x30
P129 | VIGA BALDRAME | retangular | 14 | 30 | 0 | 0.75 % | 0.15 | 0.14 | Concreto - C-30 - Abatimento 12 cm | 0.0126 | Dimensionado | Forma - Estrutura - Concreto | 0.264 | Dimensionado | Armadura - Aço CA50 - ø 10.0 mm | 1.55367 | Armadura - Aço CA60 - ø 5.0 mm | 0.383795 | Pilar C-30 - Retangular 14x30
P13 | VIGA BALDRAME | retangular | 14 | 30 | 0 | Não calculado | Não calculado | Não calculado |  |  | Não dimensionado |  |  |  |  |  |  |  | Pilar C-30 - Retangular 14x30
P130 | VIGA BALDRAME | retangular | 14 | 30 | 0 | 0.75 % | 0.04 | 0.03 | Concreto - C-30 - Abatimento 12 cm | 0.0126 | Dimensionado | Forma - Estrutura - Concreto | 0.264 | Dimensionado | Armadura - Aço CA50 - ø 10.0 mm | 1.55367 | Armadura - Aço CA60 - ø 5.0 mm | 0.383795 | Pilar C-30 - Retangular 14x30
P131 | VIGA BALDRAME | retangular | 14 | 30 | 0 | 0.75 % | 0.12 | 0.1 | Concreto - C-30 - Abatimento 12 cm | 0.0126 | Dimensionado | Forma - Estrutura - Concreto | 0.264 | Dimensionado | Armadura - Aço CA50 - ø 10.0 mm | 1.55367 | Armadura - Aço CA60 - ø 5.0 mm | 0.383795 | Pilar C-30 - Retangular 14x30
P132 | VIGA BALDRAME | retangular | 14 | 30 | 0 | Não calculado | Não calculado | Não calculado |  |  | Não dimensionado |  |  |  |  |  |  |  | Pilar C-30 - Retangular 14x30
P133 | VIGA BALDRAME | retangular | 14 | 30 | 0 | Não calculado | Não calculado | Não calculado |  |  | Não dimensionado |  |  |  |  |  |  |  | Pilar C-30 - Retangular 14x30
P134 | VIGA BALDRAME | retangular | 14 | 30 | 0 | 0.75 % | 0.1 | 0.09 | Concreto - C-30 - Abatimento 12 cm | 0.0126 | Dimensionado | Forma - Estrutura - Concreto | 0.264 | Dimensionado | Armadura - Aço CA50 - ø 10.0 mm | 1.55367 | Armadura - Aço CA60 - ø 5.0 mm | 0.383795 | Pilar C-30 - Retangular 14x30
P135 | VIGA BALDRAME | retangular | 14 | 30 | 0 | 1.50 % | 0.13 | 0.1 | Concreto - C-30 - Abatimento 12 cm | 0.0126 | Dimensionado | Forma - Estrutura - Concreto | 0.264 | Dimensionado | Armadura - Aço CA50 - ø 10.0 mm | 2.67577 | Armadura - Aço CA60 - ø 5.0 mm | 0.383795 | Pilar C-30 - Retangular 14x30
P136 | VIGA BALDRAME | retangular | 14 | 30 | 0 | 0.75 % | 0.15 | 0.13 | Concreto - C-30 - Abatimento 12 cm | 0.0126 | Dimensionado | Forma - Estrutura - Concreto | 0.264 | Dimensionado | Armadura - Aço CA50 - ø 10.0 mm | 1.55367 | Armadura - Aço CA60 - ø 5.0 mm | 0.383795 | Pilar C-30 - Retangular 14x30
P137 | VIGA BALDRAME | retangular | 14 | 30 | 0 | 0.75 % | 0.11 | 0.1 | Concreto - C-30 - Abatimento 12 cm | 0.0126 | Dimensionado | Forma - Estrutura - Concreto | 0.264 | Dimensionado | Armadura - Aço CA50 - ø 10.0 mm | 1.55367 | Armadura - Aço CA60 - ø 5.0 mm | 0.383795 | Pilar C-30 - Retangular 14x30
P138 | VIGA BALDRAME | retangular | 14 | 30 | 0 | 0.75 % | 0.09 | 0.08 | Concreto - C-30 - Abatimento 12 cm | 0.0126 | Dimensionado | Forma - Estrutura - Concreto | 0.264 | Dimensionado | Armadura - Aço CA50 - ø 10.0 mm | 1.55367 | Armadura - Aço CA60 - ø 5.0 mm | 0.383795 | Pilar C-30 - Retangular 14x30
P139 | VIGA BALDRAME | retangular | 14 | 30 | 0 | 0.75 % | 0.12 | 0.1 | Concreto - C-30 - Abatimento 12 cm | 0.0126 | Dimensionado | Forma - Estrutura - Concreto | 0.264001 | Dimensionado | Armadura - Aço CA50 - ø 10.0 mm | 1.55367 | Armadura - Aço CA60 - ø 5.0 mm | 0.383795 | Pilar C-30 - Retangular 14x30
P14 | VIGA BALDRAME | retangular | 14 | 30 | 0 | 0.75 % | 0.04 | 0.03 | Concreto - C-30 - Abatimento 12 cm | 0.0126 | Dimensionado | Forma - Estrutura - Concreto | 0.264 | Dimensionado | Armadura - Aço CA50 - ø 10.0 mm | 1.55367 | Armadura - Aço CA60 - ø 5.0 mm | 0.383795 | Pilar C-30 - Retangular 14x30
P140 | VIGA BALDRAME | retangular | 14 | 30 | 0 | 1.50 % | 0.15 | 0.12 | Concreto - C-30 - Abatimento 12 cm | 0.0126 | Dimensionado | Forma - Estrutura - Concreto | 0.264 | Dimensionado | Armadura - Aço CA50 - ø 10.0 mm | 2.67577 | Armadura - Aço CA60 - ø 5.0 mm | 0.383795 | Pilar C-30 - Retangular 14x30
P141 | VIGA BALDRAME | retangular | 14 | 30 | 0 | 0.75 % | 0.03 | 0.03 | Concreto - C-30 - Abatimento 12 cm | 0.0126 | Dimensionado | Forma - Estrutura - Concreto | 0.264001 | Dimensionado | Armadura - Aço CA50 - ø 10.0 mm | 1.55367 | Armadura - Aço CA60 - ø 5.0 mm | 0.383795 | Pilar C-30 - Retangular 14x30
P142 | VIGA BALDRAME | retangular | 14 | 30 | 0 | 0.75 % | 0.07 | 0.06 | Concreto - C-30 - Abatimento 12 cm | 0.0126 | Dimensionado | Forma - Estrutura - Concreto | 0.264 | Dimensionado | Armadura - Aço CA50 - ø 10.0 mm | 1.55367 | Armadura - Aço CA50 - ø 12.5 mm | 1.59914 | Pilar C-30 - Retangular 14x30 | AltoQi_Eberick-Item_05 - Descrição_05: Armadura - Aço CA60 - ø 5.0 mm; Quantidade_05: 0.383795 kg; Status_05: Dimensionado
P143 | VIGA BALDRAME | retangular | 14 | 30 | 0 | 0.75 % | 0.08 | 0.07 | Concreto - C-30 - Abatimento 12 cm | 0.0126 | Dimensionado | Forma - Estrutura - Concreto | 0.264 | Dimensionado | Armadura - Aço CA50 - ø 10.0 mm | 1.55367 | Armadura - Aço CA60 - ø 5.0 mm | 0.383795 | Pilar C-30 - Retangular 14x30
P144 | VIGA BALDRAME | retangular | 14 | 30 | 0 | Não calculado | Não calculado | Não calculado |  |  | Não dimensionado |  |  |  |  |  |  |  | Pilar C-30 - Retangular 14x30
P145 | VIGA BALDRAME | retangular | 14 | 30 | 0 | 0.75 % | 0.07 | 0.07 | Concreto - C-30 - Abatimento 12 cm | 0.0126 | Dimensionado | Forma - Estrutura - Concreto | 0.264 | Dimensionado | Armadura - Aço CA50 - ø 10.0 mm | 1.55367 | Armadura - Aço CA60 - ø 5.0 mm | 0.383795 | Pilar C-30 - Retangular 14x30
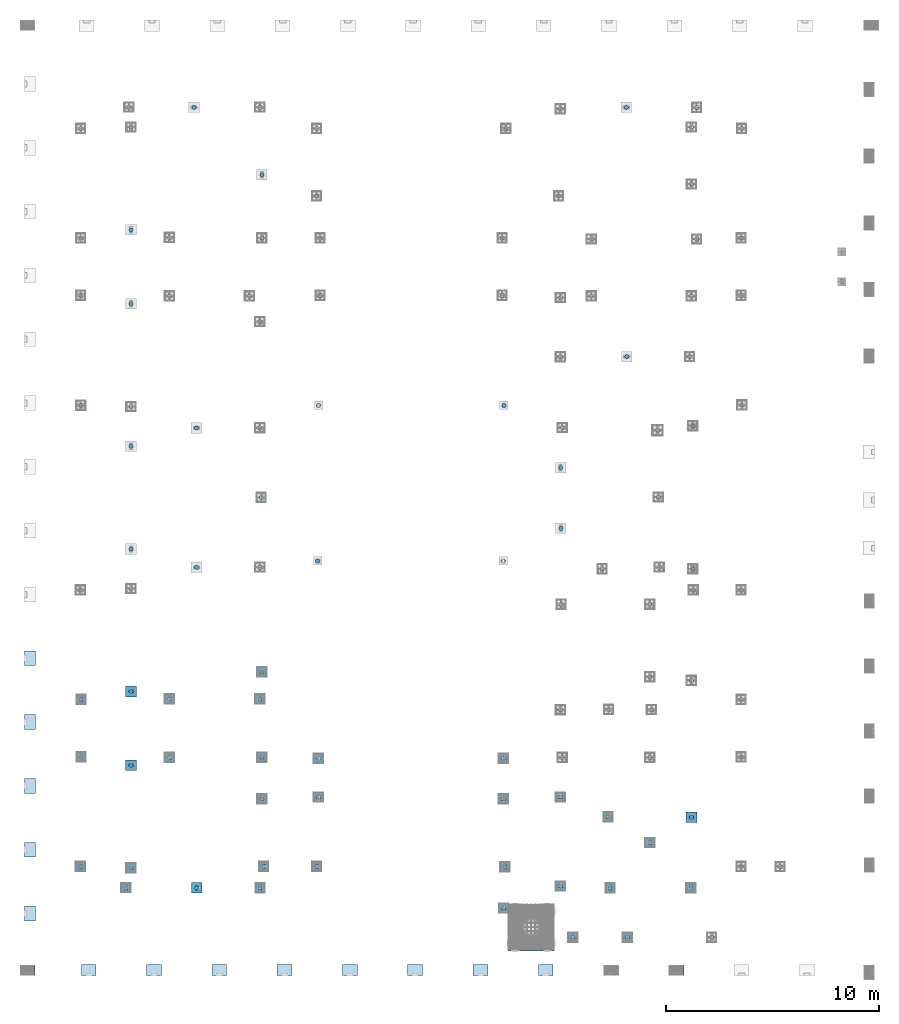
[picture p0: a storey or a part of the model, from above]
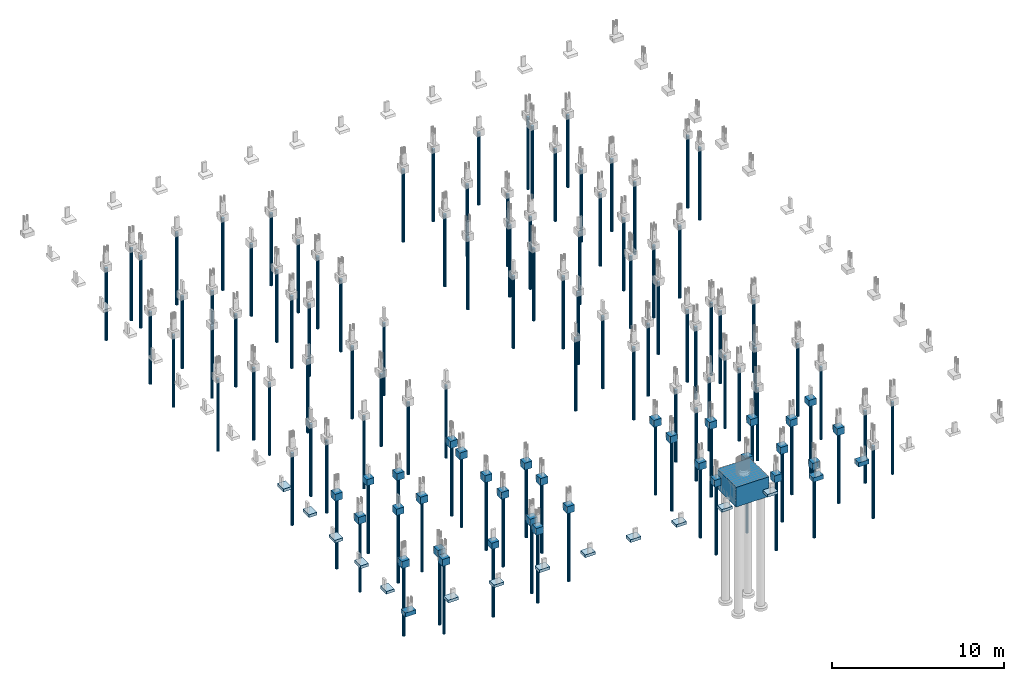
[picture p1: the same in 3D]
Properties of the parts of a building model (IFC4), part 5 of 9

# IfcColumn (561)
Name | In | Tipo | Seção_b (cm) | Seção_h (cm) | Elevação (cm) | Taxa de armadura | Taxa de compressão bruta | Taxa de compressão homogeneizada | Descrição_01 | Quantidade_01 (m3) | Status_01 | Descrição_02 | Quantidade_02 (m2) | Status_02 = Status_03 = Status_04 | Descrição_03 | Quantidade_03 (kg) | Descrição_04 | Quantidade_04 (kg) | Reference
P146 | VIGA BALDRAME | retangular | 14 | 30 | 0 | 0.75 % | 0.13 | 0.11 | Concreto - C-30 - Abatimento 12 cm | 0.0126 | Dimensionado | Forma - Estrutura - Concreto | 0.264 | Dimensionado | Armadura - Aço CA50 - ø 10.0 mm | 1.55367 | Armadura - Aço CA60 - ø 5.0 mm | 0.383795 | Pilar C-30 - Retangular 14x30
P147 | VIGA BALDRAME | retangular | 14 | 30 | 0 | 0.75 % | 0.16 | 0.14 | Concreto - C-30 - Abatimento 12 cm | 0.0126 | Dimensionado | Forma - Estrutura - Concreto | 0.264 | Dimensionado | Armadura - Aço CA50 - ø 10.0 mm | 1.55367 | Armadura - Aço CA60 - ø 5.0 mm | 0.383795 | Pilar C-30 - Retangular 14x30
P148 | VIGA BALDRAME | retangular | 14 | 30 | 0 | 0.75 % | 0.16 | 0.14 | Concreto - C-30 - Abatimento 12 cm | 0.0126 | Dimensionado | Forma - Estrutura - Concreto | 0.264 | Dimensionado | Armadura - Aço CA50 - ø 10.0 mm | 1.55367 | Armadura - Aço CA60 - ø 5.0 mm | 0.383795 | Pilar C-30 - Retangular 14x30
P149 | VIGA BALDRAME | retangular | 14 | 30 | 0 | Não calculado | Não calculado | Não calculado |  |  | Não dimensionado |  |  |  |  |  |  |  | Pilar C-30 - Retangular 14x30
P15 | VIGA BALDRAME | retangular | 14 | 30 | 0 | Não calculado | Não calculado | Não calculado |  |  | Não dimensionado |  |  |  |  |  |  |  | Pilar C-30 - Retangular 14x30
P150 | VIGA BALDRAME | retangular | 14 | 30 | 0 | 0.75 % | 0.05 | 0.05 | Concreto - C-30 - Abatimento 12 cm | 0.0126 | Dimensionado | Forma - Estrutura - Concreto | 0.264 | Dimensionado | Armadura - Aço CA50 - ø 10.0 mm | 1.55367 | Armadura - Aço CA60 - ø 5.0 mm | 0.383795 | Pilar C-30 - Retangular 14x30
P151 | VIGA BALDRAME | seção circular | 0 | 80 | 0 | 1.60 % | 0.08 | 0.06 | Concreto - C-30 - Abatimento 12 cm | 0.146425 | Dimensionado | Forma - Estrutura - Concreto | 0.732125 | Dimensionado | Armadura - Aço CA50 - ø 16.0 mm | 17.6774 | Armadura - Aço CA60 - ø 5.0 mm | 0.789168 | Pilar C-30 - Seção Circular 80
P152 | VIGA BALDRAME | retangular | 14 | 30 | 0 | 0.75 % | 0.02 | 0.02 | Concreto - C-30 - Abatimento 12 cm | 0.0126 | Dimensionado | Forma - Estrutura - Concreto | 0.264 | Dimensionado | Armadura - Aço CA50 - ø 10.0 mm | 1.55367 | Armadura - Aço CA60 - ø 5.0 mm | 0.383795 | Pilar C-30 - Retangular 14x30
P153 | VIGA BALDRAME | retangular | 14 | 30 | 0 | 0.75 % | 0.04 | 0.03 | Concreto - C-30 - Abatimento 12 cm | 0.0126 | Dimensionado | Forma - Estrutura - Concreto | 0.264 | Dimensionado | Armadura - Aço CA50 - ø 10.0 mm | 1.55367 | Armadura - Aço CA60 - ø 5.0 mm | 0.383795 | Pilar C-30 - Retangular 14x30
P154 | VIGA BALDRAME | retangular | 14 | 30 | 0 | 0.75 % | 0.03 | 0.02 | Concreto - C-30 - Abatimento 12 cm | 0.0126 | Dimensionado | Forma - Estrutura - Concreto | 0.264 | Dimensionado | Armadura - Aço CA50 - ø 10.0 mm | 1.55367 | Armadura - Aço CA60 - ø 5.0 mm | 0.383795 | Pilar C-30 - Retangular 14x30
P155 | VIGA BALDRAME | retangular | 14 | 30 | 0 | 0.75 % | 0.03 | 0.03 | Concreto - C-30 - Abatimento 12 cm | 0.0126 | Dimensionado | Forma - Estrutura - Concreto | 0.264 | Dimensionado | Armadura - Aço CA50 - ø 10.0 mm | 2.37983 | Armadura - Aço CA60 - ø 5.0 mm | 0.383795 | Pilar C-30 - Retangular 14x30
P156 | VIGA BALDRAME | retangular | 14 | 30 | 0 | Não calculado | Não calculado | Não calculado |  |  | Não dimensionado |  |  |  |  |  |  |  | Pilar C-30 - Retangular 14x30
P157 | VIGA BALDRAME | retangular | 14 | 30 | 0 | Não calculado | Não calculado | Não calculado |  |  | Não dimensionado |  |  |  |  |  |  |  | Pilar C-30 - Retangular 14x30
P158 | VIGA BALDRAME | retangular | 14 | 30 | 0 | Não calculado | Não calculado | Não calculado |  |  | Não dimensionado |  |  |  |  |  |  |  | Pilar C-30 - Retangular 14x30
P159 | VIGA BALDRAME | retangular | 14 | 30 | 0 | Não calculado | Não calculado | Não calculado |  |  | Não dimensionado |  |  |  |  |  |  |  | Pilar C-30 - Retangular 14x30
P16 | VIGA BALDRAME | retangular | 14 | 30 | 0 | 0.75 % | 0.04 | 0.03 | Concreto - C-30 - Abatimento 12 cm | 0.0126 | Dimensionado | Forma - Estrutura - Concreto | 0.264 | Dimensionado | Armadura - Aço CA50 - ø 10.0 mm | 1.55367 | Armadura - Aço CA60 - ø 5.0 mm | 0.383795 | Pilar C-30 - Retangular 14x30
P160 | VIGA BALDRAME | retangular | 14 | 30 | 0 | Não calculado | Não calculado | Não calculado |  |  | Não dimensionado |  |  |  |  |  |  |  | Pilar C-30 - Retangular 14x30
P161 | VIGA BALDRAME | retangular | 14 | 30 | 0 | Não calculado | Não calculado | Não calculado |  |  | Não dimensionado |  |  |  |  |  |  |  | Pilar C-30 - Retangular 14x30
P162 | VIGA BALDRAME | retangular | 14 | 30 | 0 | Não calculado | Não calculado | Não calculado |  |  | Não dimensionado |  |  |  |  |  |  |  | Pilar C-30 - Retangular 14x30
P163 | VIGA BALDRAME | retangular | 14 | 30 | 0 | Não calculado | Não calculado | Não calculado |  |  | Não dimensionado |  |  |  |  |  |  |  | Pilar C-30 - Retangular 14x30
P164 | VIGA BALDRAME | retangular | 14 | 30 | 0 | 0.75 % | 0.06 | 0.05 | Concreto - C-30 - Abatimento 12 cm | 0.0126 | Dimensionado | Forma - Estrutura - Concreto | 0.264 | Dimensionado | Armadura - Aço CA50 - ø 10.0 mm | 1.55367 | Armadura - Aço CA60 - ø 5.0 mm | 0.383795 | Pilar C-30 - Retangular 14x30
P165 | VIGA BALDRAME | retangular | 14 | 30 | 0 | 0.75 % | 0.06 | 0.05 | Concreto - C-30 - Abatimento 12 cm | 0.0126 | Dimensionado | Forma - Estrutura - Concreto | 0.264 | Dimensionado | Armadura - Aço CA50 - ø 10.0 mm | 1.55367 | Armadura - Aço CA60 - ø 5.0 mm | 0.383795 | Pilar C-30 - Retangular 14x30
P166 | VIGA BALDRAME | retangular | 14 | 30 | 0 | Não calculado | Não calculado | Não calculado |  |  | Não dimensionado |  |  |  |  |  |  |  | Pilar C-30 - Retangular 14x30
P167 | VIGA BALDRAME | retangular | 14 | 30 | 0 | Não calculado | Não calculado | Não calculado |  |  | Não dimensionado |  |  |  |  |  |  |  | Pilar C-30 - Retangular 14x30
P168 | VIGA BALDRAME | retangular | 14 | 30 | 0 | 0.75 % | 0.05 | 0.04 | Concreto - C-30 - Abatimento 12 cm | 0.0126 | Dimensionado | Forma - Estrutura - Concreto | 0.264 | Dimensionado | Armadura - Aço CA50 - ø 10.0 mm | 1.55367 | Armadura - Aço CA60 - ø 5.0 mm | 0.383795 | Pilar C-30 - Retangular 14x30
P17 | VIGA BALDRAME | retangular | 14 | 30 | 0 | 0.75 % | 0.09 | 0.08 | Concreto - C-30 - Abatimento 12 cm | 0.0126 | Dimensionado | Forma - Estrutura - Concreto | 0.264 | Dimensionado | Armadura - Aço CA50 - ø 10.0 mm | 1.55367 | Armadura - Aço CA60 - ø 5.0 mm | 0.383795 | Pilar C-30 - Retangular 14x30
P18 | VIGA BALDRAME | retangular | 14 | 30 | 0 | Não calculado | Não calculado | Não calculado |  |  | Não dimensionado |  |  |  |  |  |  |  | Pilar C-30 - Retangular 14x30
P19 | VIGA BALDRAME | retangular | 14 | 30 | 0 | 0.75 % | 0.13 | 0.11 | Concreto - C-30 - Abatimento 12 cm | 0.0126 | Dimensionado | Forma - Estrutura - Concreto | 0.264 | Dimensionado | Armadura - Aço CA50 - ø 10.0 mm | 1.55367 | Armadura - Aço CA60 - ø 5.0 mm | 0.383795 | Pilar C-30 - Retangular 14x30
P2 | VIGA BALDRAME | retangular | 14 | 30 | 0 | Não calculado | Não calculado | Não calculado |  |  | Não dimensionado |  |  |  |  |  |  |  | Pilar C-30 - Retangular 14x30
P20 | VIGA BALDRAME | retangular | 14 | 30 | 0 | 0.75 % | 0.18 | 0.15 | Concreto - C-30 - Abatimento 12 cm | 0.0126 | Dimensionado | Forma - Estrutura - Concreto | 0.264 | Dimensionado | Armadura - Aço CA50 - ø 10.0 mm | 1.55367 | Armadura - Aço CA60 - ø 5.0 mm | 0.383795 | Pilar C-30 - Retangular 14x30
P21 | VIGA BALDRAME | retangular | 14 | 30 | 0 | Não calculado | Não calculado | Não calculado |  |  | Não dimensionado |  |  |  |  |  |  |  | Pilar C-30 - Retangular 14x30
P22 | VIGA BALDRAME | retangular | 14 | 30 | 0 | 0.75 % | 0.08 | 0.07 | Concreto - C-30 - Abatimento 12 cm | 0.0126 | Dimensionado | Forma - Estrutura - Concreto | 0.264 | Dimensionado | Armadura - Aço CA50 - ø 10.0 mm | 1.55367 | Armadura - Aço CA60 - ø 5.0 mm | 0.383795 | Pilar C-30 - Retangular 14x30
P23 | VIGA BALDRAME | retangular | 14 | 30 | 0 | 1.17 % | 0.13 | 0.11 | Concreto - C-30 - Abatimento 12 cm | 0.0126 | Dimensionado | Forma - Estrutura - Concreto | 0.264 | Dimensionado | Armadura - Aço CA50 - ø 10.0 mm | 0.82616 | Armadura - Aço CA50 - ø 12.5 mm | 2.77442 | Pilar C-30 - Retangular 14x30 | AltoQi_Eberick-Item_05 - Descrição_05: Armadura - Aço CA60 - ø 5.0 mm; Quantidade_05: 0.383795 kg; Status_05: Dimensionado
P24 | VIGA BALDRAME | retangular | 14 | 30 | 0 | 0.75 % | 0.15 | 0.13 | Concreto - C-30 - Abatimento 12 cm | 0.0126 | Dimensionado | Forma - Estrutura - Concreto | 0.264 | Dimensionado | Armadura - Aço CA50 - ø 10.0 mm | 1.55367 | Armadura - Aço CA60 - ø 5.0 mm | 0.383795 | Pilar C-30 - Retangular 14x30
P25 | VIGA BALDRAME | retangular | 14 | 30 | 0 | 0.75 % | 0.1 | 0.09 | Concreto - C-30 - Abatimento 12 cm | 0.0126 | Dimensionado | Forma - Estrutura - Concreto | 0.264 | Dimensionado | Armadura - Aço CA50 - ø 10.0 mm | 1.55367 | Armadura - Aço CA60 - ø 5.0 mm | 0.383795 | Pilar C-30 - Retangular 14x30
P26 | VIGA BALDRAME | retangular | 17 | 30 | 0 | 1.23 % | 0.11 | 0.1 | Concreto - C-30 - Abatimento 12 cm | 0.0153 | Dimensionado | Forma - Estrutura - Concreto | 0.282 | Dimensionado | Armadura - Aço CA50 - ø 10.0 mm | 2.67577 | Armadura - Aço CA60 - ø 5.0 mm | 0.411539 | Pilar C-30 - Retangular 17x30
P27 | VIGA BALDRAME | retangular | 14 | 30 | 0 | 0.75 % | 0.13 | 0.11 | Concreto - C-30 - Abatimento 12 cm | 0.0126 | Dimensionado | Forma - Estrutura - Concreto | 0.264 | Dimensionado | Armadura - Aço CA50 - ø 10.0 mm | 1.55367 | Armadura - Aço CA60 - ø 5.0 mm | 0.383795 | Pilar C-30 - Retangular 14x30
P28 | VIGA BALDRAME | retangular | 14 | 30 | 0 | 1.17 % | 0.13 | 0.1 | Concreto - C-30 - Abatimento 12 cm | 0.0126 | Dimensionado | Forma - Estrutura - Concreto | 0.264 | Dimensionado | Armadura - Aço CA50 - ø 10.0 mm | 0.82616 | Armadura - Aço CA50 - ø 12.5 mm | 2.77442 | Pilar C-30 - Retangular 14x30 | AltoQi_Eberick-Item_05 - Descrição_05: Armadura - Aço CA60 - ø 5.0 mm; Quantidade_05: 0.383795 kg; Status_05: Dimensionado
P29 | VIGA BALDRAME | retangular | 14 | 30 | 0 | Não calculado | Não calculado | Não calculado |  |  | Não dimensionado |  |  |  |  |  |  |  | Pilar C-30 - Retangular 14x30
P3 | VIGA BALDRAME | retangular | 14 | 30 | 0 | Não calculado | Não calculado | Não calculado |  |  | Não dimensionado |  |  |  |  |  |  |  | Pilar C-30 - Retangular 14x30
P30 | VIGA BALDRAME | retangular | 14 | 30 | 0 | 0.75 % | 0.04 | 0.03 | Concreto - C-30 - Abatimento 12 cm | 0.0126 | Dimensionado | Forma - Estrutura - Concreto | 0.264 | Dimensionado | Armadura - Aço CA50 - ø 10.0 mm | 1.55367 | Armadura - Aço CA60 - ø 5.0 mm | 0.383795 | Pilar C-30 - Retangular 14x30
P31 | VIGA BALDRAME | retangular | 14 | 30 | 0 | Não calculado | Não calculado | Não calculado |  |  | Não dimensionado |  |  |  |  |  |  |  | Pilar C-30 - Retangular 14x30
P32 | VIGA BALDRAME | retangular | 14 | 30 | 0 | 0.75 % | 0.06 | 0.05 | Concreto - C-30 - Abatimento 12 cm | 0.0126 | Dimensionado | Forma - Estrutura - Concreto | 0.264 | Dimensionado | Armadura - Aço CA50 - ø 10.0 mm | 0.690522 | Armadura - Aço CA60 - ø 5.0 mm | 0.383795 | Pilar C-30 - Retangular 14x30
P33 | VIGA BALDRAME | retangular | 14 | 30 | 0 | 0.75 % | 0.13 | 0.11 | Concreto - C-30 - Abatimento 12 cm | 0.0126 | Dimensionado | Forma - Estrutura - Concreto | 0.264 | Dimensionado | Armadura - Aço CA50 - ø 10.0 mm | 1.55367 | Armadura - Aço CA60 - ø 5.0 mm | 0.383795 | Pilar C-30 - Retangular 14x30
P34 | VIGA BALDRAME | retangular | 14 | 30 | 0 | 0.75 % | 0.15 | 0.13 | Concreto - C-30 - Abatimento 12 cm | 0.0126 | Dimensionado | Forma - Estrutura - Concreto | 0.264 | Dimensionado | Armadura - Aço CA50 - ø 10.0 mm | 1.55367 | Armadura - Aço CA60 - ø 5.0 mm | 0.383795 | Pilar C-30 - Retangular 14x30
P35 | VIGA BALDRAME | retangular | 14 | 30 | 0 | Não calculado | Não calculado | Não calculado |  |  | Não dimensionado |  |  |  |  |  |  |  | Pilar C-30 - Retangular 14x30
P36 | VIGA BALDRAME | retangular | 17 | 30 | 0 | 0.62 % | 0.14 | 0.12 | Concreto - C-30 - Abatimento 12 cm | 0.0153 | Dimensionado | Forma - Estrutura - Concreto | 0.282 | Dimensionado | Armadura - Aço CA50 - ø 10.0 mm | 1.55367 | Armadura - Aço CA60 - ø 5.0 mm | 0.411539 | Pilar C-30 - Retangular 17x30
P37 | VIGA BALDRAME | retangular | 14 | 30 | 0 | Não calculado | Não calculado | Não calculado |  |  | Não dimensionado |  |  |  |  |  |  |  | Pilar C-30 - Retangular 14x30
P38 | VIGA BALDRAME | retangular | 14 | 30 | 0 | 0.75 % | 0.04 | 0.03 | Concreto - C-30 - Abatimento 12 cm | 0.0126 | Dimensionado | Forma - Estrutura - Concreto | 0.264 | Dimensionado | Armadura - Aço CA50 - ø 10.0 mm | 1.55367 | Armadura - Aço CA60 - ø 5.0 mm | 0.383795 | Pilar C-30 - Retangular 14x30
P39 | VIGA BALDRAME | retangular | 14 | 30 | 0 | 0.75 % | 0.14 | 0.13 | Concreto - C-30 - Abatimento 12 cm | 0.0126 | Dimensionado | Forma - Estrutura - Concreto | 0.264 | Dimensionado | Armadura - Aço CA50 - ø 10.0 mm | 1.55367 | Armadura - Aço CA60 - ø 5.0 mm | 0.383795 | Pilar C-30 - Retangular 14x30
P4 | VIGA BALDRAME | retangular | 14 | 30 | 0 | Não calculado | Não calculado | Não calculado |  |  | Não dimensionado |  |  |  |  |  |  |  | Pilar C-30 - Retangular 14x30
P40 | VIGA BALDRAME | retangular | 14 | 30 | 0 | 0.75 % | 0.21 | 0.18 | Concreto - C-30 - Abatimento 12 cm | 0.0126 | Dimensionado | Forma - Estrutura - Concreto | 0.264 | Dimensionado | Armadura - Aço CA50 - ø 10.0 mm | 1.55367 | Armadura - Aço CA60 - ø 5.0 mm | 0.383795 | Pilar C-30 - Retangular 14x30
P41 | VIGA BALDRAME | retangular | 17 | 30 | 0 | 0.62 % | 0.09 | 0.08 | Concreto - C-30 - Abatimento 12 cm | 0.0153 | Dimensionado | Forma - Estrutura - Concreto | 0.282 | Dimensionado | Armadura - Aço CA50 - ø 10.0 mm | 1.55367 | Armadura - Aço CA60 - ø 5.0 mm | 0.411539 | Pilar C-30 - Retangular 17x30
P42 | VIGA BALDRAME | retangular | 17 | 30 | 0 | 0.92 % | 0.16 | 0.14 | Concreto - C-30 - Abatimento 12 cm | 0.0153 | Dimensionado | Forma - Estrutura - Concreto | 0.282 | Dimensionado | Armadura - Aço CA50 - ø 10.0 mm | 2.33051 | Armadura - Aço CA60 - ø 5.0 mm | 0.541012 | Pilar C-30 - Retangular 17x30
P43 | VIGA BALDRAME | retangular | 14 | 30 | 0 | 0.75 % | 0.19 | 0.17 | Concreto - C-30 - Abatimento 12 cm | 0.0126 | Dimensionado | Forma - Estrutura - Concreto | 0.264 | Dimensionado | Armadura - Aço CA50 - ø 10.0 mm | 1.55367 | Armadura - Aço CA60 - ø 5.0 mm | 0.383795 | Pilar C-30 - Retangular 14x30
P44 | VIGA BALDRAME | retangular | 14 | 30 | 0 | 0.75 % | 0.2 | 0.18 | Concreto - C-30 - Abatimento 12 cm | 0.0126 | Dimensionado | Forma - Estrutura - Concreto | 0.264 | Dimensionado | Armadura - Aço CA50 - ø 10.0 mm | 1.55367 | Armadura - Aço CA60 - ø 5.0 mm | 0.383795 | Pilar C-30 - Retangular 14x30
P45 | VIGA BALDRAME | retangular | 17 | 30 | 0 | 0.92 % | 0.12 | 0.11 | Concreto - C-30 - Abatimento 12 cm | 0.0153 | Dimensionado | Forma - Estrutura - Concreto | 0.282 | Dimensionado | Armadura - Aço CA50 - ø 10.0 mm | 1.89894 | Armadura - Aço CA60 - ø 5.0 mm | 0.541012 | Pilar C-30 - Retangular 17x30
P46 | VIGA BALDRAME | retangular | 14 | 30 | 0 | Não calculado | Não calculado | Não calculado |  |  | Não dimensionado |  |  |  |  |  |  |  | Pilar C-30 - Retangular 14x30
P47 | VIGA BALDRAME | retangular | 17 | 30 | 0 | 0.92 % | 0.13 | 0.11 | Concreto - C-30 - Abatimento 12 cm | 0.0153 | Dimensionado | Forma - Estrutura - Concreto | 0.282 | Dimensionado | Armadura - Aço CA50 - ø 10.0 mm | 1.89894 | Armadura - Aço CA60 - ø 5.0 mm | 0.541012 | Pilar C-30 - Retangular 17x30
P48 | VIGA BALDRAME | retangular | 14 | 30 | 0 | Não calculado | Não calculado | Não calculado |  |  | Não dimensionado |  |  |  |  |  |  |  | Pilar C-30 - Retangular 14x30
P49 | VIGA BALDRAME | retangular | 14 | 30 | 0 | 0.75 % | 0.11 | 0.1 | Concreto - C-30 - Abatimento 12 cm | 0.0126 | Dimensionado | Forma - Estrutura - Concreto | 0.264 | Dimensionado | Armadura - Aço CA50 - ø 10.0 mm | 1.55367 | Armadura - Aço CA60 - ø 5.0 mm | 0.383795 | Pilar C-30 - Retangular 14x30
P5 | VIGA BALDRAME | retangular | 14 | 30 | 0 | Não calculado | Não calculado | Não calculado |  |  | Não dimensionado |  |  |  |  |  |  |  | Pilar C-30 - Retangular 14x30
P50 | VIGA BALDRAME | retangular | 14 | 30 | 0 | 0.75 % | 0.16 | 0.14 | Concreto - C-30 - Abatimento 12 cm | 0.0126 | Dimensionado | Forma - Estrutura - Concreto | 0.264 | Dimensionado | Armadura - Aço CA50 - ø 10.0 mm | 1.55367 | Armadura - Aço CA60 - ø 5.0 mm | 0.383795 | Pilar C-30 - Retangular 14x30
P51 | VIGA BALDRAME | retangular | 17 | 30 | 0 | 0.62 % | 0.1 | 0.09 | Concreto - C-30 - Abatimento 12 cm | 0.0153 | Dimensionado | Forma - Estrutura - Concreto | 0.282 | Dimensionado | Armadura - Aço CA50 - ø 10.0 mm | 1.55367 | Armadura - Aço CA60 - ø 5.0 mm | 0.411539 | Pilar C-30 - Retangular 17x30
P52 | VIGA BALDRAME | retangular | 17 | 30 | 0 | 0.62 % | 0.09 | 0.08 | Concreto - C-30 - Abatimento 12 cm | 0.0153 | Dimensionado | Forma - Estrutura - Concreto | 0.282 | Dimensionado | Armadura - Aço CA50 - ø 10.0 mm | 1.55367 | Armadura - Aço CA60 - ø 5.0 mm | 0.411539 | Pilar C-30 - Retangular 17x30
P53 | VIGA BALDRAME | retangular | 14 | 30 | 0 | 0.75 % | 0.08 | 0.07 | Concreto - C-30 - Abatimento 12 cm | 0.0126 | Dimensionado | Forma - Estrutura - Concreto | 0.264 | Dimensionado | Armadura - Aço CA50 - ø 10.0 mm | 1.55367 | Armadura - Aço CA60 - ø 5.0 mm | 0.383795 | Pilar C-30 - Retangular 14x30
P54 | VIGA BALDRAME | retangular | 14 | 30 | 0 | 0.75 % | 0.14 | 0.12 | Concreto - C-30 - Abatimento 12 cm | 0.0126 | Dimensionado | Forma - Estrutura - Concreto | 0.264 | Dimensionado | Armadura - Aço CA50 - ø 10.0 mm | 1.55367 | Armadura - Aço CA60 - ø 5.0 mm | 0.383795 | Pilar C-30 - Retangular 14x30
P55 | VIGA BALDRAME | retangular | 14 | 30 | 0 | 0.75 % | 0.18 | 0.16 | Concreto - C-30 - Abatimento 12 cm | 0.0126 | Dimensionado | Forma - Estrutura - Concreto | 0.264 | Dimensionado | Armadura - Aço CA50 - ø 10.0 mm | 1.55367 | Armadura - Aço CA60 - ø 5.0 mm | 0.383795 | Pilar C-30 - Retangular 14x30
P56 | VIGA BALDRAME | retangular | 17 | 30 | 0 | 0.62 % | 0.13 | 0.12 | Concreto - C-30 - Abatimento 12 cm | 0.0153 | Dimensionado | Forma - Estrutura - Concreto | 0.282 | Dimensionado | Armadura - Aço CA50 - ø 10.0 mm | 1.55367 | Armadura - Aço CA60 - ø 5.0 mm | 0.411539 | Pilar C-30 - Retangular 17x30
P57 | VIGA BALDRAME | retangular | 14 | 30 | 0 | 0.75 % | 0.04 | 0.03 | Concreto - C-30 - Abatimento 12 cm | 0.0126 | Dimensionado | Forma - Estrutura - Concreto | 0.264 | Dimensionado | Armadura - Aço CA50 - ø 10.0 mm | 1.55367 | Armadura - Aço CA60 - ø 5.0 mm | 0.383795 | Pilar C-30 - Retangular 14x30
P58 | VIGA BALDRAME | retangular | 14 | 30 | 0 | 1.12 % | 0.11 | 0.09 | Concreto - C-30 - Abatimento 12 cm | 0.0126 | Dimensionado | Forma - Estrutura - Concreto | 0.264 | Dimensionado | Armadura - Aço CA50 - ø 10.0 mm | 1.89894 | Armadura - Aço CA60 - ø 5.0 mm | 0.499395 | Pilar C-30 - Retangular 14x30
P59 | VIGA BALDRAME | retangular | 14 | 30 | 0 | Não calculado | Não calculado | Não calculado |  |  | Não dimensionado |  |  |  |  |  |  |  | Pilar C-30 - Retangular 14x30
P6 | VIGA BALDRAME | retangular | 14 | 30 | 0 | Não calculado | Não calculado | Não calculado |  |  | Não dimensionado |  |  |  |  |  |  |  | Pilar C-30 - Retangular 14x30
P60 | VIGA BALDRAME | retangular | 14 | 30 | 0 | 0.75 % | 0.13 | 0.12 | Concreto - C-30 - Abatimento 12 cm | 0.0126 | Dimensionado | Forma - Estrutura - Concreto | 0.264 | Dimensionado | Armadura - Aço CA50 - ø 10.0 mm | 1.55367 | Armadura - Aço CA60 - ø 5.0 mm | 0.383795 | Pilar C-30 - Retangular 14x30
P61 | VIGA BALDRAME | retangular | 14 | 30 | 0 | Não calculado | Não calculado | Não calculado |  |  | Não dimensionado |  |  |  |  |  |  |  | Pilar C-30 - Retangular 14x30
P62 | VIGA BALDRAME | retangular | 14 | 30 | 0 | 0.75 % | 0.14 | 0.12 | Concreto - C-30 - Abatimento 12 cm | 0.0126 | Dimensionado | Forma - Estrutura - Concreto | 0.264 | Dimensionado | Armadura - Aço CA50 - ø 10.0 mm | 1.55367 | Armadura - Aço CA60 - ø 5.0 mm | 0.383795 | Pilar C-30 - Retangular 14x30
P63 | VIGA BALDRAME | retangular | 14 | 30 | 0 | 0.75 % | 0.04 | 0.04 | Concreto - C-30 - Abatimento 12 cm | 0.0126 | Dimensionado | Forma - Estrutura - Concreto | 0.264 | Dimensionado | Armadura - Aço CA50 - ø 10.0 mm | 2.37983 | Armadura - Aço CA60 - ø 5.0 mm | 0.383795 | Pilar C-30 - Retangular 14x30
P64 | VIGA BALDRAME | retangular | 14 | 30 | 0 | Não calculado | Não calculado | Não calculado |  |  | Não dimensionado |  |  |  |  |  |  |  | Pilar C-30 - Retangular 14x30
P65 | VIGA BALDRAME | retangular | 17 | 30 | 0 | 0.92 % | 0.11 | 0.1 | Concreto - C-30 - Abatimento 12 cm | 0.0153 | Dimensionado | Forma - Estrutura - Concreto | 0.282 | Dimensionado | Armadura - Aço CA50 - ø 10.0 mm | 1.89894 | Armadura - Aço CA60 - ø 5.0 mm | 0.541012 | Pilar C-30 - Retangular 17x30
P66 | VIGA BALDRAME | retangular | 14 | 30 | 0 | 0.75 % | 0.17 | 0.15 | Concreto - C-30 - Abatimento 12 cm | 0.0126 | Dimensionado | Forma - Estrutura - Concreto | 0.264 | Dimensionado | Armadura - Aço CA50 - ø 10.0 mm | 1.55367 | Armadura - Aço CA60 - ø 5.0 mm | 0.383795 | Pilar C-30 - Retangular 14x30
P67 | VIGA BALDRAME | retangular | 14 | 20 | 0 | Não calculado | Não calculado | Não calculado |  |  | Não dimensionado |  |  |  |  |  |  |  | Pilar C-30 - Retangular 14x20
P68 | VIGA BALDRAME | retangular | 20 | 20 | 30 | Não calculado | Não calculado | Não calculado |  |  | Não dimensionado |  |  |  |  |  |  |  | Pilar C-30 - Retangular 20x20
P69 | VIGA BALDRAME | retangular | 14 | 30 | 0 | 1.50 % | 0.13 | 0.11 | Concreto - C-30 - Abatimento 12 cm | 0.0126 | Dimensionado | Forma - Estrutura - Concreto | 0.264 | Dimensionado | Armadura - Aço CA50 - ø 10.0 mm | 2.67577 | Armadura - Aço CA60 - ø 5.0 mm | 0.383795 | Pilar C-30 - Retangular 14x30
P7 | VIGA BALDRAME | retangular | 14 | 30 | 0 | Não calculado | Não calculado | Não calculado |  |  | Não dimensionado |  |  |  |  |  |  |  | Pilar C-30 - Retangular 14x30
P70 | VIGA BALDRAME | retangular | 14 | 30 | 0 | Não calculado | Não calculado | Não calculado |  |  | Não dimensionado |  |  |  |  |  |  |  | Pilar C-30 - Retangular 14x30
P71 | VIGA BALDRAME | retangular | 14 | 30 | 0 | 0.75 % | 0.22 | 0.19 | Concreto - C-30 - Abatimento 12 cm | 0.0126 | Dimensionado | Forma - Estrutura - Concreto | 0.264 | Dimensionado | Armadura - Aço CA50 - ø 10.0 mm | 1.55367 | Armadura - Aço CA60 - ø 5.0 mm | 0.383795 | Pilar C-30 - Retangular 14x30
P72 | VIGA BALDRAME | retangular | 14 | 30 | 0 | 0.75 % | 0.14 | 0.12 | Concreto - C-30 - Abatimento 12 cm | 0.0126 | Dimensionado | Forma - Estrutura - Concreto | 0.264 | Dimensionado | Armadura - Aço CA50 - ø 10.0 mm | 1.55367 | Armadura - Aço CA60 - ø 5.0 mm | 0.383795 | Pilar C-30 - Retangular 14x30
P73 | VIGA BALDRAME | retangular | 14 | 35 | 0 | 0.96 % | 0.12 | 0.1 | Concreto - C-30 - Abatimento 12 cm | 0.0147 | Dimensionado | Forma - Estrutura - Concreto | 0.294 | Dimensionado | Armadura - Aço CA50 - ø 10.0 mm | 2.33051 | Armadura - Aço CA60 - ø 5.0 mm | 0.545636 | Pilar C-30 - Retangular 14x35
P74 | VIGA BALDRAME | retangular | 24 | 30 | 0 | 0.44 % | 0.07 | 0.06 | Concreto - C-30 - Abatimento 12 cm | 0.0216 | Dimensionado | Forma - Estrutura - Concreto | 0.324 | Dimensionado | Armadura - Aço CA50 - ø 10.0 mm | 1.55367 | Armadura - Aço CA60 - ø 5.0 mm | 0.476275 | Pilar C-30 - Retangular 24x30
P75 | VIGA BALDRAME | retangular | 14 | 30 | 0 | Não calculado | Não calculado | Não calculado |  |  | Não dimensionado |  |  |  |  |  |  |  | Pilar C-30 - Retangular 14x30
P76 | VIGA BALDRAME | retangular | 14 | 25 | 0 | Não calculado | Não calculado | Não calculado |  |  | Não dimensionado |  |  |  |  |  |  |  | Pilar C-30 - Retangular 14x25
P77 | VIGA BALDRAME | retangular | 14 | 30 | 0 | Não calculado | Não calculado | Não calculado |  |  | Não dimensionado |  |  |  |  |  |  |  | Pilar C-30 - Retangular 14x30
P78 | VIGA BALDRAME | retangular | 14 | 30 | 0 | Não calculado | Não calculado | Não calculado |  |  | Não dimensionado |  |  |  |  |  |  |  | Pilar C-30 - Retangular 14x30
P79 | VIGA BALDRAME | retangular | 14 | 30 | 0 | 0.75 % | 0.06 | 0.05 | Concreto - C-30 - Abatimento 12 cm | 0.0126 | Dimensionado | Forma - Estrutura - Concreto | 0.264 | Dimensionado | Armadura - Aço CA50 - ø 10.0 mm | 0.690522 | Armadura - Aço CA60 - ø 5.0 mm | 0.383795 | Pilar C-30 - Retangular 14x30
P8 | VIGA BALDRAME | retangular | 14 | 30 | 0 | Não calculado | Não calculado | Não calculado |  |  | Não dimensionado |  |  |  |  |  |  |  | Pilar C-30 - Retangular 14x30
P80 | VIGA BALDRAME | retangular | 14 | 30 | 0 | 0.75 % | 0.06 | 0.06 | Concreto - C-30 - Abatimento 12 cm | 0.0126 | Dimensionado | Forma - Estrutura - Concreto | 0.264 | Dimensionado | Armadura - Aço CA50 - ø 10.0 mm | 0.690522 | Armadura - Aço CA60 - ø 5.0 mm | 0.383795 | Pilar C-30 - Retangular 14x30
P81 | VIGA BALDRAME | retangular | 14 | 30 | 0 | Não calculado | Não calculado | Não calculado |  |  | Não dimensionado |  |  |  |  |  |  |  | Pilar C-30 - Retangular 14x30
P82 | VIGA BALDRAME | retangular | 14 | 30 | 0 | Não calculado | Não calculado | Não calculado |  |  | Não dimensionado |  |  |  |  |  |  |  | Pilar C-30 - Retangular 14x30
P83 | VIGA BALDRAME | retangular | 14 | 30 | 0 | Não calculado | Não calculado | Não calculado |  |  | Não dimensionado |  |  |  |  |  |  |  | Pilar C-30 - Retangular 14x30
P84 | VIGA BALDRAME | retangular | 14 | 30 | 0 | Não calculado | Não calculado | Não calculado |  |  | Não dimensionado |  |  |  |  |  |  |  | Pilar C-30 - Retangular 14x30
P85 | VIGA BALDRAME | retangular | 14 | 25 | 0 | Não calculado | Não calculado | Não calculado |  |  | Não dimensionado |  |  |  |  |  |  |  | Pilar C-30 - Retangular 14x25
P86 | VIGA BALDRAME | retangular | 14 | 30 | 0 | Não calculado | Não calculado | Não calculado |  |  | Não dimensionado |  |  |  |  |  |  |  | Pilar C-30 - Retangular 14x30
P87 | VIGA BALDRAME | retangular | 14 | 30 | 0 | 0.75 % | 0.18 | 0.16 | Concreto - C-30 - Abatimento 12 cm | 0.0126 | Dimensionado | Forma - Estrutura - Concreto | 0.264 | Dimensionado | Armadura - Aço CA50 - ø 10.0 mm | 1.55367 | Armadura - Aço CA60 - ø 5.0 mm | 0.383795 | Pilar C-30 - Retangular 14x30
P88 | VIGA BALDRAME | retangular | 20 | 20 | 0 | Não calculado | Não calculado | Não calculado |  |  | Não dimensionado |  |  |  |  |  |  |  | Pilar C-30 - Retangular 20x20
P89 | VIGA BALDRAME | retangular | 14 | 20 | 30 | Não calculado | Não calculado | Não calculado |  |  | Não dimensionado |  |  |  |  |  |  |  | Pilar C-30 - Retangular 14x20
P9 | VIGA BALDRAME | retangular | 14 | 30 | 0 | Não calculado | Não calculado | Não calculado |  |  | Não dimensionado |  |  |  |  |  |  |  | Pilar C-30 - Retangular 14x30
P90 | VIGA BALDRAME | retangular | 14 | 30 | 0 | 0.75 % | 0.07 | 0.06 | Concreto - C-30 - Abatimento 12 cm | 0.0126 | Dimensionado | Forma - Estrutura - Concreto | 0.264 | Dimensionado | Armadura - Aço CA50 - ø 10.0 mm | 1.55367 | Armadura - Aço CA60 - ø 5.0 mm | 0.383795 | Pilar C-30 - Retangular 14x30
P91 | VIGA BALDRAME | retangular | 14 | 30 | 0 | 0.75 % | 0.09 | 0.08 | Concreto - C-30 - Abatimento 12 cm | 0.0126 | Dimensionado | Forma - Estrutura - Concreto | 0.264 | Dimensionado | Armadura - Aço CA50 - ø 10.0 mm | 1.55367 | Armadura - Aço CA60 - ø 5.0 mm | 0.383795 | Pilar C-30 - Retangular 14x30
P92 | VIGA BALDRAME | retangular | 24 | 30 | 0 | 0.44 % | 0.03 | 0.03 | Concreto - C-30 - Abatimento 12 cm | 0.0216 | Dimensionado | Forma - Estrutura - Concreto | 0.324 | Dimensionado | Armadura - Aço CA50 - ø 10.0 mm | 1.55367 | Armadura - Aço CA60 - ø 5.0 mm | 0.476275 | Pilar C-30 - Retangular 24x30
P93 | VIGA BALDRAME | retangular | 14 | 30 | 0 | Não calculado | Não calculado | Não calculado |  |  | Não dimensionado |  |  |  |  |  |  |  | Pilar C-30 - Retangular 14x30
P94 | VIGA BALDRAME | retangular | 17 | 30 | 0 | 0.92 % | 0.11 | 0.1 | Concreto - C-30 - Abatimento 12 cm | 0.0153 | Dimensionado | Forma - Estrutura - Concreto | 0.282 | Dimensionado | Armadura - Aço CA50 - ø 10.0 mm | 1.89894 | Armadura - Aço CA60 - ø 5.0 mm | 0.541012 | Pilar C-30 - Retangular 17x30
P95 | VIGA BALDRAME | retangular | 14 | 30 | 0 | 0.75 % | 0.17 | 0.15 | Concreto - C-30 - Abatimento 12 cm | 0.0126 | Dimensionado | Forma - Estrutura - Concreto | 0.264 | Dimensionado | Armadura - Aço CA50 - ø 10.0 mm | 1.55367 | Armadura - Aço CA60 - ø 5.0 mm | 0.383795 | Pilar C-30 - Retangular 14x30
P96 | VIGA BALDRAME | retangular | 17 | 30 | 0 | 0.62 % | 0.11 | 0.1 | Concreto - C-30 - Abatimento 12 cm | 0.0153 | Dimensionado | Forma - Estrutura - Concreto | 0.282 | Dimensionado | Armadura - Aço CA50 - ø 10.0 mm | 1.55367 | Armadura - Aço CA60 - ø 5.0 mm | 0.411539 | Pilar C-30 - Retangular 17x30
P97 | VIGA BALDRAME | retangular | 17 | 30 | 0 | 0.62 % | 0.1 | 0.09 | Concreto - C-30 - Abatimento 12 cm | 0.0153 | Dimensionado | Forma - Estrutura - Concreto | 0.282 | Dimensionado | Armadura - Aço CA50 - ø 10.0 mm | 1.55367 | Armadura - Aço CA60 - ø 5.0 mm | 0.411539 | Pilar C-30 - Retangular 17x30
P98 | VIGA BALDRAME | retangular | 14 | 30 | 0 | 0.75 % | 0.26 | 0.23 | Concreto - C-30 - Abatimento 12 cm | 0.0126 | Dimensionado | Forma - Estrutura - Concreto | 0.264 | Dimensionado | Armadura - Aço CA50 - ø 10.0 mm | 1.55367 | Armadura - Aço CA60 - ø 5.0 mm | 0.383795 | Pilar C-30 - Retangular 14x30
P99 | VIGA BALDRAME | retangular | 14 | 30 | 0 | 0.75 % | 0.18 | 0.16 | Concreto - C-30 - Abatimento 12 cm | 0.0126 | Dimensionado | Forma - Estrutura - Concreto | 0.264 | Dimensionado | Armadura - Aço CA50 - ø 10.0 mm | 1.55367 | Armadura - Aço CA60 - ø 5.0 mm | 0.383795 | Pilar C-30 - Retangular 14x30
PM1 | VIGA BALDRAME | retangular | 20 | 20 | 0 | 0.79 % | 0.01 | 0.01 | Concreto - C-30 - Abatimento 12 cm | 0.012 | Dimensionado | Forma - Estrutura - Concreto | 0.24 | Dimensionado | Armadura - Aço CA50 - ø 10.0 mm | 0.690522 | Armadura - Aço CA60 - ø 5.0 mm | 0.346802 | Pilar C-30 - Retangular 20x20
PM2 | VIGA BALDRAME | retangular | 20 | 20 | 0 | 0.79 % | 0.01 | 0.01 | Concreto - C-30 - Abatimento 12 cm | 0.012 | Dimensionado | Forma - Estrutura - Concreto | 0.24 | Dimensionado | Armadura - Aço CA50 - ø 10.0 mm | 0.690522 | Armadura - Aço CA60 - ø 5.0 mm | 0.346802 | Pilar C-30 - Retangular 20x20
P1 | TERREO | retangular | 14 | 30 | 0 | Não calculado | Não calculado | Não calculado |  |  | Não dimensionado |  |  |  |  |  |  |  | Pilar C-30 - Retangular 14x30
P10 | TERREO | retangular | 14 | 30 | 0 | Não calculado | Não calculado | Não calculado |  |  | Não dimensionado |  |  |  |  |  |  |  | Pilar C-30 - Retangular 14x30
P100 | TERREO | retangular | 14 | 30 | 0 | Não calculado | Não calculado | Não calculado |  |  | Não dimensionado |  |  |  |  |  |  |  | Pilar C-30 - Retangular 14x30
P101 | TERREO | retangular | 14 | 30 | 0 | Não calculado | Não calculado | Não calculado |  |  | Não dimensionado |  |  |  |  |  |  |  | Pilar C-30 - Retangular 14x30
P102 | TERREO | retangular | 14 | 30 | 0 | 1.12 % | 0.04 | 0.03 | Concreto - C-30 - Abatimento 12 cm | 0.1302 | Dimensionado | Forma - Estrutura - Concreto | 2.728 | Dimensionado | Armadura - Aço CA50 - ø 10.0 mm | 11.3936 | Armadura - Aço CA60 - ø 5.0 mm | 4.32809 | Pilar C-30 - Retangular 14x30
P103 | TERREO | retangular | 14 | 30 | 0 | Não calculado | Não calculado | Não calculado |  |  | Não dimensionado |  |  |  |  |  |  |  | Pilar C-30 - Retangular 14x30
P104 | TERREO | retangular | 14 | 30 | 0 | Não calculado | Não calculado | Não calculado |  |  | Não dimensionado |  |  |  |  |  |  |  | Pilar C-30 - Retangular 14x30
P105 | TERREO | retangular | 14 | 30 | 0 | Não calculado | Não calculado | Não calculado |  |  | Não dimensionado |  |  |  |  |  |  |  | Pilar C-30 - Retangular 14x30
P106 | TERREO | retangular | 14 | 30 | 0 | 0.75 % | 0.05 | 0.05 | Concreto - C-30 - Abatimento 12 cm | 0.1302 | Dimensionado | Forma - Estrutura - Concreto | 2.728 | Dimensionado | Armadura - Aço CA50 - ø 10.0 mm | 8.4589 | Armadura - Aço CA60 - ø 5.0 mm | 3.32622 | Pilar C-30 - Retangular 14x30
P107 | TERREO | retangular | 14 | 30 | 0 | Não calculado | Não calculado | Não calculado |  |  | Não dimensionado |  |  |  |  |  |  |  | Pilar C-30 - Retangular 14x30
P108 | TERREO | retangular | 14 | 30 | 0 | Não calculado | Não calculado | Não calculado |  |  | Não dimensionado |  |  |  |  |  |  |  | Pilar C-30 - Retangular 14x30
P109 | TERREO | retangular | 14 | 30 | 0 | 0.75 % | 0.04 | 0.04 | Concreto - C-30 - Abatimento 12 cm | 0.1302 | Dimensionado | Forma - Estrutura - Concreto | 2.728 | Dimensionado | Armadura - Aço CA50 - ø 10.0 mm | 7.59574 | Armadura - Aço CA60 - ø 5.0 mm | 3.32622 | Pilar C-30 - Retangular 14x30
P11 | TERREO | retangular | 14 | 30 | 0 | Não calculado | Não calculado | Não calculado |  |  | Não dimensionado |  |  |  |  |  |  |  | Pilar C-30 - Retangular 14x30
P110 | TERREO | retangular | 14 | 30 | 0 | Não calculado | Não calculado | Não calculado |  |  | Não dimensionado |  |  |  |  |  |  |  | Pilar C-30 - Retangular 14x30
P112 | TERREO | retangular | 14 | 30 | 0 | 0.75 % | 0.02 | 0.02 | Concreto - C-30 - Abatimento 12 cm | 0.1302 | Dimensionado | Forma - Estrutura - Concreto | 2.728 | Dimensionado | Armadura - Aço CA50 - ø 10.0 mm | 7.59574 | Armadura - Aço CA60 - ø 5.0 mm | 3.32622 | Pilar C-30 - Retangular 14x30
P113 | TERREO | retangular | 17 | 30 | 0 | 0.62 % | 0.05 | 0.04 | Concreto - C-30 - Abatimento 12 cm | 0.1581 | Dimensionado | Forma - Estrutura - Concreto | 2.914 | Dimensionado | Armadura - Aço CA50 - ø 10.0 mm | 8.4589 | Armadura - Aço CA60 - ø 5.0 mm | 3.56667 | Pilar C-30 - Retangular 17x30
P114 | TERREO | retangular | 14 | 30 | 0 | Não calculado | Não calculado | Não calculado |  |  | Não dimensionado |  |  |  |  |  |  |  | Pilar C-30 - Retangular 14x30
P115 | TERREO | retangular | 14 | 30 | 0 | Não calculado | Não calculado | Não calculado |  |  | Não dimensionado |  |  |  |  |  |  |  | Pilar C-30 - Retangular 14x30
P116 | TERREO | retangular | 17 | 30 | 0 | 0.62 % | 0.05 | 0.04 | Concreto - C-30 - Abatimento 12 cm | 0.1581 | Dimensionado | Forma - Estrutura - Concreto | 2.914 | Dimensionado | Armadura - Aço CA50 - ø 10.0 mm | 8.4589 | Armadura - Aço CA60 - ø 5.0 mm | 3.56667 | Pilar C-30 - Retangular 17x30
P117 | TERREO | retangular | 14 | 30 | 0 | Não calculado | Não calculado | Não calculado |  |  | Não dimensionado |  |  |  |  |  |  |  | Pilar C-30 - Retangular 14x30
P118 | TERREO | retangular | 14 | 30 | 0 | Não calculado | Não calculado | Não calculado |  |  | Não dimensionado |  |  |  |  |  |  |  | Pilar C-30 - Retangular 14x30
P119 | TERREO | retangular | 14 | 30 | 0 | 0.75 % | 0.06 | 0.05 | Concreto - C-30 - Abatimento 12 cm | 0.1302 | Dimensionado | Forma - Estrutura - Concreto | 2.728 | Dimensionado | Armadura - Aço CA50 - ø 10.0 mm | 7.59574 | Armadura - Aço CA60 - ø 5.0 mm | 3.32622 | Pilar C-30 - Retangular 14x30
P12 | TERREO | retangular | 14 | 30 | 0 | Não calculado | Não calculado | Não calculado |  |  | Não dimensionado |  |  |  |  |  |  |  | Pilar C-30 - Retangular 14x30
P120 | TERREO | retangular | 14 | 30 | 0 | 0.75 % | 0.11 | 0.09 | Concreto - C-30 - Abatimento 12 cm | 0.1302 | Dimensionado | Forma - Estrutura - Concreto | 2.728 | Dimensionado | Armadura - Aço CA50 - ø 10.0 mm | 8.4589 | Armadura - Aço CA60 - ø 5.0 mm | 3.32622 | Pilar C-30 - Retangular 14x30
P121 | TERREO | retangular | 14 | 30 | 0 | 0.75 % | 0.1 | 0.09 | Concreto - C-30 - Abatimento 12 cm | 0.1302 | Dimensionado | Forma - Estrutura - Concreto | 2.728 | Dimensionado | Armadura - Aço CA50 - ø 10.0 mm | 9.28506 | Armadura - Aço CA60 - ø 5.0 mm | 3.32622 | Pilar C-30 - Retangular 14x30
P122 | TERREO | retangular | 14 | 30 | 0 | 0.75 % | 0.05 | 0.04 | Concreto - C-30 - Abatimento 12 cm | 0.1302 | Dimensionado | Forma - Estrutura - Concreto | 2.728 | Dimensionado | Armadura - Aço CA50 - ø 10.0 mm | 7.59574 | Armadura - Aço CA60 - ø 5.0 mm | 3.32622 | Pilar C-30 - Retangular 14x30
P123 | TERREO | retangular | 14 | 30 | 0 | Não calculado | Não calculado | Não calculado |  |  | Não dimensionado |  |  |  |  |  |  |  | Pilar C-30 - Retangular 14x30
P124 | TERREO | retangular | 17 | 30 | 0 | 0.62 % | 0.05 | 0.04 | Concreto - C-30 - Abatimento 12 cm | 0.158099 | Dimensionado | Forma - Estrutura - Concreto | 2.91399 | Dimensionado | Armadura - Aço CA50 - ø 10.0 mm | 8.4589 | Armadura - Aço CA60 - ø 5.0 mm | 3.56667 | Pilar C-30 - Retangular 17x30
P125 | TERREO | retangular | 14 | 30 | 0 | Não calculado | Não calculado | Não calculado |  |  | Não dimensionado |  |  |  |  |  |  |  | Pilar C-30 - Retangular 14x30
P126 | TERREO | retangular | 14 | 30 | 0 | Não calculado | Não calculado | Não calculado |  |  | Não dimensionado |  |  |  |  |  |  |  | Pilar C-30 - Retangular 14x30
P127 | TERREO | retangular | 14 | 30 | 0 | Não calculado | Não calculado | Não calculado |  |  | Não dimensionado |  |  |  |  |  |  |  | Pilar C-30 - Retangular 14x30
P128 | TERREO | retangular | 14 | 30 | 0 | 0.75 % | 0.02 | 0.02 | Concreto - C-30 - Abatimento 12 cm | 0.1302 | Dimensionado | Forma - Estrutura - Concreto | 2.728 | Dimensionado | Armadura - Aço CA50 - ø 10.0 mm | 8.4589 | Armadura - Aço CA60 - ø 5.0 mm | 3.32622 | Pilar C-30 - Retangular 14x30
P129 | TERREO | retangular | 14 | 30 | 0 | 0.75 % | 0.05 | 0.04 | Concreto - C-30 - Abatimento 12 cm | 0.1302 | Dimensionado | Forma - Estrutura - Concreto | 2.728 | Dimensionado | Armadura - Aço CA50 - ø 10.0 mm | 7.59574 | Armadura - Aço CA60 - ø 5.0 mm | 3.32622 | Pilar C-30 - Retangular 14x30
P13 | TERREO | retangular | 14 | 30 | 0 | Não calculado | Não calculado | Não calculado |  |  | Não dimensionado |  |  |  |  |  |  |  | Pilar C-30 - Retangular 14x30
P130 | TERREO | retangular | 14 | 30 | 0 | Não calculado | Não calculado | Não calculado |  |  | Não dimensionado |  |  |  |  |  |  |  | Pilar C-30 - Retangular 14x30
P131 | TERREO | retangular | 14 | 30 | 0 | 0.75 % | 0.03 | 0.03 | Concreto - C-30 - Abatimento 12 cm | 0.1302 | Dimensionado | Forma - Estrutura - Concreto | 2.728 | Dimensionado | Armadura - Aço CA50 - ø 10.0 mm | 7.59574 | Armadura - Aço CA60 - ø 5.0 mm | 3.32622 | Pilar C-30 - Retangular 14x30
P132 | TERREO | retangular | 14 | 30 | 0 | Não calculado | Não calculado | Não calculado |  |  | Não dimensionado |  |  |  |  |  |  |  | Pilar C-30 - Retangular 14x30
P133 | TERREO | retangular | 14 | 30 | 0 | Não calculado | Não calculado | Não calculado |  |  | Não dimensionado |  |  |  |  |  |  |  | Pilar C-30 - Retangular 14x30
P134 | TERREO | retangular | 14 | 30 | 0 | Não calculado | Não calculado | Não calculado |  |  | Não dimensionado |  |  |  |  |  |  |  | Pilar C-30 - Retangular 14x30
P135 | TERREO | retangular | 14 | 30 | 0 | 1.12 % | 0.05 | 0.04 | Concreto - C-30 - Abatimento 12 cm | 0.1302 | Dimensionado | Forma - Estrutura - Concreto | 2.728 | Dimensionado | Armadura - Aço CA50 - ø 10.0 mm | 12.2568 | Armadura - Aço CA60 - ø 5.0 mm | 4.32809 | Pilar C-30 - Retangular 14x30
P136 | TERREO | retangular | 14 | 30 | 0 | 0.75 % | 0.05 | 0.04 | Concreto - C-30 - Abatimento 12 cm | 0.1302 | Dimensionado | Forma - Estrutura - Concreto | 2.728 | Dimensionado | Armadura - Aço CA50 - ø 10.0 mm | 7.59574 | Armadura - Aço CA60 - ø 5.0 mm | 3.32622 | Pilar C-30 - Retangular 14x30
P137 | TERREO | retangular | 14 | 30 | 0 | 0.75 % | 0.04 | 0.03 | Concreto - C-30 - Abatimento 12 cm | 0.1302 | Dimensionado | Forma - Estrutura - Concreto | 2.728 | Dimensionado | Armadura - Aço CA50 - ø 10.0 mm | 8.4589 | Armadura - Aço CA60 - ø 5.0 mm | 3.32622 | Pilar C-30 - Retangular 14x30
P138 | TERREO | retangular | 14 | 30 | 0 | 0.75 % | 0.03 | 0.03 | Concreto - C-30 - Abatimento 12 cm | 0.1302 | Dimensionado | Forma - Estrutura - Concreto | 2.728 | Dimensionado | Armadura - Aço CA50 - ø 10.0 mm | 8.4589 | Armadura - Aço CA60 - ø 5.0 mm | 3.32622 | Pilar C-30 - Retangular 14x30
P139 | TERREO | retangular | 14 | 30 | 0 | 0.75 % | 0.04 | 0.03 | Concreto - C-30 - Abatimento 12 cm | 0.1302 | Dimensionado | Forma - Estrutura - Concreto | 2.72801 | Dimensionado | Armadura - Aço CA50 - ø 10.0 mm | 8.4589 | Armadura - Aço CA60 - ø 5.0 mm | 3.32622 | Pilar C-30 - Retangular 14x30
P14 | TERREO | retangular | 14 | 30 | 0 | Não calculado | Não calculado | Não calculado |  |  | Não dimensionado |  |  |  |  |  |  |  | Pilar C-30 - Retangular 14x30
P140 | TERREO | retangular | 14 | 30 | 0 | 1.12 % | 0.05 | 0.04 | Concreto - C-30 - Abatimento 12 cm | 0.1302 | Dimensionado | Forma - Estrutura - Concreto | 2.728 | Dimensionado | Armadura - Aço CA50 - ø 10.0 mm | 12.2568 | Armadura - Aço CA60 - ø 5.0 mm | 4.32809 | Pilar C-30 - Retangular 14x30
P141 | TERREO | retangular | 14 | 30 | 0 | 0.75 % | 0 | 0 | Concreto - C-30 - Abatimento 12 cm | 0.0189 | Dimensionado | Forma - Estrutura - Concreto | 0.396001 | Dimensionado | Armadura - Aço CA50 - ø 10.0 mm | 1.06045 | Armadura - Aço CA60 - ø 5.0 mm | 0.511726 | Pilar C-30 - Retangular 14x30
P142 | TERREO | retangular | 14 | 30 | 0 | 1.75 % | 0.01 | 0 | Concreto - C-30 - Abatimento 12 cm | 0.0189 | Dimensionado | Forma - Estrutura - Concreto | 0.396 | Dimensionado | Armadura - Aço CA50 - ø 12.5 mm | 2.48542 | Armadura - Aço CA60 - ø 5.0 mm | 1.99758 | Pilar C-30 - Retangular 14x30
P143 | TERREO | retangular | 14 | 30 | 0 | 0.75 % | 0.04 | 0.04 | Concreto - C-30 - Abatimento 12 cm | 0.1302 | Dimensionado | Forma - Estrutura - Concreto | 2.728 | Dimensionado | Armadura - Aço CA50 - ø 10.0 mm | 8.4589 | Armadura - Aço CA60 - ø 5.0 mm | 3.32622 | Pilar C-30 - Retangular 14x30
P144 | TERREO | retangular | 14 | 30 | -40 | Não calculado | Não calculado | Não calculado |  |  | Não dimensionado |  |  |  |  |  |  |  | Pilar C-30 - Retangular 14x30
P145 | TERREO | retangular | 14 | 30 | 0 | 0.75 % | 0.04 | 0.04 | Concreto - C-30 - Abatimento 12 cm | 0.1302 | Dimensionado | Forma - Estrutura - Concreto | 2.728 | Dimensionado | Armadura - Aço CA50 - ø 10.0 mm | 8.4589 | Armadura - Aço CA60 - ø 5.0 mm | 3.32622 | Pilar C-30 - Retangular 14x30
P146 | TERREO | retangular | 14 | 30 | 0 | 0.75 % | 0.05 | 0.04 | Concreto - C-30 - Abatimento 12 cm | 0.1302 | Dimensionado | Forma - Estrutura - Concreto | 2.728 | Dimensionado | Armadura - Aço CA50 - ø 10.0 mm | 8.4589 | Armadura - Aço CA60 - ø 5.0 mm | 3.32622 | Pilar C-30 - Retangular 14x30
P147 | TERREO | retangular | 14 | 30 | 0 | 0.75 % | 0.05 | 0.05 | Concreto - C-30 - Abatimento 12 cm | 0.1302 | Dimensionado | Forma - Estrutura - Concreto | 2.728 | Dimensionado | Armadura - Aço CA50 - ø 10.0 mm | 8.4589 | Armadura - Aço CA60 - ø 5.0 mm | 3.32622 | Pilar C-30 - Retangular 14x30
P148 | TERREO | retangular | 14 | 30 | 0 | 0.75 % | 0.06 | 0.05 | Concreto - C-30 - Abatimento 12 cm | 0.1302 | Dimensionado | Forma - Estrutura - Concreto | 2.728 | Dimensionado | Armadura - Aço CA50 - ø 10.0 mm | 8.4589 | Armadura - Aço CA60 - ø 5.0 mm | 3.32622 | Pilar C-30 - Retangular 14x30
P149 | TERREO | retangular | 14 | 30 | 0 | Não calculado | Não calculado | Não calculado |  |  | Não dimensionado |  |  |  |  |  |  |  | Pilar C-30 - Retangular 14x30
P15 | TERREO | retangular | 14 | 30 | 0 | Não calculado | Não calculado | Não calculado |  |  | Não dimensionado |  |  |  |  |  |  |  | Pilar C-30 - Retangular 14x30
P150 | TERREO | retangular | 14 | 30 | 0 | 0.75 % | 0 | 0 | Concreto - C-30 - Abatimento 12 cm | 0.0189 | Dimensionado | Forma - Estrutura - Concreto | 0.396 | Dimensionado | Armadura - Aço CA50 - ø 10.0 mm | 1.06045 | Armadura - Aço CA60 - ø 5.0 mm | 0.511726 | Pilar C-30 - Retangular 14x30
P152 | TERREO | retangular | 14 | 30 | 0 | 0.75 % | 0.02 | 0.01 | Concreto - C-30 - Abatimento 12 cm | 0.0882 | Dimensionado | Forma - Estrutura - Concreto | 1.848 | Dimensionado | Armadura - Aço CA50 - ø 10.0 mm | 5.12959 | Armadura - Aço CA60 - ø 5.0 mm | 2.30277 | Pilar C-30 - Retangular 14x30
P153 | TERREO | retangular | 14 | 30 | 0 | 0.75 % | 0.04 | 0.03 | Concreto - C-30 - Abatimento 12 cm | 0.0882 | Dimensionado | Forma - Estrutura - Concreto | 1.848 | Dimensionado | Armadura - Aço CA50 - ø 10.0 mm | 5.12959 | Armadura - Aço CA60 - ø 5.0 mm | 2.30277 | Pilar C-30 - Retangular 14x30
P154 | TERREO | retangular | 14 | 30 | 0 | 0.75 % | 0.02 | 0.02 | Concreto - C-30 - Abatimento 12 cm | 0.0882 | Dimensionado | Forma - Estrutura - Concreto | 1.848 | Dimensionado | Armadura - Aço CA50 - ø 10.0 mm | 5.12959 | Armadura - Aço CA60 - ø 5.0 mm | 2.30277 | Pilar C-30 - Retangular 14x30
P155 | TERREO | retangular | 14 | 30 | 0 | 1.12 % | 0.01 | 0.01 | Concreto - C-30 - Abatimento 12 cm | 0.0882 | Dimensionado | Forma - Estrutura - Concreto | 1.848 | Dimensionado | Armadura - Aço CA50 - ø 10.0 mm | 7.69439 | Armadura - Aço CA60 - ø 5.0 mm | 11.6526 | Pilar C-30 - Retangular 14x30
P156 | TERREO | retangular | 14 | 30 | 0 | Não calculado | Não calculado | Não calculado |  |  | Não dimensionado |  |  |  |  |  |  |  | Pilar C-30 - Retangular 14x30
P157 | TERREO | retangular | 14 | 30 | 0 | Não calculado | Não calculado | Não calculado |  |  | Não dimensionado |  |  |  |  |  |  |  | Pilar C-30 - Retangular 14x30
P158 | TERREO | retangular | 14 | 30 | 0 | Não calculado | Não calculado | Não calculado |  |  | Não dimensionado |  |  |  |  |  |  |  | Pilar C-30 - Retangular 14x30
P159 | TERREO | retangular | 14 | 30 | 0 | Não calculado | Não calculado | Não calculado |  |  | Não dimensionado |  |  |  |  |  |  |  | Pilar C-30 - Retangular 14x30
P16 | TERREO | retangular | 14 | 30 | 0 | Não calculado | Não calculado | Não calculado |  |  | Não dimensionado |  |  |  |  |  |  |  | Pilar C-30 - Retangular 14x30
P160 | TERREO | retangular | 14 | 30 | 0 | Não calculado | Não calculado | Não calculado |  |  | Não dimensionado |  |  |  |  |  |  |  | Pilar C-30 - Retangular 14x30
P161 | TERREO | retangular | 14 | 30 | 0 | Não calculado | Não calculado | Não calculado |  |  | Não dimensionado |  |  |  |  |  |  |  | Pilar C-30 - Retangular 14x30
P162 | TERREO | retangular | 14 | 30 | 0 | Não calculado | Não calculado | Não calculado |  |  | Não dimensionado |  |  |  |  |  |  |  | Pilar C-30 - Retangular 14x30
P163 | TERREO | retangular | 14 | 30 | 0 | Não calculado | Não calculado | Não calculado |  |  | Não dimensionado |  |  |  |  |  |  |  | Pilar C-30 - Retangular 14x30
P164 | TERREO | retangular | 14 | 30 | 0 | 0.75 % | 0.02 | 0.02 | Concreto - C-30 - Abatimento 12 cm | 0.0882 | Dimensionado | Forma - Estrutura - Concreto | 1.848 | Dimensionado | Armadura - Aço CA50 - ø 10.0 mm | 5.12959 | Armadura - Aço CA60 - ø 5.0 mm | 2.30277 | Pilar C-30 - Retangular 14x30
P165 | TERREO | retangular | 14 | 30 | 0 | 0.75 % | 0.02 | 0.02 | Concreto - C-30 - Abatimento 12 cm | 0.0882 | Dimensionado | Forma - Estrutura - Concreto | 1.848 | Dimensionado | Armadura - Aço CA50 - ø 10.0 mm | 5.12959 | Armadura - Aço CA60 - ø 5.0 mm | 2.30277 | Pilar C-30 - Retangular 14x30
P166 | TERREO | retangular | 14 | 30 | 0 | Não calculado | Não calculado | Não calculado |  |  | Não dimensionado |  |  |  |  |  |  |  | Pilar C-30 - Retangular 14x30
P167 | TERREO | retangular | 14 | 30 | 0 | Não calculado | Não calculado | Não calculado |  |  | Não dimensionado |  |  |  |  |  |  |  | Pilar C-30 - Retangular 14x30
P168 | TERREO | retangular | 14 | 30 | 0 | 0.75 % | 0.01 | 0 | Concreto - C-30 - Abatimento 12 cm | 0.0882 | Dimensionado | Forma - Estrutura - Concreto | 1.848 | Dimensionado | Armadura - Aço CA50 - ø 10.0 mm | 5.12959 | Armadura - Aço CA60 - ø 5.0 mm | 2.30277 | Pilar C-30 - Retangular 14x30
P17 | TERREO | retangular | 14 | 30 | 0 | 0.75 % | 0.05 | 0.04 | Concreto - C-30 - Abatimento 12 cm | 0.1302 | Dimensionado | Forma - Estrutura - Concreto | 2.728 | Dimensionado | Armadura - Aço CA50 - ø 10.0 mm | 8.4589 | Armadura - Aço CA60 - ø 5.0 mm | 3.32622 | Pilar C-30 - Retangular 14x30
P18 | TERREO | retangular | 14 | 30 | -40 | Não calculado | Não calculado | Não calculado |  |  | Não dimensionado |  |  |  |  |  |  |  | Pilar C-30 - Retangular 14x30
P19 | TERREO | retangular | 14 | 30 | 0 | 0.75 % | 0.06 | 0.05 | Concreto - C-30 - Abatimento 12 cm | 0.1302 | Dimensionado | Forma - Estrutura - Concreto | 2.728 | Dimensionado | Armadura - Aço CA50 - ø 10.0 mm | 8.4589 | Armadura - Aço CA60 - ø 5.0 mm | 3.32622 | Pilar C-30 - Retangular 14x30
P2 | TERREO | retangular | 14 | 30 | 0 | Não calculado | Não calculado | Não calculado |  |  | Não dimensionado |  |  |  |  |  |  |  | Pilar C-30 - Retangular 14x30
P20 | TERREO | retangular | 14 | 30 | 0 | 0.75 % | 0.07 | 0.06 | Concreto - C-30 - Abatimento 12 cm | 0.1302 | Dimensionado | Forma - Estrutura - Concreto | 2.728 | Dimensionado | Armadura - Aço CA50 - ø 10.0 mm | 9.28506 | Armadura - Aço CA60 - ø 5.0 mm | 3.32622 | Pilar C-30 - Retangular 14x30
P21 | TERREO | retangular | 14 | 30 | -40 | Não calculado | Não calculado | Não calculado |  |  | Não dimensionado |  |  |  |  |  |  |  | Pilar C-30 - Retangular 14x30
P22 | TERREO | retangular | 14 | 30 | 0 | 0.75 % | 0.04 | 0.03 | Concreto - C-30 - Abatimento 12 cm | 0.1302 | Dimensionado | Forma - Estrutura - Concreto | 2.728 | Dimensionado | Armadura - Aço CA50 - ø 10.0 mm | 8.4589 | Armadura - Aço CA60 - ø 5.0 mm | 3.32622 | Pilar C-30 - Retangular 14x30
P23 | TERREO | retangular | 14 | 30 | 0 | 1.12 % | 0.05 | 0.04 | Concreto - C-30 - Abatimento 12 cm | 0.1302 | Dimensionado | Forma - Estrutura - Concreto | 2.728 | Dimensionado | Armadura - Aço CA50 - ø 10.0 mm | 12.2568 | Armadura - Aço CA60 - ø 5.0 mm | 4.32809 | Pilar C-30 - Retangular 14x30
P24 | TERREO | retangular | 14 | 30 | 0 | 0.75 % | 0.05 | 0.04 | Concreto - C-30 - Abatimento 12 cm | 0.1302 | Dimensionado | Forma - Estrutura - Concreto | 2.728 | Dimensionado | Armadura - Aço CA50 - ø 10.0 mm | 7.59574 | Armadura - Aço CA60 - ø 5.0 mm | 3.32622 | Pilar C-30 - Retangular 14x30
P25 | TERREO | retangular | 14 | 30 | 0 | 0.75 % | 0.04 | 0.03 | Concreto - C-30 - Abatimento 12 cm | 0.1302 | Dimensionado | Forma - Estrutura - Concreto | 2.728 | Dimensionado | Armadura - Aço CA50 - ø 10.0 mm | 8.4589 | Armadura - Aço CA60 - ø 5.0 mm | 3.32622 | Pilar C-30 - Retangular 14x30
P26 | TERREO | retangular | 17 | 30 | 0 | 0.92 % | 0.04 | 0.04 | Concreto - C-30 - Abatimento 12 cm | 0.1581 | Dimensionado | Forma - Estrutura - Concreto | 2.914 | Dimensionado | Armadura - Aço CA50 - ø 10.0 mm | 12.2568 | Armadura - Aço CA60 - ø 5.0 mm | 4.68877 | Pilar C-30 - Retangular 17x30
P27 | TERREO | retangular | 14 | 30 | 0 | 0.75 % | 0.06 | 0.05 | Concreto - C-30 - Abatimento 12 cm | 0.1302 | Dimensionado | Forma - Estrutura - Concreto | 2.728 | Dimensionado | Armadura - Aço CA50 - ø 10.0 mm | 7.59574 | Armadura - Aço CA60 - ø 5.0 mm | 3.32622 | Pilar C-30 - Retangular 14x30
P28 | TERREO | retangular | 14 | 30 | 0 | 1.12 % | 0.05 | 0.04 | Concreto - C-30 - Abatimento 12 cm | 0.1302 | Dimensionado | Forma - Estrutura - Concreto | 2.728 | Dimensionado | Armadura - Aço CA50 - ø 10.0 mm | 12.2568 | Armadura - Aço CA60 - ø 5.0 mm | 4.32809 | Pilar C-30 - Retangular 14x30
P29 | TERREO | retangular | 14 | 30 | 0 | Não calculado | Não calculado | Não calculado |  |  | Não dimensionado |  |  |  |  |  |  |  | Pilar C-30 - Retangular 14x30
P3 | TERREO | retangular | 14 | 30 | 0 | Não calculado | Não calculado | Não calculado |  |  | Não dimensionado |  |  |  |  |  |  |  | Pilar C-30 - Retangular 14x30
P30 | TERREO | retangular | 14 | 30 | 0 | Não calculado | Não calculado | Não calculado |  |  | Não dimensionado |  |  |  |  |  |  |  | Pilar C-30 - Retangular 14x30
P31 | TERREO | retangular | 14 | 30 | 0 | Não calculado | Não calculado | Não calculado |  |  | Não dimensionado |  |  |  |  |  |  |  | Pilar C-30 - Retangular 14x30
P33 | TERREO | retangular | 14 | 30 | 0 | 0.75 % | 0.05 | 0.04 | Concreto - C-30 - Abatimento 12 cm | 0.1302 | Dimensionado | Forma - Estrutura - Concreto | 2.728 | Dimensionado | Armadura - Aço CA50 - ø 10.0 mm | 8.85348 | Armadura - Aço CA60 - ø 5.0 mm | 3.32622 | Pilar C-30 - Retangular 14x30
P34 | TERREO | retangular | 14 | 30 | 0 | 0.75 % | 0.04 | 0.04 | Concreto - C-30 - Abatimento 12 cm | 0.1302 | Dimensionado | Forma - Estrutura - Concreto | 2.728 | Dimensionado | Armadura - Aço CA50 - ø 10.0 mm | 7.59574 | Armadura - Aço CA60 - ø 5.0 mm | 3.32622 | Pilar C-30 - Retangular 14x30
P35 | TERREO | retangular | 14 | 30 | 0 | Não calculado | Não calculado | Não calculado |  |  | Não dimensionado |  |  |  |  |  |  |  | Pilar C-30 - Retangular 14x30
P36 | TERREO | retangular | 17 | 30 | 0 | 0.62 % | 0.05 | 0.04 | Concreto - C-30 - Abatimento 12 cm | 0.1581 | Dimensionado | Forma - Estrutura - Concreto | 2.914 | Dimensionado | Armadura - Aço CA50 - ø 10.0 mm | 8.4589 | Armadura - Aço CA60 - ø 5.0 mm | 3.56667 | Pilar C-30 - Retangular 17x30
P37 | TERREO | retangular | 14 | 30 | 0 | Não calculado | Não calculado | Não calculado |  |  | Não dimensionado |  |  |  |  |  |  |  | Pilar C-30 - Retangular 14x30
P38 | TERREO | retangular | 14 | 30 | 0 | Não calculado | Não calculado | Não calculado |  |  | Não dimensionado |  |  |  |  |  |  |  | Pilar C-30 - Retangular 14x30
P39 | TERREO | retangular | 14 | 30 | 0 | Não calculado | Não calculado | Não calculado |  |  | Não dimensionado |  |  |  |  |  |  |  | Pilar C-30 - Retangular 14x30
P4 | TERREO | retangular | 14 | 30 | 0 | Não calculado | Não calculado | Não calculado |  |  | Não dimensionado |  |  |  |  |  |  |  | Pilar C-30 - Retangular 14x30
P40 | TERREO | retangular | 14 | 30 | 0 | 0.75 % | 0.05 | 0.04 | Concreto - C-30 - Abatimento 12 cm | 0.1302 | Dimensionado | Forma - Estrutura - Concreto | 2.728 | Dimensionado | Armadura - Aço CA50 - ø 10.0 mm | 7.59574 | Armadura - Aço CA60 - ø 5.0 mm | 3.32622 | Pilar C-30 - Retangular 14x30
P41 | TERREO | retangular | 17 | 30 | 0 | 0.62 % | 0.03 | 0.03 | Concreto - C-30 - Abatimento 12 cm | 0.1581 | Dimensionado | Forma - Estrutura - Concreto | 2.914 | Dimensionado | Armadura - Aço CA50 - ø 10.0 mm | 8.4589 | Armadura - Aço CA60 - ø 5.0 mm | 3.56667 | Pilar C-30 - Retangular 17x30
P42 | TERREO | retangular | 17 | 30 | 0 | 0.92 % | 0.05 | 0.04 | Concreto - C-30 - Abatimento 12 cm | 0.1581 | Dimensionado | Forma - Estrutura - Concreto | 2.914 | Dimensionado | Armadura - Aço CA50 - ø 10.0 mm | 12.2568 | Armadura - Aço CA60 - ø 5.0 mm | 4.68877 | Pilar C-30 - Retangular 17x30
P43 | TERREO | retangular | 14 | 30 | 0 | 0.75 % | 0.06 | 0.05 | Concreto - C-30 - Abatimento 12 cm | 0.1302 | Dimensionado | Forma - Estrutura - Concreto | 2.728 | Dimensionado | Armadura - Aço CA50 - ø 10.0 mm | 7.59574 | Armadura - Aço CA60 - ø 5.0 mm | 3.32622 | Pilar C-30 - Retangular 14x30
P44 | TERREO | retangular | 14 | 30 | 0 | 0.75 % | 0.05 | 0.05 | Concreto - C-30 - Abatimento 12 cm | 0.1302 | Dimensionado | Forma - Estrutura - Concreto | 2.728 | Dimensionado | Armadura - Aço CA50 - ø 10.0 mm | 7.59574 | Armadura - Aço CA60 - ø 5.0 mm | 3.32622 | Pilar C-30 - Retangular 14x30
P45 | TERREO | retangular | 17 | 30 | 0 | 0.62 % | 0.05 | 0.04 | Concreto - C-30 - Abatimento 12 cm | 0.1581 | Dimensionado | Forma - Estrutura - Concreto | 2.914 | Dimensionado | Armadura - Aço CA50 - ø 10.0 mm | 8.4589 | Armadura - Aço CA60 - ø 5.0 mm | 3.56667 | Pilar C-30 - Retangular 17x30
P46 | TERREO | retangular | 14 | 30 | 0 | Não calculado | Não calculado | Não calculado |  |  | Não dimensionado |  |  |  |  |  |  |  | Pilar C-30 - Retangular 14x30
P47 | TERREO | retangular | 17 | 30 | 0 | 0.62 % | 0.05 | 0.04 | Concreto - C-30 - Abatimento 12 cm | 0.1581 | Dimensionado | Forma - Estrutura - Concreto | 2.914 | Dimensionado | Armadura - Aço CA50 - ø 10.0 mm | 8.4589 | Armadura - Aço CA60 - ø 5.0 mm | 3.56667 | Pilar C-30 - Retangular 17x30
P48 | TERREO | retangular | 14 | 30 | 0 | Não calculado | Não calculado | Não calculado |  |  | Não dimensionado |  |  |  |  |  |  |  | Pilar C-30 - Retangular 14x30
P49 | TERREO | retangular | 14 | 30 | 0 | Não calculado | Não calculado | Não calculado |  |  | Não dimensionado |  |  |  |  |  |  |  | Pilar C-30 - Retangular 14x30
P5 | TERREO | retangular | 14 | 30 | 0 | Não calculado | Não calculado | Não calculado |  |  | Não dimensionado |  |  |  |  |  |  |  | Pilar C-30 - Retangular 14x30
P50 | TERREO | retangular | 14 | 30 | 0 | 0.75 % | 0.04 | 0.04 | Concreto - C-30 - Abatimento 12 cm | 0.1302 | Dimensionado | Forma - Estrutura - Concreto | 2.728 | Dimensionado | Armadura - Aço CA50 - ø 10.0 mm | 7.59574 | Armadura - Aço CA60 - ø 5.0 mm | 3.32622 | Pilar C-30 - Retangular 14x30
P51 | TERREO | retangular | 17 | 30 | 0 | 0.62 % | 0.05 | 0.04 | Concreto - C-30 - Abatimento 12 cm | 0.1581 | Dimensionado | Forma - Estrutura - Concreto | 2.914 | Dimensionado | Armadura - Aço CA50 - ø 10.0 mm | 8.4589 | Armadura - Aço CA60 - ø 5.0 mm | 3.56667 | Pilar C-30 - Retangular 17x30
P52 | TERREO | retangular | 17 | 30 | 0 | 0.62 % | 0.05 | 0.04 | Concreto - C-30 - Abatimento 12 cm | 0.1581 | Dimensionado | Forma - Estrutura - Concreto | 2.914 | Dimensionado | Armadura - Aço CA50 - ø 10.0 mm | 8.4589 | Armadura - Aço CA60 - ø 5.0 mm | 3.56667 | Pilar C-30 - Retangular 17x30
P53 | TERREO | retangular | 14 | 30 | 0 | 0.75 % | 0.02 | 0.02 | Concreto - C-30 - Abatimento 12 cm | 0.1302 | Dimensionado | Forma - Estrutura - Concreto | 2.728 | Dimensionado | Armadura - Aço CA50 - ø 10.0 mm | 7.59574 | Armadura - Aço CA60 - ø 5.0 mm | 3.32622 | Pilar C-30 - Retangular 14x30
P54 | TERREO | retangular | 14 | 30 | 0 | 0.75 % | 0.04 | 0.04 | Concreto - C-30 - Abatimento 12 cm | 0.1302 | Dimensionado | Forma - Estrutura - Concreto | 2.728 | Dimensionado | Armadura - Aço CA50 - ø 10.0 mm | 7.59574 | Armadura - Aço CA60 - ø 5.0 mm | 3.32622 | Pilar C-30 - Retangular 14x30
P55 | TERREO | retangular | 14 | 30 | 0 | 0.75 % | 0.05 | 0.04 | Concreto - C-30 - Abatimento 12 cm | 0.1302 | Dimensionado | Forma - Estrutura - Concreto | 2.728 | Dimensionado | Armadura - Aço CA50 - ø 10.0 mm | 7.59574 | Armadura - Aço CA60 - ø 5.0 mm | 3.32622 | Pilar C-30 - Retangular 14x30
P56 | TERREO | retangular | 17 | 30 | 0 | 0.62 % | 0.05 | 0.04 | Concreto - C-30 - Abatimento 12 cm | 0.1581 | Dimensionado | Forma - Estrutura - Concreto | 2.914 | Dimensionado | Armadura - Aço CA50 - ø 10.0 mm | 8.4589 | Armadura - Aço CA60 - ø 5.0 mm | 3.56667 | Pilar C-30 - Retangular 17x30
P57 | TERREO | retangular | 14 | 30 | 0 | Não calculado | Não calculado | Não calculado |  |  | Não dimensionado |  |  |  |  |  |  |  | Pilar C-30 - Retangular 14x30
P58 | TERREO | retangular | 14 | 30 | 0 | 0.75 % | 0.04 | 0.04 | Concreto - C-30 - Abatimento 12 cm | 0.1302 | Dimensionado | Forma - Estrutura - Concreto | 2.728 | Dimensionado | Armadura - Aço CA50 - ø 10.0 mm | 7.59574 | Armadura - Aço CA60 - ø 5.0 mm | 3.32622 | Pilar C-30 - Retangular 14x30
P59 | TERREO | retangular | 14 | 30 | 0 | Não calculado | Não calculado | Não calculado |  |  | Não dimensionado |  |  |  |  |  |  |  | Pilar C-30 - Retangular 14x30
P6 | TERREO | retangular | 14 | 30 | 0 | Não calculado | Não calculado | Não calculado |  |  | Não dimensionado |  |  |  |  |  |  |  | Pilar C-30 - Retangular 14x30
P60 | TERREO | retangular | 14 | 30 | 0 | 0.75 % | 0.04 | 0.04 | Concreto - C-30 - Abatimento 12 cm | 0.1302 | Dimensionado | Forma - Estrutura - Concreto | 2.728 | Dimensionado | Armadura - Aço CA50 - ø 10.0 mm | 7.59574 | Armadura - Aço CA60 - ø 5.0 mm | 3.32622 | Pilar C-30 - Retangular 14x30
P61 | TERREO | retangular | 14 | 30 | 0 | Não calculado | Não calculado | Não calculado |  |  | Não dimensionado |  |  |  |  |  |  |  | Pilar C-30 - Retangular 14x30
P62 | TERREO | retangular | 14 | 30 | 0 | 0.75 % | 0.05 | 0.04 | Concreto - C-30 - Abatimento 12 cm | 0.1302 | Dimensionado | Forma - Estrutura - Concreto | 2.728 | Dimensionado | Armadura - Aço CA50 - ø 10.0 mm | 7.59574 | Armadura - Aço CA60 - ø 5.0 mm | 3.32622 | Pilar C-30 - Retangular 14x30
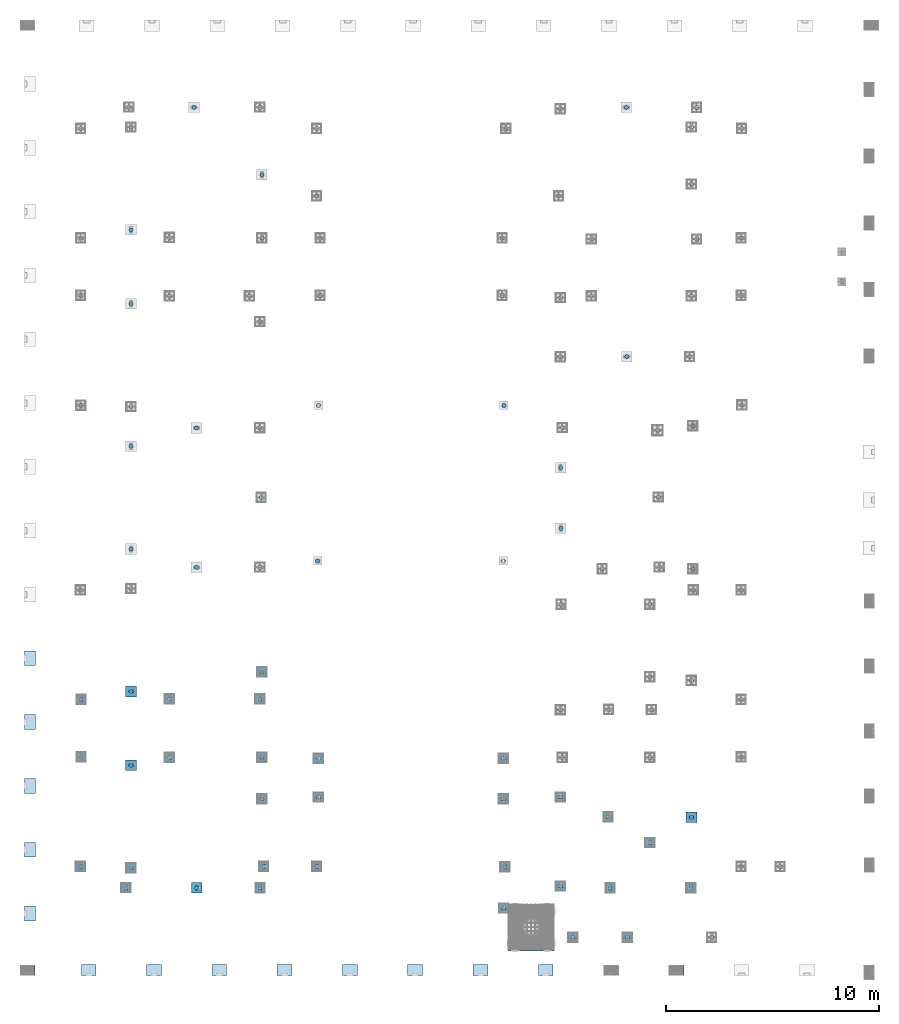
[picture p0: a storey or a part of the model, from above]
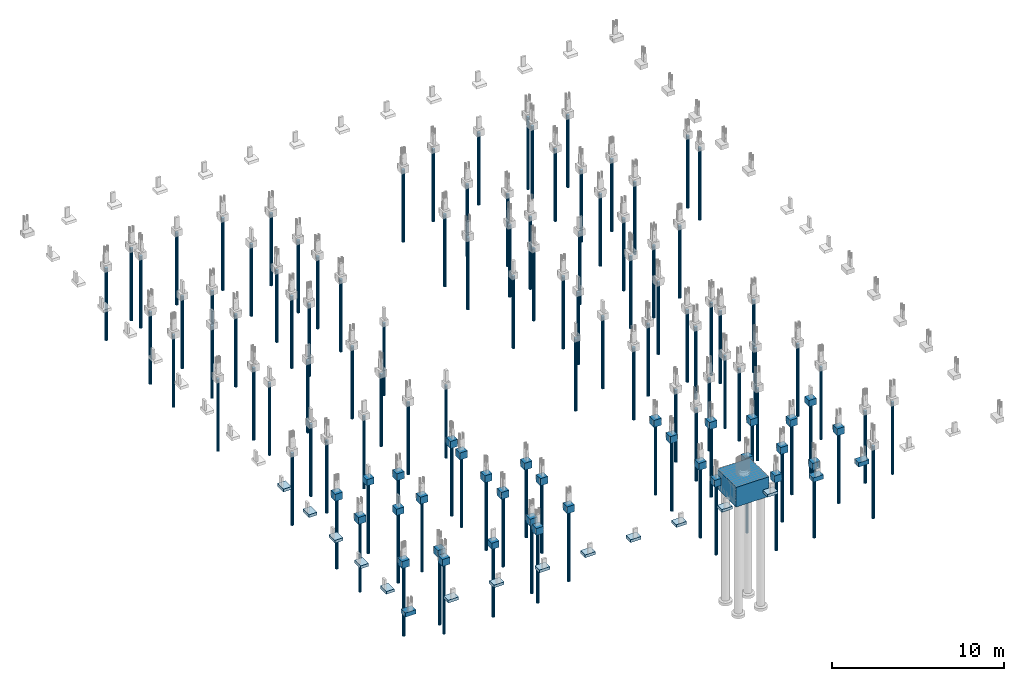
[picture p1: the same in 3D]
Properties of the parts of a building model (IFC4), part 6 of 9

# IfcColumn (561)
Name | In | Tipo | Seção_b (cm) | Seção_h (cm) | Elevação (cm) | Taxa de armadura | Taxa de compressão bruta | Taxa de compressão homogeneizada | Descrição_01 | Quantidade_01 (m3) | Status_01 | Descrição_02 | Quantidade_02 (m2) | Status_02 = Status_03 = Status_04 | Descrição_03 | Quantidade_03 (kg) | Descrição_04 | Quantidade_04 (kg) | Reference
P63 | TERREO | retangular | 14 | 30 | 0 | 1.12 % | 0 | 0 | Concreto - C-30 - Abatimento 12 cm | 0.0189 | Dimensionado | Forma - Estrutura - Concreto | 0.396 | Dimensionado | Armadura - Aço CA50 - ø 10.0 mm | 1.59067 | Armadura - Aço CA60 - ø 5.0 mm | 1.49819 | Pilar C-30 - Retangular 14x30
P64 | TERREO | retangular | 14 | 30 | 0 | Não calculado | Não calculado | Não calculado |  |  | Não dimensionado |  |  |  |  |  |  |  | Pilar C-30 - Retangular 14x30
P65 | TERREO | retangular | 17 | 30 | 0 | 0.62 % | 0.04 | 0.04 | Concreto - C-30 - Abatimento 12 cm | 0.1581 | Dimensionado | Forma - Estrutura - Concreto | 2.914 | Dimensionado | Armadura - Aço CA50 - ø 10.0 mm | 8.4589 | Armadura - Aço CA60 - ø 5.0 mm | 3.56667 | Pilar C-30 - Retangular 17x30
P66 | TERREO | retangular | 14 | 30 | 0 | 0.75 % | 0.06 | 0.05 | Concreto - C-30 - Abatimento 12 cm | 0.1302 | Dimensionado | Forma - Estrutura - Concreto | 2.728 | Dimensionado | Armadura - Aço CA50 - ø 10.0 mm | 8.4589 | Armadura - Aço CA60 - ø 5.0 mm | 3.32622 | Pilar C-30 - Retangular 14x30
P67 | TERREO | retangular | 14 | 20 | 20 | Não calculado | Não calculado | Não calculado |  |  | Não dimensionado |  |  |  |  |  |  |  | Pilar C-30 - Retangular 14x20
P68 | TERREO | retangular | 20 | 20 | 20 | Não calculado | Não calculado | Não calculado |  |  | Não dimensionado |  |  |  |  |  |  |  | Pilar C-30 - Retangular 20x20
P69 | TERREO | retangular | 14 | 30 | 0 | 1.12 % | 0.05 | 0.04 | Concreto - C-30 - Abatimento 12 cm | 0.1302 | Dimensionado | Forma - Estrutura - Concreto | 2.728 | Dimensionado | Armadura - Aço CA50 - ø 10.0 mm | 12.2568 | Armadura - Aço CA60 - ø 5.0 mm | 4.32809 | Pilar C-30 - Retangular 14x30
P7 | TERREO | retangular | 14 | 30 | 0 | Não calculado | Não calculado | Não calculado |  |  | Não dimensionado |  |  |  |  |  |  |  | Pilar C-30 - Retangular 14x30
P70 | TERREO | retangular | 14 | 30 | 0 | Não calculado | Não calculado | Não calculado |  |  | Não dimensionado |  |  |  |  |  |  |  | Pilar C-30 - Retangular 14x30
P71 | TERREO | retangular | 14 | 30 | 0 | 0.75 % | 0.08 | 0.07 | Concreto - C-30 - Abatimento 12 cm | 0.1302 | Dimensionado | Forma - Estrutura - Concreto | 2.728 | Dimensionado | Armadura - Aço CA50 - ø 10.0 mm | 7.59574 | Armadura - Aço CA60 - ø 5.0 mm | 3.32622 | Pilar C-30 - Retangular 14x30
P72 | TERREO | retangular | 14 | 30 | 0 | 0.75 % | 0.04 | 0.04 | Concreto - C-30 - Abatimento 12 cm | 0.1302 | Dimensionado | Forma - Estrutura - Concreto | 2.728 | Dimensionado | Armadura - Aço CA50 - ø 10.0 mm | 7.59574 | Armadura - Aço CA60 - ø 5.0 mm | 3.32622 | Pilar C-30 - Retangular 14x30
P73 | TERREO | retangular | 14 | 35 | 0 | 0.96 % | 0.04 | 0.03 | Concreto - C-30 - Abatimento 12 cm | 0.1519 | Dimensionado | Forma - Estrutura - Concreto | 3.038 | Dimensionado | Armadura - Aço CA50 - ø 10.0 mm | 12.6883 | Armadura - Aço CA60 - ø 5.0 mm | 4.72884 | Pilar C-30 - Retangular 14x35
P74 | TERREO | retangular | 24 | 30 | 0 | 0.44 % | 0.03 | 0.03 | Concreto - C-30 - Abatimento 12 cm | 0.2232 | Dimensionado | Forma - Estrutura - Concreto | 3.348 | Dimensionado | Armadura - Aço CA50 - ø 10.0 mm | 8.85348 | Armadura - Aço CA60 - ø 5.0 mm | 4.12772 | Pilar C-30 - Retangular 24x30
P75 | TERREO | retangular | 14 | 30 | 0 | Não calculado | Não calculado | Não calculado |  |  | Não dimensionado |  |  |  |  |  |  |  | Pilar C-30 - Retangular 14x30
P76 | TERREO | retangular | 14 | 25 | -5 | Não calculado | Não calculado | Não calculado |  |  | Não dimensionado |  |  |  |  |  |  |  | Pilar C-30 - Retangular 14x25
P77 | TERREO | retangular | 14 | 30 | 0 | Não calculado | Não calculado | Não calculado |  |  | Não dimensionado |  |  |  |  |  |  |  | Pilar C-30 - Retangular 14x30
P78 | TERREO | retangular | 14 | 30 | 0 | Não calculado | Não calculado | Não calculado |  |  | Não dimensionado |  |  |  |  |  |  |  | Pilar C-30 - Retangular 14x30
P8 | TERREO | retangular | 14 | 30 | 0 | Não calculado | Não calculado | Não calculado |  |  | Não dimensionado |  |  |  |  |  |  |  | Pilar C-30 - Retangular 14x30
P81 | TERREO | retangular | 14 | 30 | -5 | Não calculado | Não calculado | Não calculado |  |  | Não dimensionado |  |  |  |  |  |  |  | Pilar C-30 - Retangular 14x30
P82 | TERREO | retangular | 14 | 30 | 0 | Não calculado | Não calculado | Não calculado |  |  | Não dimensionado |  |  |  |  |  |  |  | Pilar C-30 - Retangular 14x30
P83 | TERREO | retangular | 14 | 30 | 0 | Não calculado | Não calculado | Não calculado |  |  | Não dimensionado |  |  |  |  |  |  |  | Pilar C-30 - Retangular 14x30
P84 | TERREO | retangular | 14 | 30 | 0 | Não calculado | Não calculado | Não calculado |  |  | Não dimensionado |  |  |  |  |  |  |  | Pilar C-30 - Retangular 14x30
P85 | TERREO | retangular | 14 | 25 | -5 | Não calculado | Não calculado | Não calculado |  |  | Não dimensionado |  |  |  |  |  |  |  | Pilar C-30 - Retangular 14x25
P86 | TERREO | retangular | 14 | 30 | 0 | Não calculado | Não calculado | Não calculado |  |  | Não dimensionado |  |  |  |  |  |  |  | Pilar C-30 - Retangular 14x30
P87 | TERREO | retangular | 14 | 30 | 0 | 0.75 % | 0.07 | 0.06 | Concreto - C-30 - Abatimento 12 cm | 0.1302 | Dimensionado | Forma - Estrutura - Concreto | 2.728 | Dimensionado | Armadura - Aço CA50 - ø 10.0 mm | 7.59574 | Armadura - Aço CA60 - ø 5.0 mm | 3.32622 | Pilar C-30 - Retangular 14x30
P88 | TERREO | retangular | 20 | 20 | 20 | Não calculado | Não calculado | Não calculado |  |  | Não dimensionado |  |  |  |  |  |  |  | Pilar C-30 - Retangular 20x20
P89 | TERREO | retangular | 14 | 20 | 20 | Não calculado | Não calculado | Não calculado |  |  | Não dimensionado |  |  |  |  |  |  |  | Pilar C-30 - Retangular 14x20
P9 | TERREO | retangular | 14 | 30 | 0 | Não calculado | Não calculado | Não calculado |  |  | Não dimensionado |  |  |  |  |  |  |  | Pilar C-30 - Retangular 14x30
P90 | TERREO | retangular | 14 | 30 | 0 | 0.75 % | 0.02 | 0.02 | Concreto - C-30 - Abatimento 12 cm | 0.1302 | Dimensionado | Forma - Estrutura - Concreto | 2.728 | Dimensionado | Armadura - Aço CA50 - ø 10.0 mm | 7.59574 | Armadura - Aço CA60 - ø 5.0 mm | 3.32622 | Pilar C-30 - Retangular 14x30
P91 | TERREO | retangular | 14 | 30 | 0 | Não calculado | Não calculado | Não calculado |  |  | Não dimensionado |  |  |  |  |  |  |  | Pilar C-30 - Retangular 14x30
P92 | TERREO | retangular | 24 | 30 | 0 | 0.44 % | 0.02 | 0.02 | Concreto - C-30 - Abatimento 12 cm | 0.2232 | Dimensionado | Forma - Estrutura - Concreto | 3.348 | Dimensionado | Armadura - Aço CA50 - ø 10.0 mm | 8.85348 | Armadura - Aço CA60 - ø 5.0 mm | 4.12772 | Pilar C-30 - Retangular 24x30
P93 | TERREO | retangular | 14 | 30 | 0 | Não calculado | Não calculado | Não calculado |  |  | Não dimensionado |  |  |  |  |  |  |  | Pilar C-30 - Retangular 14x30
P94 | TERREO | retangular | 17 | 30 | 0 | 0.62 % | 0.04 | 0.04 | Concreto - C-30 - Abatimento 12 cm | 0.1581 | Dimensionado | Forma - Estrutura - Concreto | 2.914 | Dimensionado | Armadura - Aço CA50 - ø 10.0 mm | 8.4589 | Armadura - Aço CA60 - ø 5.0 mm | 3.56667 | Pilar C-30 - Retangular 17x30
P95 | TERREO | retangular | 14 | 30 | 0 | 0.75 % | 0.06 | 0.05 | Concreto - C-30 - Abatimento 12 cm | 0.1302 | Dimensionado | Forma - Estrutura - Concreto | 2.728 | Dimensionado | Armadura - Aço CA50 - ø 10.0 mm | 8.4589 | Armadura - Aço CA60 - ø 5.0 mm | 3.32622 | Pilar C-30 - Retangular 14x30
P96 | TERREO | retangular | 17 | 30 | 0 | 0.62 % | 0.04 | 0.03 | Concreto - C-30 - Abatimento 12 cm | 0.1581 | Dimensionado | Forma - Estrutura - Concreto | 2.914 | Dimensionado | Armadura - Aço CA50 - ø 10.0 mm | 8.4589 | Armadura - Aço CA60 - ø 5.0 mm | 3.56667 | Pilar C-30 - Retangular 17x30
P97 | TERREO | retangular | 17 | 30 | 0 | 0.62 % | 0.04 | 0.04 | Concreto - C-30 - Abatimento 12 cm | 0.1581 | Dimensionado | Forma - Estrutura - Concreto | 2.914 | Dimensionado | Armadura - Aço CA50 - ø 10.0 mm | 8.4589 | Armadura - Aço CA60 - ø 5.0 mm | 3.56667 | Pilar C-30 - Retangular 17x30
P98 | TERREO | retangular | 14 | 30 | 0 | 0.75 % | 0.08 | 0.07 | Concreto - C-30 - Abatimento 12 cm | 0.1302 | Dimensionado | Forma - Estrutura - Concreto | 2.728 | Dimensionado | Armadura - Aço CA50 - ø 10.0 mm | 7.59574 | Armadura - Aço CA60 - ø 5.0 mm | 3.32622 | Pilar C-30 - Retangular 14x30
P99 | TERREO | retangular | 14 | 30 | 0 | 0.75 % | 0.06 | 0.05 | Concreto - C-30 - Abatimento 12 cm | 0.1302 | Dimensionado | Forma - Estrutura - Concreto | 2.728 | Dimensionado | Armadura - Aço CA50 - ø 10.0 mm | 7.59574 | Armadura - Aço CA60 - ø 5.0 mm | 3.32622 | Pilar C-30 - Retangular 14x30
P106 | COBERTURA | retangular | 14 | 30 | 20 | 0.75 % | 0.01 | 0.01 | Concreto - C-30 - Abatimento 12 cm | 0.063 | Dimensionado | Forma - Estrutura - Concreto | 1.32 | Dimensionado | Armadura - Aço CA50 - ø 10.0 mm | 3.6499 | Armadura - Aço CA60 - ø 5.0 mm | 1.66311 | Pilar C-30 - Retangular 14x30
P113 | COBERTURA | retangular | 17 | 30 | 20 | 0.62 % | 0.01 | 0.01 | Concreto - C-30 - Abatimento 12 cm | 0.0765 | Dimensionado | Forma - Estrutura - Concreto | 1.41 | Dimensionado | Armadura - Aço CA50 - ø 10.0 mm | 3.6499 | Armadura - Aço CA60 - ø 5.0 mm | 1.78333 | Pilar C-30 - Retangular 17x30
P116 | COBERTURA | retangular | 17 | 30 | 20 | 0.62 % | 0.01 | 0.01 | Concreto - C-30 - Abatimento 12 cm | 0.0765 | Dimensionado | Forma - Estrutura - Concreto | 1.41 | Dimensionado | Armadura - Aço CA50 - ø 10.0 mm | 3.6499 | Armadura - Aço CA60 - ø 5.0 mm | 1.78333 | Pilar C-30 - Retangular 17x30
P120 | COBERTURA | retangular | 14 | 30 | 0 | 1.91 % | 0.01 | 0.01 | Concreto - C-30 - Abatimento 12 cm | 0.0546 | Dimensionado | Forma - Estrutura - Concreto | 1.144 | Dimensionado | Armadura - Aço CA50 - ø 16.0 mm | 8.08108 | Armadura - Aço CA60 - ø 5.0 mm | 1.27931 | Pilar C-30 - Retangular 14x30
P121 | COBERTURA | retangular | 14 | 30 | 0 | 1.12 % | 0.01 | 0.01 | Concreto - C-30 - Abatimento 12 cm | 0.0546 | Dimensionado | Forma - Estrutura - Concreto | 1.144 | Dimensionado | Armadura - Aço CA50 - ø 10.0 mm | 4.73501 | Armadura - Aço CA60 - ø 5.0 mm | 1.83112 | Pilar C-30 - Retangular 14x30
P124 | COBERTURA | retangular | 17 | 30 | 20 | 0.62 % | 0.01 | 0.01 | Concreto - C-30 - Abatimento 12 cm | 0.0765 | Dimensionado | Forma - Estrutura - Concreto | 1.41 | Dimensionado | Armadura - Aço CA50 - ø 10.0 mm | 3.6499 | Armadura - Aço CA60 - ø 5.0 mm | 1.78333 | Pilar C-30 - Retangular 17x30
P127 | COBERTURA | retangular | 14 | 30 | 0 | Não calculado | Não calculado | Não calculado |  |  | Não dimensionado |  |  |  |  |  |  |  | Pilar C-30 - Retangular 14x30
P128 | COBERTURA | retangular | 14 | 30 | 0 | 0.75 % | 0.01 | 0.01 | Concreto - C-30 - Abatimento 12 cm | 0.0546 | Dimensionado | Forma - Estrutura - Concreto | 1.144 | Dimensionado | Armadura - Aço CA50 - ø 10.0 mm | 3.15667 | Armadura - Aço CA60 - ø 5.0 mm | 1.40725 | Pilar C-30 - Retangular 14x30
P135 | COBERTURA | retangular | 14 | 30 | 0 | 0.75 % | 0.01 | 0.01 | Concreto - C-30 - Abatimento 12 cm | 0.0546 | Dimensionado | Forma - Estrutura - Concreto | 1.144 | Dimensionado | Armadura - Aço CA50 - ø 10.0 mm | 3.15667 | Armadura - Aço CA60 - ø 5.0 mm | 1.40725 | Pilar C-30 - Retangular 14x30
P137 | COBERTURA | retangular | 14 | 30 | 0 | 0.75 % | 0 | 0 | Concreto - C-30 - Abatimento 12 cm | 0.0546 | Dimensionado | Forma - Estrutura - Concreto | 1.144 | Dimensionado | Armadura - Aço CA50 - ø 10.0 mm | 3.15667 | Armadura - Aço CA60 - ø 5.0 mm | 1.40725 | Pilar C-30 - Retangular 14x30
P138 | COBERTURA | retangular | 14 | 30 | 0 | 0.75 % | 0.01 | 0.01 | Concreto - C-30 - Abatimento 12 cm | 0.0546 | Dimensionado | Forma - Estrutura - Concreto | 1.144 | Dimensionado | Armadura - Aço CA50 - ø 10.0 mm | 3.15667 | Armadura - Aço CA60 - ø 5.0 mm | 1.40725 | Pilar C-30 - Retangular 14x30
P139 | COBERTURA | retangular | 14 | 30 | 0 | 0.75 % | 0.01 | 0.01 | Concreto - C-30 - Abatimento 12 cm | 0.0546 | Dimensionado | Forma - Estrutura - Concreto | 1.144 | Dimensionado | Armadura - Aço CA50 - ø 10.0 mm | 3.15667 | Armadura - Aço CA60 - ø 5.0 mm | 1.40725 | Pilar C-30 - Retangular 14x30
P140 | COBERTURA | retangular | 14 | 30 | 0 | 0.75 % | 0.01 | 0.01 | Concreto - C-30 - Abatimento 12 cm | 0.0546 | Dimensionado | Forma - Estrutura - Concreto | 1.144 | Dimensionado | Armadura - Aço CA50 - ø 10.0 mm | 3.15667 | Armadura - Aço CA60 - ø 5.0 mm | 1.40725 | Pilar C-30 - Retangular 14x30
P143 | COBERTURA | retangular | 14 | 30 | 0 | 0.75 % | 0.01 | 0.01 | Concreto - C-30 - Abatimento 12 cm | 0.0546 | Dimensionado | Forma - Estrutura - Concreto | 1.144 | Dimensionado | Armadura - Aço CA50 - ø 10.0 mm | 3.15667 | Armadura - Aço CA60 - ø 5.0 mm | 1.40725 | Pilar C-30 - Retangular 14x30
P145 | COBERTURA | retangular | 14 | 30 | 0 | 0.75 % | 0.01 | 0.01 | Concreto - C-30 - Abatimento 12 cm | 0.0546 | Dimensionado | Forma - Estrutura - Concreto | 1.144 | Dimensionado | Armadura - Aço CA50 - ø 10.0 mm | 3.15667 | Armadura - Aço CA60 - ø 5.0 mm | 1.40725 | Pilar C-30 - Retangular 14x30
P146 | COBERTURA | retangular | 14 | 30 | 0 | 0.75 % | 0.01 | 0.01 | Concreto - C-30 - Abatimento 12 cm | 0.0546 | Dimensionado | Forma - Estrutura - Concreto | 1.144 | Dimensionado | Armadura - Aço CA50 - ø 10.0 mm | 3.15667 | Armadura - Aço CA60 - ø 5.0 mm | 1.40725 | Pilar C-30 - Retangular 14x30
P147 | COBERTURA | retangular | 14 | 30 | 0 | 0.75 % | 0.01 | 0.01 | Concreto - C-30 - Abatimento 12 cm | 0.0546 | Dimensionado | Forma - Estrutura - Concreto | 1.144 | Dimensionado | Armadura - Aço CA50 - ø 10.0 mm | 3.15667 | Armadura - Aço CA60 - ø 5.0 mm | 1.40725 | Pilar C-30 - Retangular 14x30
P148 | COBERTURA | retangular | 14 | 30 | 0 | 0.75 % | 0.01 | 0.01 | Concreto - C-30 - Abatimento 12 cm | 0.0546 | Dimensionado | Forma - Estrutura - Concreto | 1.144 | Dimensionado | Armadura - Aço CA50 - ø 10.0 mm | 3.15667 | Armadura - Aço CA60 - ø 5.0 mm | 1.40725 | Pilar C-30 - Retangular 14x30
P169 | COBERTURA | retangular | 14 | 30 | 0 | 0.75 % | 0 | 0 | Concreto - C-30 - Abatimento 12 cm | 0.0546 | Dimensionado | Forma - Estrutura - Concreto | 1.144 | Dimensionado | Armadura - Aço CA50 - ø 10.0 mm | 3.15667 | Armadura - Aço CA60 - ø 5.0 mm | 1.40725 | Pilar C-30 - Retangular 14x30
P17 | COBERTURA | retangular | 14 | 30 | 0 | 0.75 % | 0.01 | 0.01 | Concreto - C-30 - Abatimento 12 cm | 0.0546 | Dimensionado | Forma - Estrutura - Concreto | 1.144 | Dimensionado | Armadura - Aço CA50 - ø 10.0 mm | 3.15667 | Armadura - Aço CA60 - ø 5.0 mm | 1.40725 | Pilar C-30 - Retangular 14x30
P170 | COBERTURA | retangular | 14 | 25 | 0 | 0.90 % | 0 | 0 | Concreto - C-30 - Abatimento 12 cm | 0.0455 | Dimensionado | Forma - Estrutura - Concreto | 1.014 | Dimensionado | Armadura - Aço CA50 - ø 10.0 mm | 3.15667 | Armadura - Aço CA60 - ø 5.0 mm | 1.2377 | Pilar C-30 - Retangular 14x25
P171 | COBERTURA | retangular | 14 | 30 | 0 | 0.75 % | 0 | 0 | Concreto - C-30 - Abatimento 12 cm | 0.0462 | Dimensionado | Forma - Estrutura - Concreto | 0.968 | Dimensionado | Armadura - Aço CA50 - ø 10.0 mm | 2.66344 | Armadura - Aço CA60 - ø 5.0 mm | 1.27931 | Pilar C-30 - Retangular 14x30
P172 | COBERTURA | retangular | 14 | 30 | 0 | 0.75 % | 0 | 0 | Concreto - C-30 - Abatimento 12 cm | 0.0462 | Dimensionado | Forma - Estrutura - Concreto | 0.968 | Dimensionado | Armadura - Aço CA50 - ø 10.0 mm | 2.66344 | Armadura - Aço CA60 - ø 5.0 mm | 1.27931 | Pilar C-30 - Retangular 14x30
P173 | COBERTURA | retangular | 14 | 30 | 0 | 0.75 % | 0 | 0 | Concreto - C-30 - Abatimento 12 cm | 0.0462 | Dimensionado | Forma - Estrutura - Concreto | 0.968 | Dimensionado | Armadura - Aço CA50 - ø 10.0 mm | 2.66344 | Armadura - Aço CA60 - ø 5.0 mm | 1.27931 | Pilar C-30 - Retangular 14x30
P174 | COBERTURA | retangular | 14 | 30 | 0 | 0.75 % | 0 | 0 | Concreto - C-30 - Abatimento 12 cm | 0.0462 | Dimensionado | Forma - Estrutura - Concreto | 0.968 | Dimensionado | Armadura - Aço CA50 - ø 10.0 mm | 2.66344 | Armadura - Aço CA60 - ø 5.0 mm | 1.27931 | Pilar C-30 - Retangular 14x30
P19 | COBERTURA | retangular | 14 | 30 | 0 | 0.75 % | 0.01 | 0.01 | Concreto - C-30 - Abatimento 12 cm | 0.0546 | Dimensionado | Forma - Estrutura - Concreto | 1.144 | Dimensionado | Armadura - Aço CA50 - ø 10.0 mm | 3.15667 | Armadura - Aço CA60 - ø 5.0 mm | 1.40725 | Pilar C-30 - Retangular 14x30
P20 | COBERTURA | retangular | 14 | 30 | 0 | 1.12 % | 0.01 | 0.01 | Concreto - C-30 - Abatimento 12 cm | 0.0546 | Dimensionado | Forma - Estrutura - Concreto | 1.144 | Dimensionado | Armadura - Aço CA50 - ø 10.0 mm | 4.73501 | Armadura - Aço CA60 - ø 5.0 mm | 1.83112 | Pilar C-30 - Retangular 14x30
P22 | COBERTURA | retangular | 14 | 30 | 0 | 0.75 % | 0.01 | 0.01 | Concreto - C-30 - Abatimento 12 cm | 0.0546 | Dimensionado | Forma - Estrutura - Concreto | 1.144 | Dimensionado | Armadura - Aço CA50 - ø 10.0 mm | 3.15667 | Armadura - Aço CA60 - ø 5.0 mm | 1.40725 | Pilar C-30 - Retangular 14x30
P23 | COBERTURA | retangular | 14 | 30 | 0 | 0.75 % | 0.01 | 0.01 | Concreto - C-30 - Abatimento 12 cm | 0.0546 | Dimensionado | Forma - Estrutura - Concreto | 1.144 | Dimensionado | Armadura - Aço CA50 - ø 10.0 mm | 3.15667 | Armadura - Aço CA60 - ø 5.0 mm | 1.40725 | Pilar C-30 - Retangular 14x30
P25 | COBERTURA | retangular | 14 | 30 | 0 | 0.75 % | 0.01 | 0.01 | Concreto - C-30 - Abatimento 12 cm | 0.0546 | Dimensionado | Forma - Estrutura - Concreto | 1.144 | Dimensionado | Armadura - Aço CA50 - ø 10.0 mm | 3.15667 | Armadura - Aço CA60 - ø 5.0 mm | 1.40725 | Pilar C-30 - Retangular 14x30
P26 | COBERTURA | retangular | 17 | 30 | 0 | 0.62 % | 0.01 | 0.01 | Concreto - C-30 - Abatimento 12 cm | 0.0663 | Dimensionado | Forma - Estrutura - Concreto | 1.222 | Dimensionado | Armadura - Aço CA50 - ø 10.0 mm | 3.15667 | Armadura - Aço CA60 - ø 5.0 mm | 1.50898 | Pilar C-30 - Retangular 17x30
P28 | COBERTURA | retangular | 14 | 30 | 0 | 0.75 % | 0.01 | 0.01 | Concreto - C-30 - Abatimento 12 cm | 0.0546 | Dimensionado | Forma - Estrutura - Concreto | 1.144 | Dimensionado | Armadura - Aço CA50 - ø 10.0 mm | 3.15667 | Armadura - Aço CA60 - ø 5.0 mm | 1.40725 | Pilar C-30 - Retangular 14x30
P33 | COBERTURA | retangular | 14 | 14 | 0 | 1.60 % | 0.01 | 0.01 | Concreto - C-30 - Abatimento 12 cm | 0.02548 | Dimensionado | Forma - Estrutura - Concreto | 0.728 | Dimensionado | Armadura - Aço CA50 - ø 10.0 mm | 3.15667 | Armadura - Aço CA60 - ø 5.0 mm | 0.864694 | Pilar C-30 - Retangular 14x14
P36 | COBERTURA | retangular | 17 | 30 | 20 | 0.62 % | 0.01 | 0.01 | Concreto - C-30 - Abatimento 12 cm | 0.0765 | Dimensionado | Forma - Estrutura - Concreto | 1.41 | Dimensionado | Armadura - Aço CA50 - ø 10.0 mm | 3.6499 | Armadura - Aço CA60 - ø 5.0 mm | 1.78333 | Pilar C-30 - Retangular 17x30
P41 | COBERTURA | retangular | 17 | 30 | 20 | 0.62 % | 0.01 | 0.01 | Concreto - C-30 - Abatimento 12 cm | 0.0765 | Dimensionado | Forma - Estrutura - Concreto | 1.41 | Dimensionado | Armadura - Aço CA50 - ø 10.0 mm | 3.6499 | Armadura - Aço CA60 - ø 5.0 mm | 1.78333 | Pilar C-30 - Retangular 17x30
P42 | COBERTURA | retangular | 17 | 30 | 20 | 0.62 % | 0.01 | 0.01 | Concreto - C-30 - Abatimento 12 cm | 0.0765 | Dimensionado | Forma - Estrutura - Concreto | 1.41 | Dimensionado | Armadura - Aço CA50 - ø 10.0 mm | 3.6499 | Armadura - Aço CA60 - ø 5.0 mm | 1.78333 | Pilar C-30 - Retangular 17x30
P45 | COBERTURA | retangular | 17 | 30 | 20 | 0.62 % | 0.01 | 0.01 | Concreto - C-30 - Abatimento 12 cm | 0.0765 | Dimensionado | Forma - Estrutura - Concreto | 1.41 | Dimensionado | Armadura - Aço CA50 - ø 10.0 mm | 3.6499 | Armadura - Aço CA60 - ø 5.0 mm | 1.78333 | Pilar C-30 - Retangular 17x30
P47 | COBERTURA | retangular | 17 | 30 | 20 | 0.62 % | 0.01 | 0.01 | Concreto - C-30 - Abatimento 12 cm | 0.0765 | Dimensionado | Forma - Estrutura - Concreto | 1.41 | Dimensionado | Armadura - Aço CA50 - ø 10.0 mm | 3.6499 | Armadura - Aço CA60 - ø 5.0 mm | 1.78333 | Pilar C-30 - Retangular 17x30
P51 | COBERTURA | retangular | 17 | 30 | 20 | 0.62 % | 0.01 | 0.01 | Concreto - C-30 - Abatimento 12 cm | 0.0765 | Dimensionado | Forma - Estrutura - Concreto | 1.41 | Dimensionado | Armadura - Aço CA50 - ø 10.0 mm | 3.6499 | Armadura - Aço CA60 - ø 5.0 mm | 1.78333 | Pilar C-30 - Retangular 17x30
P52 | COBERTURA | retangular | 17 | 30 | 20 | 0.62 % | 0.01 | 0.01 | Concreto - C-30 - Abatimento 12 cm | 0.0765 | Dimensionado | Forma - Estrutura - Concreto | 1.41 | Dimensionado | Armadura - Aço CA50 - ø 10.0 mm | 3.6499 | Armadura - Aço CA60 - ø 5.0 mm | 1.78333 | Pilar C-30 - Retangular 17x30
P56 | COBERTURA | retangular | 17 | 30 | 20 | 0.62 % | 0.01 | 0.01 | Concreto - C-30 - Abatimento 12 cm | 0.0765 | Dimensionado | Forma - Estrutura - Concreto | 1.41 | Dimensionado | Armadura - Aço CA50 - ø 10.0 mm | 3.6499 | Armadura - Aço CA60 - ø 5.0 mm | 1.78333 | Pilar C-30 - Retangular 17x30
P65 | COBERTURA | retangular | 17 | 30 | 55 | 0.62 % | 0.01 | 0.01 | Concreto - C-30 - Abatimento 12 cm | 0.09435 | Dimensionado | Forma - Estrutura - Concreto | 1.739 | Dimensionado | Armadura - Aço CA50 - ø 10.0 mm | 4.51305 | Armadura - Aço CA60 - ø 5.0 mm | 2.19487 | Pilar C-30 - Retangular 17x30
P66 | COBERTURA | retangular | 14 | 30 | 55 | 0.75 % | 0.01 | 0 | Concreto - C-30 - Abatimento 12 cm | 0.0777 | Dimensionado | Forma - Estrutura - Concreto | 1.628 | Dimensionado | Armadura - Aço CA50 - ø 10.0 mm | 4.51305 | Armadura - Aço CA60 - ø 5.0 mm | 2.04691 | Pilar C-30 - Retangular 14x30
P67 | COBERTURA | retangular | 14 | 20 | 0 | Não calculado | Não calculado | Não calculado |  |  | Não dimensionado |  |  |  |  |  |  |  | Pilar C-30 - Retangular 14x20
P68 | COBERTURA | retangular | 14 | 20 | 0 | Não calculado | Não calculado | Não calculado |  |  | Não dimensionado |  |  |  |  |  |  |  | Pilar C-30 - Retangular 14x20
P69 | COBERTURA | retangular | 14 | 30 | 55 | 0.75 % | 0.01 | 0.01 | Concreto - C-30 - Abatimento 12 cm | 0.0777 | Dimensionado | Forma - Estrutura - Concreto | 1.628 | Dimensionado | Armadura - Aço CA50 - ø 10.0 mm | 4.51305 | Armadura - Aço CA60 - ø 5.0 mm | 2.04691 | Pilar C-30 - Retangular 14x30
P73 | COBERTURA | retangular | 14 | 15 | 55 | Não calculado | Não calculado | Não calculado |  |  | Não dimensionado |  |  |  |  |  |  |  | Pilar C-30 - Retangular 14x15
P74 | COBERTURA | retangular | 14 | 30 | 55 | 0.75 % | 0.02 | 0.01 | Concreto - C-30 - Abatimento 12 cm | 0.0777 | Dimensionado | Forma - Estrutura - Concreto | 1.628 | Dimensionado | Armadura - Aço CA50 - ø 10.0 mm | 4.51305 | Armadura - Aço CA60 - ø 5.0 mm | 2.04691 | Pilar C-30 - Retangular 14x30
P75 | COBERTURA | retangular | 14 | 30 | 55 | Não calculado | Não calculado | Não calculado |  |  | Não dimensionado |  |  |  |  |  |  |  | Pilar C-30 - Retangular 14x30
P84 | COBERTURA | retangular | 14 | 30 | 55 | Não calculado | Não calculado | Não calculado |  |  | Não dimensionado |  |  |  |  |  |  |  | Pilar C-30 - Retangular 14x30
P88 | COBERTURA | retangular | 14 | 20 | 0 | Não calculado | Não calculado | Não calculado |  |  | Não dimensionado |  |  |  |  |  |  |  | Pilar C-30 - Retangular 14x20
P89 | COBERTURA | retangular | 14 | 20 | 0 | Não calculado | Não calculado | Não calculado |  |  | Não dimensionado |  |  |  |  |  |  |  | Pilar C-30 - Retangular 14x20
P91 | COBERTURA | retangular | 14 | 30 | 55 | Não calculado | Não calculado | Não calculado |  |  | Não dimensionado |  |  |  |  |  |  |  | Pilar C-30 - Retangular 14x30
P92 | COBERTURA | retangular | 14 | 30 | 55 | 0.75 % | 0.02 | 0.01 | Concreto - C-30 - Abatimento 12 cm | 0.0777 | Dimensionado | Forma - Estrutura - Concreto | 1.628 | Dimensionado | Armadura - Aço CA50 - ø 10.0 mm | 4.51305 | Armadura - Aço CA60 - ø 5.0 mm | 2.04691 | Pilar C-30 - Retangular 14x30
P94 | COBERTURA | retangular | 17 | 30 | 55 | 0.62 % | 0.01 | 0.01 | Concreto - C-30 - Abatimento 12 cm | 0.09435 | Dimensionado | Forma - Estrutura - Concreto | 1.739 | Dimensionado | Armadura - Aço CA50 - ø 10.0 mm | 4.51305 | Armadura - Aço CA60 - ø 5.0 mm | 2.19487 | Pilar C-30 - Retangular 17x30
P95 | COBERTURA | retangular | 14 | 30 | 55 | 0.75 % | 0.01 | 0 | Concreto - C-30 - Abatimento 12 cm | 0.0777 | Dimensionado | Forma - Estrutura - Concreto | 1.628 | Dimensionado | Armadura - Aço CA50 - ø 10.0 mm | 4.51305 | Armadura - Aço CA60 - ø 5.0 mm | 2.04691 | Pilar C-30 - Retangular 14x30
P96 | COBERTURA | retangular | 17 | 30 | 55 | 0.62 % | 0 | 0 | Concreto - C-30 - Abatimento 12 cm | 0.09435 | Dimensionado | Forma - Estrutura - Concreto | 1.739 | Dimensionado | Armadura - Aço CA50 - ø 10.0 mm | 4.51305 | Armadura - Aço CA60 - ø 5.0 mm | 2.19487 | Pilar C-30 - Retangular 17x30
P97 | COBERTURA | retangular | 17 | 30 | 55 | 0.62 % | 0.01 | 0.01 | Concreto - C-30 - Abatimento 12 cm | 0.09435 | Dimensionado | Forma - Estrutura - Concreto | 1.739 | Dimensionado | Armadura - Aço CA50 - ø 10.0 mm | 4.51305 | Armadura - Aço CA60 - ø 5.0 mm | 2.19487 | Pilar C-30 - Retangular 17x30

# IfcFooting (170)
In: FUNDAÇÃO
Material: Concreto
Pset_ConcreteElementGeneral - ConstructionMethod: InSitu; ExposureClass: 1; StrengthClass: C-25
AltoQi_Eberick_Padrão - Classe de concreto: C-25
Name | ConcreteCover (cm) | Elemento | Elevação (cm) | Cobrimento (cm) | Descrição_01 | Quantidade_01 (m3) | Status_01 | Descrição_02 | Quantidade_02 (m2) | Status_02 = Status_03 | Descrição_03 | Quantidade_03 (kg) | Pset_FootingCommon, Reference | Tipo | Seção_LB (cm) = Seção_LH (cm) | Descrição_04 | Quantidade_04 (kg) | Status_04 | Pset_PileCommon, Reference
P1 | 5 | Sapata | 0 | 5 | Concreto - C-25 - Abatimento 12 cm | 0.105 | Dimensionado | Forma - Estrutura - Concreto | 0.72 | Dimensionado | Armadura - Aço CA50 - ø 8.0 mm | 4.07211 | Sapata C-25 | PredefinedType: PAD_FOOTING; AltoQi_Eberick_Elemento - Seção_B: 50 cm; Seção_H: 70 cm
P10 | 5 | Sapata | 0 | 5 |  |  | Não dimensionado |  |  |  |  |  | Sapata C-25 | PredefinedType: PAD_FOOTING; AltoQi_Eberick_Elemento - Seção_B: 50 cm; Seção_H: 70 cm
P100 | 5 | Sapata | 0 | 5 | Concreto - C-25 - Abatimento 12 cm | 0.105 | Dimensionado | Forma - Estrutura - Concreto | 0.72 | Dimensionado | Armadura - Aço CA50 - ø 8.0 mm | 4.07211 | Sapata C-25 | PredefinedType: PAD_FOOTING; AltoQi_Eberick_Elemento - Seção_B: 50 cm; Seção_H: 70 cm
P101 | 5 | Sapata | 0 | 5 |  |  | Não dimensionado |  |  |  |  |  | Sapata C-25 | PredefinedType: PAD_FOOTING; AltoQi_Eberick_Elemento - Seção_B: 50 cm; Seção_H: 70 cm
P102 | 3 | Bloco | 0 | 3 | Concreto - C-25 - Abatimento 12 cm | 0.120288 | Dimensionado | Forma - Estrutura - Concreto | 1 | Dimensionado | Armadura - Aço CA50 - ø 6.3 mm | 2.30022 | Bloco C-25 | 1 | 50 | Armadura - Aço CA60 - ø 5.0 mm | 0.471651 | Dimensionado | Estaca circular R20 - Concreto C-25
P103 | 5 | Sapata | 0 | 5 | Concreto - C-25 - Abatimento 12 cm | 0.105 | Dimensionado | Forma - Estrutura - Concreto | 0.72 | Dimensionado | Armadura - Aço CA50 - ø 8.0 mm | 4.07211 | Sapata C-25 | PredefinedType: PAD_FOOTING; AltoQi_Eberick_Elemento - Seção_B: 50 cm; Seção_H: 70 cm
P104 | 3 | Bloco | 0 | 3 | Concreto - C-25 - Abatimento 12 cm | 0.120288 | Dimensionado | Forma - Estrutura - Concreto | 1 | Dimensionado | Armadura - Aço CA50 - ø 6.3 mm | 2.30022 | Bloco C-25 | 1 | 50 | Armadura - Aço CA60 - ø 5.0 mm | 0.471651 | Dimensionado | Estaca circular R20 - Concreto C-25
P105 | 3 | Bloco | 0 | 3 | Concreto - C-25 - Abatimento 12 cm | 0.120288 | Dimensionado | Forma - Estrutura - Concreto | 1 | Dimensionado | Armadura - Aço CA50 - ø 6.3 mm | 2.30022 | Bloco C-25 | 1 | 50 | Armadura - Aço CA60 - ø 5.0 mm | 0.471651 | Dimensionado | Estaca circular R20 - Concreto C-25
P106 | 3 | Bloco | 0 | 3 | Concreto - C-25 - Abatimento 12 cm | 0.120288 | Dimensionado | Forma - Estrutura - Concreto | 1 | Dimensionado | Armadura - Aço CA50 - ø 6.3 mm | 2.30022 | Bloco C-25 | 1 | 50 | Armadura - Aço CA60 - ø 5.0 mm | 0.471651 | Dimensionado | Estaca circular R20 - Concreto C-25
P107 | 3 | Bloco | 0 | 3 |  |  | Não dimensionado |  |  |  |  |  | Bloco C-25 | 1 | 50 |  |  |  | Estaca circular R20 - Concreto C-25
P108 | 3 | Bloco | 0 | 3 | Concreto - C-25 - Abatimento 12 cm | 0.120288 | Dimensionado | Forma - Estrutura - Concreto | 1 | Dimensionado | Armadura - Aço CA50 - ø 6.3 mm | 2.30022 | Bloco C-25 | 1 | 50 | Armadura - Aço CA60 - ø 5.0 mm | 0.471651 | Dimensionado | Estaca circular R20 - Concreto C-25
P109 | 3 | Bloco | 0 | 3 | Concreto - C-25 - Abatimento 12 cm | 0.120288 | Dimensionado | Forma - Estrutura - Concreto | 1 | Dimensionado | Armadura - Aço CA50 - ø 6.3 mm | 2.30022 | Bloco C-25 | 1 | 50 | Armadura - Aço CA60 - ø 5.0 mm | 0.471651 | Dimensionado | Estaca circular R20 - Concreto C-25
P11 | 5 | Sapata | 0 | 5 |  |  | Não dimensionado |  |  |  |  |  | Sapata C-25 | PredefinedType: PAD_FOOTING; AltoQi_Eberick_Elemento - Seção_B: 50 cm; Seção_H: 70 cm
P110 | 3 | Bloco | 0 | 3 | Concreto - C-25 - Abatimento 12 cm | 0.120288 | Dimensionado | Forma - Estrutura - Concreto | 1 | Dimensionado | Armadura - Aço CA50 - ø 6.3 mm | 2.30022 | Bloco C-25 | 1 | 50 | Armadura - Aço CA60 - ø 5.0 mm | 0.471651 | Dimensionado | Estaca circular R20 - Concreto C-25
P111 | 3 | Bloco | 0 | 3 | Concreto - C-25 - Abatimento 12 cm | 0.120288 | Dimensionado | Forma - Estrutura - Concreto | 1 | Dimensionado | Armadura - Aço CA50 - ø 6.3 mm | 2.30022 | Bloco C-25 | 1 | 50 | Armadura - Aço CA60 - ø 5.0 mm | 0.471651 | Dimensionado | Estaca circular R20 - Concreto C-25
P112 | 3 | Bloco | 0 | 3 | Concreto - C-25 - Abatimento 12 cm | 0.120288 | Dimensionado | Forma - Estrutura - Concreto | 1 | Dimensionado | Armadura - Aço CA50 - ø 6.3 mm | 2.30022 | Bloco C-25 | 1 | 50 | Armadura - Aço CA60 - ø 5.0 mm | 0.471651 | Dimensionado | Estaca circular R20 - Concreto C-25
P113 | 3 | Bloco | 0 | 3 | Concreto - C-25 - Abatimento 12 cm | 0.120288 | Dimensionado | Forma - Estrutura - Concreto | 1 | Dimensionado | Armadura - Aço CA50 - ø 6.3 mm | 2.30022 | Bloco C-25 | 1 | 50 | Armadura - Aço CA60 - ø 5.0 mm | 0.471651 | Dimensionado | Estaca circular R20 - Concreto C-25
P114 | 5 | Sapata | 0 | 5 |  |  | Não dimensionado |  |  |  |  |  | Sapata C-25 | PredefinedType: PAD_FOOTING; AltoQi_Eberick_Elemento - Seção_B: 50 cm; Seção_H: 70 cm
P115 | 5 | Sapata | 0 | 5 | Concreto - C-25 - Abatimento 12 cm | 0.105 | Dimensionado | Forma - Estrutura - Concreto | 0.72 | Dimensionado | Armadura - Aço CA50 - ø 8.0 mm | 4.07211 | Sapata C-25 | PredefinedType: PAD_FOOTING; AltoQi_Eberick_Elemento - Seção_B: 50 cm; Seção_H: 70 cm
P116 | 3 | Bloco | 0 | 3 | Concreto - C-25 - Abatimento 12 cm | 0.120288 | Dimensionado | Forma - Estrutura - Concreto | 1 | Dimensionado | Armadura - Aço CA50 - ø 6.3 mm | 2.30022 | Bloco C-25 | 1 | 50 | Armadura - Aço CA60 - ø 5.0 mm | 0.471651 | Dimensionado | Estaca circular R20 - Concreto C-25
P117 | 3 | Bloco | 0 | 3 |  |  | Não dimensionado |  |  |  |  |  | Bloco C-25 | 1 | 50 |  |  |  | Estaca circular R20 - Concreto C-25
P118 | 3 | Bloco | 0 | 3 | Concreto - C-25 - Abatimento 12 cm | 0.120288 | Dimensionado | Forma - Estrutura - Concreto | 1 | Dimensionado | Armadura - Aço CA50 - ø 6.3 mm | 2.30022 | Bloco C-25 | 1 | 50 | Armadura - Aço CA60 - ø 5.0 mm | 0.471651 | Dimensionado | Estaca circular R20 - Concreto C-25
P119 | 3 | Bloco | 0 | 3 | Concreto - C-25 - Abatimento 12 cm | 0.120288 | Dimensionado | Forma - Estrutura - Concreto | 1 | Dimensionado | Armadura - Aço CA50 - ø 6.3 mm | 2.30022 | Bloco C-25 | 1 | 50 | Armadura - Aço CA60 - ø 5.0 mm | 0.471651 | Dimensionado | Estaca circular R20 - Concreto C-25
P12 | 5 | Sapata | 0 | 5 |  |  | Não dimensionado |  |  |  |  |  | Sapata C-25 | PredefinedType: PAD_FOOTING; AltoQi_Eberick_Elemento - Seção_B: 50 cm; Seção_H: 70 cm
P120 | 3 | Bloco | 0 | 3 | Concreto - C-25 - Abatimento 12 cm | 0.120288 | Dimensionado | Forma - Estrutura - Concreto | 1 | Dimensionado | Armadura - Aço CA50 - ø 6.3 mm | 2.30022 | Bloco C-25 | 1 | 50 | Armadura - Aço CA60 - ø 5.0 mm | 0.471651 | Dimensionado | Estaca circular R20 - Concreto C-25
P121 | 3 | Bloco | 0 | 3 | Concreto - C-25 - Abatimento 12 cm | 0.120288 | Dimensionado | Forma - Estrutura - Concreto | 1 | Dimensionado | Armadura - Aço CA50 - ø 6.3 mm | 2.30022 | Bloco C-25 | 1 | 50 | Armadura - Aço CA60 - ø 5.0 mm | 0.471651 | Dimensionado | Estaca circular R20 - Concreto C-25
P122 | 3 | Bloco | 0 | 3 | Concreto - C-25 - Abatimento 12 cm | 0.120288 | Dimensionado | Forma - Estrutura - Concreto | 1 | Dimensionado | Armadura - Aço CA50 - ø 6.3 mm | 2.30022 | Bloco C-25 | 1 | 50 | Armadura - Aço CA60 - ø 5.0 mm | 0.471651 | Dimensionado | Estaca circular R20 - Concreto C-25
P123 | 3 | Bloco | 0 | 3 | Concreto - C-25 - Abatimento 12 cm | 0.120288 | Dimensionado | Forma - Estrutura - Concreto | 1 | Dimensionado | Armadura - Aço CA50 - ø 6.3 mm | 2.30022 | Bloco C-25 | 1 | 50 | Armadura - Aço CA60 - ø 5.0 mm | 0.471651 | Dimensionado | Estaca circular R20 - Concreto C-25
P124 | 3 | Bloco | 0 | 3 | Concreto - C-25 - Abatimento 12 cm | 0.120288 | Dimensionado | Forma - Estrutura - Concreto | 1 | Dimensionado | Armadura - Aço CA50 - ø 6.3 mm | 2.30022 | Bloco C-25 | 1 | 50 | Armadura - Aço CA60 - ø 5.0 mm | 0.471651 | Dimensionado | Estaca circular R20 - Concreto C-25
P125 | 5 | Sapata | 0 | 5 |  |  | Não dimensionado |  |  |  |  |  | Sapata C-25 | PredefinedType: PAD_FOOTING; AltoQi_Eberick_Elemento - Seção_B: 50 cm; Seção_H: 70 cm
P126 | 3 | Bloco | 0 | 3 | Concreto - C-25 - Abatimento 12 cm | 0.120288 | Dimensionado | Forma - Estrutura - Concreto | 1 | Dimensionado | Armadura - Aço CA50 - ø 6.3 mm | 2.30022 | Bloco C-25 | 1 | 50 | Armadura - Aço CA60 - ø 5.0 mm | 0.471651 | Dimensionado | Estaca circular R20 - Concreto C-25
P127 | 3 | Bloco | 0 | 3 | Concreto - C-25 - Abatimento 12 cm | 0.120288 | Dimensionado | Forma - Estrutura - Concreto | 1 | Dimensionado | Armadura - Aço CA50 - ø 6.3 mm | 2.30022 | Bloco C-25 | 1 | 50 | Armadura - Aço CA60 - ø 5.0 mm | 0.471651 | Dimensionado | Estaca circular R20 - Concreto C-25
P128 | 3 | Bloco | 0 | 3 | Concreto - C-25 - Abatimento 12 cm | 0.120288 | Dimensionado | Forma - Estrutura - Concreto | 1 | Dimensionado | Armadura - Aço CA50 - ø 6.3 mm | 2.30022 | Bloco C-25 | 1 | 50 | Armadura - Aço CA60 - ø 5.0 mm | 0.471651 | Dimensionado | Estaca circular R20 - Concreto C-25
P129 | 3 | Bloco | 0 | 3 | Concreto - C-25 - Abatimento 12 cm | 0.120288 | Dimensionado | Forma - Estrutura - Concreto | 1 | Dimensionado | Armadura - Aço CA50 - ø 6.3 mm | 2.30022 | Bloco C-25 | 1 | 50 | Armadura - Aço CA60 - ø 5.0 mm | 0.471651 | Dimensionado | Estaca circular R20 - Concreto C-25
P13 | 5 | Sapata | 0 | 5 |  |  | Não dimensionado |  |  |  |  |  | Sapata C-25 | PredefinedType: PAD_FOOTING; AltoQi_Eberick_Elemento - Seção_B: 50 cm; Seção_H: 70 cm
P130 | 5 | Sapata | 0 | 5 | Concreto - C-25 - Abatimento 12 cm | 0.105 | Dimensionado | Forma - Estrutura - Concreto | 0.72 | Dimensionado | Armadura - Aço CA50 - ø 8.0 mm | 4.07211 | Sapata C-25 | PredefinedType: PAD_FOOTING; AltoQi_Eberick_Elemento - Seção_B: 50 cm; Seção_H: 70 cm
P131 | 3 | Bloco | 0 | 3 | Concreto - C-25 - Abatimento 12 cm | 0.120288 | Dimensionado | Forma - Estrutura - Concreto | 1 | Dimensionado | Armadura - Aço CA50 - ø 6.3 mm | 2.30022 | Bloco C-25 | 1 | 50 | Armadura - Aço CA60 - ø 5.0 mm | 0.471651 | Dimensionado | Estaca circular R20 - Concreto C-25
P132 | 3 | Bloco | 0 | 3 |  |  | Não dimensionado |  |  |  |  |  | Bloco C-25 | 1 | 50 |  |  |  | Estaca circular R20 - Concreto C-25
P133 | 5 | Sapata | 0 | 5 |  |  | Não dimensionado |  |  |  |  |  | Sapata C-25 | PredefinedType: PAD_FOOTING; AltoQi_Eberick_Elemento - Seção_B: 50 cm; Seção_H: 70 cm
P134 | 3 | Bloco | 0 | 3 | Concreto - C-25 - Abatimento 12 cm | 0.120288 | Dimensionado | Forma - Estrutura - Concreto | 1 | Dimensionado | Armadura - Aço CA50 - ø 6.3 mm | 2.30022 | Bloco C-25 | 1 | 50 | Armadura - Aço CA60 - ø 5.0 mm | 0.471651 | Dimensionado | Estaca circular R20 - Concreto C-25
P135 | 3 | Bloco | 0 | 3 | Concreto - C-25 - Abatimento 12 cm | 0.120288 | Dimensionado | Forma - Estrutura - Concreto | 1 | Dimensionado | Armadura - Aço CA50 - ø 6.3 mm | 2.30022 | Bloco C-25 | 1 | 50 | Armadura - Aço CA60 - ø 5.0 mm | 0.471651 | Dimensionado | Estaca circular R20 - Concreto C-25
P136 | 3 | Bloco | 0 | 3 | Concreto - C-25 - Abatimento 12 cm | 0.120288 | Dimensionado | Forma - Estrutura - Concreto | 1 | Dimensionado | Armadura - Aço CA50 - ø 6.3 mm | 2.30022 | Bloco C-25 | 1 | 50 | Armadura - Aço CA60 - ø 5.0 mm | 0.471651 | Dimensionado | Estaca circular R20 - Concreto C-25
P137 | 3 | Bloco | 0 | 3 | Concreto - C-25 - Abatimento 12 cm | 0.120288 | Dimensionado | Forma - Estrutura - Concreto | 1 | Dimensionado | Armadura - Aço CA50 - ø 6.3 mm | 2.30022 | Bloco C-25 | 1 | 50 | Armadura - Aço CA60 - ø 5.0 mm | 0.471651 | Dimensionado | Estaca circular R20 - Concreto C-25
P138 | 3 | Bloco | 0 | 3 | Concreto - C-25 - Abatimento 12 cm | 0.120288 | Dimensionado | Forma - Estrutura - Concreto | 1 | Dimensionado | Armadura - Aço CA50 - ø 6.3 mm | 2.30022 | Bloco C-25 | 1 | 50 | Armadura - Aço CA60 - ø 5.0 mm | 0.471651 | Dimensionado | Estaca circular R20 - Concreto C-25
P139 | 3 | Bloco | 0 | 3 | Concreto - C-25 - Abatimento 12 cm | 0.120288 | Dimensionado | Forma - Estrutura - Concreto | 1 | Dimensionado | Armadura - Aço CA50 - ø 6.3 mm | 2.30022 | Bloco C-25 | 1 | 50 | Armadura - Aço CA60 - ø 5.0 mm | 0.471651 | Dimensionado | Estaca circular R20 - Concreto C-25
P14 | 5 | Sapata | 0 | 5 | Concreto - C-25 - Abatimento 12 cm | 0.105 | Dimensionado | Forma - Estrutura - Concreto | 0.72 | Dimensionado | Armadura - Aço CA50 - ø 8.0 mm | 4.07211 | Sapata C-25 | PredefinedType: PAD_FOOTING; AltoQi_Eberick_Elemento - Seção_B: 50 cm; Seção_H: 70 cm
P140 | 3 | Bloco | 0 | 3 | Concreto - C-25 - Abatimento 12 cm | 0.120288 | Dimensionado | Forma - Estrutura - Concreto | 1 | Dimensionado | Armadura - Aço CA50 - ø 6.3 mm | 2.30022 | Bloco C-25 | 1 | 50 | Armadura - Aço CA60 - ø 5.0 mm | 0.471651 | Dimensionado | Estaca circular R20 - Concreto C-25
P141 | 3 | Bloco | 0 | 3 | Concreto - C-25 - Abatimento 12 cm | 0.120288 | Dimensionado | Forma - Estrutura - Concreto | 1 | Dimensionado | Armadura - Aço CA50 - ø 6.3 mm | 2.30022 | Bloco C-25 | 1 | 50 | Armadura - Aço CA60 - ø 5.0 mm | 0.471651 | Dimensionado | Estaca circular R20 - Concreto C-25
P142 | 5 | Sapata | 0 | 5 | Concreto - C-25 - Abatimento 12 cm | 0.105 | Dimensionado | Forma - Estrutura - Concreto | 0.72 | Dimensionado | Armadura - Aço CA50 - ø 8.0 mm | 4.07211 | Sapata C-25 | PredefinedType: PAD_FOOTING; AltoQi_Eberick_Elemento - Seção_B: 50 cm; Seção_H: 70 cm
P143 | 3 | Bloco | 0 | 3 | Concreto - C-25 - Abatimento 12 cm | 0.120288 | Dimensionado | Forma - Estrutura - Concreto | 1 | Dimensionado | Armadura - Aço CA50 - ø 6.3 mm | 2.30022 | Bloco C-25 | 1 | 50 | Armadura - Aço CA60 - ø 5.0 mm | 0.471651 | Dimensionado | Estaca circular R20 - Concreto C-25
P144 | 3 | Bloco | 0 | 3 |  |  | Não dimensionado |  |  |  |  |  | Bloco C-25 | 1 | 50 |  |  |  | Estaca circular R20 - Concreto C-25
P145 | 3 | Bloco | 0 | 3 | Concreto - C-25 - Abatimento 12 cm | 0.120288 | Dimensionado | Forma - Estrutura - Concreto | 1 | Dimensionado | Armadura - Aço CA50 - ø 6.3 mm | 2.30022 | Bloco C-25 | 1 | 50 | Armadura - Aço CA60 - ø 5.0 mm | 0.471651 | Dimensionado | Estaca circular R20 - Concreto C-25
P146 | 3 | Bloco | 0 | 3 | Concreto - C-25 - Abatimento 12 cm | 0.120288 | Dimensionado | Forma - Estrutura - Concreto | 1 | Dimensionado | Armadura - Aço CA50 - ø 6.3 mm | 2.30022 | Bloco C-25 | 1 | 50 | Armadura - Aço CA60 - ø 5.0 mm | 0.471651 | Dimensionado | Estaca circular R20 - Concreto C-25
P147 | 3 | Bloco | 0 | 3 | Concreto - C-25 - Abatimento 12 cm | 0.120288 | Dimensionado | Forma - Estrutura - Concreto | 1 | Dimensionado | Armadura - Aço CA50 - ø 6.3 mm | 2.30022 | Bloco C-25 | 1 | 50 | Armadura - Aço CA60 - ø 5.0 mm | 0.471651 | Dimensionado | Estaca circular R20 - Concreto C-25
P148 | 3 | Bloco | 0 | 3 | Concreto - C-25 - Abatimento 12 cm | 0.120288 | Dimensionado | Forma - Estrutura - Concreto | 1 | Dimensionado | Armadura - Aço CA50 - ø 6.3 mm | 2.30022 | Bloco C-25 | 1 | 50 | Armadura - Aço CA60 - ø 5.0 mm | 0.471651 | Dimensionado | Estaca circular R20 - Concreto C-25
P149 | 5 | Sapata | 0 | 5 |  |  | Não dimensionado |  |  |  |  |  | Sapata C-25 | PredefinedType: PAD_FOOTING; AltoQi_Eberick_Elemento - Seção_B: 50 cm; Seção_H: 70 cm
P15 | 5 | Sapata | 0 | 5 |  |  | Não dimensionado |  |  |  |  |  | Sapata C-25 | PredefinedType: PAD_FOOTING; AltoQi_Eberick_Elemento - Seção_B: 50 cm; Seção_H: 70 cm
P150 | 3 | Bloco | 0 | 3 | Concreto - C-25 - Abatimento 12 cm | 0.120288 | Dimensionado | Forma - Estrutura - Concreto | 1 | Dimensionado | Armadura - Aço CA50 - ø 6.3 mm | 2.30022 | Bloco C-25 | 1 | 50 | Armadura - Aço CA60 - ø 5.0 mm | 0.471651 | Dimensionado | Estaca circular R20 - Concreto C-25
P151 | 5 | Bloco | 0 | 3 | Concreto - C-25 - Abatimento 12 cm | 6.65819 | Dimensionado | Forma - Estrutura - Concreto | 12.32 | Dimensionado | Armadura - Aço CA50 - ø 6.3 mm | 25.733 | Bloco C-25 | 4 RET | 220 | Armadura - Aço CA50 - ø 12.5 mm | 50.6331 | Dimensionado | Tubulão T50 C-25 - 800cm | AltoQi_Eberick-Item_05 - Descrição_05: Armadura - Aço CA50 - ø 16.0 mm; Quantidade_05: 111.62 kg; Status_05: Dimensionado
P152 | 3 | Bloco | 0 | 3 | Concreto - C-25 - Abatimento 12 cm | 0.120288 | Dimensionado | Forma - Estrutura - Concreto | 1 | Dimensionado | Armadura - Aço CA50 - ø 6.3 mm | 2.30022 | Bloco C-25 | 1 | 50 | Armadura - Aço CA60 - ø 5.0 mm | 0.471651 | Dimensionado | Estaca circular R20 - Concreto C-25
P153 | 3 | Bloco | 0 | 3 | Concreto - C-25 - Abatimento 12 cm | 0.120288 | Dimensionado | Forma - Estrutura - Concreto | 1 | Dimensionado | Armadura - Aço CA50 - ø 6.3 mm | 2.30022 | Bloco C-25 | 1 | 50 | Armadura - Aço CA60 - ø 5.0 mm | 0.471651 | Dimensionado | Estaca circular R20 - Concreto C-25
P154 | 3 | Bloco | 0 | 3 | Concreto - C-25 - Abatimento 12 cm | 0.120288 | Dimensionado | Forma - Estrutura - Concreto | 1 | Dimensionado | Armadura - Aço CA50 - ø 6.3 mm | 2.30022 | Bloco C-25 | 1 | 50 | Armadura - Aço CA60 - ø 5.0 mm | 0.471651 | Dimensionado | Estaca circular R20 - Concreto C-25
P155 | 5 | Sapata | 0 | 5 | Concreto - C-25 - Abatimento 12 cm | 0.105 | Dimensionado | Forma - Estrutura - Concreto | 0.72 | Dimensionado | Armadura - Aço CA50 - ø 8.0 mm | 4.07211 | Sapata C-25 | PredefinedType: PAD_FOOTING; AltoQi_Eberick_Elemento - Seção_B: 50 cm; Seção_H: 70 cm
P156 | 5 | Sapata | 0 | 5 |  |  | Não dimensionado |  |  |  |  |  | Sapata C-25 | PredefinedType: PAD_FOOTING; AltoQi_Eberick_Elemento - Seção_B: 50 cm; Seção_H: 70 cm
P157 | 5 | Sapata | 0 | 5 |  |  | Não dimensionado |  |  |  |  |  | Sapata C-25 | PredefinedType: PAD_FOOTING; AltoQi_Eberick_Elemento - Seção_B: 50 cm; Seção_H: 70 cm
P158 | 5 | Sapata | 0 | 5 |  |  | Não dimensionado |  |  |  |  |  | Sapata C-25 | PredefinedType: PAD_FOOTING; AltoQi_Eberick_Elemento - Seção_B: 50 cm; Seção_H: 70 cm
P159 | 5 | Sapata | 0 | 5 |  |  | Não dimensionado |  |  |  |  |  | Sapata C-25 | PredefinedType: PAD_FOOTING; AltoQi_Eberick_Elemento - Seção_B: 50 cm; Seção_H: 70 cm
P16 | 5 | Sapata | 0 | 5 | Concreto - C-25 - Abatimento 12 cm | 0.105 | Dimensionado | Forma - Estrutura - Concreto | 0.72 | Dimensionado | Armadura - Aço CA50 - ø 8.0 mm | 4.07211 | Sapata C-25 | PredefinedType: PAD_FOOTING; AltoQi_Eberick_Elemento - Seção_B: 50 cm; Seção_H: 70 cm
P160 | 5 | Sapata | 0 | 5 |  |  | Não dimensionado |  |  |  |  |  | Sapata C-25 | PredefinedType: PAD_FOOTING; AltoQi_Eberick_Elemento - Seção_B: 50 cm; Seção_H: 70 cm
P161 | 5 | Sapata | 0 | 5 |  |  | Não dimensionado |  |  |  |  |  | Sapata C-25 | PredefinedType: PAD_FOOTING; AltoQi_Eberick_Elemento - Seção_B: 50 cm; Seção_H: 70 cm
P162 | 5 | Sapata | 0 | 5 |  |  | Não dimensionado |  |  |  |  |  | Sapata C-25 | PredefinedType: PAD_FOOTING; AltoQi_Eberick_Elemento - Seção_B: 50 cm; Seção_H: 70 cm
P163 | 5 | Sapata | 0 | 5 |  |  | Não dimensionado |  |  |  |  |  | Sapata C-25 | PredefinedType: PAD_FOOTING; AltoQi_Eberick_Elemento - Seção_B: 50 cm; Seção_H: 70 cm
P164 | 5 | Sapata | 0 | 5 | Concreto - C-25 - Abatimento 12 cm | 0.105 | Dimensionado | Forma - Estrutura - Concreto | 0.72 | Dimensionado | Armadura - Aço CA50 - ø 8.0 mm | 4.07211 | Sapata C-25 | PredefinedType: PAD_FOOTING; AltoQi_Eberick_Elemento - Seção_B: 50 cm; Seção_H: 70 cm
P165 | 5 | Sapata | 0 | 5 | Concreto - C-25 - Abatimento 12 cm | 0.105 | Dimensionado | Forma - Estrutura - Concreto | 0.72 | Dimensionado | Armadura - Aço CA50 - ø 8.0 mm | 4.07211 | Sapata C-25 | PredefinedType: PAD_FOOTING; AltoQi_Eberick_Elemento - Seção_B: 50 cm; Seção_H: 70 cm
P166 | 5 | Sapata | 0 | 5 |  |  | Não dimensionado |  |  |  |  |  | Sapata C-25 | PredefinedType: PAD_FOOTING; AltoQi_Eberick_Elemento - Seção_B: 50 cm; Seção_H: 70 cm
P167 | 5 | Sapata | 0 | 5 |  |  | Não dimensionado |  |  |  |  |  | Sapata C-25 | PredefinedType: PAD_FOOTING; AltoQi_Eberick_Elemento - Seção_B: 50 cm; Seção_H: 70 cm
P168 | 5 | Sapata | 0 | 5 | Concreto - C-25 - Abatimento 12 cm | 0.105 | Dimensionado | Forma - Estrutura - Concreto | 0.72 | Dimensionado | Armadura - Aço CA50 - ø 8.0 mm | 4.07211 | Sapata C-25 | PredefinedType: PAD_FOOTING; AltoQi_Eberick_Elemento - Seção_B: 50 cm; Seção_H: 70 cm
P17 | 3 | Bloco | 0 | 3 | Concreto - C-25 - Abatimento 12 cm | 0.120288 | Dimensionado | Forma - Estrutura - Concreto | 1 | Dimensionado | Armadura - Aço CA50 - ø 6.3 mm | 2.30022 | Bloco C-25 | 1 | 50 | Armadura - Aço CA60 - ø 5.0 mm | 0.471651 | Dimensionado | Estaca circular R20 - Concreto C-25
P18 | 3 | Bloco | 0 | 3 |  |  | Não dimensionado |  |  |  |  |  | Bloco C-25 | 1 | 50 |  |  |  | Estaca circular R20 - Concreto C-25
P19 | 3 | Bloco | 0 | 3 | Concreto - C-25 - Abatimento 12 cm | 0.120288 | Dimensionado | Forma - Estrutura - Concreto | 1 | Dimensionado | Armadura - Aço CA50 - ø 6.3 mm | 2.30022 | Bloco C-25 | 1 | 50 | Armadura - Aço CA60 - ø 5.0 mm | 0.471651 | Dimensionado | Estaca circular R20 - Concreto C-25
P2 | 5 | Sapata | 0 | 5 |  |  | Não dimensionado |  |  |  |  |  | Sapata C-25 | PredefinedType: PAD_FOOTING; AltoQi_Eberick_Elemento - Seção_B: 50 cm; Seção_H: 70 cm
P20 | 3 | Bloco | 0 | 3 | Concreto - C-25 - Abatimento 12 cm | 0.120288 | Dimensionado | Forma - Estrutura - Concreto | 1 | Dimensionado | Armadura - Aço CA50 - ø 6.3 mm | 2.30022 | Bloco C-25 | 1 | 50 | Armadura - Aço CA60 - ø 5.0 mm | 0.471651 | Dimensionado | Estaca circular R20 - Concreto C-25
P21 | 3 | Bloco | 0 | 3 |  |  | Não dimensionado |  |  |  |  |  | Bloco C-25 | 1 | 50 |  |  |  | Estaca circular R20 - Concreto C-25
P22 | 3 | Bloco | 0 | 3 | Concreto - C-25 - Abatimento 12 cm | 0.120288 | Dimensionado | Forma - Estrutura - Concreto | 1 | Dimensionado | Armadura - Aço CA50 - ø 6.3 mm | 2.30022 | Bloco C-25 | 1 | 50 | Armadura - Aço CA60 - ø 5.0 mm | 0.471651 | Dimensionado | Estaca circular R20 - Concreto C-25
P23 | 3 | Bloco | 0 | 3 | Concreto - C-25 - Abatimento 12 cm | 0.120288 | Dimensionado | Forma - Estrutura - Concreto | 1 | Dimensionado | Armadura - Aço CA50 - ø 6.3 mm | 2.30022 | Bloco C-25 | 1 | 50 | Armadura - Aço CA60 - ø 5.0 mm | 0.471651 | Dimensionado | Estaca circular R20 - Concreto C-25
P24 | 3 | Bloco | 0 | 3 | Concreto - C-25 - Abatimento 12 cm | 0.120288 | Dimensionado | Forma - Estrutura - Concreto | 1 | Dimensionado | Armadura - Aço CA50 - ø 6.3 mm | 2.30022 | Bloco C-25 | 1 | 50 | Armadura - Aço CA60 - ø 5.0 mm | 0.471651 | Dimensionado | Estaca circular R20 - Concreto C-25
P25 | 3 | Bloco | 0 | 3 | Concreto - C-25 - Abatimento 12 cm | 0.120288 | Dimensionado | Forma - Estrutura - Concreto | 1 | Dimensionado | Armadura - Aço CA50 - ø 6.3 mm | 2.30022 | Bloco C-25 | 1 | 50 | Armadura - Aço CA60 - ø 5.0 mm | 0.471651 | Dimensionado | Estaca circular R20 - Concreto C-25
P26 | 3 | Bloco | 0 | 3 | Concreto - C-25 - Abatimento 12 cm | 0.120288 | Dimensionado | Forma - Estrutura - Concreto | 1 | Dimensionado | Armadura - Aço CA50 - ø 6.3 mm | 2.30022 | Bloco C-25 | 1 | 50 | Armadura - Aço CA60 - ø 5.0 mm | 0.471651 | Dimensionado | Estaca circular R20 - Concreto C-25
P27 | 3 | Bloco | 0 | 3 | Concreto - C-25 - Abatimento 12 cm | 0.120288 | Dimensionado | Forma - Estrutura - Concreto | 1 | Dimensionado | Armadura - Aço CA50 - ø 6.3 mm | 2.30022 | Bloco C-25 | 1 | 50 | Armadura - Aço CA60 - ø 5.0 mm | 0.471651 | Dimensionado | Estaca circular R20 - Concreto C-25
P28 | 3 | Bloco | 0 | 3 | Concreto - C-25 - Abatimento 12 cm | 0.120288 | Dimensionado | Forma - Estrutura - Concreto | 1 | Dimensionado | Armadura - Aço CA50 - ø 6.3 mm | 2.30022 | Bloco C-25 | 1 | 50 | Armadura - Aço CA60 - ø 5.0 mm | 0.471651 | Dimensionado | Estaca circular R20 - Concreto C-25
P29 | 5 | Sapata | 0 | 5 |  |  | Não dimensionado |  |  |  |  |  | Sapata C-25 | PredefinedType: PAD_FOOTING; AltoQi_Eberick_Elemento - Seção_B: 50 cm; Seção_H: 70 cm
P3 | 5 | Sapata | 0 | 5 |  |  | Não dimensionado |  |  |  |  |  | Sapata C-25 | PredefinedType: PAD_FOOTING; AltoQi_Eberick_Elemento - Seção_B: 50 cm; Seção_H: 70 cm
P30 | 5 | Sapata | 0 | 5 | Concreto - C-25 - Abatimento 12 cm | 0.105 | Dimensionado | Forma - Estrutura - Concreto | 0.72 | Dimensionado | Armadura - Aço CA50 - ø 8.0 mm | 4.07211 | Sapata C-25 | PredefinedType: PAD_FOOTING; AltoQi_Eberick_Elemento - Seção_B: 50 cm; Seção_H: 70 cm
P31 | 3 | Bloco | 0 | 3 |  |  | Não dimensionado |  |  |  |  |  | Bloco C-25 | 1 | 50 |  |  |  | Estaca circular R20 - Concreto C-25
P32 | 3 | Bloco | 0 | 3 | Concreto - C-25 - Abatimento 12 cm | 0.120288 | Dimensionado | Forma - Estrutura - Concreto | 1 | Dimensionado | Armadura - Aço CA50 - ø 6.3 mm | 2.30022 | Bloco C-25 | 1 | 50 | Armadura - Aço CA60 - ø 5.0 mm | 0.471651 | Dimensionado | Estaca circular R20 - Concreto C-25
P33 | 3 | Bloco | 0 | 3 | Concreto - C-25 - Abatimento 12 cm | 0.120288 | Dimensionado | Forma - Estrutura - Concreto | 1 | Dimensionado | Armadura - Aço CA50 - ø 6.3 mm | 2.30022 | Bloco C-25 | 1 | 50 | Armadura - Aço CA60 - ø 5.0 mm | 0.471651 | Dimensionado | Estaca circular R20 - Concreto C-25
P34 | 3 | Bloco | 0 | 3 | Concreto - C-25 - Abatimento 12 cm | 0.120288 | Dimensionado | Forma - Estrutura - Concreto | 1 | Dimensionado | Armadura - Aço CA50 - ø 6.3 mm | 2.30022 | Bloco C-25 | 1 | 50 | Armadura - Aço CA60 - ø 5.0 mm | 0.471651 | Dimensionado | Estaca circular R20 - Concreto C-25
P35 | 5 | Sapata | 0 | 5 |  |  | Não dimensionado |  |  |  |  |  | Sapata C-25 | PredefinedType: PAD_FOOTING; AltoQi_Eberick_Elemento - Seção_B: 50 cm; Seção_H: 70 cm
P36 | 3 | Bloco | 0 | 3 | Concreto - C-25 - Abatimento 12 cm | 0.120288 | Dimensionado | Forma - Estrutura - Concreto | 1 | Dimensionado | Armadura - Aço CA50 - ø 6.3 mm | 2.30022 | Bloco C-25 | 1 | 50 | Armadura - Aço CA60 - ø 5.0 mm | 0.471651 | Dimensionado | Estaca circular R20 - Concreto C-25
P37 | 3 | Bloco | 0 | 3 |  |  | Não dimensionado |  |  |  |  |  | Bloco C-25 | 1 | 50 |  |  |  | Estaca circular R20 - Concreto C-25
P38 | 5 | Sapata | 0 | 5 | Concreto - C-25 - Abatimento 12 cm | 0.105 | Dimensionado | Forma - Estrutura - Concreto | 0.72 | Dimensionado | Armadura - Aço CA50 - ø 8.0 mm | 4.07211 | Sapata C-25 | PredefinedType: PAD_FOOTING; AltoQi_Eberick_Elemento - Seção_B: 50 cm; Seção_H: 70 cm
P39 | 3 | Bloco | 0 | 3 | Concreto - C-25 - Abatimento 12 cm | 0.120288 | Dimensionado | Forma - Estrutura - Concreto | 1 | Dimensionado | Armadura - Aço CA50 - ø 6.3 mm | 2.30022 | Bloco C-25 | 1 | 50 | Armadura - Aço CA60 - ø 5.0 mm | 0.471651 | Dimensionado | Estaca circular R20 - Concreto C-25
P4 | 5 | Sapata | 0 | 5 |  |  | Não dimensionado |  |  |  |  |  | Sapata C-25 | PredefinedType: PAD_FOOTING; AltoQi_Eberick_Elemento - Seção_B: 50 cm; Seção_H: 70 cm
P40 | 3 | Bloco | 0 | 3 | Concreto - C-25 - Abatimento 12 cm | 0.120288 | Dimensionado | Forma - Estrutura - Concreto | 1 | Dimensionado | Armadura - Aço CA50 - ø 6.3 mm | 3.0539 | Bloco C-25 | 1 | 50 |  |  |  | Estaca circular R20 - Concreto C-25
P41 | 3 | Bloco | 0 | 3 | Concreto - C-25 - Abatimento 12 cm | 0.120288 | Dimensionado | Forma - Estrutura - Concreto | 1 | Dimensionado | Armadura - Aço CA50 - ø 6.3 mm | 2.30022 | Bloco C-25 | 1 | 50 | Armadura - Aço CA60 - ø 5.0 mm | 0.471651 | Dimensionado | Estaca circular R20 - Concreto C-25
P42 | 3 | Bloco | 0 | 3 | Concreto - C-25 - Abatimento 12 cm | 0.120288 | Dimensionado | Forma - Estrutura - Concreto | 1 | Dimensionado | Armadura - Aço CA50 - ø 6.3 mm | 3.0539 | Bloco C-25 | 1 | 50 |  |  |  | Estaca circular R20 - Concreto C-25
P43 | 3 | Bloco | 0 | 3 | Concreto - C-25 - Abatimento 12 cm | 0.120288 | Dimensionado | Forma - Estrutura - Concreto | 1 | Dimensionado | Armadura - Aço CA50 - ø 6.3 mm | 2.30022 | Bloco C-25 | 1 | 50 | Armadura - Aço CA60 - ø 5.0 mm | 0.471651 | Dimensionado | Estaca circular R20 - Concreto C-25
P44 | 3 | Bloco | 0 | 3 | Concreto - C-25 - Abatimento 12 cm | 0.120288 | Dimensionado | Forma - Estrutura - Concreto | 1 | Dimensionado | Armadura - Aço CA50 - ø 6.3 mm | 3.0539 | Bloco C-25 | 1 | 50 |  |  |  | Estaca circular R20 - Concreto C-25
P45 | 3 | Bloco | 0 | 3 | Concreto - C-25 - Abatimento 12 cm | 0.120288 | Dimensionado | Forma - Estrutura - Concreto | 1 | Dimensionado | Armadura - Aço CA50 - ø 6.3 mm | 2.30022 | Bloco C-25 | 1 | 50 | Armadura - Aço CA60 - ø 5.0 mm | 0.471651 | Dimensionado | Estaca circular R20 - Concreto C-25
P46 | 5 | Sapata | 0 | 5 |  |  | Não dimensionado |  |  |  |  |  | Sapata C-25 | PredefinedType: PAD_FOOTING; AltoQi_Eberick_Elemento - Seção_B: 50 cm; Seção_H: 70 cm
P47 | 3 | Bloco | 0 | 3 | Concreto - C-25 - Abatimento 12 cm | 0.120288 | Dimensionado | Forma - Estrutura - Concreto | 1 | Dimensionado | Armadura - Aço CA50 - ø 6.3 mm | 2.30022 | Bloco C-25 | 1 | 50 | Armadura - Aço CA60 - ø 5.0 mm | 0.471651 | Dimensionado | Estaca circular R20 - Concreto C-25
P48 | 3 | Bloco | 0 | 3 |  |  | Não dimensionado |  |  |  |  |  | Bloco C-25 | 1 | 50 |  |  |  | Estaca circular R20 - Concreto C-25
P49 | 3 | Bloco | 0 | 3 | Concreto - C-25 - Abatimento 12 cm | 0.120288 | Dimensionado | Forma - Estrutura - Concreto | 1 | Dimensionado | Armadura - Aço CA50 - ø 6.3 mm | 2.30022 | Bloco C-25 | 1 | 50 | Armadura - Aço CA60 - ø 5.0 mm | 0.471651 | Dimensionado | Estaca circular R20 - Concreto C-25
P5 | 5 | Sapata | 0 | 5 |  |  | Não dimensionado |  |  |  |  |  | Sapata C-25 | PredefinedType: PAD_FOOTING; AltoQi_Eberick_Elemento - Seção_B: 50 cm; Seção_H: 70 cm
P50 | 3 | Bloco | 0 | 3 | Concreto - C-25 - Abatimento 12 cm | 0.120288 | Dimensionado | Forma - Estrutura - Concreto | 1 | Dimensionado | Armadura - Aço CA50 - ø 6.3 mm | 2.30022 | Bloco C-25 | 1 | 50 | Armadura - Aço CA60 - ø 5.0 mm | 0.471651 | Dimensionado | Estaca circular R20 - Concreto C-25
P51 | 3 | Bloco | 0 | 3 | Concreto - C-25 - Abatimento 12 cm | 0.120288 | Dimensionado | Forma - Estrutura - Concreto | 1 | Dimensionado | Armadura - Aço CA50 - ø 6.3 mm | 2.30022 | Bloco C-25 | 1 | 50 | Armadura - Aço CA60 - ø 5.0 mm | 0.471651 | Dimensionado | Estaca circular R20 - Concreto C-25
P52 | 3 | Bloco | 0 | 3 | Concreto - C-25 - Abatimento 12 cm | 0.120288 | Dimensionado | Forma - Estrutura - Concreto | 1 | Dimensionado | Armadura - Aço CA50 - ø 6.3 mm | 2.30022 | Bloco C-25 | 1 | 50 | Armadura - Aço CA60 - ø 5.0 mm | 0.471651 | Dimensionado | Estaca circular R20 - Concreto C-25
P53 | 3 | Bloco | 0 | 3 | Concreto - C-25 - Abatimento 12 cm | 0.120288 | Dimensionado | Forma - Estrutura - Concreto | 1 | Dimensionado | Armadura - Aço CA50 - ø 6.3 mm | 2.30022 | Bloco C-25 | 1 | 50 | Armadura - Aço CA60 - ø 5.0 mm | 0.471651 | Dimensionado | Estaca circular R20 - Concreto C-25
P54 | 3 | Bloco | 0 | 3 | Concreto - C-25 - Abatimento 12 cm | 0.120288 | Dimensionado | Forma - Estrutura - Concreto | 1 | Dimensionado | Armadura - Aço CA50 - ø 6.3 mm | 2.30022 | Bloco C-25 | 1 | 50 | Armadura - Aço CA60 - ø 5.0 mm | 0.471651 | Dimensionado | Estaca circular R20 - Concreto C-25
P55 | 3 | Bloco | 0 | 3 | Concreto - C-25 - Abatimento 12 cm | 0.120288 | Dimensionado | Forma - Estrutura - Concreto | 1 | Dimensionado | Armadura - Aço CA50 - ø 6.3 mm | 2.30022 | Bloco C-25 | 1 | 50 | Armadura - Aço CA60 - ø 5.0 mm | 0.471651 | Dimensionado | Estaca circular R20 - Concreto C-25
P56 | 3 | Bloco | 0 | 3 | Concreto - C-25 - Abatimento 12 cm | 0.120288 | Dimensionado | Forma - Estrutura - Concreto | 1 | Dimensionado | Armadura - Aço CA50 - ø 6.3 mm | 2.30022 | Bloco C-25 | 1 | 50 | Armadura - Aço CA60 - ø 5.0 mm | 0.471651 | Dimensionado | Estaca circular R20 - Concreto C-25
P57 | 5 | Sapata | 0 | 5 | Concreto - C-25 - Abatimento 12 cm | 0.105 | Dimensionado | Forma - Estrutura - Concreto | 0.72 | Dimensionado | Armadura - Aço CA50 - ø 8.0 mm | 4.07211 | Sapata C-25 | PredefinedType: PAD_FOOTING; AltoQi_Eberick_Elemento - Seção_B: 50 cm; Seção_H: 70 cm
P58 | 3 | Bloco | 0 | 3 | Concreto - C-25 - Abatimento 12 cm | 0.120288 | Dimensionado | Forma - Estrutura - Concreto | 1 | Dimensionado | Armadura - Aço CA50 - ø 6.3 mm | 2.30022 | Bloco C-25 | 1 | 50 | Armadura - Aço CA60 - ø 5.0 mm | 0.471651 | Dimensionado | Estaca circular R20 - Concreto C-25
P59 | 5 | Sapata | 0 | 5 |  |  | Não dimensionado |  |  |  |  |  | Sapata C-25 | PredefinedType: PAD_FOOTING; AltoQi_Eberick_Elemento - Seção_B: 50 cm; Seção_H: 70 cm
P6 | 5 | Sapata | 0 | 5 |  |  | Não dimensionado |  |  |  |  |  | Sapata C-25 | PredefinedType: PAD_FOOTING; AltoQi_Eberick_Elemento - Seção_B: 50 cm; Seção_H: 70 cm
P60 | 3 | Bloco | 0 | 3 | Concreto - C-25 - Abatimento 12 cm | 0.120288 | Dimensionado | Forma - Estrutura - Concreto | 1 | Dimensionado | Armadura - Aço CA50 - ø 6.3 mm | 2.30022 | Bloco C-25 | 1 | 50 | Armadura - Aço CA60 - ø 5.0 mm | 0.471651 | Dimensionado | Estaca circular R20 - Concreto C-25
P61 | 3 | Bloco | 0 | 3 |  |  | Não dimensionado |  |  |  |  |  | Bloco C-25 | 1 | 50 |  |  |  | Estaca circular R20 - Concreto C-25
P62 | 3 | Bloco | 0 | 3 | Concreto - C-25 - Abatimento 12 cm | 0.120288 | Dimensionado | Forma - Estrutura - Concreto | 1 | Dimensionado | Armadura - Aço CA50 - ø 6.3 mm | 2.30022 | Bloco C-25 | 1 | 50 | Armadura - Aço CA60 - ø 5.0 mm | 0.471651 | Dimensionado | Estaca circular R20 - Concreto C-25
P63 | 5 | Sapata | 0 | 5 | Concreto - C-25 - Abatimento 12 cm | 0.105 | Dimensionado | Forma - Estrutura - Concreto | 0.72 | Dimensionado | Armadura - Aço CA50 - ø 8.0 mm | 4.07211 | Sapata C-25 | PredefinedType: PAD_FOOTING; AltoQi_Eberick_Elemento - Seção_B: 50 cm; Seção_H: 70 cm
P64 | 5 | Sapata | 0 | 5 |  |  | Não dimensionado |  |  |  |  |  | Sapata C-25 | PredefinedType: PAD_FOOTING; AltoQi_Eberick_Elemento - Seção_B: 50 cm; Seção_H: 70 cm
P65 | 3 | Bloco | 0 | 3 | Concreto - C-25 - Abatimento 12 cm | 0.120288 | Dimensionado | Forma - Estrutura - Concreto | 1 | Dimensionado | Armadura - Aço CA50 - ø 6.3 mm | 2.30022 | Bloco C-25 | 1 | 50 | Armadura - Aço CA60 - ø 5.0 mm | 0.471651 | Dimensionado | Estaca circular R20 - Concreto C-25
P66 | 3 | Bloco | 0 | 3 | Concreto - C-25 - Abatimento 12 cm | 0.120288 | Dimensionado | Forma - Estrutura - Concreto | 1 | Dimensionado | Armadura - Aço CA50 - ø 6.3 mm | 2.30022 | Bloco C-25 | 1 | 50 | Armadura - Aço CA60 - ø 5.0 mm | 0.471651 | Dimensionado | Estaca circular R20 - Concreto C-25
P67 | 3 | Bloco | 0 | 3 |  |  | Não dimensionado |  |  |  |  |  | Bloco C-25 | 1 | 40 |  |  |  | Estaca circular R20 - Concreto C-25
P68 | 3 | Bloco | 30 | 3 |  |  | Não dimensionado |  |  |  |  |  | Bloco C-25 | 1 | 40 |  |  |  | Estaca circular R20 - Concreto C-25
P69 | 3 | Bloco | 0 | 3 | Concreto - C-25 - Abatimento 12 cm | 0.120288 | Dimensionado | Forma - Estrutura - Concreto | 1 | Dimensionado | Armadura - Aço CA50 - ø 6.3 mm | 2.30022 | Bloco C-25 | 1 | 50 | Armadura - Aço CA60 - ø 5.0 mm | 0.471651 | Dimensionado | Estaca circular R20 - Concreto C-25
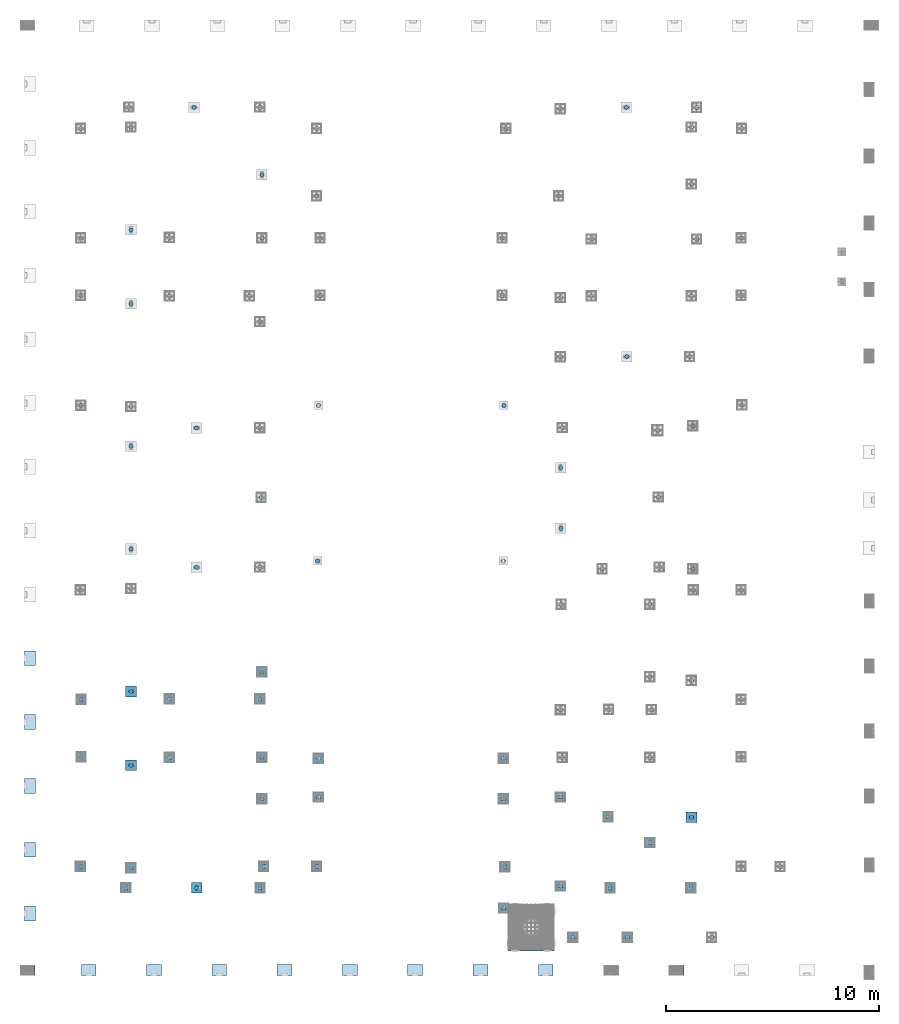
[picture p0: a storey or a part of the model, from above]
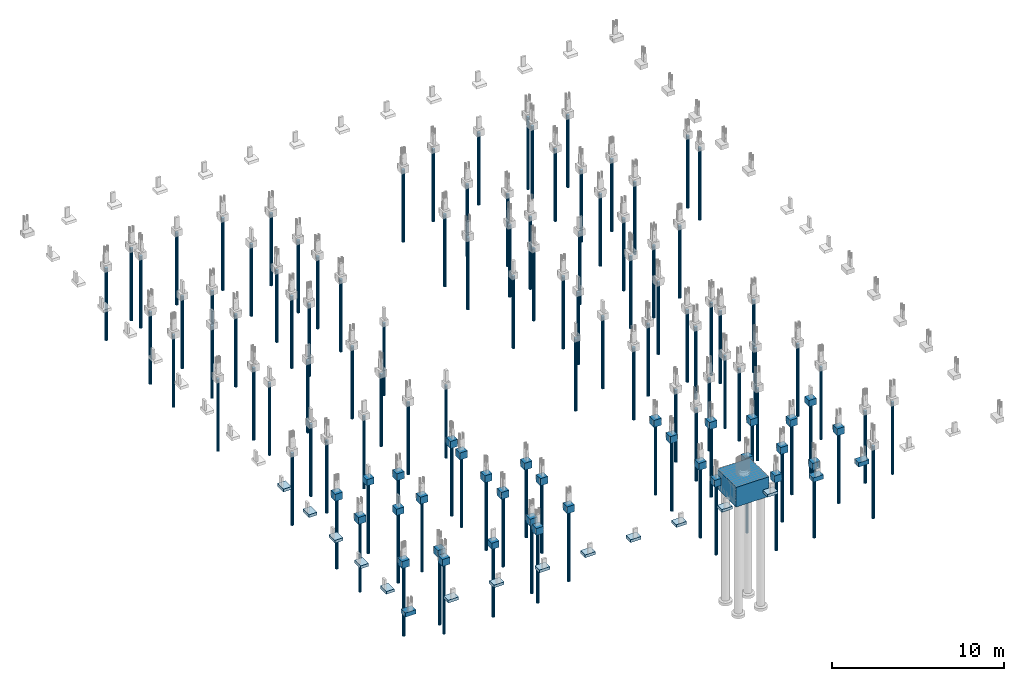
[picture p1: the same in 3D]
Properties of the parts of a building model (IFC4), part 7 of 9

# IfcFooting (170)
Name | ConcreteCover (cm) | Elemento | Elevação (cm) | Cobrimento (cm) | Descrição_01 | Quantidade_01 (m3) | Status_01 | Descrição_02 | Quantidade_02 (m2) | Status_02 = Status_03 | Descrição_03 | Quantidade_03 (kg) | Pset_FootingCommon, Reference | Tipo | Seção_LB (cm) = Seção_LH (cm) | Descrição_04 | Quantidade_04 (kg) | Status_04 | Pset_PileCommon, Reference
P7 | 5 | Sapata | 0 | 5 |  |  | Não dimensionado |  |  |  |  |  | Sapata C-25 | PredefinedType: PAD_FOOTING; AltoQi_Eberick_Elemento - Seção_B: 50 cm; Seção_H: 70 cm
P70 | 3 | Bloco | 0 | 3 |  |  | Não dimensionado |  |  |  |  |  | Bloco C-25 | 1 | 50 |  |  |  | Estaca circular R20 - Concreto C-25
P71 | 3 | Bloco | 0 | 3 | Concreto - C-25 - Abatimento 12 cm | 0.120288 | Dimensionado | Forma - Estrutura - Concreto | 1 | Dimensionado | Armadura - Aço CA50 - ø 6.3 mm | 3.0539 | Bloco C-25 | 1 | 50 |  |  |  | Estaca circular R20 - Concreto C-25
P72 | 3 | Bloco | 0 | 3 | Concreto - C-25 - Abatimento 12 cm | 0.120288 | Dimensionado | Forma - Estrutura - Concreto | 1 | Dimensionado | Armadura - Aço CA50 - ø 6.3 mm | 2.30022 | Bloco C-25 | 1 | 50 | Armadura - Aço CA60 - ø 5.0 mm | 0.471651 | Dimensionado | Estaca circular R20 - Concreto C-25
P73 | 3 | Bloco | 0 | 3 | Concreto - C-25 - Abatimento 12 cm | 0.161663 | Dimensionado | Forma - Estrutura - Concreto | 1.21 | Dimensionado | Armadura - Aço CA50 - ø 6.3 mm | 2.54492 | Bloco C-25 | 1 | 55 | Armadura - Aço CA60 - ø 5.0 mm | 0.533305 | Dimensionado | Estaca circular R20 - Concreto C-25
P74 | 3 | Bloco | 0 | 3 | Concreto - C-25 - Abatimento 12 cm | 0.120288 | Dimensionado | Forma - Estrutura - Concreto | 1 | Dimensionado | Armadura - Aço CA50 - ø 6.3 mm | 2.30022 | Bloco C-25 | 1 | 50 | Armadura - Aço CA60 - ø 5.0 mm | 0.471651 | Dimensionado | Estaca circular R20 - Concreto C-25
P75 | 3 | Bloco | 0 | 3 |  |  | Não dimensionado |  |  |  |  |  | Bloco C-25 | 1 | 50 |  |  |  | Estaca circular R20 - Concreto C-25
P76 | 5 | Sapata | 0 | 5 |  |  | Não dimensionado |  |  |  |  |  | Sapata C-25 | PredefinedType: PAD_FOOTING; AltoQi_Eberick_Elemento - Seção_B: 60 cm; Seção_H: 70 cm
P77 | 5 | Sapata | 0 | 5 |  |  | Não dimensionado |  |  |  |  |  | Sapata C-25 | PredefinedType: PAD_FOOTING; AltoQi_Eberick_Elemento - Seção_B: 50 cm; Seção_H: 70 cm
P78 | 3 | Bloco | 0 | 3 |  |  | Não dimensionado |  |  |  |  |  | Bloco C-25 | 1 | 50 |  |  |  | Estaca circular R20 - Concreto C-25
P79 | 3 | Bloco | 0 | 3 | Concreto - C-25 - Abatimento 12 cm | 0.120288 | Dimensionado | Forma - Estrutura - Concreto | 1 | Dimensionado | Armadura - Aço CA50 - ø 6.3 mm | 2.30022 | Bloco C-25 | 1 | 50 | Armadura - Aço CA60 - ø 5.0 mm | 0.471651 | Dimensionado | Estaca circular R20 - Concreto C-25
P8 | 5 | Sapata | 0 | 5 |  |  | Não dimensionado |  |  |  |  |  | Sapata C-25 | PredefinedType: PAD_FOOTING; AltoQi_Eberick_Elemento - Seção_B: 50 cm; Seção_H: 70 cm
P80 | 3 | Bloco | 0 | 3 | Concreto - C-25 - Abatimento 12 cm | 0.120288 | Dimensionado | Forma - Estrutura - Concreto | 1 | Dimensionado | Armadura - Aço CA50 - ø 6.3 mm | 2.30022 | Bloco C-25 | 1 | 50 | Armadura - Aço CA60 - ø 5.0 mm | 0.471651 | Dimensionado | Estaca circular R20 - Concreto C-25
P81 | 5 | Sapata | 0 | 5 |  |  | Não dimensionado |  |  |  |  |  | Sapata C-25 | PredefinedType: PAD_FOOTING; AltoQi_Eberick_Elemento - Seção_B: 50 cm; Seção_H: 70 cm
P82 | 5 | Sapata | 0 | 5 |  |  | Não dimensionado |  |  |  |  |  | Sapata C-25 | PredefinedType: PAD_FOOTING; AltoQi_Eberick_Elemento - Seção_B: 50 cm; Seção_H: 70 cm
P83 | 3 | Bloco | 0 | 3 |  |  | Não dimensionado |  |  |  |  |  | Bloco C-25 | 1 | 50 |  |  |  | Estaca circular R20 - Concreto C-25
P84 | 3 | Bloco | 0 | 3 |  |  | Não dimensionado |  |  |  |  |  | Bloco C-25 | 1 | 50 |  |  |  | Estaca circular R20 - Concreto C-25
P85 | 5 | Sapata | 0 | 5 |  |  | Não dimensionado |  |  |  |  |  | Sapata C-25 | PredefinedType: PAD_FOOTING; AltoQi_Eberick_Elemento - Seção_B: 60 cm; Seção_H: 70 cm
P86 | 3 | Bloco | 0 | 3 |  |  | Não dimensionado |  |  |  |  |  | Bloco C-25 | 1 | 50 |  |  |  | Estaca circular R20 - Concreto C-25
P87 | 3 | Bloco | 0 | 3 | Concreto - C-25 - Abatimento 12 cm | 0.120288 | Dimensionado | Forma - Estrutura - Concreto | 1 | Dimensionado | Armadura - Aço CA50 - ø 6.3 mm | 2.30022 | Bloco C-25 | 1 | 50 | Armadura - Aço CA60 - ø 5.0 mm | 0.471651 | Dimensionado | Estaca circular R20 - Concreto C-25
P88 | 3 | Bloco | 0 | 3 |  |  | Não dimensionado |  |  |  |  |  | Bloco C-25 | 1 | 40 |  |  |  | Estaca circular R20 - Concreto C-25
P89 | 3 | Bloco | 30 | 3 |  |  | Não dimensionado |  |  |  |  |  | Bloco C-25 | 1 | 40 |  |  |  | Estaca circular R20 - Concreto C-25
P9 | 5 | Sapata | 0 | 5 |  |  | Não dimensionado |  |  |  |  |  | Sapata C-25 | PredefinedType: PAD_FOOTING; AltoQi_Eberick_Elemento - Seção_B: 50 cm; Seção_H: 70 cm
P90 | 3 | Bloco | 0 | 3 | Concreto - C-25 - Abatimento 12 cm | 0.120288 | Dimensionado | Forma - Estrutura - Concreto | 1 | Dimensionado | Armadura - Aço CA50 - ø 6.3 mm | 2.30022 | Bloco C-25 | 1 | 50 | Armadura - Aço CA60 - ø 5.0 mm | 0.471651 | Dimensionado | Estaca circular R20 - Concreto C-25
P91 | 3 | Bloco | 0 | 3 | Concreto - C-25 - Abatimento 12 cm | 0.120288 | Dimensionado | Forma - Estrutura - Concreto | 1 | Dimensionado | Armadura - Aço CA50 - ø 6.3 mm | 2.30022 | Bloco C-25 | 1 | 50 | Armadura - Aço CA60 - ø 5.0 mm | 0.471651 | Dimensionado | Estaca circular R20 - Concreto C-25
P92 | 3 | Bloco | 0 | 3 | Concreto - C-25 - Abatimento 12 cm | 0.120288 | Dimensionado | Forma - Estrutura - Concreto | 1 | Dimensionado | Armadura - Aço CA50 - ø 6.3 mm | 2.30022 | Bloco C-25 | 1 | 50 | Armadura - Aço CA60 - ø 5.0 mm | 0.471651 | Dimensionado | Estaca circular R20 - Concreto C-25
P93 | 5 | Sapata | 0 | 5 |  |  | Não dimensionado |  |  |  |  |  | Sapata C-25 | PredefinedType: PAD_FOOTING; AltoQi_Eberick_Elemento - Seção_B: 50 cm; Seção_H: 70 cm
P94 | 3 | Bloco | 0 | 3 | Concreto - C-25 - Abatimento 12 cm | 0.120288 | Dimensionado | Forma - Estrutura - Concreto | 1 | Dimensionado | Armadura - Aço CA50 - ø 6.3 mm | 2.30022 | Bloco C-25 | 1 | 50 | Armadura - Aço CA60 - ø 5.0 mm | 0.471651 | Dimensionado | Estaca circular R20 - Concreto C-25
P95 | 3 | Bloco | 0 | 3 | Concreto - C-25 - Abatimento 12 cm | 0.120288 | Dimensionado | Forma - Estrutura - Concreto | 1 | Dimensionado | Armadura - Aço CA50 - ø 6.3 mm | 2.30022 | Bloco C-25 | 1 | 50 | Armadura - Aço CA60 - ø 5.0 mm | 0.471651 | Dimensionado | Estaca circular R20 - Concreto C-25
P96 | 3 | Bloco | 0 | 3 | Concreto - C-25 - Abatimento 12 cm | 0.120288 | Dimensionado | Forma - Estrutura - Concreto | 1 | Dimensionado | Armadura - Aço CA50 - ø 6.3 mm | 2.30022 | Bloco C-25 | 1 | 50 | Armadura - Aço CA60 - ø 5.0 mm | 0.471651 | Dimensionado | Estaca circular R20 - Concreto C-25
P97 | 3 | Bloco | 0 | 3 | Concreto - C-25 - Abatimento 12 cm | 0.120288 | Dimensionado | Forma - Estrutura - Concreto | 1 | Dimensionado | Armadura - Aço CA50 - ø 6.3 mm | 2.30022 | Bloco C-25 | 1 | 50 | Armadura - Aço CA60 - ø 5.0 mm | 0.471651 | Dimensionado | Estaca circular R20 - Concreto C-25
P98 | 3 | Bloco | 0 | 3 | Concreto - C-25 - Abatimento 12 cm | 0.120288 | Dimensionado | Forma - Estrutura - Concreto | 1 | Dimensionado | Armadura - Aço CA50 - ø 6.3 mm | 3.0539 | Bloco C-25 | 1 | 50 |  |  |  | Estaca circular R20 - Concreto C-25
P99 | 3 | Bloco | 0 | 3 | Concreto - C-25 - Abatimento 12 cm | 0.120288 | Dimensionado | Forma - Estrutura - Concreto | 1 | Dimensionado | Armadura - Aço CA50 - ø 6.3 mm | 2.30022 | Bloco C-25 | 1 | 50 | Armadura - Aço CA60 - ø 5.0 mm | 0.471651 | Dimensionado | Estaca circular R20 - Concreto C-25
PM1 | 3 | Bloco | 0 | 3 | Concreto - C-25 - Abatimento 12 cm | 0.075288 | Dimensionado | Forma - Estrutura - Concreto | 0.8 | Dimensionado | Armadura - Aço CA50 - ø 6.3 mm | 1.81081 | Bloco C-25 | 1 | 40 | Armadura - Aço CA60 - ø 5.0 mm | 0.409997 | Dimensionado | Estaca circular R20 - Concreto C-25
PM2 | 3 | Bloco | 0 | 3 | Concreto - C-25 - Abatimento 12 cm | 0.075288 | Dimensionado | Forma - Estrutura - Concreto | 0.8 | Dimensionado | Armadura - Aço CA50 - ø 6.3 mm | 1.81081 | Bloco C-25 | 1 | 40 | Armadura - Aço CA60 - ø 5.0 mm | 0.409997 | Dimensionado | Estaca circular R20 - Concreto C-25

# IfcPile (118)
In: FUNDAÇÃO
Material: Concreto
Pset_ConcreteElementGeneral - ConstructionMethod: InSitu; ExposureClass: 1; StrengthClass: C-25
AltoQi_Eberick_Elemento - Elemento: Bloco
AltoQi_Eberick_Padrão - Cobrimento: 3 cm; Classe de concreto: C-25
Pset_FootingCommon - Reference: Bloco C-25
Name | ConcreteCover (cm) | Tipo | Seção_LB (cm) = Seção_LH (cm) | Elevação (cm) | Status_01 | Reference
E102-1 | 3 | 1 | 50 | 0 | Não dimensionado | Estaca circular R20 - Concreto C-25
E104-1 | 3 | 1 | 50 | 0 | Não dimensionado | Estaca circular R20 - Concreto C-25
E105-1 | 3 | 1 | 50 | 0 | Não dimensionado | Estaca circular R20 - Concreto C-25
E106-1 | 3 | 1 | 50 | 0 | Não dimensionado | Estaca circular R20 - Concreto C-25
E107-1 | 3 | 1 | 50 | 0 | Não dimensionado | Estaca circular R20 - Concreto C-25
E108-1 | 3 | 1 | 50 | 0 | Não dimensionado | Estaca circular R20 - Concreto C-25
E109-1 | 3 | 1 | 50 | 0 | Não dimensionado | Estaca circular R20 - Concreto C-25
E110-1 | 3 | 1 | 50 | 0 | Não dimensionado | Estaca circular R20 - Concreto C-25
E111-1 | 3 | 1 | 50 | 0 | Não dimensionado | Estaca circular R20 - Concreto C-25
E112-1 | 3 | 1 | 50 | 0 | Não dimensionado | Estaca circular R20 - Concreto C-25
E113-1 | 3 | 1 | 50 | 0 | Não dimensionado | Estaca circular R20 - Concreto C-25
E116-1 | 3 | 1 | 50 | 0 | Não dimensionado | Estaca circular R20 - Concreto C-25
E117-1 | 3 | 1 | 50 | 0 | Não dimensionado | Estaca circular R20 - Concreto C-25
E118-1 | 3 | 1 | 50 | 0 | Não dimensionado | Estaca circular R20 - Concreto C-25
E119-1 | 3 | 1 | 50 | 0 | Não dimensionado | Estaca circular R20 - Concreto C-25
E120-1 | 3 | 1 | 50 | 0 | Não dimensionado | Estaca circular R20 - Concreto C-25
E121-1 | 3 | 1 | 50 | 0 | Não dimensionado | Estaca circular R20 - Concreto C-25
E122-1 | 3 | 1 | 50 | 0 | Não dimensionado | Estaca circular R20 - Concreto C-25
E123-1 | 3 | 1 | 50 | 0 | Não dimensionado | Estaca circular R20 - Concreto C-25
E124-1 | 3 | 1 | 50 | 0 | Não dimensionado | Estaca circular R20 - Concreto C-25
E126-1 | 3 | 1 | 50 | 0 | Não dimensionado | Estaca circular R20 - Concreto C-25
E127-1 | 3 | 1 | 50 | 0 | Não dimensionado | Estaca circular R20 - Concreto C-25
E128-1 | 3 | 1 | 50 | 0 | Não dimensionado | Estaca circular R20 - Concreto C-25
E129-1 | 3 | 1 | 50 | 0 | Não dimensionado | Estaca circular R20 - Concreto C-25
E131-1 | 3 | 1 | 50 | 0 | Não dimensionado | Estaca circular R20 - Concreto C-25
E132-1 | 3 | 1 | 50 | 0 | Não dimensionado | Estaca circular R20 - Concreto C-25
E134-1 | 3 | 1 | 50 | 0 | Não dimensionado | Estaca circular R20 - Concreto C-25
E135-1 | 3 | 1 | 50 | 0 | Não dimensionado | Estaca circular R20 - Concreto C-25
E136-1 | 3 | 1 | 50 | 0 | Não dimensionado | Estaca circular R20 - Concreto C-25
E137-1 | 3 | 1 | 50 | 0 | Não dimensionado | Estaca circular R20 - Concreto C-25
E138-1 | 3 | 1 | 50 | 0 | Não dimensionado | Estaca circular R20 - Concreto C-25
E139-1 | 3 | 1 | 50 | 0 | Não dimensionado | Estaca circular R20 - Concreto C-25
E140-1 | 3 | 1 | 50 | 0 | Não dimensionado | Estaca circular R20 - Concreto C-25
E141-1 | 3 | 1 | 50 | 0 | Não dimensionado | Estaca circular R20 - Concreto C-25
E143-1 | 3 | 1 | 50 | 0 | Não dimensionado | Estaca circular R20 - Concreto C-25
E144-1 | 3 | 1 | 50 | 0 | Não dimensionado | Estaca circular R20 - Concreto C-25
E145-1 | 3 | 1 | 50 | 0 | Não dimensionado | Estaca circular R20 - Concreto C-25
E146-1 | 3 | 1 | 50 | 0 | Não dimensionado | Estaca circular R20 - Concreto C-25
E147-1 | 3 | 1 | 50 | 0 | Não dimensionado | Estaca circular R20 - Concreto C-25
E148-1 | 3 | 1 | 50 | 0 | Não dimensionado | Estaca circular R20 - Concreto C-25
E150-1 | 3 | 1 | 50 | 0 | Não dimensionado | Estaca circular R20 - Concreto C-25
E152-1 | 3 | 1 | 50 | 0 | Não dimensionado | Estaca circular R20 - Concreto C-25
E153-1 | 3 | 1 | 50 | 0 | Não dimensionado | Estaca circular R20 - Concreto C-25
E154-1 | 3 | 1 | 50 | 0 | Não dimensionado | Estaca circular R20 - Concreto C-25
E17-1 | 3 | 1 | 50 | 0 | Não dimensionado | Estaca circular R20 - Concreto C-25
E18-1 | 3 | 1 | 50 | 0 | Não dimensionado | Estaca circular R20 - Concreto C-25
E19-1 | 3 | 1 | 50 | 0 | Não dimensionado | Estaca circular R20 - Concreto C-25
E20-1 | 3 | 1 | 50 | 0 | Não dimensionado | Estaca circular R20 - Concreto C-25
E21-1 | 3 | 1 | 50 | 0 | Não dimensionado | Estaca circular R20 - Concreto C-25
E22-1 | 3 | 1 | 50 | 0 | Não dimensionado | Estaca circular R20 - Concreto C-25
E23-1 | 3 | 1 | 50 | 0 | Não dimensionado | Estaca circular R20 - Concreto C-25
E24-1 | 3 | 1 | 50 | 0 | Não dimensionado | Estaca circular R20 - Concreto C-25
E25-1 | 3 | 1 | 50 | 0 | Não dimensionado | Estaca circular R20 - Concreto C-25
E26-1 | 3 | 1 | 50 | 0 | Não dimensionado | Estaca circular R20 - Concreto C-25
E27-1 | 3 | 1 | 50 | 0 | Não dimensionado | Estaca circular R20 - Concreto C-25
E28-1 | 3 | 1 | 50 | 0 | Não dimensionado | Estaca circular R20 - Concreto C-25
E31-1 | 3 | 1 | 50 | 0 | Não dimensionado | Estaca circular R20 - Concreto C-25
E32-1 | 3 | 1 | 50 | 0 | Não dimensionado | Estaca circular R20 - Concreto C-25
E33-1 | 3 | 1 | 50 | 0 | Não dimensionado | Estaca circular R20 - Concreto C-25
E34-1 | 3 | 1 | 50 | 0 | Não dimensionado | Estaca circular R20 - Concreto C-25
E36-1 | 3 | 1 | 50 | 0 | Não dimensionado | Estaca circular R20 - Concreto C-25
E37-1 | 3 | 1 | 50 | 0 | Não dimensionado | Estaca circular R20 - Concreto C-25
E39-1 | 3 | 1 | 50 | 0 | Não dimensionado | Estaca circular R20 - Concreto C-25
E40-1 | 3 | 1 | 50 | 0 | Não dimensionado | Estaca circular R20 - Concreto C-25
E41-1 | 3 | 1 | 50 | 0 | Não dimensionado | Estaca circular R20 - Concreto C-25
E42-1 | 3 | 1 | 50 | 0 | Não dimensionado | Estaca circular R20 - Concreto C-25
E43-1 | 3 | 1 | 50 | 0 | Não dimensionado | Estaca circular R20 - Concreto C-25
E44-1 | 3 | 1 | 50 | 0 | Não dimensionado | Estaca circular R20 - Concreto C-25
E45-1 | 3 | 1 | 50 | 0 | Não dimensionado | Estaca circular R20 - Concreto C-25
E47-1 | 3 | 1 | 50 | 0 | Não dimensionado | Estaca circular R20 - Concreto C-25
E48-1 | 3 | 1 | 50 | 0 | Não dimensionado | Estaca circular R20 - Concreto C-25
E49-1 | 3 | 1 | 50 | 0 | Não dimensionado | Estaca circular R20 - Concreto C-25
E50-1 | 3 | 1 | 50 | 0 | Não dimensionado | Estaca circular R20 - Concreto C-25
E51-1 | 3 | 1 | 50 | 0 | Não dimensionado | Estaca circular R20 - Concreto C-25
E52-1 | 3 | 1 | 50 | 0 | Não dimensionado | Estaca circular R20 - Concreto C-25
E53-1 | 3 | 1 | 50 | 0 | Não dimensionado | Estaca circular R20 - Concreto C-25
E54-1 | 3 | 1 | 50 | 0 | Não dimensionado | Estaca circular R20 - Concreto C-25
E55-1 | 3 | 1 | 50 | 0 | Não dimensionado | Estaca circular R20 - Concreto C-25
E56-1 | 3 | 1 | 50 | 0 | Não dimensionado | Estaca circular R20 - Concreto C-25
E58-1 | 3 | 1 | 50 | 0 | Não dimensionado | Estaca circular R20 - Concreto C-25
E60-1 | 3 | 1 | 50 | 0 | Não dimensionado | Estaca circular R20 - Concreto C-25
E61-1 | 3 | 1 | 50 | 0 | Não dimensionado | Estaca circular R20 - Concreto C-25
E62-1 | 3 | 1 | 50 | 0 | Não dimensionado | Estaca circular R20 - Concreto C-25
E65-1 | 3 | 1 | 50 | 0 | Não dimensionado | Estaca circular R20 - Concreto C-25
E66-1 | 3 | 1 | 50 | 0 | Não dimensionado | Estaca circular R20 - Concreto C-25
E67-1 | 3 | 1 | 40 | 0 | Não dimensionado | Estaca circular R20 - Concreto C-25
E68-1 | 3 | 1 | 40 | 30 | Não dimensionado | Estaca circular R20 - Concreto C-25
E69-1 | 3 | 1 | 50 | 0 | Não dimensionado | Estaca circular R20 - Concreto C-25
E70-1 | 3 | 1 | 50 | 0 | Não dimensionado | Estaca circular R20 - Concreto C-25
E71-1 | 3 | 1 | 50 | 0 | Não dimensionado | Estaca circular R20 - Concreto C-25
E72-1 | 3 | 1 | 50 | 0 | Não dimensionado | Estaca circular R20 - Concreto C-25
E73-1 | 3 | 1 | 55 | 0 | Não dimensionado | Estaca circular R20 - Concreto C-25
E74-1 | 3 | 1 | 50 | 0 | Não dimensionado | Estaca circular R20 - Concreto C-25
E75-1 | 3 | 1 | 50 | 0 | Não dimensionado | Estaca circular R20 - Concreto C-25
E78-1 | 3 | 1 | 50 | 0 | Não dimensionado | Estaca circular R20 - Concreto C-25
E79-1 | 3 | 1 | 50 | 0 | Não dimensionado | Estaca circular R20 - Concreto C-25
E80-1 | 3 | 1 | 50 | 0 | Não dimensionado | Estaca circular R20 - Concreto C-25
E83-1 | 3 | 1 | 50 | 0 | Não dimensionado | Estaca circular R20 - Concreto C-25
E84-1 | 3 | 1 | 50 | 0 | Não dimensionado | Estaca circular R20 - Concreto C-25
E86-1 | 3 | 1 | 50 | 0 | Não dimensionado | Estaca circular R20 - Concreto C-25
E87-1 | 3 | 1 | 50 | 0 | Não dimensionado | Estaca circular R20 - Concreto C-25
E88-1 | 3 | 1 | 40 | 0 | Não dimensionado | Estaca circular R20 - Concreto C-25
E89-1 | 3 | 1 | 40 | 30 | Não dimensionado | Estaca circular R20 - Concreto C-25
E90-1 | 3 | 1 | 50 | 0 | Não dimensionado | Estaca circular R20 - Concreto C-25
E91-1 | 3 | 1 | 50 | 0 | Não dimensionado | Estaca circular R20 - Concreto C-25
E92-1 | 3 | 1 | 50 | 0 | Não dimensionado | Estaca circular R20 - Concreto C-25
E94-1 | 3 | 1 | 50 | 0 | Não dimensionado | Estaca circular R20 - Concreto C-25
E95-1 | 3 | 1 | 50 | 0 | Não dimensionado | Estaca circular R20 - Concreto C-25
E96-1 | 3 | 1 | 50 | 0 | Não dimensionado | Estaca circular R20 - Concreto C-25
E97-1 | 3 | 1 | 50 | 0 | Não dimensionado | Estaca circular R20 - Concreto C-25
E98-1 | 3 | 1 | 50 | 0 | Não dimensionado | Estaca circular R20 - Concreto C-25
E99-1 | 3 | 1 | 50 | 0 | Não dimensionado | Estaca circular R20 - Concreto C-25
EM1-1 | 3 | 1 | 40 | 0 | Não dimensionado | Estaca circular R20 - Concreto C-25
EM2-1 | 3 | 1 | 40 | 0 | Não dimensionado | Estaca circular R20 - Concreto C-25
T151-1 | 5 | 4 RET | 220 | 0 | Dimensionado | Tubulão T50 C-25 - 800cm | AltoQi_Eberick-Item_01 - Descrição_01: Concreto - C-25 - Abatimento 12 cm; Quantidade_01: 1.94779 m3; AltoQi_Eberick-Item_02 - Descrição_02: Armadura - Aço CA50 - ø 12.5 mm; Quantidade_02: 23.3995 kg; Status_02: Dimensionado; AltoQi_Eberick-Item_03 - Descrição_03: Armadura - Aço CA60 - ø 5.0 mm; Quantidade_03: 4.40824 kg; Status_03: Dimensionado
T151-2 | 5 | 4 RET | 220 | 0 | Dimensionado | Tubulão T50 C-25 - 800cm | AltoQi_Eberick-Item_01 - Descrição_01: Concreto - C-25 - Abatimento 12 cm; Quantidade_01: 1.94779 m3; AltoQi_Eberick-Item_02 - Descrição_02: Armadura - Aço CA50 - ø 12.5 mm; Quantidade_02: 23.3995 kg; Status_02: Dimensionado; AltoQi_Eberick-Item_03 - Descrição_03: Armadura - Aço CA60 - ø 5.0 mm; Quantidade_03: 4.40824 kg; Status_03: Dimensionado
T151-3 | 5 | 4 RET | 220 | 0 | Dimensionado | Tubulão T50 C-25 - 800cm | AltoQi_Eberick-Item_01 - Descrição_01: Concreto - C-25 - Abatimento 12 cm; Quantidade_01: 1.94779 m3; AltoQi_Eberick-Item_02 - Descrição_02: Armadura - Aço CA50 - ø 12.5 mm; Quantidade_02: 23.3995 kg; Status_02: Dimensionado; AltoQi_Eberick-Item_03 - Descrição_03: Armadura - Aço CA60 - ø 5.0 mm; Quantidade_03: 4.40824 kg; Status_03: Dimensionado
T151-4 | 5 | 4 RET | 220 | 0 | Dimensionado | Tubulão T50 C-25 - 800cm | AltoQi_Eberick-Item_01 - Descrição_01: Concreto - C-25 - Abatimento 12 cm; Quantidade_01: 1.94779 m3; AltoQi_Eberick-Item_02 - Descrição_02: Armadura - Aço CA50 - ø 12.5 mm; Quantidade_02: 23.3995 kg; Status_02: Dimensionado; AltoQi_Eberick-Item_03 - Descrição_03: Armadura - Aço CA60 - ø 5.0 mm; Quantidade_03: 4.40824 kg; Status_03: Dimensionado

# IfcReinforcingBar (17755)
BarLength: 0 cm; PredefinedType: MAIN
Name | In | NominalDiameter (cm) | CrossSectionArea (m2)
8 x P1 - Estribo | FUNDAÇÃO | 0.5 | 0.000019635
4 x P1 - Longitudinal | FUNDAÇÃO | 1 | 0.0000785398
12 x P1 - Sapatas (inferior) | FUNDAÇÃO | 0.8 | 0.0000502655
8 x P100 - Estribo | FUNDAÇÃO | 0.5 | 0.000019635
4 x P100 - Longitudinal | FUNDAÇÃO | 1 | 0.0000785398
12 x P100 - Sapatas (inferior) | FUNDAÇÃO | 0.8 | 0.0000502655
5 x P102 - Blocos (estribos) | FUNDAÇÃO | 0.63 | 0.0000311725
2 x P102 - Blocos (estribos) | FUNDAÇÃO | 0.5 | 0.000019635
10 x P102 - Estribo | FUNDAÇÃO | 0.5 | 0.000019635
6 x P102 - Longitudinal | FUNDAÇÃO | 1 | 0.0000785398
8 x P103 - Estribo | FUNDAÇÃO | 0.5 | 0.000019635
4 x P103 - Longitudinal | FUNDAÇÃO | 1 | 0.0000785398
12 x P103 - Sapatas (inferior) | FUNDAÇÃO | 0.8 | 0.0000502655
2 x P104 - Blocos (estribos) | FUNDAÇÃO | 0.5 | 0.000019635
5 x P104 - Blocos (estribos) | FUNDAÇÃO | 0.63 | 0.0000311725
10 x P104 - Estribo | FUNDAÇÃO | 0.5 | 0.000019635
4 x P104 - Longitudinal | FUNDAÇÃO | 1 | 0.0000785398
5 x P105 - Blocos (estribos) | FUNDAÇÃO | 0.63 | 0.0000311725
2 x P105 - Blocos (estribos) | FUNDAÇÃO | 0.5 | 0.000019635
10 x P105 - Estribo | FUNDAÇÃO | 0.5 | 0.000019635
4 x P105 - Longitudinal | FUNDAÇÃO | 1 | 0.0000785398
5 x P106 - Blocos (estribos) | FUNDAÇÃO | 0.63 | 0.0000311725
2 x P106 - Blocos (estribos) | FUNDAÇÃO | 0.5 | 0.000019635
10 x P106 - Estribo | FUNDAÇÃO | 0.5 | 0.000019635
6 x P106 - Longitudinal | FUNDAÇÃO | 1 | 0.0000785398
5 x P108 - Blocos (estribos) | FUNDAÇÃO | 0.63 | 0.0000311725
2 x P108 - Blocos (estribos) | FUNDAÇÃO | 0.5 | 0.000019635
10 x P108 - Estribo | FUNDAÇÃO | 0.5 | 0.000019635
4 x P108 - Longitudinal | FUNDAÇÃO | 1 | 0.0000785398
5 x P109 - Blocos (estribos) | FUNDAÇÃO | 0.63 | 0.0000311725
2 x P109 - Blocos (estribos) | FUNDAÇÃO | 0.5 | 0.000019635
10 x P109 - Estribo | FUNDAÇÃO | 0.5 | 0.000019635
4 x P109 - Longitudinal | FUNDAÇÃO | 1 | 0.0000785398
5 x P110 - Blocos (estribos) | FUNDAÇÃO | 0.63 | 0.0000311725
2 x P110 - Blocos (estribos) | FUNDAÇÃO | 0.5 | 0.000019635
10 x P110 - Estribo | FUNDAÇÃO | 0.5 | 0.000019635
4 x P110 - Longitudinal | FUNDAÇÃO | 1 | 0.0000785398
2 x P111 - Blocos (estribos) | FUNDAÇÃO | 0.5 | 0.000019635
5 x P111 - Blocos (estribos) | FUNDAÇÃO | 0.63 | 0.0000311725
10 x P111 - Estribo | FUNDAÇÃO | 0.5 | 0.000019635
4 x P111 - Longitudinal | FUNDAÇÃO | 1 | 0.0000785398
5 x P112 - Blocos (estribos) | FUNDAÇÃO | 0.63 | 0.0000311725
2 x P112 - Blocos (estribos) | FUNDAÇÃO | 0.5 | 0.000019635
10 x P112 - Estribo | FUNDAÇÃO | 0.5 | 0.000019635
4 x P112 - Longitudinal | FUNDAÇÃO | 1 | 0.0000785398
5 x P113 - Blocos (estribos) | FUNDAÇÃO | 0.63 | 0.0000311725
2 x P113 - Blocos (estribos) | FUNDAÇÃO | 0.5 | 0.000019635
10 x P113 - Estribo | FUNDAÇÃO | 0.5 | 0.000019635
4 x P113 - Longitudinal | FUNDAÇÃO | 1 | 0.0000785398
8 x P115 - Estribo | FUNDAÇÃO | 0.5 | 0.000019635
4 x P115 - Longitudinal | FUNDAÇÃO | 1 | 0.0000785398
12 x P115 - Sapatas (inferior) | FUNDAÇÃO | 0.8 | 0.0000502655
5 x P116 - Blocos (estribos) | FUNDAÇÃO | 0.63 | 0.0000311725
2 x P116 - Blocos (estribos) | FUNDAÇÃO | 0.5 | 0.000019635
10 x P116 - Estribo | FUNDAÇÃO | 0.5 | 0.000019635
4 x P116 - Longitudinal | FUNDAÇÃO | 1 | 0.0000785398
2 x P118 - Blocos (estribos) | FUNDAÇÃO | 0.5 | 0.000019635
5 x P118 - Blocos (estribos) | FUNDAÇÃO | 0.63 | 0.0000311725
10 x P118 - Estribo | FUNDAÇÃO | 0.5 | 0.000019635
4 x P118 - Longitudinal | FUNDAÇÃO | 1 | 0.0000785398
2 x P119 - Blocos (estribos) | FUNDAÇÃO | 0.5 | 0.000019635
5 x P119 - Blocos (estribos) | FUNDAÇÃO | 0.63 | 0.0000311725
10 x P119 - Estribo | FUNDAÇÃO | 0.5 | 0.000019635
6 x P119 - Longitudinal | FUNDAÇÃO | 1 | 0.0000785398
2 x P120 - Blocos (estribos) | FUNDAÇÃO | 0.5 | 0.000019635
5 x P120 - Blocos (estribos) | FUNDAÇÃO | 0.63 | 0.0000311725
10 x P120 - Estribo | FUNDAÇÃO | 0.5 | 0.000019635
4 x P120 - Longitudinal | FUNDAÇÃO | 1 | 0.0000785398
5 x P121 - Blocos (estribos) | FUNDAÇÃO | 0.63 | 0.0000311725
2 x P121 - Blocos (estribos) | FUNDAÇÃO | 0.5 | 0.000019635
10 x P121 - Estribo | FUNDAÇÃO | 0.5 | 0.000019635
4 x P121 - Longitudinal | FUNDAÇÃO | 1 | 0.0000785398
5 x P122 - Blocos (estribos) | FUNDAÇÃO | 0.63 | 0.0000311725
2 x P122 - Blocos (estribos) | FUNDAÇÃO | 0.5 | 0.000019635
10 x P122 - Estribo | FUNDAÇÃO | 0.5 | 0.000019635
4 x P122 - Longitudinal | FUNDAÇÃO | 1 | 0.0000785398
5 x P123 - Blocos (estribos) | FUNDAÇÃO | 0.63 | 0.0000311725
2 x P123 - Blocos (estribos) | FUNDAÇÃO | 0.5 | 0.000019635
10 x P123 - Estribo | FUNDAÇÃO | 0.5 | 0.000019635
4 x P123 - Longitudinal | FUNDAÇÃO | 1 | 0.0000785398
2 x P124 - Blocos (estribos) | FUNDAÇÃO | 0.5 | 0.000019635
5 x P124 - Blocos (estribos) | FUNDAÇÃO | 0.63 | 0.0000311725
10 x P124 - Estribo | FUNDAÇÃO | 0.5 | 0.000019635
6 x P124 - Longitudinal | FUNDAÇÃO | 1 | 0.0000785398
2 x P126 - Blocos (estribos) | FUNDAÇÃO | 0.5 | 0.000019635
5 x P126 - Blocos (estribos) | FUNDAÇÃO | 0.63 | 0.0000311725
10 x P126 - Estribo | FUNDAÇÃO | 0.5 | 0.000019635
4 x P126 - Longitudinal | FUNDAÇÃO | 1 | 0.0000785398
5 x P127 - Blocos (estribos) | FUNDAÇÃO | 0.63 | 0.0000311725
2 x P127 - Blocos (estribos) | FUNDAÇÃO | 0.5 | 0.000019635
10 x P127 - Estribo | FUNDAÇÃO | 0.5 | 0.000019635
4 x P127 - Longitudinal | FUNDAÇÃO | 1 | 0.0000785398
5 x P128 - Blocos (estribos) | FUNDAÇÃO | 0.63 | 0.0000311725
2 x P128 - Blocos (estribos) | FUNDAÇÃO | 0.5 | 0.000019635
10 x P128 - Estribo | FUNDAÇÃO | 0.5 | 0.000019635
4 x P128 - Longitudinal | FUNDAÇÃO | 1 | 0.0000785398
5 x P129 - Blocos (estribos) | FUNDAÇÃO | 0.63 | 0.0000311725
2 x P129 - Blocos (estribos) | FUNDAÇÃO | 0.5 | 0.000019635
10 x P129 - Estribo | FUNDAÇÃO | 0.5 | 0.000019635
4 x P129 - Longitudinal | FUNDAÇÃO | 1 | 0.0000785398
8 x P130 - Estribo | FUNDAÇÃO | 0.5 | 0.000019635
4 x P130 - Longitudinal | FUNDAÇÃO | 1 | 0.0000785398
12 x P130 - Sapatas (inferior) | FUNDAÇÃO | 0.8 | 0.0000502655
2 x P131 - Blocos (estribos) | FUNDAÇÃO | 0.5 | 0.000019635
5 x P131 - Blocos (estribos) | FUNDAÇÃO | 0.63 | 0.0000311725
10 x P131 - Estribo | FUNDAÇÃO | 0.5 | 0.000019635
4 x P131 - Longitudinal | FUNDAÇÃO | 1 | 0.0000785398
5 x P134 - Blocos (estribos) | FUNDAÇÃO | 0.63 | 0.0000311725
2 x P134 - Blocos (estribos) | FUNDAÇÃO | 0.5 | 0.000019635
10 x P134 - Estribo | FUNDAÇÃO | 0.5 | 0.000019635
4 x P134 - Longitudinal | FUNDAÇÃO | 1 | 0.0000785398
5 x P135 - Blocos (estribos) | FUNDAÇÃO | 0.63 | 0.0000311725
2 x P135 - Blocos (estribos) | FUNDAÇÃO | 0.5 | 0.000019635
10 x P135 - Estribo | FUNDAÇÃO | 0.5 | 0.000019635
8 x P135 - Longitudinal | FUNDAÇÃO | 1 | 0.0000785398
5 x P136 - Blocos (estribos) | FUNDAÇÃO | 0.63 | 0.0000311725
2 x P136 - Blocos (estribos) | FUNDAÇÃO | 0.5 | 0.000019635
10 x P136 - Estribo | FUNDAÇÃO | 0.5 | 0.000019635
4 x P136 - Longitudinal | FUNDAÇÃO | 1 | 0.0000785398
5 x P137 - Blocos (estribos) | FUNDAÇÃO | 0.63 | 0.0000311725
2 x P137 - Blocos (estribos) | FUNDAÇÃO | 0.5 | 0.000019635
10 x P137 - Estribo | FUNDAÇÃO | 0.5 | 0.000019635
4 x P137 - Longitudinal | FUNDAÇÃO | 1 | 0.0000785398
5 x P138 - Blocos (estribos) | FUNDAÇÃO | 0.63 | 0.0000311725
2 x P138 - Blocos (estribos) | FUNDAÇÃO | 0.5 | 0.000019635
10 x P138 - Estribo | FUNDAÇÃO | 0.5 | 0.000019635
4 x P138 - Longitudinal | FUNDAÇÃO | 1 | 0.0000785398
5 x P139 - Blocos (estribos) | FUNDAÇÃO | 0.63 | 0.0000311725
2 x P139 - Blocos (estribos) | FUNDAÇÃO | 0.5 | 0.000019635
10 x P139 - Estribo | FUNDAÇÃO | 0.5 | 0.000019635
4 x P139 - Longitudinal | FUNDAÇÃO | 1 | 0.0000785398
8 x P14 - Estribo | FUNDAÇÃO | 0.5 | 0.000019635
4 x P14 - Longitudinal | FUNDAÇÃO | 1 | 0.0000785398
12 x P14 - Sapatas (inferior) | FUNDAÇÃO | 0.8 | 0.0000502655
5 x P140 - Blocos (estribos) | FUNDAÇÃO | 0.63 | 0.0000311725
2 x P140 - Blocos (estribos) | FUNDAÇÃO | 0.5 | 0.000019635
10 x P140 - Estribo | FUNDAÇÃO | 0.5 | 0.000019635
8 x P140 - Longitudinal | FUNDAÇÃO | 1 | 0.0000785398
2 x P141 - Blocos (estribos) | FUNDAÇÃO | 0.5 | 0.000019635
5 x P141 - Blocos (estribos) | FUNDAÇÃO | 0.63 | 0.0000311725
10 x P141 - Estribo | FUNDAÇÃO | 0.5 | 0.000019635
4 x P141 - Longitudinal | FUNDAÇÃO | 1 | 0.0000785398
8 x P142 - Estribo | FUNDAÇÃO | 0.5 | 0.000019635
4 x P142 - Longitudinal | FUNDAÇÃO | 1 | 0.0000785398
12 x P142 - Sapatas (inferior) | FUNDAÇÃO | 0.8 | 0.0000502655
5 x P143 - Blocos (estribos) | FUNDAÇÃO | 0.63 | 0.0000311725
2 x P143 - Blocos (estribos) | FUNDAÇÃO | 0.5 | 0.000019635
10 x P143 - Estribo | FUNDAÇÃO | 0.5 | 0.000019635
4 x P143 - Longitudinal | FUNDAÇÃO | 1 | 0.0000785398
5 x P145 - Blocos (estribos) | FUNDAÇÃO | 0.63 | 0.0000311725
2 x P145 - Blocos (estribos) | FUNDAÇÃO | 0.5 | 0.000019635
10 x P145 - Estribo | FUNDAÇÃO | 0.5 | 0.000019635
4 x P145 - Longitudinal | FUNDAÇÃO | 1 | 0.0000785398
5 x P146 - Blocos (estribos) | FUNDAÇÃO | 0.63 | 0.0000311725
2 x P146 - Blocos (estribos) | FUNDAÇÃO | 0.5 | 0.000019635
10 x P146 - Estribo | FUNDAÇÃO | 0.5 | 0.000019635
4 x P146 - Longitudinal | FUNDAÇÃO | 1 | 0.0000785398
2 x P147 - Blocos (estribos) | FUNDAÇÃO | 0.5 | 0.000019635
5 x P147 - Blocos (estribos) | FUNDAÇÃO | 0.63 | 0.0000311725
10 x P147 - Estribo | FUNDAÇÃO | 0.5 | 0.000019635
4 x P147 - Longitudinal | FUNDAÇÃO | 1 | 0.0000785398
2 x P148 - Blocos (estribos) | FUNDAÇÃO | 0.5 | 0.000019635
5 x P148 - Blocos (estribos) | FUNDAÇÃO | 0.63 | 0.0000311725
10 x P148 - Estribo | FUNDAÇÃO | 0.5 | 0.000019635
4 x P148 - Longitudinal | FUNDAÇÃO | 1 | 0.0000785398
5 x P150 - Blocos (estribos) | FUNDAÇÃO | 0.63 | 0.0000311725
2 x P150 - Blocos (estribos) | FUNDAÇÃO | 0.5 | 0.000019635
10 x P150 - Estribo | FUNDAÇÃO | 0.5 | 0.000019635
4 x P150 - Longitudinal | FUNDAÇÃO | 1 | 0.0000785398
22 x P151 - Blocos (distribuição) | FUNDAÇÃO | 0.63 | 0.0000311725
6 x P151 - Blocos (estribos) | FUNDAÇÃO | 1.25 | 0.000122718
16 x P151 - Blocos (principal) | FUNDAÇÃO | 1.6 | 0.000201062
22 x P151 - Blocos (superior) | FUNDAÇÃO | 0.63 | 0.0000311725
9 x P151 - Estribo | FUNDAÇÃO | 0.5 | 0.000019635
40 x P151 - Longitudinal | FUNDAÇÃO | 1.6 | 0.000201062
5 x P152 - Blocos (estribos) | FUNDAÇÃO | 0.63 | 0.0000311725
2 x P152 - Blocos (estribos) | FUNDAÇÃO | 0.5 | 0.000019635
10 x P152 - Estribo | FUNDAÇÃO | 0.5 | 0.000019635
4 x P152 - Longitudinal | FUNDAÇÃO | 1 | 0.0000785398
5 x P153 - Blocos (estribos) | FUNDAÇÃO | 0.63 | 0.0000311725
2 x P153 - Blocos (estribos) | FUNDAÇÃO | 0.5 | 0.000019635
10 x P153 - Estribo | FUNDAÇÃO | 0.5 | 0.000019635
4 x P153 - Longitudinal | FUNDAÇÃO | 1 | 0.0000785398
5 x P154 - Blocos (estribos) | FUNDAÇÃO | 0.63 | 0.0000311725
2 x P154 - Blocos (estribos) | FUNDAÇÃO | 0.5 | 0.000019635
10 x P154 - Estribo | FUNDAÇÃO | 0.5 | 0.000019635
4 x P154 - Longitudinal | FUNDAÇÃO | 1 | 0.0000785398
8 x P155 - Estribo | FUNDAÇÃO | 0.5 | 0.000019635
4 x P155 - Longitudinal | FUNDAÇÃO | 1 | 0.0000785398
12 x P155 - Sapatas (inferior) | FUNDAÇÃO | 0.8 | 0.0000502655
8 x P16 - Estribo | FUNDAÇÃO | 0.5 | 0.000019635
4 x P16 - Longitudinal | FUNDAÇÃO | 1 | 0.0000785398
12 x P16 - Sapatas (inferior) | FUNDAÇÃO | 0.8 | 0.0000502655
8 x P164 - Estribo | FUNDAÇÃO | 0.5 | 0.000019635
4 x P164 - Longitudinal | FUNDAÇÃO | 1 | 0.0000785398
12 x P164 - Sapatas (inferior) | FUNDAÇÃO | 0.8 | 0.0000502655
8 x P165 - Estribo | FUNDAÇÃO | 0.5 | 0.000019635
4 x P165 - Longitudinal | FUNDAÇÃO | 1 | 0.0000785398
12 x P165 - Sapatas (inferior) | FUNDAÇÃO | 0.8 | 0.0000502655
8 x P168 - Estribo | FUNDAÇÃO | 0.5 | 0.000019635
4 x P168 - Longitudinal | FUNDAÇÃO | 1 | 0.0000785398
12 x P168 - Sapatas (inferior) | FUNDAÇÃO | 0.8 | 0.0000502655
2 x P17 - Blocos (estribos) | FUNDAÇÃO | 0.5 | 0.000019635
5 x P17 - Blocos (estribos) | FUNDAÇÃO | 0.63 | 0.0000311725
10 x P17 - Estribo | FUNDAÇÃO | 0.5 | 0.000019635
4 x P17 - Longitudinal | FUNDAÇÃO | 1 | 0.0000785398
5 x P19 - Blocos (estribos) | FUNDAÇÃO | 0.63 | 0.0000311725
2 x P19 - Blocos (estribos) | FUNDAÇÃO | 0.5 | 0.000019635
10 x P19 - Estribo | FUNDAÇÃO | 0.5 | 0.000019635
4 x P19 - Longitudinal | FUNDAÇÃO | 1 | 0.0000785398
5 x P20 - Blocos (estribos) | FUNDAÇÃO | 0.63 | 0.0000311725
2 x P20 - Blocos (estribos) | FUNDAÇÃO | 0.5 | 0.000019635
10 x P20 - Estribo | FUNDAÇÃO | 0.5 | 0.000019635
4 x P20 - Longitudinal | FUNDAÇÃO | 1 | 0.0000785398
2 x P22 - Blocos (estribos) | FUNDAÇÃO | 0.5 | 0.000019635
5 x P22 - Blocos (estribos) | FUNDAÇÃO | 0.63 | 0.0000311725
10 x P22 - Estribo | FUNDAÇÃO | 0.5 | 0.000019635
4 x P22 - Longitudinal | FUNDAÇÃO | 1 | 0.0000785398
5 x P23 - Blocos (estribos) | FUNDAÇÃO | 0.63 | 0.0000311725
2 x P23 - Blocos (estribos) | FUNDAÇÃO | 0.5 | 0.000019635
10 x P23 - Estribo | FUNDAÇÃO | 0.5 | 0.000019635
4 x P23 - Longitudinal | FUNDAÇÃO | 1 | 0.0000785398
5 x P24 - Blocos (estribos) | FUNDAÇÃO | 0.63 | 0.0000311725
2 x P24 - Blocos (estribos) | FUNDAÇÃO | 0.5 | 0.000019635
10 x P24 - Estribo | FUNDAÇÃO | 0.5 | 0.000019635
4 x P24 - Longitudinal | FUNDAÇÃO | 1 | 0.0000785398
5 x P25 - Blocos (estribos) | FUNDAÇÃO | 0.63 | 0.0000311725
2 x P25 - Blocos (estribos) | FUNDAÇÃO | 0.5 | 0.000019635
10 x P25 - Estribo | FUNDAÇÃO | 0.5 | 0.000019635
4 x P25 - Longitudinal | FUNDAÇÃO | 1 | 0.0000785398
2 x P26 - Blocos (estribos) | FUNDAÇÃO | 0.5 | 0.000019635
5 x P26 - Blocos (estribos) | FUNDAÇÃO | 0.63 | 0.0000311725
10 x P26 - Estribo | FUNDAÇÃO | 0.5 | 0.000019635
8 x P26 - Longitudinal | FUNDAÇÃO | 1 | 0.0000785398
2 x P27 - Blocos (estribos) | FUNDAÇÃO | 0.5 | 0.000019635
5 x P27 - Blocos (estribos) | FUNDAÇÃO | 0.63 | 0.0000311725
10 x P27 - Estribo | FUNDAÇÃO | 0.5 | 0.000019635
4 x P27 - Longitudinal | FUNDAÇÃO | 1 | 0.0000785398
5 x P28 - Blocos (estribos) | FUNDAÇÃO | 0.63 | 0.0000311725
2 x P28 - Blocos (estribos) | FUNDAÇÃO | 0.5 | 0.000019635
10 x P28 - Estribo | FUNDAÇÃO | 0.5 | 0.000019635
4 x P28 - Longitudinal | FUNDAÇÃO | 1 | 0.0000785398
8 x P30 - Estribo | FUNDAÇÃO | 0.5 | 0.000019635
4 x P30 - Longitudinal | FUNDAÇÃO | 1 | 0.0000785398
12 x P30 - Sapatas (inferior) | FUNDAÇÃO | 0.8 | 0.0000502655
2 x P32 - Blocos (estribos) | FUNDAÇÃO | 0.5 | 0.000019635
5 x P32 - Blocos (estribos) | FUNDAÇÃO | 0.63 | 0.0000311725
10 x P32 - Estribo | FUNDAÇÃO | 0.5 | 0.000019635
4 x P32 - Longitudinal | FUNDAÇÃO | 1 | 0.0000785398
2 x P33 - Blocos (estribos) | FUNDAÇÃO | 0.5 | 0.000019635
5 x P33 - Blocos (estribos) | FUNDAÇÃO | 0.63 | 0.0000311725
10 x P33 - Estribo | FUNDAÇÃO | 0.5 | 0.000019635
4 x P33 - Longitudinal | FUNDAÇÃO | 1 | 0.0000785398
5 x P34 - Blocos (estribos) | FUNDAÇÃO | 0.63 | 0.0000311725
2 x P34 - Blocos (estribos) | FUNDAÇÃO | 0.5 | 0.000019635
10 x P34 - Estribo | FUNDAÇÃO | 0.5 | 0.000019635
4 x P34 - Longitudinal | FUNDAÇÃO | 1 | 0.0000785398
2 x P36 - Blocos (estribos) | FUNDAÇÃO | 0.5 | 0.000019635
5 x P36 - Blocos (estribos) | FUNDAÇÃO | 0.63 | 0.0000311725
10 x P36 - Estribo | FUNDAÇÃO | 0.5 | 0.000019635
4 x P36 - Longitudinal | FUNDAÇÃO | 1 | 0.0000785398
8 x P38 - Estribo | FUNDAÇÃO | 0.5 | 0.000019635
4 x P38 - Longitudinal | FUNDAÇÃO | 1 | 0.0000785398
12 x P38 - Sapatas (inferior) | FUNDAÇÃO | 0.8 | 0.0000502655
5 x P39 - Blocos (estribos) | FUNDAÇÃO | 0.63 | 0.0000311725
2 x P39 - Blocos (estribos) | FUNDAÇÃO | 0.5 | 0.000019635
10 x P39 - Estribo | FUNDAÇÃO | 0.5 | 0.000019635
4 x P39 - Longitudinal | FUNDAÇÃO | 1 | 0.0000785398
7 x P40 - Blocos (estribos) | FUNDAÇÃO | 0.63 | 0.0000311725
10 x P40 - Estribo | FUNDAÇÃO | 0.5 | 0.000019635
4 x P40 - Longitudinal | FUNDAÇÃO | 1 | 0.0000785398
2 x P41 - Blocos (estribos) | FUNDAÇÃO | 0.5 | 0.000019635
5 x P41 - Blocos (estribos) | FUNDAÇÃO | 0.63 | 0.0000311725
10 x P41 - Estribo | FUNDAÇÃO | 0.5 | 0.000019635
4 x P41 - Longitudinal | FUNDAÇÃO | 1 | 0.0000785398
7 x P42 - Blocos (estribos) | FUNDAÇÃO | 0.63 | 0.0000311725
10 x P42 - Estribo | FUNDAÇÃO | 0.5 | 0.000019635
6 x P42 - Longitudinal | FUNDAÇÃO | 1 | 0.0000785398
2 x P43 - Blocos (estribos) | FUNDAÇÃO | 0.5 | 0.000019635
5 x P43 - Blocos (estribos) | FUNDAÇÃO | 0.63 | 0.0000311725
10 x P43 - Estribo | FUNDAÇÃO | 0.5 | 0.000019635
4 x P43 - Longitudinal | FUNDAÇÃO | 1 | 0.0000785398
7 x P44 - Blocos (estribos) | FUNDAÇÃO | 0.63 | 0.0000311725
10 x P44 - Estribo | FUNDAÇÃO | 0.5 | 0.000019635
4 x P44 - Longitudinal | FUNDAÇÃO | 1 | 0.0000785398
5 x P45 - Blocos (estribos) | FUNDAÇÃO | 0.63 | 0.0000311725
2 x P45 - Blocos (estribos) | FUNDAÇÃO | 0.5 | 0.000019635
10 x P45 - Estribo | FUNDAÇÃO | 0.5 | 0.000019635
6 x P45 - Longitudinal | FUNDAÇÃO | 1 | 0.0000785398
2 x P47 - Blocos (estribos) | FUNDAÇÃO | 0.5 | 0.000019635
5 x P47 - Blocos (estribos) | FUNDAÇÃO | 0.63 | 0.0000311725
10 x P47 - Estribo | FUNDAÇÃO | 0.5 | 0.000019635
6 x P47 - Longitudinal | FUNDAÇÃO | 1 | 0.0000785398
5 x P49 - Blocos (estribos) | FUNDAÇÃO | 0.63 | 0.0000311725
2 x P49 - Blocos (estribos) | FUNDAÇÃO | 0.5 | 0.000019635
10 x P49 - Estribo | FUNDAÇÃO | 0.5 | 0.000019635
4 x P49 - Longitudinal | FUNDAÇÃO | 1 | 0.0000785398
2 x P50 - Blocos (estribos) | FUNDAÇÃO | 0.5 | 0.000019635
5 x P50 - Blocos (estribos) | FUNDAÇÃO | 0.63 | 0.0000311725
10 x P50 - Estribo | FUNDAÇÃO | 0.5 | 0.000019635
4 x P50 - Longitudinal | FUNDAÇÃO | 1 | 0.0000785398
2 x P51 - Blocos (estribos) | FUNDAÇÃO | 0.5 | 0.000019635
5 x P51 - Blocos (estribos) | FUNDAÇÃO | 0.63 | 0.0000311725
10 x P51 - Estribo | FUNDAÇÃO | 0.5 | 0.000019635
4 x P51 - Longitudinal | FUNDAÇÃO | 1 | 0.0000785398
5 x P52 - Blocos (estribos) | FUNDAÇÃO | 0.63 | 0.0000311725
2 x P52 - Blocos (estribos) | FUNDAÇÃO | 0.5 | 0.000019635
10 x P52 - Estribo | FUNDAÇÃO | 0.5 | 0.000019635
4 x P52 - Longitudinal | FUNDAÇÃO | 1 | 0.0000785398
5 x P53 - Blocos (estribos) | FUNDAÇÃO | 0.63 | 0.0000311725
2 x P53 - Blocos (estribos) | FUNDAÇÃO | 0.5 | 0.000019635
10 x P53 - Estribo | FUNDAÇÃO | 0.5 | 0.000019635
4 x P53 - Longitudinal | FUNDAÇÃO | 1 | 0.0000785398
5 x P54 - Blocos (estribos) | FUNDAÇÃO | 0.63 | 0.0000311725
2 x P54 - Blocos (estribos) | FUNDAÇÃO | 0.5 | 0.000019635
10 x P54 - Estribo | FUNDAÇÃO | 0.5 | 0.000019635
4 x P54 - Longitudinal | FUNDAÇÃO | 1 | 0.0000785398
5 x P55 - Blocos (estribos) | FUNDAÇÃO | 0.63 | 0.0000311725
2 x P55 - Blocos (estribos) | FUNDAÇÃO | 0.5 | 0.000019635
10 x P55 - Estribo | FUNDAÇÃO | 0.5 | 0.000019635
4 x P55 - Longitudinal | FUNDAÇÃO | 1 | 0.0000785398
5 x P56 - Blocos (estribos) | FUNDAÇÃO | 0.63 | 0.0000311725
2 x P56 - Blocos (estribos) | FUNDAÇÃO | 0.5 | 0.000019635
10 x P56 - Estribo | FUNDAÇÃO | 0.5 | 0.000019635
4 x P56 - Longitudinal | FUNDAÇÃO | 1 | 0.0000785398
8 x P57 - Estribo | FUNDAÇÃO | 0.5 | 0.000019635
4 x P57 - Longitudinal | FUNDAÇÃO | 1 | 0.0000785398
12 x P57 - Sapatas (inferior) | FUNDAÇÃO | 0.8 | 0.0000502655
2 x P58 - Blocos (estribos) | FUNDAÇÃO | 0.5 | 0.000019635
5 x P58 - Blocos (estribos) | FUNDAÇÃO | 0.63 | 0.0000311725
10 x P58 - Estribo | FUNDAÇÃO | 0.5 | 0.000019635
6 x P58 - Longitudinal | FUNDAÇÃO | 1 | 0.0000785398
5 x P60 - Blocos (estribos) | FUNDAÇÃO | 0.63 | 0.0000311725
2 x P60 - Blocos (estribos) | FUNDAÇÃO | 0.5 | 0.000019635
10 x P60 - Estribo | FUNDAÇÃO | 0.5 | 0.000019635
4 x P60 - Longitudinal | FUNDAÇÃO | 1 | 0.0000785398
5 x P62 - Blocos (estribos) | FUNDAÇÃO | 0.63 | 0.0000311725
2 x P62 - Blocos (estribos) | FUNDAÇÃO | 0.5 | 0.000019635
10 x P62 - Estribo | FUNDAÇÃO | 0.5 | 0.000019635
4 x P62 - Longitudinal | FUNDAÇÃO | 1 | 0.0000785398
8 x P63 - Estribo | FUNDAÇÃO | 0.5 | 0.000019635
4 x P63 - Longitudinal | FUNDAÇÃO | 1 | 0.0000785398
12 x P63 - Sapatas (inferior) | FUNDAÇÃO | 0.8 | 0.0000502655
2 x P65 - Blocos (estribos) | FUNDAÇÃO | 0.5 | 0.000019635
5 x P65 - Blocos (estribos) | FUNDAÇÃO | 0.63 | 0.0000311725
10 x P65 - Estribo | FUNDAÇÃO | 0.5 | 0.000019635
6 x P65 - Longitudinal | FUNDAÇÃO | 1 | 0.0000785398
2 x P66 - Blocos (estribos) | FUNDAÇÃO | 0.5 | 0.000019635
5 x P66 - Blocos (estribos) | FUNDAÇÃO | 0.63 | 0.0000311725
10 x P66 - Estribo | FUNDAÇÃO | 0.5 | 0.000019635
4 x P66 - Longitudinal | FUNDAÇÃO | 1 | 0.0000785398
5 x P69 - Blocos (estribos) | FUNDAÇÃO | 0.63 | 0.0000311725
2 x P69 - Blocos (estribos) | FUNDAÇÃO | 0.5 | 0.000019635
10 x P69 - Estribo | FUNDAÇÃO | 0.5 | 0.000019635
8 x P69 - Longitudinal | FUNDAÇÃO | 1 | 0.0000785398
7 x P71 - Blocos (estribos) | FUNDAÇÃO | 0.63 | 0.0000311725
10 x P71 - Estribo | FUNDAÇÃO | 0.5 | 0.000019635
4 x P71 - Longitudinal | FUNDAÇÃO | 1 | 0.0000785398
2 x P72 - Blocos (estribos) | FUNDAÇÃO | 0.5 | 0.000019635
5 x P72 - Blocos (estribos) | FUNDAÇÃO | 0.63 | 0.0000311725
10 x P72 - Estribo | FUNDAÇÃO | 0.5 | 0.000019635
4 x P72 - Longitudinal | FUNDAÇÃO | 1 | 0.0000785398
5 x P73 - Blocos (estribos) | FUNDAÇÃO | 0.63 | 0.0000311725
2 x P73 - Blocos (estribos) | FUNDAÇÃO | 0.5 | 0.000019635
10 x P73 - Estribo | FUNDAÇÃO | 0.5 | 0.000019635
10 x P73 - Grampo | FUNDAÇÃO | 0.5 | 0.000019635
6 x P73 - Longitudinal | FUNDAÇÃO | 1 | 0.0000785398
5 x P74 - Blocos (estribos) | FUNDAÇÃO | 0.63 | 0.0000311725
2 x P74 - Blocos (estribos) | FUNDAÇÃO | 0.5 | 0.000019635
10 x P74 - Estribo | FUNDAÇÃO | 0.5 | 0.000019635
4 x P74 - Longitudinal | FUNDAÇÃO | 1 | 0.0000785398
5 x P79 - Blocos (estribos) | FUNDAÇÃO | 0.63 | 0.0000311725
2 x P79 - Blocos (estribos) | FUNDAÇÃO | 0.5 | 0.000019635
10 x P79 - Estribo | FUNDAÇÃO | 0.5 | 0.000019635
4 x P79 - Longitudinal | FUNDAÇÃO | 1 | 0.0000785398
2 x P80 - Blocos (estribos) | FUNDAÇÃO | 0.5 | 0.000019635
5 x P80 - Blocos (estribos) | FUNDAÇÃO | 0.63 | 0.0000311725
10 x P80 - Estribo | FUNDAÇÃO | 0.5 | 0.000019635
4 x P80 - Longitudinal | FUNDAÇÃO | 1 | 0.0000785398
5 x P87 - Blocos (estribos) | FUNDAÇÃO | 0.63 | 0.0000311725
2 x P87 - Blocos (estribos) | FUNDAÇÃO | 0.5 | 0.000019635
10 x P87 - Estribo | FUNDAÇÃO | 0.5 | 0.000019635
4 x P87 - Longitudinal | FUNDAÇÃO | 1 | 0.0000785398
2 x P90 - Blocos (estribos) | FUNDAÇÃO | 0.5 | 0.000019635
5 x P90 - Blocos (estribos) | FUNDAÇÃO | 0.63 | 0.0000311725
10 x P90 - Estribo | FUNDAÇÃO | 0.5 | 0.000019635
4 x P90 - Longitudinal | FUNDAÇÃO | 1 | 0.0000785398
5 x P91 - Blocos (estribos) | FUNDAÇÃO | 0.63 | 0.0000311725
2 x P91 - Blocos (estribos) | FUNDAÇÃO | 0.5 | 0.000019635
10 x P91 - Estribo | FUNDAÇÃO | 0.5 | 0.000019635
4 x P91 - Longitudinal | FUNDAÇÃO | 1 | 0.0000785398
2 x P92 - Blocos (estribos) | FUNDAÇÃO | 0.5 | 0.000019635
5 x P92 - Blocos (estribos) | FUNDAÇÃO | 0.63 | 0.0000311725
10 x P92 - Estribo | FUNDAÇÃO | 0.5 | 0.000019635
4 x P92 - Longitudinal | FUNDAÇÃO | 1 | 0.0000785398
5 x P94 - Blocos (estribos) | FUNDAÇÃO | 0.63 | 0.0000311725
2 x P94 - Blocos (estribos) | FUNDAÇÃO | 0.5 | 0.000019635
10 x P94 - Estribo | FUNDAÇÃO | 0.5 | 0.000019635
6 x P94 - Longitudinal | FUNDAÇÃO | 1 | 0.0000785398
5 x P95 - Blocos (estribos) | FUNDAÇÃO | 0.63 | 0.0000311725
2 x P95 - Blocos (estribos) | FUNDAÇÃO | 0.5 | 0.000019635
10 x P95 - Estribo | FUNDAÇÃO | 0.5 | 0.000019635
4 x P95 - Longitudinal | FUNDAÇÃO | 1 | 0.0000785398
5 x P96 - Blocos (estribos) | FUNDAÇÃO | 0.63 | 0.0000311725
2 x P96 - Blocos (estribos) | FUNDAÇÃO | 0.5 | 0.000019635
10 x P96 - Estribo | FUNDAÇÃO | 0.5 | 0.000019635
4 x P96 - Longitudinal | FUNDAÇÃO | 1 | 0.0000785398
2 x P97 - Blocos (estribos) | FUNDAÇÃO | 0.5 | 0.000019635
5 x P97 - Blocos (estribos) | FUNDAÇÃO | 0.63 | 0.0000311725
10 x P97 - Estribo | FUNDAÇÃO | 0.5 | 0.000019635
4 x P97 - Longitudinal | FUNDAÇÃO | 1 | 0.0000785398
7 x P98 - Blocos (estribos) | FUNDAÇÃO | 0.63 | 0.0000311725
10 x P98 - Estribo | FUNDAÇÃO | 0.5 | 0.000019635
4 x P98 - Longitudinal | FUNDAÇÃO | 1 | 0.0000785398
5 x P99 - Blocos (estribos) | FUNDAÇÃO | 0.63 | 0.0000311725
2 x P99 - Blocos (estribos) | FUNDAÇÃO | 0.5 | 0.000019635
10 x P99 - Estribo | FUNDAÇÃO | 0.5 | 0.000019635
4 x P99 - Longitudinal | FUNDAÇÃO | 1 | 0.0000785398
5 x PM1 - Blocos (estribos) | FUNDAÇÃO | 0.63 | 0.0000311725
2 x PM1 - Blocos (estribos) | FUNDAÇÃO | 0.5 | 0.000019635
7 x PM1 - Estribo | FUNDAÇÃO | 0.5 | 0.000019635
4 x PM1 - Longitudinal | FUNDAÇÃO | 1 | 0.0000785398
2 x PM2 - Blocos (estribos) | FUNDAÇÃO | 0.5 | 0.000019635
5 x PM2 - Blocos (estribos) | FUNDAÇÃO | 0.63 | 0.0000311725
7 x PM2 - Estribo | FUNDAÇÃO | 0.5 | 0.000019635
4 x PM2 - Longitudinal | FUNDAÇÃO | 1 | 0.0000785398
15 x LM1 - Inferior X | VIGA BALDRAME | 0.8 | 0.0000502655
2 x LM1 - Inferior Y | VIGA BALDRAME | 0.8 | 0.0000502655
29 x LM1 - Superior X | VIGA BALDRAME | 0.8 | 0.0000502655
4 x LM1 - Superior Y | VIGA BALDRAME | 0.8 | 0.0000502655
15 x LM2 - Inferior X | VIGA BALDRAME | 0.8 | 0.0000502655
2 x LM2 - Inferior Y | VIGA BALDRAME | 0.8 | 0.0000502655
29 x LM2 - Superior X | VIGA BALDRAME | 0.8 | 0.0000502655
4 x LM2 - Superior Y | VIGA BALDRAME | 0.8 | 0.0000502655
3 x P1 - Estribo | VIGA BALDRAME | 0.5 | 0.000019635
4 x P1 - Longitudinal | VIGA BALDRAME | 1 | 0.0000785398
3 x P100 - Estribo | VIGA BALDRAME | 0.5 | 0.000019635
4 x P100 - Longitudinal | VIGA BALDRAME | 1 | 0.0000785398
3 x P102 - Estribo | VIGA BALDRAME | 0.5 | 0.000019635
3 x P102 - Grampo | VIGA BALDRAME | 0.5 | 0.000019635
6 x P102 - Longitudinal | VIGA BALDRAME | 1 | 0.0000785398
3 x P103 - Estribo | VIGA BALDRAME | 0.5 | 0.000019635
4 x P103 - Longitudinal | VIGA BALDRAME | 1 | 0.0000785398
3 x P104 - Estribo | VIGA BALDRAME | 0.5 | 0.000019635
4 x P104 - Longitudinal | VIGA BALDRAME | 1 | 0.0000785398
3 x P105 - Estribo | VIGA BALDRAME | 0.5 | 0.000019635
4 x P105 - Longitudinal | VIGA BALDRAME | 1 | 0.0000785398
3 x P106 - Estribo | VIGA BALDRAME | 0.5 | 0.000019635
3 x P106 - Grampo | VIGA BALDRAME | 0.5 | 0.000019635
6 x P106 - Longitudinal | VIGA BALDRAME | 1 | 0.0000785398
3 x P108 - Estribo | VIGA BALDRAME | 0.5 | 0.000019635
4 x P108 - Longitudinal | VIGA BALDRAME | 1 | 0.0000785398
3 x P109 - Estribo | VIGA BALDRAME | 0.5 | 0.000019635
4 x P109 - Longitudinal | VIGA BALDRAME | 1 | 0.0000785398
3 x P110 - Estribo | VIGA BALDRAME | 0.5 | 0.000019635
4 x P110 - Longitudinal | VIGA BALDRAME | 1 | 0.0000785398
3 x P111 - Estribo | VIGA BALDRAME | 0.5 | 0.000019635
4 x P111 - Longitudinal | VIGA BALDRAME | 1 | 0.0000785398
3 x P112 - Estribo | VIGA BALDRAME | 0.5 | 0.000019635
4 x P112 - Longitudinal | VIGA BALDRAME | 1 | 0.0000785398
3 x P113 - Estribo | VIGA BALDRAME | 0.5 | 0.000019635
4 x P113 - Longitudinal | VIGA BALDRAME | 1 | 0.0000785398
3 x P115 - Estribo | VIGA BALDRAME | 0.5 | 0.000019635
4 x P115 - Longitudinal | VIGA BALDRAME | 1 | 0.0000785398
3 x P116 - Estribo | VIGA BALDRAME | 0.5 | 0.000019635
4 x P116 - Longitudinal | VIGA BALDRAME | 1 | 0.0000785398
3 x P118 - Estribo | VIGA BALDRAME | 0.5 | 0.000019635
4 x P118 - Longitudinal | VIGA BALDRAME | 1 | 0.0000785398
3 x P119 - Estribo | VIGA BALDRAME | 0.5 | 0.000019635
3 x P119 - Grampo | VIGA BALDRAME | 0.5 | 0.000019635
6 x P119 - Longitudinal | VIGA BALDRAME | 1 | 0.0000785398
3 x P120 - Estribo | VIGA BALDRAME | 0.5 | 0.000019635
4 x P120 - Longitudinal | VIGA BALDRAME | 1 | 0.0000785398
3 x P121 - Estribo | VIGA BALDRAME | 0.5 | 0.000019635
4 x P121 - Longitudinal | VIGA BALDRAME | 1 | 0.0000785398
3 x P122 - Estribo | VIGA BALDRAME | 0.5 | 0.000019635
4 x P122 - Longitudinal | VIGA BALDRAME | 1 | 0.0000785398
3 x P123 - Estribo | VIGA BALDRAME | 0.5 | 0.000019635
4 x P123 - Longitudinal | VIGA BALDRAME | 1 | 0.0000785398
3 x P124 - Estribo | VIGA BALDRAME | 0.5 | 0.000019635
3 x P124 - Grampo | VIGA BALDRAME | 0.5 | 0.000019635
6 x P124 - Longitudinal | VIGA BALDRAME | 1 | 0.0000785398
3 x P126 - Estribo | VIGA BALDRAME | 0.5 | 0.000019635
4 x P126 - Longitudinal | VIGA BALDRAME | 1 | 0.0000785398
3 x P127 - Estribo | VIGA BALDRAME | 0.5 | 0.000019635
4 x P127 - Longitudinal | VIGA BALDRAME | 1 | 0.0000785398
3 x P128 - Estribo | VIGA BALDRAME | 0.5 | 0.000019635
4 x P128 - Longitudinal | VIGA BALDRAME | 1 | 0.0000785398
3 x P129 - Estribo | VIGA BALDRAME | 0.5 | 0.000019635
4 x P129 - Longitudinal | VIGA BALDRAME | 1 | 0.0000785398
3 x P130 - Estribo | VIGA BALDRAME | 0.5 | 0.000019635
4 x P130 - Longitudinal | VIGA BALDRAME | 1 | 0.0000785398
3 x P131 - Estribo | VIGA BALDRAME | 0.5 | 0.000019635
4 x P131 - Longitudinal | VIGA BALDRAME | 1 | 0.0000785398
3 x P134 - Estribo | VIGA BALDRAME | 0.5 | 0.000019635
4 x P134 - Longitudinal | VIGA BALDRAME | 1 | 0.0000785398
3 x P135 - Estribo | VIGA BALDRAME | 0.5 | 0.000019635
8 x P135 - Longitudinal | VIGA BALDRAME | 1 | 0.0000785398
3 x P136 - Estribo | VIGA BALDRAME | 0.5 | 0.000019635
4 x P136 - Longitudinal | VIGA BALDRAME | 1 | 0.0000785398
3 x P137 - Estribo | VIGA BALDRAME | 0.5 | 0.000019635
4 x P137 - Longitudinal | VIGA BALDRAME | 1 | 0.0000785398
3 x P138 - Estribo | VIGA BALDRAME | 0.5 | 0.000019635
4 x P138 - Longitudinal | VIGA BALDRAME | 1 | 0.0000785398
3 x P139 - Estribo | VIGA BALDRAME | 0.5 | 0.000019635
4 x P139 - Longitudinal | VIGA BALDRAME | 1 | 0.0000785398
3 x P14 - Estribo | VIGA BALDRAME | 0.5 | 0.000019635
4 x P14 - Longitudinal | VIGA BALDRAME | 1 | 0.0000785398
3 x P140 - Estribo | VIGA BALDRAME | 0.5 | 0.000019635
8 x P140 - Longitudinal | VIGA BALDRAME | 1 | 0.0000785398
3 x P141 - Estribo | VIGA BALDRAME | 0.5 | 0.000019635
4 x P141 - Longitudinal | VIGA BALDRAME | 1 | 0.0000785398
3 x P142 - Estribo | VIGA BALDRAME | 0.5 | 0.000019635
4 x P142 - Longitudinal | VIGA BALDRAME | 1 | 0.0000785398
2 x P142 - Longitudinal | VIGA BALDRAME | 1.25 | 0.000122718
3 x P143 - Estribo | VIGA BALDRAME | 0.5 | 0.000019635
4 x P143 - Longitudinal | VIGA BALDRAME | 1 | 0.0000785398
3 x P145 - Estribo | VIGA BALDRAME | 0.5 | 0.000019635
4 x P145 - Longitudinal | VIGA BALDRAME | 1 | 0.0000785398
3 x P146 - Estribo | VIGA BALDRAME | 0.5 | 0.000019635
4 x P146 - Longitudinal | VIGA BALDRAME | 1 | 0.0000785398
3 x P147 - Estribo | VIGA BALDRAME | 0.5 | 0.000019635
4 x P147 - Longitudinal | VIGA BALDRAME | 1 | 0.0000785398
3 x P148 - Estribo | VIGA BALDRAME | 0.5 | 0.000019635
4 x P148 - Longitudinal | VIGA BALDRAME | 1 | 0.0000785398
3 x P150 - Estribo | VIGA BALDRAME | 0.5 | 0.000019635
4 x P150 - Longitudinal | VIGA BALDRAME | 1 | 0.0000785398
2 x P151 - Estribo | VIGA BALDRAME | 0.5 | 0.000019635
40 x P151 - Longitudinal | VIGA BALDRAME | 1.6 | 0.000201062
3 x P152 - Estribo | VIGA BALDRAME | 0.5 | 0.000019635
4 x P152 - Longitudinal | VIGA BALDRAME | 1 | 0.0000785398
3 x P153 - Estribo | VIGA BALDRAME | 0.5 | 0.000019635
4 x P153 - Longitudinal | VIGA BALDRAME | 1 | 0.0000785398
3 x P154 - Estribo | VIGA BALDRAME | 0.5 | 0.000019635
4 x P154 - Longitudinal | VIGA BALDRAME | 1 | 0.0000785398
3 x P155 - Estribo | VIGA BALDRAME | 0.5 | 0.000019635
6 x P155 - Longitudinal | VIGA BALDRAME | 1 | 0.0000785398
3 x P16 - Estribo | VIGA BALDRAME | 0.5 | 0.000019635
4 x P16 - Longitudinal | VIGA BALDRAME | 1 | 0.0000785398
3 x P164 - Estribo | VIGA BALDRAME | 0.5 | 0.000019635
4 x P164 - Longitudinal | VIGA BALDRAME | 1 | 0.0000785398
3 x P165 - Estribo | VIGA BALDRAME | 0.5 | 0.000019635
4 x P165 - Longitudinal | VIGA BALDRAME | 1 | 0.0000785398
3 x P168 - Estribo | VIGA BALDRAME | 0.5 | 0.000019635
4 x P168 - Longitudinal | VIGA BALDRAME | 1 | 0.0000785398
3 x P17 - Estribo | VIGA BALDRAME | 0.5 | 0.000019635
4 x P17 - Longitudinal | VIGA BALDRAME | 1 | 0.0000785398
3 x P19 - Estribo | VIGA BALDRAME | 0.5 | 0.000019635
4 x P19 - Longitudinal | VIGA BALDRAME | 1 | 0.0000785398
3 x P20 - Estribo | VIGA BALDRAME | 0.5 | 0.000019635
4 x P20 - Longitudinal | VIGA BALDRAME | 1 | 0.0000785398
3 x P22 - Estribo | VIGA BALDRAME | 0.5 | 0.000019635
4 x P22 - Longitudinal | VIGA BALDRAME | 1 | 0.0000785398
3 x P23 - Estribo | VIGA BALDRAME | 0.5 | 0.000019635
4 x P23 - Longitudinal | VIGA BALDRAME | 1.25 | 0.000122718
2 x P23 - Longitudinal | VIGA BALDRAME | 1 | 0.0000785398
3 x P24 - Estribo | VIGA BALDRAME | 0.5 | 0.000019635
4 x P24 - Longitudinal | VIGA BALDRAME | 1 | 0.0000785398
3 x P25 - Estribo | VIGA BALDRAME | 0.5 | 0.000019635
4 x P25 - Longitudinal | VIGA BALDRAME | 1 | 0.0000785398
3 x P26 - Estribo | VIGA BALDRAME | 0.5 | 0.000019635
8 x P26 - Longitudinal | VIGA BALDRAME | 1 | 0.0000785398
3 x P27 - Estribo | VIGA BALDRAME | 0.5 | 0.000019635
4 x P27 - Longitudinal | VIGA BALDRAME | 1 | 0.0000785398
3 x P28 - Estribo | VIGA BALDRAME | 0.5 | 0.000019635
4 x P28 - Longitudinal | VIGA BALDRAME | 1.25 | 0.000122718
2 x P28 - Longitudinal | VIGA BALDRAME | 1 | 0.0000785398
3 x P30 - Estribo | VIGA BALDRAME | 0.5 | 0.000019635
4 x P30 - Longitudinal | VIGA BALDRAME | 1 | 0.0000785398
3 x P32 - Estribo | VIGA BALDRAME | 0.5 | 0.000019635
4 x P32 - Longitudinal | VIGA BALDRAME | 1 | 0.0000785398
3 x P33 - Estribo | VIGA BALDRAME | 0.5 | 0.000019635
4 x P33 - Longitudinal | VIGA BALDRAME | 1 | 0.0000785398
3 x P34 - Estribo | VIGA BALDRAME | 0.5 | 0.000019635
4 x P34 - Longitudinal | VIGA BALDRAME | 1 | 0.0000785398
3 x P36 - Estribo | VIGA BALDRAME | 0.5 | 0.000019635
4 x P36 - Longitudinal | VIGA BALDRAME | 1 | 0.0000785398
3 x P38 - Estribo | VIGA BALDRAME | 0.5 | 0.000019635
4 x P38 - Longitudinal | VIGA BALDRAME | 1 | 0.0000785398
3 x P39 - Estribo | VIGA BALDRAME | 0.5 | 0.000019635
4 x P39 - Longitudinal | VIGA BALDRAME | 1 | 0.0000785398
3 x P40 - Estribo | VIGA BALDRAME | 0.5 | 0.000019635
4 x P40 - Longitudinal | VIGA BALDRAME | 1 | 0.0000785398
3 x P41 - Estribo | VIGA BALDRAME | 0.5 | 0.000019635
4 x P41 - Longitudinal | VIGA BALDRAME | 1 | 0.0000785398
3 x P42 - Estribo | VIGA BALDRAME | 0.5 | 0.000019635
3 x P42 - Grampo | VIGA BALDRAME | 0.5 | 0.000019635
6 x P42 - Longitudinal | VIGA BALDRAME | 1 | 0.0000785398
3 x P43 - Estribo | VIGA BALDRAME | 0.5 | 0.000019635
4 x P43 - Longitudinal | VIGA BALDRAME | 1 | 0.0000785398
3 x P44 - Estribo | VIGA BALDRAME | 0.5 | 0.000019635
4 x P44 - Longitudinal | VIGA BALDRAME | 1 | 0.0000785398
3 x P45 - Estribo | VIGA BALDRAME | 0.5 | 0.000019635
3 x P45 - Grampo | VIGA BALDRAME | 0.5 | 0.000019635
6 x P45 - Longitudinal | VIGA BALDRAME | 1 | 0.0000785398
3 x P47 - Estribo | VIGA BALDRAME | 0.5 | 0.000019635
3 x P47 - Grampo | VIGA BALDRAME | 0.5 | 0.000019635
6 x P47 - Longitudinal | VIGA BALDRAME | 1 | 0.0000785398
3 x P49 - Estribo | VIGA BALDRAME | 0.5 | 0.000019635
4 x P49 - Longitudinal | VIGA BALDRAME | 1 | 0.0000785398
3 x P50 - Estribo | VIGA BALDRAME | 0.5 | 0.000019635
4 x P50 - Longitudinal | VIGA BALDRAME | 1 | 0.0000785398
3 x P51 - Estribo | VIGA BALDRAME | 0.5 | 0.000019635
4 x P51 - Longitudinal | VIGA BALDRAME | 1 | 0.0000785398
3 x P52 - Estribo | VIGA BALDRAME | 0.5 | 0.000019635
4 x P52 - Longitudinal | VIGA BALDRAME | 1 | 0.0000785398
3 x P53 - Estribo | VIGA BALDRAME | 0.5 | 0.000019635
4 x P53 - Longitudinal | VIGA BALDRAME | 1 | 0.0000785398
3 x P54 - Estribo | VIGA BALDRAME | 0.5 | 0.000019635
4 x P54 - Longitudinal | VIGA BALDRAME | 1 | 0.0000785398
3 x P55 - Estribo | VIGA BALDRAME | 0.5 | 0.000019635
4 x P55 - Longitudinal | VIGA BALDRAME | 1 | 0.0000785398
3 x P56 - Estribo | VIGA BALDRAME | 0.5 | 0.000019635
4 x P56 - Longitudinal | VIGA BALDRAME | 1 | 0.0000785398
3 x P57 - Estribo | VIGA BALDRAME | 0.5 | 0.000019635
4 x P57 - Longitudinal | VIGA BALDRAME | 1 | 0.0000785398
3 x P58 - Estribo | VIGA BALDRAME | 0.5 | 0.000019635
3 x P58 - Grampo | VIGA BALDRAME | 0.5 | 0.000019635
6 x P58 - Longitudinal | VIGA BALDRAME | 1 | 0.0000785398
3 x P60 - Estribo | VIGA BALDRAME | 0.5 | 0.000019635
4 x P60 - Longitudinal | VIGA BALDRAME | 1 | 0.0000785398
3 x P62 - Estribo | VIGA BALDRAME | 0.5 | 0.000019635
4 x P62 - Longitudinal | VIGA BALDRAME | 1 | 0.0000785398
3 x P63 - Estribo | VIGA BALDRAME | 0.5 | 0.000019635
6 x P63 - Longitudinal | VIGA BALDRAME | 1 | 0.0000785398
3 x P65 - Estribo | VIGA BALDRAME | 0.5 | 0.000019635
3 x P65 - Grampo | VIGA BALDRAME | 0.5 | 0.000019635
6 x P65 - Longitudinal | VIGA BALDRAME | 1 | 0.0000785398
3 x P66 - Estribo | VIGA BALDRAME | 0.5 | 0.000019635
4 x P66 - Longitudinal | VIGA BALDRAME | 1 | 0.0000785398
3 x P69 - Estribo | VIGA BALDRAME | 0.5 | 0.000019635
8 x P69 - Longitudinal | VIGA BALDRAME | 1 | 0.0000785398
3 x P71 - Estribo | VIGA BALDRAME | 0.5 | 0.000019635
4 x P71 - Longitudinal | VIGA BALDRAME | 1 | 0.0000785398
3 x P72 - Estribo | VIGA BALDRAME | 0.5 | 0.000019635
4 x P72 - Longitudinal | VIGA BALDRAME | 1 | 0.0000785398
3 x P73 - Estribo | VIGA BALDRAME | 0.5 | 0.000019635
3 x P73 - Grampo | VIGA BALDRAME | 0.5 | 0.000019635
6 x P73 - Longitudinal | VIGA BALDRAME | 1 | 0.0000785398
3 x P74 - Estribo | VIGA BALDRAME | 0.5 | 0.000019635
4 x P74 - Longitudinal | VIGA BALDRAME | 1 | 0.0000785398
3 x P79 - Estribo | VIGA BALDRAME | 0.5 | 0.000019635
4 x P79 - Longitudinal | VIGA BALDRAME | 1 | 0.0000785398
3 x P80 - Estribo | VIGA BALDRAME | 0.5 | 0.000019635
4 x P80 - Longitudinal | VIGA BALDRAME | 1 | 0.0000785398
3 x P87 - Estribo | VIGA BALDRAME | 0.5 | 0.000019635
4 x P87 - Longitudinal | VIGA BALDRAME | 1 | 0.0000785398
3 x P90 - Estribo | VIGA BALDRAME | 0.5 | 0.000019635
4 x P90 - Longitudinal | VIGA BALDRAME | 1 | 0.0000785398
3 x P91 - Estribo | VIGA BALDRAME | 0.5 | 0.000019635
4 x P91 - Longitudinal | VIGA BALDRAME | 1 | 0.0000785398
3 x P92 - Estribo | VIGA BALDRAME | 0.5 | 0.000019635
4 x P92 - Longitudinal | VIGA BALDRAME | 1 | 0.0000785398
3 x P94 - Estribo | VIGA BALDRAME | 0.5 | 0.000019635
3 x P94 - Grampo | VIGA BALDRAME | 0.5 | 0.000019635
6 x P94 - Longitudinal | VIGA BALDRAME | 1 | 0.0000785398
3 x P95 - Estribo | VIGA BALDRAME | 0.5 | 0.000019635
4 x P95 - Longitudinal | VIGA BALDRAME | 1 | 0.0000785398
3 x P96 - Estribo | VIGA BALDRAME | 0.5 | 0.000019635
4 x P96 - Longitudinal | VIGA BALDRAME | 1 | 0.0000785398
3 x P97 - Estribo | VIGA BALDRAME | 0.5 | 0.000019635
4 x P97 - Longitudinal | VIGA BALDRAME | 1 | 0.0000785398
3 x P98 - Estribo | VIGA BALDRAME | 0.5 | 0.000019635
4 x P98 - Longitudinal | VIGA BALDRAME | 1 | 0.0000785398
3 x P99 - Estribo | VIGA BALDRAME | 0.5 | 0.000019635
4 x P99 - Longitudinal | VIGA BALDRAME | 1 | 0.0000785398
3 x PM1 - Estribo | VIGA BALDRAME | 0.5 | 0.000019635
4 x PM1 - Longitudinal | VIGA BALDRAME | 1 | 0.0000785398
3 x PM2 - Estribo | VIGA BALDRAME | 0.5 | 0.000019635
4 x PM2 - Longitudinal | VIGA BALDRAME | 1 | 0.0000785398
188 x V101 - Estribo | VIGA BALDRAME | 0.5 | 0.000019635
10 x V101 - Longitudinal inferior | VIGA BALDRAME | 0.8 | 0.0000502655
8 x V101 - Longitudinal superior | VIGA BALDRAME | 0.8 | 0.0000502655
40 x V102 - Estribo | VIGA BALDRAME | 0.5 | 0.000019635
4 x V102 - Grampo | VIGA BALDRAME | 0.5 | 0.000019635
2 x V102 - Longitudinal inferior | VIGA BALDRAME | 0.8 | 0.0000502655
2 x V102 - Longitudinal superior | VIGA BALDRAME | 1 | 0.0000785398
40 x V103 - Estribo | VIGA BALDRAME | 0.5 | 0.000019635
2 x V103 - Longitudinal inferior | VIGA BALDRAME | 1 | 0.0000785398
2 x V103 - Longitudinal superior | VIGA BALDRAME | 1 | 0.0000785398
18 x V104 - Estribo | VIGA BALDRAME | 0.5 | 0.000019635
4 x V104 - Grampo | VIGA BALDRAME | 0.5 | 0.000019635
2 x V104 - Longitudinal inferior | VIGA BALDRAME | 0.8 | 0.0000502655
2 x V104 - Longitudinal superior | VIGA BALDRAME | 1 | 0.0000785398
16 x V105 - Estribo | VIGA BALDRAME | 0.5 | 0.000019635
2 x V105 - Longitudinal inferior | VIGA BALDRAME | 0.8 | 0.0000502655
2 x V105 - Longitudinal superior | VIGA BALDRAME | 0.8 | 0.0000502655
16 x V106 - Estribo | VIGA BALDRAME | 0.5 | 0.000019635
2 x V106 - Longitudinal inferior | VIGA BALDRAME | 0.8 | 0.0000502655
2 x V106 - Longitudinal superior | VIGA BALDRAME | 1 | 0.0000785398
18 x V107 - Estribo | VIGA BALDRAME | 0.5 | 0.000019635
4 x V107 - Grampo | VIGA BALDRAME | 0.5 | 0.000019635
2 x V107 - Longitudinal inferior | VIGA BALDRAME | 0.8 | 0.0000502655
2 x V107 - Longitudinal superior | VIGA BALDRAME | 1 | 0.0000785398
17 x V108 - Estribo | VIGA BALDRAME | 0.5 | 0.000019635
2 x V108 - Longitudinal inferior | VIGA BALDRAME | 0.8 | 0.0000502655
2 x V108 - Longitudinal superior | VIGA BALDRAME | 0.8 | 0.0000502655
16 x V109 - Estribo | VIGA BALDRAME | 0.5 | 0.000019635
2 x V109 - Longitudinal inferior | VIGA BALDRAME | 0.8 | 0.0000502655
2 x V109 - Longitudinal superior | VIGA BALDRAME | 1.25 | 0.000122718
82 x V110 - Estribo | VIGA BALDRAME | 0.5 | 0.000019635
8 x V110 - Grampo | VIGA BALDRAME | 0.5 | 0.000019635
2 x V110 - Longitudinal inferior | VIGA BALDRAME | 1.6 | 0.000201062
4 x V110 - Longitudinal inferior | VIGA BALDRAME | 0.8 | 0.0000502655
2 x V110 - Longitudinal inferior | VIGA BALDRAME | 1.25 | 0.000122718
6 x V110 - Longitudinal superior | VIGA BALDRAME | 1.25 | 0.000122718
86 x V111 - Estribo | VIGA BALDRAME | 0.5 | 0.000019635
8 x V111 - Grampo | VIGA BALDRAME | 0.5 | 0.000019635
2 x V111 - Longitudinal inferior | VIGA BALDRAME | 1.25 | 0.000122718
2 x V111 - Longitudinal inferior | VIGA BALDRAME | 0.8 | 0.0000502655
2 x V111 - Longitudinal inferior | VIGA BALDRAME | 1.6 | 0.000201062
7 x V111 - Longitudinal superior | VIGA BALDRAME | 1.25 | 0.000122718
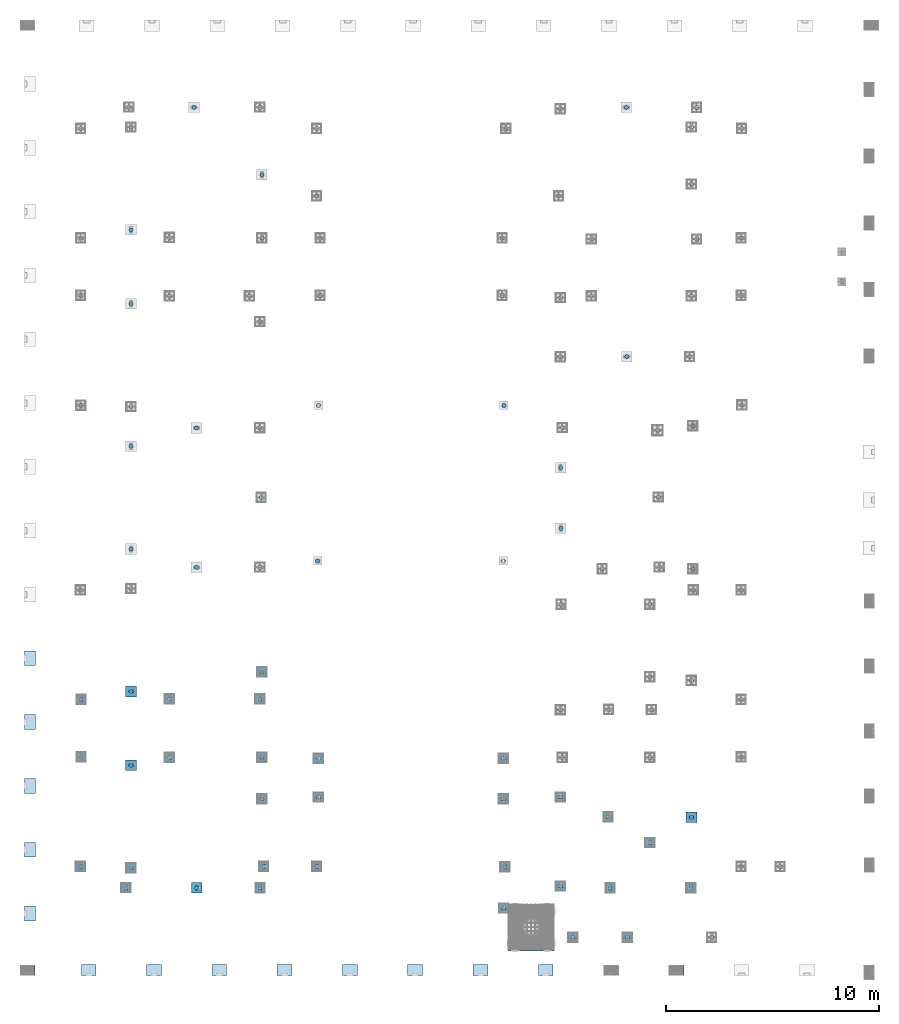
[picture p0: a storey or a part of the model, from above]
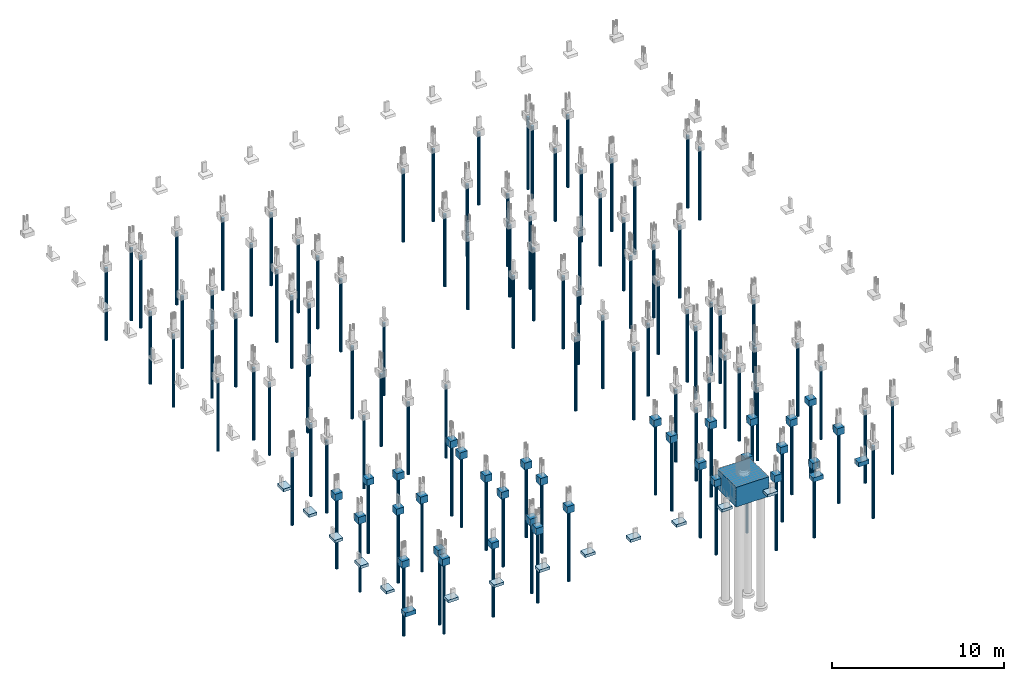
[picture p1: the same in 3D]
Properties of the parts of a building model (IFC4), part 8 of 9

# IfcReinforcingBar (17755)
Name | In | NominalDiameter (cm) | CrossSectionArea (m2)
6 x V112 - Estribo | VIGA BALDRAME | 0.5 | 0.000019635
2 x V112 - Longitudinal inferior | VIGA BALDRAME | 0.8 | 0.0000502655
2 x V112 - Longitudinal superior | VIGA BALDRAME | 0.8 | 0.0000502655
81 x V113 - Estribo | VIGA BALDRAME | 0.5 | 0.000019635
8 x V113 - Grampo | VIGA BALDRAME | 0.5 | 0.000019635
2 x V113 - Longitudinal inferior | VIGA BALDRAME | 0.8 | 0.0000502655
2 x V113 - Longitudinal inferior | VIGA BALDRAME | 1 | 0.0000785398
5 x V113 - Longitudinal superior | VIGA BALDRAME | 1 | 0.0000785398
92 x V114 - Estribo | VIGA BALDRAME | 0.5 | 0.000019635
8 x V114 - Grampo | VIGA BALDRAME | 0.5 | 0.000019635
5 x V114 - Longitudinal inferior | VIGA BALDRAME | 1.25 | 0.000122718
6 x V114 - Longitudinal superior | VIGA BALDRAME | 1 | 0.0000785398
7 x V115 - Estribo | VIGA BALDRAME | 0.5 | 0.000019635
2 x V115 - Longitudinal inferior | VIGA BALDRAME | 1 | 0.0000785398
2 x V115 - Longitudinal superior | VIGA BALDRAME | 1 | 0.0000785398
37 x V116 - Estribo | VIGA BALDRAME | 0.5 | 0.000019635
2 x V116 - Longitudinal inferior | VIGA BALDRAME | 1 | 0.0000785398
3 x V116 - Longitudinal superior | VIGA BALDRAME | 0.8 | 0.0000502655
18 x V117 - Estribo | VIGA BALDRAME | 0.5 | 0.000019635
2 x V117 - Longitudinal inferior | VIGA BALDRAME | 0.8 | 0.0000502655
2 x V117 - Longitudinal superior | VIGA BALDRAME | 0.8 | 0.0000502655
17 x V118 - Estribo | VIGA BALDRAME | 0.5 | 0.000019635
4 x V118 - Grampo | VIGA BALDRAME | 0.5 | 0.000019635
2 x V118 - Longitudinal inferior | VIGA BALDRAME | 0.8 | 0.0000502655
2 x V118 - Longitudinal superior | VIGA BALDRAME | 1 | 0.0000785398
3 x V119 - Estribo | VIGA BALDRAME | 0.5 | 0.000019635
2 x V119 - Longitudinal inferior | VIGA BALDRAME | 0.8 | 0.0000502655
2 x V119 - Longitudinal superior | VIGA BALDRAME | 0.8 | 0.0000502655
37 x V120 - Estribo | VIGA BALDRAME | 0.5 | 0.000019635
2 x V120 - Longitudinal inferior | VIGA BALDRAME | 1 | 0.0000785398
2 x V120 - Longitudinal superior | VIGA BALDRAME | 1 | 0.0000785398
2 x V121 - Estribo | VIGA BALDRAME | 0.5 | 0.000019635
2 x V121 - Longitudinal inferior | VIGA BALDRAME | 0.8 | 0.0000502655
2 x V121 - Longitudinal superior | VIGA BALDRAME | 0.8 | 0.0000502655
29 x V122 - Estribo | VIGA BALDRAME | 0.5 | 0.000019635
2 x V122 - Longitudinal inferior | VIGA BALDRAME | 1.25 | 0.000122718
2 x V122 - Longitudinal superior | VIGA BALDRAME | 1.25 | 0.000122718
8 x V123 - Estribo | VIGA BALDRAME | 0.5 | 0.000019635
2 x V123 - Longitudinal inferior | VIGA BALDRAME | 0.8 | 0.0000502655
2 x V123 - Longitudinal superior | VIGA BALDRAME | 0.8 | 0.0000502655
2 x V124 - Estribo | VIGA BALDRAME | 0.5 | 0.000019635
2 x V124 - Longitudinal inferior | VIGA BALDRAME | 0.8 | 0.0000502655
2 x V124 - Longitudinal superior | VIGA BALDRAME | 0.8 | 0.0000502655
37 x V125 - Estribo | VIGA BALDRAME | 0.5 | 0.000019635
2 x V125 - Longitudinal inferior | VIGA BALDRAME | 1 | 0.0000785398
2 x V125 - Longitudinal superior | VIGA BALDRAME | 1 | 0.0000785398
5 x V126 - Estribo | VIGA BALDRAME | 0.5 | 0.000019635
4 x V126 - Grampo | VIGA BALDRAME | 0.5 | 0.000019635
2 x V126 - Longitudinal inferior | VIGA BALDRAME | 0.8 | 0.0000502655
2 x V126 - Longitudinal superior | VIGA BALDRAME | 1 | 0.0000785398
11 x V127 - Estribo | VIGA BALDRAME | 0.5 | 0.000019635
2 x V127 - Longitudinal inferior | VIGA BALDRAME | 0.8 | 0.0000502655
2 x V127 - Longitudinal superior | VIGA BALDRAME | 0.8 | 0.0000502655
14 x V128 - Estribo | VIGA BALDRAME | 0.5 | 0.000019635
2 x V128 - Longitudinal inferior | VIGA BALDRAME | 0.8 | 0.0000502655
2 x V128 - Longitudinal superior | VIGA BALDRAME | 0.8 | 0.0000502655
3 x V129 - Estribo | VIGA BALDRAME | 0.5 | 0.000019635
2 x V129 - Longitudinal inferior | VIGA BALDRAME | 0.8 | 0.0000502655
2 x V129 - Longitudinal superior | VIGA BALDRAME | 0.8 | 0.0000502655
18 x V130 - Estribo | VIGA BALDRAME | 0.5 | 0.000019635
4 x V130 - Grampo | VIGA BALDRAME | 0.5 | 0.000019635
2 x V130 - Longitudinal inferior | VIGA BALDRAME | 1 | 0.0000785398
2 x V130 - Longitudinal superior | VIGA BALDRAME | 1 | 0.0000785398
18 x V131 - Estribo | VIGA BALDRAME | 0.5 | 0.000019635
2 x V131 - Longitudinal inferior | VIGA BALDRAME | 0.8 | 0.0000502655
2 x V131 - Longitudinal superior | VIGA BALDRAME | 0.8 | 0.0000502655
3 x V132 - Estribo | VIGA BALDRAME | 0.5 | 0.000019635
2 x V132 - Longitudinal inferior | VIGA BALDRAME | 0.8 | 0.0000502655
2 x V132 - Longitudinal superior | VIGA BALDRAME | 0.8 | 0.0000502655
34 x V133 - Estribo | VIGA BALDRAME | 0.5 | 0.000019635
2 x V133 - Longitudinal inferior | VIGA BALDRAME | 1.25 | 0.000122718
2 x V133 - Longitudinal superior | VIGA BALDRAME | 1.25 | 0.000122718
4 x V134 - Estribo | VIGA BALDRAME | 0.5 | 0.000019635
2 x V134 - Longitudinal inferior | VIGA BALDRAME | 0.8 | 0.0000502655
2 x V134 - Longitudinal superior | VIGA BALDRAME | 0.8 | 0.0000502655
13 x V135 - Estribo | VIGA BALDRAME | 0.5 | 0.000019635
V135 - Grampo | VIGA BALDRAME | 0.5 | 0.000019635
2 x V135 - Longitudinal inferior | VIGA BALDRAME | 0.8 | 0.0000502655
2 x V135 - Longitudinal superior | VIGA BALDRAME | 0.8 | 0.0000502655
56 x V136 - Estribo | VIGA BALDRAME | 0.5 | 0.000019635
4 x V136 - Grampo | VIGA BALDRAME | 0.5 | 0.000019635
3 x V136 - Longitudinal inferior | VIGA BALDRAME | 1.25 | 0.000122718
2 x V136 - Longitudinal superior | VIGA BALDRAME | 1.25 | 0.000122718
14 x V137 - Estribo | VIGA BALDRAME | 0.5 | 0.000019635
2 x V137 - Longitudinal inferior | VIGA BALDRAME | 0.8 | 0.0000502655
2 x V137 - Longitudinal superior | VIGA BALDRAME | 0.8 | 0.0000502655
12 x V138 - Estribo | VIGA BALDRAME | 0.5 | 0.000019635
2 x V138 - Longitudinal inferior | VIGA BALDRAME | 0.8 | 0.0000502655
2 x V138 - Longitudinal superior | VIGA BALDRAME | 1.25 | 0.000122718
7 x V139 - Estribo | VIGA BALDRAME | 0.5 | 0.000019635
4 x V139 - Grampo | VIGA BALDRAME | 0.5 | 0.000019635
2 x V139 - Longitudinal inferior | VIGA BALDRAME | 1 | 0.0000785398
2 x V139 - Longitudinal superior | VIGA BALDRAME | 1 | 0.0000785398
55 x V140 - Estribo | VIGA BALDRAME | 0.5 | 0.000019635
4 x V140 - Grampo | VIGA BALDRAME | 0.5 | 0.000019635
3 x V140 - Longitudinal inferior | VIGA BALDRAME | 1.25 | 0.000122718
3 x V140 - Longitudinal superior | VIGA BALDRAME | 1.25 | 0.000122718
3 x V141 - Estribo | VIGA BALDRAME | 0.5 | 0.000019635
2 x V141 - Longitudinal inferior | VIGA BALDRAME | 0.8 | 0.0000502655
2 x V141 - Longitudinal superior | VIGA BALDRAME | 0.8 | 0.0000502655
21 x V142 - Estribo | VIGA BALDRAME | 0.5 | 0.000019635
V142 - Grampo | VIGA BALDRAME | 0.5 | 0.000019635
2 x V142 - Longitudinal inferior | VIGA BALDRAME | 0.8 | 0.0000502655
2 x V142 - Longitudinal superior | VIGA BALDRAME | 1 | 0.0000785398
47 x V143 - Estribo | VIGA BALDRAME | 0.5 | 0.000019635
2 x V143 - Longitudinal inferior | VIGA BALDRAME | 1.25 | 0.000122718
4 x V143 - Longitudinal superior | VIGA BALDRAME | 1.25 | 0.000122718
6 x V144 - Estribo | VIGA BALDRAME | 0.5 | 0.000019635
4 x V144 - Grampo | VIGA BALDRAME | 0.5 | 0.000019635
2 x V144 - Longitudinal inferior | VIGA BALDRAME | 0.8 | 0.0000502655
2 x V144 - Longitudinal superior | VIGA BALDRAME | 1 | 0.0000785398
16 x V145 - Estribo | VIGA BALDRAME | 0.5 | 0.000019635
2 x V145 - Longitudinal inferior | VIGA BALDRAME | 0.8 | 0.0000502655
2 x V145 - Longitudinal superior | VIGA BALDRAME | 0.8 | 0.0000502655
16 x V146 - Estribo | VIGA BALDRAME | 0.5 | 0.000019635
2 x V146 - Longitudinal inferior | VIGA BALDRAME | 0.8 | 0.0000502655
2 x V146 - Longitudinal superior | VIGA BALDRAME | 0.8 | 0.0000502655
13 x V147 - Estribo | VIGA BALDRAME | 0.5 | 0.000019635
2 x V147 - Longitudinal inferior | VIGA BALDRAME | 0.8 | 0.0000502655
2 x V147 - Longitudinal superior | VIGA BALDRAME | 0.8 | 0.0000502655
22 x V148 - Estribo | VIGA BALDRAME | 0.5 | 0.000019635
2 x V148 - Longitudinal inferior | VIGA BALDRAME | 0.8 | 0.0000502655
2 x V148 - Longitudinal superior | VIGA BALDRAME | 1 | 0.0000785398
17 x V149 - Estribo | VIGA BALDRAME | 0.5 | 0.000019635
4 x V149 - Grampo | VIGA BALDRAME | 0.5 | 0.000019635
2 x V149 - Longitudinal inferior | VIGA BALDRAME | 0.8 | 0.0000502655
2 x V149 - Longitudinal superior | VIGA BALDRAME | 1 | 0.0000785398
17 x V150 - Estribo | VIGA BALDRAME | 0.5 | 0.000019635
2 x V150 - Longitudinal inferior | VIGA BALDRAME | 0.8 | 0.0000502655
2 x V150 - Longitudinal superior | VIGA BALDRAME | 0.8 | 0.0000502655
16 x V151 - Estribo | VIGA BALDRAME | 0.5 | 0.000019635
2 x V151 - Longitudinal inferior | VIGA BALDRAME | 0.8 | 0.0000502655
2 x V151 - Longitudinal superior | VIGA BALDRAME | 1 | 0.0000785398
16 x V152 - Estribo | VIGA BALDRAME | 0.5 | 0.000019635
2 x V152 - Longitudinal inferior | VIGA BALDRAME | 0.8 | 0.0000502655
2 x V152 - Longitudinal superior | VIGA BALDRAME | 1.25 | 0.000122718
27 x V153 - Estribo | VIGA BALDRAME | 0.5 | 0.000019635
V153 - Grampo | VIGA BALDRAME | 0.5 | 0.000019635
2 x V153 - Longitudinal inferior | VIGA BALDRAME | 1 | 0.0000785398
2 x V153 - Longitudinal superior | VIGA BALDRAME | 1 | 0.0000785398
40 x V154 - Estribo | VIGA BALDRAME | 0.5 | 0.000019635
2 x V154 - Longitudinal inferior | VIGA BALDRAME | 1 | 0.0000785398
3 x V154 - Longitudinal superior | VIGA BALDRAME | 0.8 | 0.0000502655
41 x V155 - Estribo | VIGA BALDRAME | 0.5 | 0.000019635
7 x V155 - Grampo | VIGA BALDRAME | 0.5 | 0.000019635
2 x V155 - Longitudinal inferior | VIGA BALDRAME | 1.25 | 0.000122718
3 x V155 - Longitudinal superior | VIGA BALDRAME | 1.25 | 0.000122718
8 x V156 - Estribo | VIGA BALDRAME | 0.5 | 0.000019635
2 x V156 - Longitudinal inferior | VIGA BALDRAME | 1 | 0.0000785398
2 x V156 - Longitudinal superior | VIGA BALDRAME | 1 | 0.0000785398
11 x V157 - Estribo | VIGA BALDRAME | 0.5 | 0.000019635
2 x V157 - Longitudinal inferior | VIGA BALDRAME | 0.8 | 0.0000502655
2 x V157 - Longitudinal superior | VIGA BALDRAME | 0.8 | 0.0000502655
184 x V158 - Estribo | VIGA BALDRAME | 0.5 | 0.000019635
10 x V158 - Longitudinal inferior | VIGA BALDRAME | 0.8 | 0.0000502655
2 x V158 - Longitudinal inferior | VIGA BALDRAME | 1 | 0.0000785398
8 x V158 - Longitudinal superior | VIGA BALDRAME | 0.8 | 0.0000502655
243 x V159 - Estribo | VIGA BALDRAME | 0.5 | 0.000019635
12 x V159 - Longitudinal inferior | VIGA BALDRAME | 0.8 | 0.0000502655
8 x V159 - Longitudinal superior | VIGA BALDRAME | 0.8 | 0.0000502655
32 x V160 - Estribo | VIGA BALDRAME | 0.5 | 0.000019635
3 x V160 - Longitudinal inferior | VIGA BALDRAME | 1.25 | 0.000122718
2 x V160 - Longitudinal superior | VIGA BALDRAME | 1.25 | 0.000122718
15 x V161 - Estribo | VIGA BALDRAME | 0.5 | 0.000019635
2 x V161 - Longitudinal inferior | VIGA BALDRAME | 0.8 | 0.0000502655
2 x V161 - Longitudinal superior | VIGA BALDRAME | 0.8 | 0.0000502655
32 x V162 - Estribo | VIGA BALDRAME | 0.5 | 0.000019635
3 x V162 - Longitudinal inferior | VIGA BALDRAME | 1.25 | 0.000122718
2 x V162 - Longitudinal superior | VIGA BALDRAME | 1.25 | 0.000122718
32 x V163 - Estribo | VIGA BALDRAME | 0.5 | 0.000019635
3 x V163 - Longitudinal inferior | VIGA BALDRAME | 1.25 | 0.000122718
2 x V163 - Longitudinal superior | VIGA BALDRAME | 1.25 | 0.000122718
21 x V164 - Estribo | VIGA BALDRAME | 0.5 | 0.000019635
2 x V164 - Longitudinal inferior | VIGA BALDRAME | 1 | 0.0000785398
2 x V164 - Longitudinal superior | VIGA BALDRAME | 0.8 | 0.0000502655
32 x V165 - Estribo | VIGA BALDRAME | 0.5 | 0.000019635
3 x V165 - Longitudinal inferior | VIGA BALDRAME | 1.25 | 0.000122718
3 x V165 - Longitudinal superior | VIGA BALDRAME | 1.25 | 0.000122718
38 x V166 - Estribo | VIGA BALDRAME | 0.5 | 0.000019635
2 x V166 - Longitudinal inferior | VIGA BALDRAME | 1.25 | 0.000122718
2 x V166 - Longitudinal superior | VIGA BALDRAME | 1.25 | 0.000122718
5 x V167 - Estribo | VIGA BALDRAME | 0.5 | 0.000019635
2 x V167 - Longitudinal inferior | VIGA BALDRAME | 0.8 | 0.0000502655
2 x V167 - Longitudinal superior | VIGA BALDRAME | 0.8 | 0.0000502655
15 x V168 - Estribo | VIGA BALDRAME | 0.5 | 0.000019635
2 x V168 - Longitudinal construtiva | VIGA BALDRAME | 0.5 | 0.000019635
2 x V168 - Longitudinal inferior | VIGA BALDRAME | 1 | 0.0000785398
3 x V169 - Estribo | VIGA BALDRAME | 0.5 | 0.000019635
2 x V169 - Longitudinal inferior | VIGA BALDRAME | 0.8 | 0.0000502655
2 x V169 - Longitudinal superior | VIGA BALDRAME | 0.8 | 0.0000502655
3 x V170 - Estribo | VIGA BALDRAME | 0.5 | 0.000019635
2 x V170 - Longitudinal inferior | VIGA BALDRAME | 0.8 | 0.0000502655
2 x V170 - Longitudinal superior | VIGA BALDRAME | 0.8 | 0.0000502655
115 x V171 - Estribo | VIGA BALDRAME | 0.5 | 0.000019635
6 x V171 - Longitudinal inferior | VIGA BALDRAME | 1.25 | 0.000122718
4 x V171 - Longitudinal superior | VIGA BALDRAME | 1.25 | 0.000122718
15 x V172 - Estribo | VIGA BALDRAME | 0.5 | 0.000019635
2 x V172 - Longitudinal construtiva | VIGA BALDRAME | 0.5 | 0.000019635
2 x V172 - Longitudinal inferior | VIGA BALDRAME | 1 | 0.0000785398
38 x V173 - Estribo | VIGA BALDRAME | 0.5 | 0.000019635
2 x V173 - Longitudinal inferior | VIGA BALDRAME | 1.25 | 0.000122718
2 x V173 - Longitudinal superior | VIGA BALDRAME | 1.25 | 0.000122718
4 x V174 - Estribo | VIGA BALDRAME | 0.5 | 0.000019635
2 x V174 - Longitudinal inferior | VIGA BALDRAME | 0.8 | 0.0000502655
2 x V174 - Longitudinal superior | VIGA BALDRAME | 0.8 | 0.0000502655
17 x V175 - Estribo | VIGA BALDRAME | 0.5 | 0.000019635
2 x V175 - Longitudinal inferior | VIGA BALDRAME | 1 | 0.0000785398
2 x V175 - Longitudinal superior | VIGA BALDRAME | 0.8 | 0.0000502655
17 x V176 - Estribo | VIGA BALDRAME | 0.5 | 0.000019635
2 x V176 - Longitudinal inferior | VIGA BALDRAME | 1 | 0.0000785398
2 x V176 - Longitudinal superior | VIGA BALDRAME | 0.8 | 0.0000502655
3 x V177 - Estribo | VIGA BALDRAME | 0.5 | 0.000019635
2 x V177 - Longitudinal inferior | VIGA BALDRAME | 0.8 | 0.0000502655
2 x V177 - Longitudinal superior | VIGA BALDRAME | 0.8 | 0.0000502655
15 x V178 - Estribo | VIGA BALDRAME | 0.5 | 0.000019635
2 x V178 - Longitudinal construtiva | VIGA BALDRAME | 0.5 | 0.000019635
2 x V178 - Longitudinal inferior | VIGA BALDRAME | 1 | 0.0000785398
15 x V179 - Estribo | VIGA BALDRAME | 0.5 | 0.000019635
2 x V179 - Longitudinal construtiva | VIGA BALDRAME | 0.5 | 0.000019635
2 x V179 - Longitudinal inferior | VIGA BALDRAME | 1 | 0.0000785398
7 x V180 - Estribo | VIGA BALDRAME | 0.5 | 0.000019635
2 x V180 - Longitudinal inferior | VIGA BALDRAME | 0.8 | 0.0000502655
2 x V180 - Longitudinal superior | VIGA BALDRAME | 0.8 | 0.0000502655
7 x V181 - Estribo | VIGA BALDRAME | 0.5 | 0.000019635
2 x V181 - Longitudinal inferior | VIGA BALDRAME | 0.8 | 0.0000502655
2 x V181 - Longitudinal superior | VIGA BALDRAME | 0.8 | 0.0000502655
54 x V182 - Estribo | VIGA BALDRAME | 0.5 | 0.000019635
2 x V182 - Longitudinal inferior | VIGA BALDRAME | 1 | 0.0000785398
2 x V182 - Longitudinal superior | VIGA BALDRAME | 0.8 | 0.0000502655
121 x V183 - Estribo | VIGA BALDRAME | 0.5 | 0.000019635
3 x V183 - Grampo | VIGA BALDRAME | 0.5 | 0.000019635
5 x V183 - Longitudinal inferior | VIGA BALDRAME | 1.25 | 0.000122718
5 x V183 - Longitudinal superior | VIGA BALDRAME | 1.25 | 0.000122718
3 x V184 - Estribo | VIGA BALDRAME | 0.5 | 0.000019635
2 x V184 - Longitudinal inferior | VIGA BALDRAME | 0.8 | 0.0000502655
2 x V184 - Longitudinal superior | VIGA BALDRAME | 0.8 | 0.0000502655
54 x V185 - Estribo | VIGA BALDRAME | 0.5 | 0.000019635
2 x V185 - Grampo | VIGA BALDRAME | 0.5 | 0.000019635
2 x V185 - Longitudinal inferior | VIGA BALDRAME | 1.25 | 0.000122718
2 x V185 - Longitudinal superior | VIGA BALDRAME | 1 | 0.0000785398
15 x V187 - Estribo | VIGA BALDRAME | 0.5 | 0.000019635
2 x V187 - Longitudinal inferior | VIGA BALDRAME | 1 | 0.0000785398
2 x V187 - Longitudinal superior | VIGA BALDRAME | 0.8 | 0.0000502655
33 x V188 - Estribo | VIGA BALDRAME | 0.5 | 0.000019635
2 x V188 - Longitudinal inferior | VIGA BALDRAME | 1 | 0.0000785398
2 x V188 - Longitudinal superior | VIGA BALDRAME | 0.8 | 0.0000502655
26 x V189 - Estribo | VIGA BALDRAME | 0.5 | 0.000019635
2 x V189 - Longitudinal inferior | VIGA BALDRAME | 0.8 | 0.0000502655
2 x V189 - Longitudinal superior | VIGA BALDRAME | 0.8 | 0.0000502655
33 x V190 - Estribo | VIGA BALDRAME | 0.5 | 0.000019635
2 x V190 - Longitudinal inferior | VIGA BALDRAME | 1 | 0.0000785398
2 x V190 - Longitudinal superior | VIGA BALDRAME | 0.8 | 0.0000502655
15 x V191 - Estribo | VIGA BALDRAME | 0.5 | 0.000019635
2 x V191 - Longitudinal inferior | VIGA BALDRAME | 1 | 0.0000785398
2 x V191 - Longitudinal superior | VIGA BALDRAME | 0.8 | 0.0000502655
8 x V192 - Estribo | VIGA BALDRAME | 0.5 | 0.000019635
2 x V192 - Longitudinal construtiva | VIGA BALDRAME | 0.5 | 0.000019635
2 x V192 - Longitudinal inferior | VIGA BALDRAME | 0.8 | 0.0000502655
23 x V193 - Estribo | VIGA BALDRAME | 0.5 | 0.000019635
4 x V193 - Grampo | VIGA BALDRAME | 0.5 | 0.000019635
2 x V193 - Longitudinal inferior | VIGA BALDRAME | 1.6 | 0.000201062
2 x V193 - Longitudinal superior | VIGA BALDRAME | 1.6 | 0.000201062
2 x V194 - Estribo | VIGA BALDRAME | 0.5 | 0.000019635
4 x V194 - Grampo | VIGA BALDRAME | 0.5 | 0.000019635
2 x V194 - Longitudinal inferior | VIGA BALDRAME | 1 | 0.0000785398
2 x V194 - Longitudinal superior | VIGA BALDRAME | 1 | 0.0000785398
V195 - Estribo | VIGA BALDRAME | 0.5 | 0.000019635
V195 - Grampo | VIGA BALDRAME | 0.5 | 0.000019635
2 x V195 - Longitudinal construtiva | VIGA BALDRAME | 0.5 | 0.000019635
2 x V195 - Longitudinal inferior | VIGA BALDRAME | 0.8 | 0.0000502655
101 x V196 - Estribo | VIGA BALDRAME | 0.5 | 0.000019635
6 x V196 - Longitudinal inferior | VIGA BALDRAME | 1.25 | 0.000122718
5 x V196 - Longitudinal superior | VIGA BALDRAME | 1.25 | 0.000122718
V197 - Estribo | VIGA BALDRAME | 0.5 | 0.000019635
2 x V197 - Grampo | VIGA BALDRAME | 0.5 | 0.000019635
2 x V197 - Longitudinal construtiva | VIGA BALDRAME | 0.5 | 0.000019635
2 x V197 - Longitudinal inferior | VIGA BALDRAME | 0.8 | 0.0000502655
67 x V198 - Estribo | VIGA BALDRAME | 0.5 | 0.000019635
3 x V198 - Longitudinal inferior | VIGA BALDRAME | 0.8 | 0.0000502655
2 x V198 - Longitudinal superior | VIGA BALDRAME | 1 | 0.0000785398
37 x V199 - Estribo | VIGA BALDRAME | 0.5 | 0.000019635
2 x V199 - Longitudinal inferior | VIGA BALDRAME | 1.25 | 0.000122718
2 x V199 - Longitudinal superior | VIGA BALDRAME | 1.25 | 0.000122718
20 x V200 - Estribo | VIGA BALDRAME | 0.5 | 0.000019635
2 x V200 - Longitudinal inferior | VIGA BALDRAME | 1 | 0.0000785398
2 x V200 - Longitudinal superior | VIGA BALDRAME | 1 | 0.0000785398
8 x V201 - Estribo | VIGA BALDRAME | 0.5 | 0.000019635
2 x V201 - Longitudinal inferior | VIGA BALDRAME | 0.8 | 0.0000502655
2 x V201 - Longitudinal superior | VIGA BALDRAME | 0.8 | 0.0000502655
17 x V202 - Estribo | VIGA BALDRAME | 0.5 | 0.000019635
2 x V202 - Longitudinal inferior | VIGA BALDRAME | 0.8 | 0.0000502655
2 x V202 - Longitudinal superior | VIGA BALDRAME | 0.8 | 0.0000502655
27 x V203 - Estribo | VIGA BALDRAME | 0.5 | 0.000019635
2 x V203 - Longitudinal inferior | VIGA BALDRAME | 1.25 | 0.000122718
2 x V203 - Longitudinal superior | VIGA BALDRAME | 1 | 0.0000785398
4 x V204 - Estribo | VIGA BALDRAME | 0.5 | 0.000019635
2 x V204 - Longitudinal inferior | VIGA BALDRAME | 0.8 | 0.0000502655
2 x V204 - Longitudinal superior | VIGA BALDRAME | 0.8 | 0.0000502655
11 x V205 - Estribo | VIGA BALDRAME | 0.5 | 0.000019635
2 x V205 - Longitudinal inferior | VIGA BALDRAME | 0.8 | 0.0000502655
2 x V205 - Longitudinal superior | VIGA BALDRAME | 1 | 0.0000785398
8 x V206 - Estribo | VIGA BALDRAME | 0.5 | 0.000019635
2 x V206 - Longitudinal inferior | VIGA BALDRAME | 0.8 | 0.0000502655
2 x V206 - Longitudinal superior | VIGA BALDRAME | 0.8 | 0.0000502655
3 x V207 - Estribo | VIGA BALDRAME | 0.5 | 0.000019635
2 x V207 - Longitudinal inferior | VIGA BALDRAME | 0.8 | 0.0000502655
2 x V207 - Longitudinal superior | VIGA BALDRAME | 0.8 | 0.0000502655
3 x V208 - Estribo | VIGA BALDRAME | 0.5 | 0.000019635
2 x V208 - Longitudinal inferior | VIGA BALDRAME | 0.8 | 0.0000502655
2 x V208 - Longitudinal superior | VIGA BALDRAME | 0.8 | 0.0000502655
12 x V209 - Estribo | VIGA BALDRAME | 0.5 | 0.000019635
2 x V209 - Longitudinal inferior | VIGA BALDRAME | 0.8 | 0.0000502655
2 x V209 - Longitudinal superior | VIGA BALDRAME | 0.8 | 0.0000502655
14 x V210 - Estribo | VIGA BALDRAME | 0.5 | 0.000019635
2 x V210 - Longitudinal inferior | VIGA BALDRAME | 0.8 | 0.0000502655
2 x V210 - Longitudinal superior | VIGA BALDRAME | 0.8 | 0.0000502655
31 x V211 - Estribo | VIGA BALDRAME | 0.5 | 0.000019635
2 x V211 - Longitudinal inferior | VIGA BALDRAME | 1 | 0.0000785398
2 x V211 - Longitudinal superior | VIGA BALDRAME | 1 | 0.0000785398
39 x V212 - Estribo | VIGA BALDRAME | 0.5 | 0.000019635
2 x V212 - Longitudinal inferior | VIGA BALDRAME | 1 | 0.0000785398
2 x V212 - Longitudinal superior | VIGA BALDRAME | 1 | 0.0000785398
3 x V213 - Estribo | VIGA BALDRAME | 0.5 | 0.000019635
2 x V213 - Longitudinal inferior | VIGA BALDRAME | 0.8 | 0.0000502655
2 x V213 - Longitudinal superior | VIGA BALDRAME | 0.8 | 0.0000502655
5 x V214 - Estribo | VIGA BALDRAME | 0.5 | 0.000019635
2 x V214 - Longitudinal inferior | VIGA BALDRAME | 0.8 | 0.0000502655
2 x V214 - Longitudinal superior | VIGA BALDRAME | 0.8 | 0.0000502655
4 x V215 - Estribo | VIGA BALDRAME | 0.5 | 0.000019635
2 x V215 - Longitudinal inferior | VIGA BALDRAME | 0.8 | 0.0000502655
2 x V215 - Longitudinal superior | VIGA BALDRAME | 0.8 | 0.0000502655
84 x V216 - Estribo | VIGA BALDRAME | 0.5 | 0.000019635
5 x V216 - Longitudinal inferior | VIGA BALDRAME | 1.25 | 0.000122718
6 x V216 - Longitudinal superior | VIGA BALDRAME | 1.25 | 0.000122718
5 x V217 - Estribo | VIGA BALDRAME | 0.5 | 0.000019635
2 x V217 - Longitudinal inferior | VIGA BALDRAME | 0.8 | 0.0000502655
2 x V217 - Longitudinal superior | VIGA BALDRAME | 0.8 | 0.0000502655
2 x V218 - Estribo | VIGA BALDRAME | 0.5 | 0.000019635
2 x V218 - Longitudinal construtiva | VIGA BALDRAME | 0.5 | 0.000019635
2 x V218 - Longitudinal inferior | VIGA BALDRAME | 0.8 | 0.0000502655
38 x V219 - Estribo | VIGA BALDRAME | 0.5 | 0.000019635
3 x V219 - Longitudinal inferior | VIGA BALDRAME | 1 | 0.0000785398
2 x V219 - Longitudinal superior | VIGA BALDRAME | 1 | 0.0000785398
30 x V220 - Estribo | VIGA BALDRAME | 0.5 | 0.000019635
2 x V220 - Longitudinal inferior | VIGA BALDRAME | 1.25 | 0.000122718
2 x V220 - Longitudinal superior | VIGA BALDRAME | 1 | 0.0000785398
36 x V221 - Estribo | VIGA BALDRAME | 0.5 | 0.000019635
2 x V221 - Longitudinal inferior | VIGA BALDRAME | 0.8 | 0.0000502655
2 x V221 - Longitudinal superior | VIGA BALDRAME | 0.8 | 0.0000502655
5 x V222 - Estribo | VIGA BALDRAME | 0.5 | 0.000019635
2 x V222 - Longitudinal inferior | VIGA BALDRAME | 0.8 | 0.0000502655
2 x V222 - Longitudinal superior | VIGA BALDRAME | 0.8 | 0.0000502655
11 x V223 - Estribo | VIGA BALDRAME | 0.5 | 0.000019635
2 x V223 - Longitudinal inferior | VIGA BALDRAME | 0.8 | 0.0000502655
2 x V223 - Longitudinal superior | VIGA BALDRAME | 0.8 | 0.0000502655
32 x V224 - Estribo | VIGA BALDRAME | 0.5 | 0.000019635
3 x V224 - Longitudinal inferior | VIGA BALDRAME | 1.25 | 0.000122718
2 x V224 - Longitudinal superior | VIGA BALDRAME | 1.25 | 0.000122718
20 x V225 - Estribo | VIGA BALDRAME | 0.5 | 0.000019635
2 x V225 - Longitudinal inferior | VIGA BALDRAME | 1 | 0.0000785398
2 x V225 - Longitudinal superior | VIGA BALDRAME | 0.8 | 0.0000502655
32 x V226 - Estribo | VIGA BALDRAME | 0.5 | 0.000019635
3 x V226 - Longitudinal inferior | VIGA BALDRAME | 1.25 | 0.000122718
2 x V226 - Longitudinal superior | VIGA BALDRAME | 1.25 | 0.000122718
32 x V227 - Estribo | VIGA BALDRAME | 0.5 | 0.000019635
3 x V227 - Longitudinal inferior | VIGA BALDRAME | 1.25 | 0.000122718
2 x V227 - Longitudinal superior | VIGA BALDRAME | 1.25 | 0.000122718
20 x V228 - Estribo | VIGA BALDRAME | 0.5 | 0.000019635
2 x V228 - Longitudinal inferior | VIGA BALDRAME | 1 | 0.0000785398
2 x V228 - Longitudinal superior | VIGA BALDRAME | 0.8 | 0.0000502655
32 x V229 - Estribo | VIGA BALDRAME | 0.5 | 0.000019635
3 x V229 - Longitudinal inferior | VIGA BALDRAME | 1.25 | 0.000122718
2 x V229 - Longitudinal superior | VIGA BALDRAME | 1.25 | 0.000122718
558 x V230 - Estribo | VIGA BALDRAME | 0.5 | 0.000019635
12 x V230 - Longitudinal inferior | VIGA BALDRAME | 1 | 0.0000785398
12 x V230 - Longitudinal superior | VIGA BALDRAME | 1 | 0.0000785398
18 x VM1 - Estribo | VIGA BALDRAME | 0.5 | 0.000019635
2 x VM1 - Longitudinal inferior | VIGA BALDRAME | 1 | 0.0000785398
2 x VM1 - Longitudinal superior | VIGA BALDRAME | 1 | 0.0000785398
2 x L1 - Complementar | TERREO | 0.5 | 0.000019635
15 x L1 - Inferior X | TERREO | 0.5 | 0.000019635
11 x L1 - Inferior Y | TERREO | 0.5 | 0.000019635
2 x L1 - Superior Y | TERREO | 0.63 | 0.0000311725
2 x L2 - Complementar | TERREO | 0.5 | 0.000019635
42 x L2 - Continuidade | TERREO | 1 | 0.0000785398
21 x L2 - Inferior X | TERREO | 0.5 | 0.000019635
44 x L2 - Inferior Y | TERREO | 0.5 | 0.000019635
2 x L2 - Superior X | TERREO | 1 | 0.0000785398
2 x L3 - Complementar | TERREO | 0.5 | 0.000019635
24 x L3 - Inferior X | TERREO | 0.5 | 0.000019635
11 x L3 - Inferior Y | TERREO | 0.5 | 0.000019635
2 x L3 - Superior Y | TERREO | 0.63 | 0.0000311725
26 x P102 - Estribo | TERREO | 0.5 | 0.000019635
26 x P102 - Grampo | TERREO | 0.5 | 0.000019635
6 x P102 - Longitudinal | TERREO | 1 | 0.0000785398
26 x P106 - Estribo | TERREO | 0.5 | 0.000019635
4 x P106 - Longitudinal | TERREO | 1 | 0.0000785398
26 x P109 - Estribo | TERREO | 0.5 | 0.000019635
4 x P109 - Longitudinal | TERREO | 1 | 0.0000785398
26 x P112 - Estribo | TERREO | 0.5 | 0.000019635
4 x P112 - Longitudinal | TERREO | 1 | 0.0000785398
26 x P113 - Estribo | TERREO | 0.5 | 0.000019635
4 x P113 - Longitudinal | TERREO | 1 | 0.0000785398
26 x P116 - Estribo | TERREO | 0.5 | 0.000019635
4 x P116 - Longitudinal | TERREO | 1 | 0.0000785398
26 x P119 - Estribo | TERREO | 0.5 | 0.000019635
4 x P119 - Longitudinal | TERREO | 1 | 0.0000785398
26 x P120 - Estribo | TERREO | 0.5 | 0.000019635
4 x P120 - Longitudinal | TERREO | 1 | 0.0000785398
26 x P121 - Estribo | TERREO | 0.5 | 0.000019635
6 x P121 - Longitudinal | TERREO | 1 | 0.0000785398
26 x P122 - Estribo | TERREO | 0.5 | 0.000019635
4 x P122 - Longitudinal | TERREO | 1 | 0.0000785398
26 x P124 - Estribo | TERREO | 0.5 | 0.000019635
4 x P124 - Longitudinal | TERREO | 1 | 0.0000785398
26 x P128 - Estribo | TERREO | 0.5 | 0.000019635
4 x P128 - Longitudinal | TERREO | 1 | 0.0000785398
26 x P129 - Estribo | TERREO | 0.5 | 0.000019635
4 x P129 - Longitudinal | TERREO | 1 | 0.0000785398
26 x P131 - Estribo | TERREO | 0.5 | 0.000019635
4 x P131 - Longitudinal | TERREO | 1 | 0.0000785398
26 x P135 - Estribo | TERREO | 0.5 | 0.000019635
26 x P135 - Grampo | TERREO | 0.5 | 0.000019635
6 x P135 - Longitudinal | TERREO | 1 | 0.0000785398
26 x P136 - Estribo | TERREO | 0.5 | 0.000019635
4 x P136 - Longitudinal | TERREO | 1 | 0.0000785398
26 x P137 - Estribo | TERREO | 0.5 | 0.000019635
4 x P137 - Longitudinal | TERREO | 1 | 0.0000785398
26 x P138 - Estribo | TERREO | 0.5 | 0.000019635
4 x P138 - Longitudinal | TERREO | 1 | 0.0000785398
26 x P139 - Estribo | TERREO | 0.5 | 0.000019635
4 x P139 - Longitudinal | TERREO | 1 | 0.0000785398
26 x P140 - Estribo | TERREO | 0.5 | 0.000019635
26 x P140 - Grampo | TERREO | 0.5 | 0.000019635
6 x P140 - Longitudinal | TERREO | 1 | 0.0000785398
4 x P141 - Estribo | TERREO | 0.5 | 0.000019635
4 x P141 - Longitudinal | TERREO | 1 | 0.0000785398
12 x P142 - Estribo | TERREO | 0.5 | 0.000019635
12 x P142 - Grampo | TERREO | 0.5 | 0.000019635
6 x P142 - Longitudinal | TERREO | 1.25 | 0.000122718
26 x P143 - Estribo | TERREO | 0.5 | 0.000019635
4 x P143 - Longitudinal | TERREO | 1 | 0.0000785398
26 x P145 - Estribo | TERREO | 0.5 | 0.000019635
4 x P145 - Longitudinal | TERREO | 1 | 0.0000785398
26 x P146 - Estribo | TERREO | 0.5 | 0.000019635
4 x P146 - Longitudinal | TERREO | 1 | 0.0000785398
26 x P147 - Estribo | TERREO | 0.5 | 0.000019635
4 x P147 - Longitudinal | TERREO | 1 | 0.0000785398
26 x P148 - Estribo | TERREO | 0.5 | 0.000019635
4 x P148 - Longitudinal | TERREO | 1 | 0.0000785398
4 x P150 - Estribo | TERREO | 0.5 | 0.000019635
4 x P150 - Longitudinal | TERREO | 1 | 0.0000785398
18 x P152 - Estribo | TERREO | 0.5 | 0.000019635
4 x P152 - Longitudinal | TERREO | 1 | 0.0000785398
18 x P153 - Estribo | TERREO | 0.5 | 0.000019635
4 x P153 - Longitudinal | TERREO | 1 | 0.0000785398
18 x P154 - Estribo | TERREO | 0.5 | 0.000019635
4 x P154 - Longitudinal | TERREO | 1 | 0.0000785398
70 x P155 - Estribo | TERREO | 0.5 | 0.000019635
70 x P155 - Grampo | TERREO | 0.5 | 0.000019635
6 x P155 - Longitudinal | TERREO | 1 | 0.0000785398
18 x P164 - Estribo | TERREO | 0.5 | 0.000019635
4 x P164 - Longitudinal | TERREO | 1 | 0.0000785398
18 x P165 - Estribo | TERREO | 0.5 | 0.000019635
4 x P165 - Longitudinal | TERREO | 1 | 0.0000785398
18 x P168 - Estribo | TERREO | 0.5 | 0.000019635
4 x P168 - Longitudinal | TERREO | 1 | 0.0000785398
26 x P17 - Estribo | TERREO | 0.5 | 0.000019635
4 x P17 - Longitudinal | TERREO | 1 | 0.0000785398
26 x P19 - Estribo | TERREO | 0.5 | 0.000019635
4 x P19 - Longitudinal | TERREO | 1 | 0.0000785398
26 x P20 - Estribo | TERREO | 0.5 | 0.000019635
6 x P20 - Longitudinal | TERREO | 1 | 0.0000785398
26 x P22 - Estribo | TERREO | 0.5 | 0.000019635
4 x P22 - Longitudinal | TERREO | 1 | 0.0000785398
26 x P23 - Estribo | TERREO | 0.5 | 0.000019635
26 x P23 - Grampo | TERREO | 0.5 | 0.000019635
6 x P23 - Longitudinal | TERREO | 1 | 0.0000785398
26 x P24 - Estribo | TERREO | 0.5 | 0.000019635
4 x P24 - Longitudinal | TERREO | 1 | 0.0000785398
26 x P25 - Estribo | TERREO | 0.5 | 0.000019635
4 x P25 - Longitudinal | TERREO | 1 | 0.0000785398
26 x P26 - Estribo | TERREO | 0.5 | 0.000019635
26 x P26 - Grampo | TERREO | 0.5 | 0.000019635
6 x P26 - Longitudinal | TERREO | 1 | 0.0000785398
26 x P27 - Estribo | TERREO | 0.5 | 0.000019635
4 x P27 - Longitudinal | TERREO | 1 | 0.0000785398
26 x P28 - Estribo | TERREO | 0.5 | 0.000019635
26 x P28 - Grampo | TERREO | 0.5 | 0.000019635
6 x P28 - Longitudinal | TERREO | 1 | 0.0000785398
26 x P33 - Estribo | TERREO | 0.5 | 0.000019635
6 x P33 - Longitudinal | TERREO | 1 | 0.0000785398
26 x P34 - Estribo | TERREO | 0.5 | 0.000019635
4 x P34 - Longitudinal | TERREO | 1 | 0.0000785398
26 x P36 - Estribo | TERREO | 0.5 | 0.000019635
4 x P36 - Longitudinal | TERREO | 1 | 0.0000785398
26 x P40 - Estribo | TERREO | 0.5 | 0.000019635
4 x P40 - Longitudinal | TERREO | 1 | 0.0000785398
26 x P41 - Estribo | TERREO | 0.5 | 0.000019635
4 x P41 - Longitudinal | TERREO | 1 | 0.0000785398
26 x P42 - Estribo | TERREO | 0.5 | 0.000019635
26 x P42 - Grampo | TERREO | 0.5 | 0.000019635
6 x P42 - Longitudinal | TERREO | 1 | 0.0000785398
26 x P43 - Estribo | TERREO | 0.5 | 0.000019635
4 x P43 - Longitudinal | TERREO | 1 | 0.0000785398
26 x P44 - Estribo | TERREO | 0.5 | 0.000019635
4 x P44 - Longitudinal | TERREO | 1 | 0.0000785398
26 x P45 - Estribo | TERREO | 0.5 | 0.000019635
4 x P45 - Longitudinal | TERREO | 1 | 0.0000785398
26 x P47 - Estribo | TERREO | 0.5 | 0.000019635
4 x P47 - Longitudinal | TERREO | 1 | 0.0000785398
26 x P50 - Estribo | TERREO | 0.5 | 0.000019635
4 x P50 - Longitudinal | TERREO | 1 | 0.0000785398
26 x P51 - Estribo | TERREO | 0.5 | 0.000019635
4 x P51 - Longitudinal | TERREO | 1 | 0.0000785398
26 x P52 - Estribo | TERREO | 0.5 | 0.000019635
4 x P52 - Longitudinal | TERREO | 1 | 0.0000785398
26 x P53 - Estribo | TERREO | 0.5 | 0.000019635
4 x P53 - Longitudinal | TERREO | 1 | 0.0000785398
26 x P54 - Estribo | TERREO | 0.5 | 0.000019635
4 x P54 - Longitudinal | TERREO | 1 | 0.0000785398
26 x P55 - Estribo | TERREO | 0.5 | 0.000019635
4 x P55 - Longitudinal | TERREO | 1 | 0.0000785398
26 x P56 - Estribo | TERREO | 0.5 | 0.000019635
4 x P56 - Longitudinal | TERREO | 1 | 0.0000785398
26 x P58 - Estribo | TERREO | 0.5 | 0.000019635
4 x P58 - Longitudinal | TERREO | 1 | 0.0000785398
26 x P60 - Estribo | TERREO | 0.5 | 0.000019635
4 x P60 - Longitudinal | TERREO | 1 | 0.0000785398
26 x P62 - Estribo | TERREO | 0.5 | 0.000019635
4 x P62 - Longitudinal | TERREO | 1 | 0.0000785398
9 x P63 - Estribo | TERREO | 0.5 | 0.000019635
9 x P63 - Grampo | TERREO | 0.5 | 0.000019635
6 x P63 - Longitudinal | TERREO | 1 | 0.0000785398
26 x P65 - Estribo | TERREO | 0.5 | 0.000019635
4 x P65 - Longitudinal | TERREO | 1 | 0.0000785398
26 x P66 - Estribo | TERREO | 0.5 | 0.000019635
4 x P66 - Longitudinal | TERREO | 1 | 0.0000785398
26 x P69 - Estribo | TERREO | 0.5 | 0.000019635
26 x P69 - Grampo | TERREO | 0.5 | 0.000019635
6 x P69 - Longitudinal | TERREO | 1 | 0.0000785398
26 x P71 - Estribo | TERREO | 0.5 | 0.000019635
4 x P71 - Longitudinal | TERREO | 1 | 0.0000785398
26 x P72 - Estribo | TERREO | 0.5 | 0.000019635
4 x P72 - Longitudinal | TERREO | 1 | 0.0000785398
26 x P73 - Estribo | TERREO | 0.5 | 0.000019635
26 x P73 - Grampo | TERREO | 0.5 | 0.000019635
6 x P73 - Longitudinal | TERREO | 1 | 0.0000785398
26 x P74 - Estribo | TERREO | 0.5 | 0.000019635
6 x P74 - Longitudinal | TERREO | 1 | 0.0000785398
26 x P87 - Estribo | TERREO | 0.5 | 0.000019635
4 x P87 - Longitudinal | TERREO | 1 | 0.0000785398
26 x P90 - Estribo | TERREO | 0.5 | 0.000019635
4 x P90 - Longitudinal | TERREO | 1 | 0.0000785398
26 x P92 - Estribo | TERREO | 0.5 | 0.000019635
6 x P92 - Longitudinal | TERREO | 1 | 0.0000785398
26 x P94 - Estribo | TERREO | 0.5 | 0.000019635
4 x P94 - Longitudinal | TERREO | 1 | 0.0000785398
26 x P95 - Estribo | TERREO | 0.5 | 0.000019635
4 x P95 - Longitudinal | TERREO | 1 | 0.0000785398
26 x P96 - Estribo | TERREO | 0.5 | 0.000019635
4 x P96 - Longitudinal | TERREO | 1 | 0.0000785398
26 x P97 - Estribo | TERREO | 0.5 | 0.000019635
4 x P97 - Longitudinal | TERREO | 1 | 0.0000785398
26 x P98 - Estribo | TERREO | 0.5 | 0.000019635
4 x P98 - Longitudinal | TERREO | 1 | 0.0000785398
26 x P99 - Estribo | TERREO | 0.5 | 0.000019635
4 x P99 - Longitudinal | TERREO | 1 | 0.0000785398
32 x V201 - Estribo | TERREO | 0.5 | 0.000019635
4 x V201 - Grampo | TERREO | 0.5 | 0.000019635
4 x V201 - Longitudinal | TERREO | 1 | 0.0000785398
2 x V201 - Longitudinal inferior | TERREO | 0.8 | 0.0000502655
4 x V201 - Longitudinal superior | TERREO | 1 | 0.0000785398
2 x V201 - Longitudinal superior | TERREO | 0.8 | 0.0000502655
34 x V202 - Estribo | TERREO | 0.5 | 0.000019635
4 x V202 - Longitudinal | TERREO | 1 | 0.0000785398
2 x V202 - Longitudinal inferior | TERREO | 1 | 0.0000785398
4 x V202 - Longitudinal superior | TERREO | 1 | 0.0000785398
2 x V202 - Longitudinal superior | TERREO | 0.8 | 0.0000502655
13 x V203 - Estribo | TERREO | 0.5 | 0.000019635
4 x V203 - Grampo | TERREO | 0.5 | 0.000019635
2 x V203 - Longitudinal inferior | TERREO | 0.8 | 0.0000502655
2 x V203 - Longitudinal superior | TERREO | 1 | 0.0000785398
11 x V204 - Estribo | TERREO | 0.5 | 0.000019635
2 x V204 - Longitudinal inferior | TERREO | 0.8 | 0.0000502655
2 x V204 - Longitudinal superior | TERREO | 0.8 | 0.0000502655
12 x V205 - Estribo | TERREO | 0.5 | 0.000019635
2 x V205 - Longitudinal inferior | TERREO | 0.8 | 0.0000502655
2 x V205 - Longitudinal superior | TERREO | 0.8 | 0.0000502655
11 x V206 - Estribo | TERREO | 0.5 | 0.000019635
4 x V206 - Grampo | TERREO | 0.5 | 0.000019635
2 x V206 - Longitudinal inferior | TERREO | 0.8 | 0.0000502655
2 x V206 - Longitudinal superior | TERREO | 1 | 0.0000785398
11 x V207 - Estribo | TERREO | 0.5 | 0.000019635
2 x V207 - Longitudinal inferior | TERREO | 0.8 | 0.0000502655
2 x V207 - Longitudinal superior | TERREO | 0.8 | 0.0000502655
10 x V208 - Estribo | TERREO | 0.5 | 0.000019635
2 x V208 - Longitudinal inferior | TERREO | 0.8 | 0.0000502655
2 x V208 - Longitudinal superior | TERREO | 0.8 | 0.0000502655
3 x V209 - Estribo | TERREO | 0.5 | 0.000019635
4 x V209 - Grampo | TERREO | 0.5 | 0.000019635
2 x V209 - Longitudinal inferior | TERREO | 0.8 | 0.0000502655
2 x V209 - Longitudinal superior | TERREO | 1 | 0.0000785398
29 x V210 - Estribo | TERREO | 0.5 | 0.000019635
4 x V210 - Grampo | TERREO | 0.5 | 0.000019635
2 x V210 - Longitudinal inferior | TERREO | 0.8 | 0.0000502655
2 x V210 - Longitudinal superior | TERREO | 1 | 0.0000785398
4 x V211 - Estribo | TERREO | 0.5 | 0.000019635
4 x V211 - Grampo | TERREO | 0.5 | 0.000019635
2 x V211 - Longitudinal inferior | TERREO | 0.8 | 0.0000502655
2 x V211 - Longitudinal superior | TERREO | 1 | 0.0000785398
3 x V212 - Estribo | TERREO | 0.5 | 0.000019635
4 x V212 - Grampo | TERREO | 0.5 | 0.000019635
2 x V212 - Longitudinal inferior | TERREO | 0.8 | 0.0000502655
2 x V212 - Longitudinal superior | TERREO | 1 | 0.0000785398
29 x V213 - Estribo | TERREO | 0.5 | 0.000019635
2 x V213 - Longitudinal inferior | TERREO | 0.8 | 0.0000502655
2 x V213 - Longitudinal inferior | TERREO | 1 | 0.0000785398
2 x V213 - Longitudinal superior | TERREO | 0.8 | 0.0000502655
4 x V214 - Estribo | TERREO | 0.5 | 0.000019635
4 x V214 - Grampo | TERREO | 0.5 | 0.000019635
2 x V214 - Longitudinal inferior | TERREO | 0.8 | 0.0000502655
2 x V214 - Longitudinal superior | TERREO | 1 | 0.0000785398
3 x V215 - Estribo | TERREO | 0.5 | 0.000019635
4 x V215 - Grampo | TERREO | 0.5 | 0.000019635
2 x V215 - Longitudinal inferior | TERREO | 0.8 | 0.0000502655
2 x V215 - Longitudinal superior | TERREO | 1 | 0.0000785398
29 x V216 - Estribo | TERREO | 0.5 | 0.000019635
4 x V216 - Grampo | TERREO | 0.5 | 0.000019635
2 x V216 - Longitudinal inferior | TERREO | 0.8 | 0.0000502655
2 x V216 - Longitudinal superior | TERREO | 1 | 0.0000785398
4 x V217 - Estribo | TERREO | 0.5 | 0.000019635
4 x V217 - Grampo | TERREO | 0.5 | 0.000019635
2 x V217 - Longitudinal inferior | TERREO | 0.8 | 0.0000502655
2 x V217 - Longitudinal superior | TERREO | 1 | 0.0000785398
3 x V218 - Estribo | TERREO | 0.5 | 0.000019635
4 x V218 - Grampo | TERREO | 0.5 | 0.000019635
2 x V218 - Longitudinal inferior | TERREO | 0.8 | 0.0000502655
2 x V218 - Longitudinal superior | TERREO | 1 | 0.0000785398
28 x V219 - Estribo | TERREO | 0.5 | 0.000019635
5 x V219 - Grampo | TERREO | 0.5 | 0.000019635
2 x V219 - Longitudinal inferior | TERREO | 0.8 | 0.0000502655
3 x V219 - Longitudinal superior | TERREO | 0.8 | 0.0000502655
4 x V220 - Estribo | TERREO | 0.5 | 0.000019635
4 x V220 - Grampo | TERREO | 0.5 | 0.000019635
2 x V220 - Longitudinal inferior | TERREO | 0.8 | 0.0000502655
2 x V220 - Longitudinal superior | TERREO | 1 | 0.0000785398
2 x V221 - Estribo | TERREO | 0.5 | 0.000019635
2 x V221 - Longitudinal inferior | TERREO | 0.8 | 0.0000502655
2 x V221 - Longitudinal superior | TERREO | 0.8 | 0.0000502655
27 x V222 - Estribo | TERREO | 0.5 | 0.000019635
2 x V222 - Longitudinal inferior | TERREO | 0.8 | 0.0000502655
2 x V222 - Longitudinal superior | TERREO | 0.8 | 0.0000502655
13 x V223 - Estribo | TERREO | 0.5 | 0.000019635
4 x V223 - Grampo | TERREO | 0.5 | 0.000019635
2 x V223 - Longitudinal inferior | TERREO | 0.8 | 0.0000502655
2 x V223 - Longitudinal superior | TERREO | 1 | 0.0000785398
3 x V224 - Estribo | TERREO | 0.5 | 0.000019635
2 x V224 - Longitudinal inferior | TERREO | 0.8 | 0.0000502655
2 x V224 - Longitudinal superior | TERREO | 0.8 | 0.0000502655
11 x V225 - Estribo | TERREO | 0.5 | 0.000019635
4 x V225 - Grampo | TERREO | 0.5 | 0.000019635
2 x V225 - Longitudinal inferior | TERREO | 0.8 | 0.0000502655
2 x V225 - Longitudinal superior | TERREO | 1 | 0.0000785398
26 x V226 - Estribo | TERREO | 0.5 | 0.000019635
2 x V226 - Longitudinal inferior | TERREO | 0.8 | 0.0000502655
2 x V226 - Longitudinal superior | TERREO | 0.8 | 0.0000502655
2 x V227 - Estribo | TERREO | 0.5 | 0.000019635
2 x V227 - Longitudinal inferior | TERREO | 0.8 | 0.0000502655
2 x V227 - Longitudinal superior | TERREO | 0.8 | 0.0000502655
27 x V228 - Estribo | TERREO | 0.5 | 0.000019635
2 x V228 - Longitudinal inferior | TERREO | 0.8 | 0.0000502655
2 x V228 - Longitudinal superior | TERREO | 0.8 | 0.0000502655
9 x V229 - Estribo | TERREO | 0.5 | 0.000019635
2 x V229 - Longitudinal inferior | TERREO | 0.8 | 0.0000502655
2 x V229 - Longitudinal superior | TERREO | 0.8 | 0.0000502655
2 x V230 - Estribo | TERREO | 0.5 | 0.000019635
2 x V230 - Longitudinal inferior | TERREO | 0.8 | 0.0000502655
2 x V230 - Longitudinal superior | TERREO | 0.8 | 0.0000502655
26 x V231 - Estribo | TERREO | 0.5 | 0.000019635
2 x V231 - Longitudinal inferior | TERREO | 0.8 | 0.0000502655
2 x V231 - Longitudinal superior | TERREO | 0.8 | 0.0000502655
12 x V232 - Estribo | TERREO | 0.5 | 0.000019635
2 x V232 - Longitudinal inferior | TERREO | 0.8 | 0.0000502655
2 x V232 - Longitudinal superior | TERREO | 0.8 | 0.0000502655
5 x V233 - Estribo | TERREO | 0.5 | 0.000019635
2 x V233 - Longitudinal inferior | TERREO | 0.8 | 0.0000502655
2 x V233 - Longitudinal superior | TERREO | 0.8 | 0.0000502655
10 x V234 - Estribo | TERREO | 0.5 | 0.000019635
2 x V234 - Longitudinal inferior | TERREO | 0.8 | 0.0000502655
2 x V234 - Longitudinal superior | TERREO | 0.8 | 0.0000502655
3 x V235 - Estribo | TERREO | 0.5 | 0.000019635
V235 - Grampo | TERREO | 0.5 | 0.000019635
2 x V235 - Longitudinal inferior | TERREO | 0.8 | 0.0000502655
2 x V235 - Longitudinal superior | TERREO | 0.8 | 0.0000502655
12 x V236 - Estribo | TERREO | 0.5 | 0.000019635
4 x V236 - Grampo | TERREO | 0.5 | 0.000019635
2 x V236 - Longitudinal inferior | TERREO | 0.8 | 0.0000502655
2 x V236 - Longitudinal superior | TERREO | 1 | 0.0000785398
12 x V237 - Estribo | TERREO | 0.5 | 0.000019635
4 x V237 - Grampo | TERREO | 0.5 | 0.000019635
2 x V237 - Longitudinal inferior | TERREO | 0.8 | 0.0000502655
2 x V237 - Longitudinal superior | TERREO | 1 | 0.0000785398
29 x V238 - Estribo | TERREO | 0.5 | 0.000019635
2 x V238 - Longitudinal inferior | TERREO | 0.8 | 0.0000502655
2 x V238 - Longitudinal superior | TERREO | 0.8 | 0.0000502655
3 x V239 - Estribo | TERREO | 0.5 | 0.000019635
2 x V239 - Longitudinal inferior | TERREO | 0.8 | 0.0000502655
2 x V239 - Longitudinal superior | TERREO | 0.8 | 0.0000502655
4 x V240 - Estribo | TERREO | 0.5 | 0.000019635
2 x V240 - Longitudinal inferior | TERREO | 0.8 | 0.0000502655
2 x V240 - Longitudinal superior | TERREO | 0.8 | 0.0000502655
3 x V241 - Estribo | TERREO | 0.5 | 0.000019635
4 x V241 - Grampo | TERREO | 0.5 | 0.000019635
2 x V241 - Longitudinal inferior | TERREO | 0.8 | 0.0000502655
2 x V241 - Longitudinal superior | TERREO | 1 | 0.0000785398
28 x V242 - Estribo | TERREO | 0.5 | 0.000019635
4 x V242 - Grampo | TERREO | 0.5 | 0.000019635
2 x V242 - Longitudinal inferior | TERREO | 0.8 | 0.0000502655
2 x V242 - Longitudinal superior | TERREO | 1 | 0.0000785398
8 x V243 - Estribo | TERREO | 0.5 | 0.000019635
2 x V243 - Longitudinal inferior | TERREO | 0.8 | 0.0000502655
2 x V243 - Longitudinal superior | TERREO | 0.8 | 0.0000502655
4 x V244 - Estribo | TERREO | 0.5 | 0.000019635
4 x V244 - Grampo | TERREO | 0.5 | 0.000019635
2 x V244 - Longitudinal inferior | TERREO | 0.8 | 0.0000502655
2 x V244 - Longitudinal superior | TERREO | 1 | 0.0000785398
4 x V245 - Estribo | TERREO | 0.5 | 0.000019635
4 x V245 - Grampo | TERREO | 0.5 | 0.000019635
2 x V245 - Longitudinal inferior | TERREO | 0.8 | 0.0000502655
2 x V245 - Longitudinal superior | TERREO | 1 | 0.0000785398
29 x V246 - Estribo | TERREO | 0.5 | 0.000019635
4 x V246 - Grampo | TERREO | 0.5 | 0.000019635
2 x V246 - Longitudinal inferior | TERREO | 0.8 | 0.0000502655
2 x V246 - Longitudinal superior | TERREO | 1 | 0.0000785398
13 x V247 - Estribo | TERREO | 0.5 | 0.000019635
2 x V247 - Longitudinal inferior | TERREO | 0.8 | 0.0000502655
2 x V247 - Longitudinal superior | TERREO | 0.8 | 0.0000502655
39 x V248 - Estribo | TERREO | 0.5 | 0.000019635
2 x V248 - Longitudinal inferior | TERREO | 0.8 | 0.0000502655
2 x V248 - Longitudinal superior | TERREO | 1 | 0.0000785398
4 x V249 - Estribo | TERREO | 0.5 | 0.000019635
4 x V249 - Grampo | TERREO | 0.5 | 0.000019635
2 x V249 - Longitudinal inferior | TERREO | 0.8 | 0.0000502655
2 x V249 - Longitudinal superior | TERREO | 1 | 0.0000785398
12 x V250 - Estribo | TERREO | 0.5 | 0.000019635
2 x V250 - Longitudinal inferior | TERREO | 0.8 | 0.0000502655
2 x V250 - Longitudinal superior | TERREO | 0.8 | 0.0000502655
10 x V251 - Estribo | TERREO | 0.5 | 0.000019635
2 x V251 - Longitudinal inferior | TERREO | 0.8 | 0.0000502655
2 x V251 - Longitudinal superior | TERREO | 0.8 | 0.0000502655
16 x V252 - Estribo | TERREO | 0.5 | 0.000019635
2 x V252 - Longitudinal inferior | TERREO | 0.8 | 0.0000502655
2 x V252 - Longitudinal superior | TERREO | 0.8 | 0.0000502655
11 x V253 - Estribo | TERREO | 0.5 | 0.000019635
4 x V253 - Grampo | TERREO | 0.5 | 0.000019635
2 x V253 - Longitudinal inferior | TERREO | 0.8 | 0.0000502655
2 x V253 - Longitudinal superior | TERREO | 1 | 0.0000785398
10 x V254 - Estribo | TERREO | 0.5 | 0.000019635
2 x V254 - Longitudinal inferior | TERREO | 0.8 | 0.0000502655
2 x V254 - Longitudinal superior | TERREO | 0.8 | 0.0000502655
11 x V255 - Estribo | TERREO | 0.5 | 0.000019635
2 x V255 - Longitudinal inferior | TERREO | 0.8 | 0.0000502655
2 x V255 - Longitudinal superior | TERREO | 0.8 | 0.0000502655
11 x V256 - Estribo | TERREO | 0.5 | 0.000019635
4 x V256 - Grampo | TERREO | 0.5 | 0.000019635
2 x V256 - Longitudinal inferior | TERREO | 0.8 | 0.0000502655
2 x V256 - Longitudinal superior | TERREO | 1 | 0.0000785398
29 x V257 - Estribo | TERREO | 0.5 | 0.000019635
2 x V257 - Longitudinal construtiva | TERREO | 0.5 | 0.000019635
2 x V257 - Longitudinal inferior | TERREO | 1 | 0.0000785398
4 x V257 - Longitudinal superior | TERREO | 1 | 0.0000785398
27 x V258 - Estribo | TERREO | 0.5 | 0.000019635
5 x V258 - Grampo | TERREO | 0.5 | 0.000019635
2 x V258 - Longitudinal inferior | TERREO | 0.8 | 0.0000502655
2 x V258 - Longitudinal superior | TERREO | 1 | 0.0000785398
24 x V259 - Estribo | TERREO | 0.5 | 0.000019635
2 x V259 - Longitudinal inferior | TERREO | 0.8 | 0.0000502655
2 x V259 - Longitudinal superior | TERREO | 0.8 | 0.0000502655
13 x V260 - Estribo | TERREO | 0.5 | 0.000019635
2 x V260 - Longitudinal inferior | TERREO | 0.8 | 0.0000502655
2 x V260 - Longitudinal superior | TERREO | 0.8 | 0.0000502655
24 x V261 - Estribo | TERREO | 0.5 | 0.000019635
2 x V261 - Longitudinal inferior | TERREO | 0.8 | 0.0000502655
2 x V261 - Longitudinal superior | TERREO | 0.8 | 0.0000502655
24 x V262 - Estribo | TERREO | 0.5 | 0.000019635
2 x V262 - Longitudinal inferior | TERREO | 0.8 | 0.0000502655
2 x V262 - Longitudinal superior | TERREO | 0.8 | 0.0000502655
12 x V263 - Estribo | TERREO | 0.5 | 0.000019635
2 x V263 - Longitudinal inferior | TERREO | 0.8 | 0.0000502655
2 x V263 - Longitudinal superior | TERREO | 0.8 | 0.0000502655
23 x V264 - Estribo | TERREO | 0.5 | 0.000019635
2 x V264 - Longitudinal inferior | TERREO | 0.8 | 0.0000502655
2 x V264 - Longitudinal superior | TERREO | 0.8 | 0.0000502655
27 x V265 - Estribo | TERREO | 0.5 | 0.000019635
4 x V265 - Grampo | TERREO | 0.5 | 0.000019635
2 x V265 - Longitudinal inferior | TERREO | 0.8 | 0.0000502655
2 x V265 - Longitudinal superior | TERREO | 1 | 0.0000785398
4 x V266 - Estribo | TERREO | 0.5 | 0.000019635
2 x V266 - Longitudinal inferior | TERREO | 0.8 | 0.0000502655
2 x V266 - Longitudinal superior | TERREO | 0.8 | 0.0000502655
12 x V267 - Estribo | TERREO | 0.5 | 0.000019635
2 x V267 - Longitudinal construtiva | TERREO | 0.5 | 0.000019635
2 x V267 - Longitudinal inferior | TERREO | 0.8 | 0.0000502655
3 x V268 - Estribo | TERREO | 0.5 | 0.000019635
2 x V268 - Longitudinal inferior | TERREO | 0.8 | 0.0000502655
2 x V268 - Longitudinal superior | TERREO | 0.8 | 0.0000502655
2 x V269 - Estribo | TERREO | 0.5 | 0.000019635
2 x V269 - Longitudinal inferior | TERREO | 0.8 | 0.0000502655
2 x V269 - Longitudinal superior | TERREO | 0.8 | 0.0000502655
86 x V270 - Estribo | TERREO | 0.5 | 0.000019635
8 x V270 - Grampo | TERREO | 0.5 | 0.000019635
2 x V270 - Longitudinal inferior | TERREO | 1 | 0.0000785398
6 x V270 - Longitudinal inferior | TERREO | 0.8 | 0.0000502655
4 x V270 - Longitudinal superior | TERREO | 1 | 0.0000785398
12 x V271 - Estribo | TERREO | 0.5 | 0.000019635
2 x V271 - Longitudinal inferior | TERREO | 0.8 | 0.0000502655
2 x V271 - Longitudinal superior | TERREO | 0.8 | 0.0000502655
27 x V272 - Estribo | TERREO | 0.5 | 0.000019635
4 x V272 - Grampo | TERREO | 0.5 | 0.000019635
2 x V272 - Longitudinal inferior | TERREO | 0.8 | 0.0000502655
2 x V272 - Longitudinal superior | TERREO | 1 | 0.0000785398
4 x V273 - Estribo | TERREO | 0.5 | 0.000019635
2 x V273 - Longitudinal inferior | TERREO | 0.8 | 0.0000502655
2 x V273 - Longitudinal superior | TERREO | 0.8 | 0.0000502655
5 x V274 - Estribo | TERREO | 0.5 | 0.000019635
V274 - Grampo | TERREO | 0.5 | 0.000019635
2 x V274 - Longitudinal inferior | TERREO | 0.8 | 0.0000502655
2 x V274 - Longitudinal superior | TERREO | 0.8 | 0.0000502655
5 x V275 - Estribo | TERREO | 0.5 | 0.000019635
2 x V275 - Longitudinal inferior | TERREO | 0.8 | 0.0000502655
2 x V275 - Longitudinal superior | TERREO | 0.8 | 0.0000502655
27 x V276 - Estribo | TERREO | 0.5 | 0.000019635
V276 - Grampo | TERREO | 0.5 | 0.000019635
2 x V276 - Longitudinal inferior | TERREO | 0.8 | 0.0000502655
2 x V276 - Longitudinal superior | TERREO | 0.8 | 0.0000502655
40 x V277 - Estribo | TERREO | 0.5 | 0.000019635
2 x V277 - Longitudinal inferior | TERREO | 0.8 | 0.0000502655
3 x V277 - Longitudinal superior | TERREO | 0.8 | 0.0000502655
78 x V278 - Estribo | TERREO | 0.5 | 0.000019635
V278 - Grampo | TERREO | 0.5 | 0.000019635
2 x V278 - Longitudinal inferior | TERREO | 0.8 | 0.0000502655
2 x V278 - Longitudinal inferior | TERREO | 1.25 | 0.000122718
2 x V278 - Longitudinal superior | TERREO | 0.8 | 0.0000502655
4 x V278 - Longitudinal superior | TERREO | 1.25 | 0.000122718
3 x V279 - Estribo | TERREO | 0.5 | 0.000019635
2 x V279 - Longitudinal inferior | TERREO | 0.8 | 0.0000502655
2 x V279 - Longitudinal superior | TERREO | 0.8 | 0.0000502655
27 x V280 - Estribo | TERREO | 0.5 | 0.000019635
2 x V280 - Longitudinal inferior | TERREO | 0.8 | 0.0000502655
2 x V280 - Longitudinal superior | TERREO | 0.8 | 0.0000502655
14 x V281 - Estribo | TERREO | 0.5 | 0.000019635
2 x V281 - Longitudinal inferior | TERREO | 0.8 | 0.0000502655
2 x V281 - Longitudinal superior | TERREO | 0.8 | 0.0000502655
8 x V282 - Estribo | TERREO | 0.5 | 0.000019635
2 x V282 - Longitudinal inferior | TERREO | 1 | 0.0000785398
2 x V282 - Longitudinal superior | TERREO | 1 | 0.0000785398
42 x V283 - Estribo | TERREO | 0.5 | 0.000019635
4 x V283 - Longitudinal | TERREO | 1 | 0.0000785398
2 x V283 - Longitudinal inferior | TERREO | 1.25 | 0.000122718
4 x V283 - Longitudinal superior | TERREO | 1.25 | 0.000122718
2 x V283 - Longitudinal superior | TERREO | 0.8 | 0.0000502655
55 x V284 - Estribo | TERREO | 0.5 | 0.000019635
4 x V284 - Longitudinal | TERREO | 1 | 0.0000785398
4 x V284 - Longitudinal inferior | TERREO | 1 | 0.0000785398
4 x V284 - Longitudinal superior | TERREO | 1.25 | 0.000122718
2 x V284 - Longitudinal superior | TERREO | 0.8 | 0.0000502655
13 x V285 - Estribo | TERREO | 0.5 | 0.000019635
2 x V285 - Longitudinal inferior | TERREO | 0.8 | 0.0000502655
2 x V285 - Longitudinal superior | TERREO | 0.8 | 0.0000502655
24 x V286 - Estribo | TERREO | 0.5 | 0.000019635
2 x V286 - Longitudinal inferior | TERREO | 0.8 | 0.0000502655
2 x V286 - Longitudinal superior | TERREO | 0.8 | 0.0000502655
14 x V287 - Estribo | TERREO | 0.5 | 0.000019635
2 x V287 - Longitudinal inferior | TERREO | 0.8 | 0.0000502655
2 x V287 - Longitudinal superior | TERREO | 0.8 | 0.0000502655
8 x V288 - Estribo | TERREO | 0.5 | 0.000019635
2 x V288 - Longitudinal inferior | TERREO | 1 | 0.0000785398
2 x V288 - Longitudinal superior | TERREO | 1 | 0.0000785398
43 x V289 - Estribo | TERREO | 0.5 | 0.000019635
4 x V289 - Longitudinal | TERREO | 1 | 0.0000785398
2 x V289 - Longitudinal inferior | TERREO | 1.25 | 0.000122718
4 x V289 - Longitudinal superior | TERREO | 1.25 | 0.000122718
2 x V289 - Longitudinal superior | TERREO | 0.8 | 0.0000502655
54 x V290 - Estribo | TERREO | 0.5 | 0.000019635
4 x V290 - Longitudinal | TERREO | 1 | 0.0000785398
4 x V290 - Longitudinal inferior | TERREO | 1 | 0.0000785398
2 x V290 - Longitudinal superior | TERREO | 0.8 | 0.0000502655
4 x V290 - Longitudinal superior | TERREO | 1.25 | 0.000122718
12 x V291 - Estribo | TERREO | 0.5 | 0.000019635
2 x V291 - Longitudinal inferior | TERREO | 0.8 | 0.0000502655
2 x V291 - Longitudinal superior | TERREO | 0.8 | 0.0000502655
8 x V292 - Estribo | TERREO | 0.5 | 0.000019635
2 x V292 - Longitudinal construtiva | TERREO | 0.5 | 0.000019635
2 x V292 - Longitudinal inferior | TERREO | 0.8 | 0.0000502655
25 x V293 - Estribo | TERREO | 0.5 | 0.000019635
2 x V293 - Longitudinal inferior | TERREO | 0.8 | 0.0000502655
2 x V293 - Longitudinal superior | TERREO | 0.8 | 0.0000502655
V294 - Estribo | TERREO | 0.5 | 0.000019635
2 x V294 - Longitudinal inferior | TERREO | 0.8 | 0.0000502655
2 x V294 - Longitudinal superior | TERREO | 0.8 | 0.0000502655
V295 - Estribo | TERREO | 0.5 | 0.000019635
2 x V295 - Longitudinal construtiva | TERREO | 0.5 | 0.000019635
2 x V295 - Longitudinal inferior | TERREO | 0.8 | 0.0000502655
58 x V296 - Estribo | TERREO | 0.5 | 0.000019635
4 x V296 - Longitudinal inferior | TERREO | 0.8 | 0.0000502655
4 x V296 - Longitudinal superior | TERREO | 0.8 | 0.0000502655
63 x V297 - Estribo | TERREO | 0.5 | 0.000019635
4 x V297 - Longitudinal inferior | TERREO | 0.8 | 0.0000502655
4 x V297 - Longitudinal superior | TERREO | 0.8 | 0.0000502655
V298 - Estribo | TERREO | 0.5 | 0.000019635
2 x V298 - Longitudinal construtiva | TERREO | 0.5 | 0.000019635
2 x V298 - Longitudinal inferior | TERREO | 0.8 | 0.0000502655
27 x V299 - Estribo | TERREO | 0.5 | 0.000019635
2 x V299 - Longitudinal inferior | TERREO | 0.8 | 0.0000502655
2 x V299 - Longitudinal superior | TERREO | 0.8 | 0.0000502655
12 x V300 - Estribo | TERREO | 0.5 | 0.000019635
2 x V300 - Longitudinal inferior | TERREO | 0.8 | 0.0000502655
2 x V300 - Longitudinal superior | TERREO | 0.8 | 0.0000502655
15 x V301 - Estribo | TERREO | 0.5 | 0.000019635
2 x V301 - Longitudinal inferior | TERREO | 0.8 | 0.0000502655
2 x V301 - Longitudinal superior | TERREO | 0.8 | 0.0000502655
7 x V302 - Estribo | TERREO | 0.5 | 0.000019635
2 x V302 - Longitudinal inferior | TERREO | 0.8 | 0.0000502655
2 x V302 - Longitudinal superior | TERREO | 0.8 | 0.0000502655
29 x V303 - Estribo | TERREO | 0.5 | 0.000019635
2 x V303 - Grampo | TERREO | 0.5 | 0.000019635
2 x V303 - Longitudinal inferior | TERREO | 0.8 | 0.0000502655
2 x V303 - Longitudinal superior | TERREO | 0.8 | 0.0000502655
4 x V304 - Estribo | TERREO | 0.5 | 0.000019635
2 x V304 - Longitudinal inferior | TERREO | 0.8 | 0.0000502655
2 x V304 - Longitudinal superior | TERREO | 0.8 | 0.0000502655
64 x V305 - Estribo | TERREO | 0.5 | 0.000019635
2 x V305 - Longitudinal construtiva | TERREO | 0.5 | 0.000019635
2 x V305 - Longitudinal inferior | TERREO | 1 | 0.0000785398
4 x V305 - Longitudinal inferior | TERREO | 0.8 | 0.0000502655
4 x V305 - Longitudinal superior | TERREO | 1 | 0.0000785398
4 x V306 - Estribo | TERREO | 0.5 | 0.000019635
2 x V306 - Longitudinal inferior | TERREO | 0.8 | 0.0000502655
2 x V306 - Longitudinal superior | TERREO | 0.8 | 0.0000502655
30 x V307 - Estribo | TERREO | 0.5 | 0.000019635
2 x V307 - Longitudinal inferior | TERREO | 0.8 | 0.0000502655
2 x V307 - Longitudinal superior | TERREO | 0.8 | 0.0000502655
29 x V308 - Estribo | TERREO | 0.5 | 0.000019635
2 x V308 - Longitudinal inferior | TERREO | 0.8 | 0.0000502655
2 x V308 - Longitudinal superior | TERREO | 0.8 | 0.0000502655
12 x V309 - Estribo | TERREO | 0.5 | 0.000019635
2 x V309 - Longitudinal inferior | TERREO | 0.8 | 0.0000502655
2 x V309 - Longitudinal superior | TERREO | 0.8 | 0.0000502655
27 x V310 - Estribo | TERREO | 0.5 | 0.000019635
2 x V310 - Longitudinal construtiva | TERREO | 0.5 | 0.000019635
2 x V310 - Longitudinal inferior | TERREO | 1 | 0.0000785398
2 x V310 - Longitudinal superior | TERREO | 0.8 | 0.0000502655
4 x V311 - Estribo | TERREO | 0.5 | 0.000019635
V311 - Grampo | TERREO | 0.5 | 0.000019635
2 x V311 - Longitudinal inferior | TERREO | 0.8 | 0.0000502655
2 x V311 - Longitudinal superior | TERREO | 0.8 | 0.0000502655
25 x V312 - Estribo | TERREO | 0.5 | 0.000019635
2 x V312 - Longitudinal inferior | TERREO | 0.8 | 0.0000502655
2 x V312 - Longitudinal superior | TERREO | 0.8 | 0.0000502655
13 x V313 - Estribo | TERREO | 0.5 | 0.000019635
2 x V313 - Longitudinal inferior | TERREO | 0.8 | 0.0000502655
2 x V313 - Longitudinal superior | TERREO | 0.8 | 0.0000502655
23 x V314 - Estribo | TERREO | 0.5 | 0.000019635
2 x V314 - Longitudinal inferior | TERREO | 0.8 | 0.0000502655
2 x V314 - Longitudinal superior | TERREO | 0.8 | 0.0000502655
24 x V315 - Estribo | TERREO | 0.5 | 0.000019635
2 x V315 - Longitudinal inferior | TERREO | 0.8 | 0.0000502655
2 x V315 - Longitudinal superior | TERREO | 0.8 | 0.0000502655
13 x V316 - Estribo | TERREO | 0.5 | 0.000019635
2 x V316 - Longitudinal inferior | TERREO | 0.8 | 0.0000502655
2 x V316 - Longitudinal superior | TERREO | 0.8 | 0.0000502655
24 x V317 - Estribo | TERREO | 0.5 | 0.000019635
2 x V317 - Longitudinal inferior | TERREO | 0.8 | 0.0000502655
2 x V317 - Longitudinal superior | TERREO | 0.8 | 0.0000502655
245 x V318 - Estribo | TERREO | 0.5 | 0.000019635
10 x V318 - Longitudinal inferior | TERREO | 0.8 | 0.0000502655
8 x V318 - Longitudinal superior | TERREO | 0.8 | 0.0000502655
38 x V319 - Estribo | TERREO | 0.5 | 0.000019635
2 x V319 - Longitudinal inferior | TERREO | 0.8 | 0.0000502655
2 x V319 - Longitudinal superior | TERREO | 0.8 | 0.0000502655
43 x V320 - Estribo | TERREO | 0.5 | 0.000019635
2 x V320 - Longitudinal inferior | TERREO | 0.8 | 0.0000502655
2 x V320 - Longitudinal superior | TERREO | 0.8 | 0.0000502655
41 x V321 - Estribo | TERREO | 0.5 | 0.000019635
2 x V321 - Longitudinal inferior | TERREO | 0.8 | 0.0000502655
2 x V321 - Longitudinal superior | TERREO | 0.8 | 0.0000502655
51 x V322 - Estribo | TERREO | 0.5 | 0.000019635
2 x V322 - Longitudinal inferior | TERREO | 0.8 | 0.0000502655
2 x V322 - Longitudinal superior | TERREO | 0.8 | 0.0000502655
247 x V323 - Estribo | TERREO | 0.5 | 0.000019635
10 x V323 - Longitudinal inferior | TERREO | 0.8 | 0.0000502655
8 x V323 - Longitudinal superior | TERREO | 0.8 | 0.0000502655
271 x V324 - Estribo | TERREO | 0.5 | 0.000019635
12 x V324 - Longitudinal inferior | TERREO | 0.8 | 0.0000502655
8 x V324 - Longitudinal superior | TERREO | 0.8 | 0.0000502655
13 x V325 - Estribo | TERREO | 0.5 | 0.000019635
2 x V325 - Longitudinal inferior | TERREO | 0.8 | 0.0000502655
2 x V325 - Longitudinal superior | TERREO | 0.8 | 0.0000502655
11 x V326 - Estribo | TERREO | 0.5 | 0.000019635
2 x V326 - Longitudinal inferior | TERREO | 0.8 | 0.0000502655
2 x V326 - Longitudinal superior | TERREO | 0.8 | 0.0000502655
11 x V327 - Estribo | TERREO | 0.5 | 0.000019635
2 x V327 - Longitudinal inferior | TERREO | 0.8 | 0.0000502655
2 x V327 - Longitudinal superior | TERREO | 0.8 | 0.0000502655
28 x V328 - Estribo | TERREO | 0.5 | 0.000019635
2 x V328 - Longitudinal inferior | TERREO | 0.8 | 0.0000502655
2 x V328 - Longitudinal superior | TERREO | 0.8 | 0.0000502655
23 x V329 - Estribo | TERREO | 0.5 | 0.000019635
2 x V329 - Longitudinal inferior | TERREO | 0.8 | 0.0000502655
2 x V329 - Longitudinal superior | TERREO | 0.8 | 0.0000502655
20 x V330 - Estribo | TERREO | 0.5 | 0.000019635
2 x V330 - Longitudinal inferior | TERREO | 0.8 | 0.0000502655
2 x V330 - Longitudinal superior | TERREO | 0.8 | 0.0000502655
181 x V331 - Estribo | TERREO | 0.5 | 0.000019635
2 x V331 - Longitudinal inferior | TERREO | 1 | 0.0000785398
5 x V331 - Longitudinal inferior | TERREO | 0.8 | 0.0000502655
5 x V331 - Longitudinal superior | TERREO | 0.8 | 0.0000502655
225 x V332 - Estribo | TERREO | 0.5 | 0.000019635
4 x V332 - Longitudinal inferior | TERREO | 0.8 | 0.0000502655
4 x V332 - Longitudinal superior | TERREO | 0.8 | 0.0000502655
13 x P106 - Estribo | COBERTURA | 0.5 | 0.000019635
4 x P106 - Longitudinal | COBERTURA | 1 | 0.0000785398
13 x P113 - Estribo | COBERTURA | 0.5 | 0.000019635
4 x P113 - Longitudinal | COBERTURA | 1 | 0.0000785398
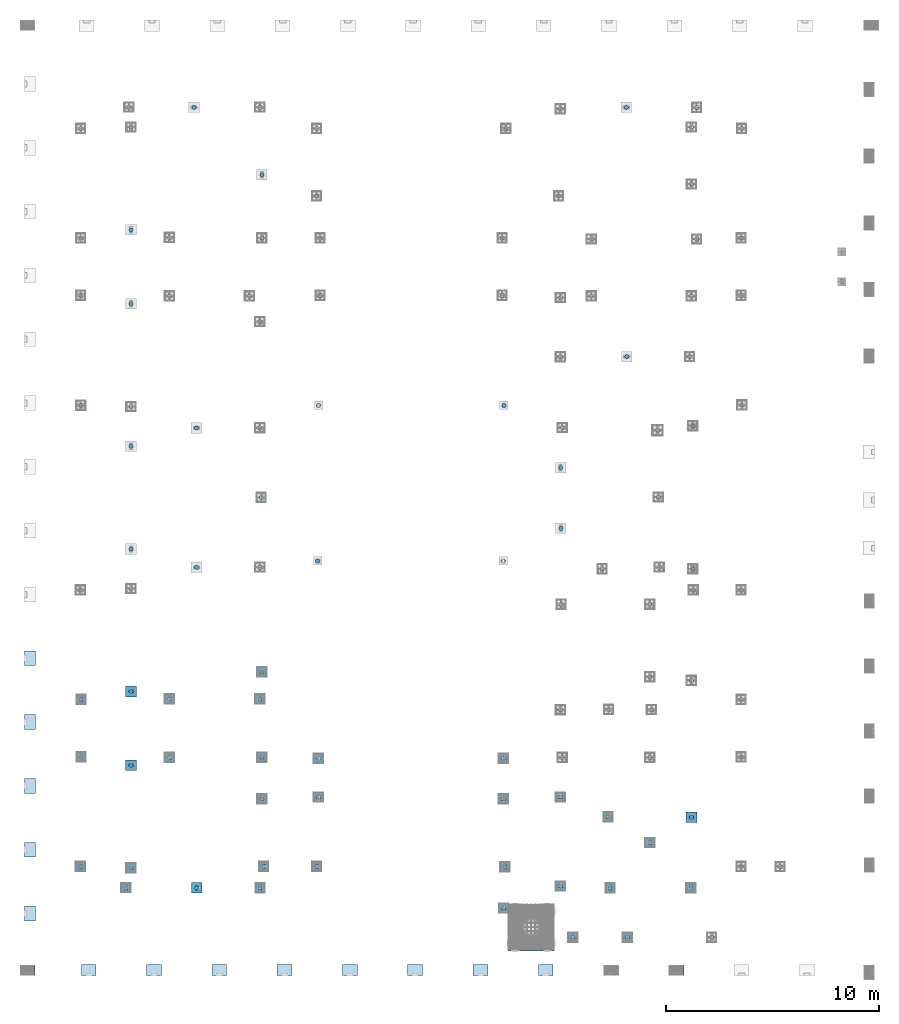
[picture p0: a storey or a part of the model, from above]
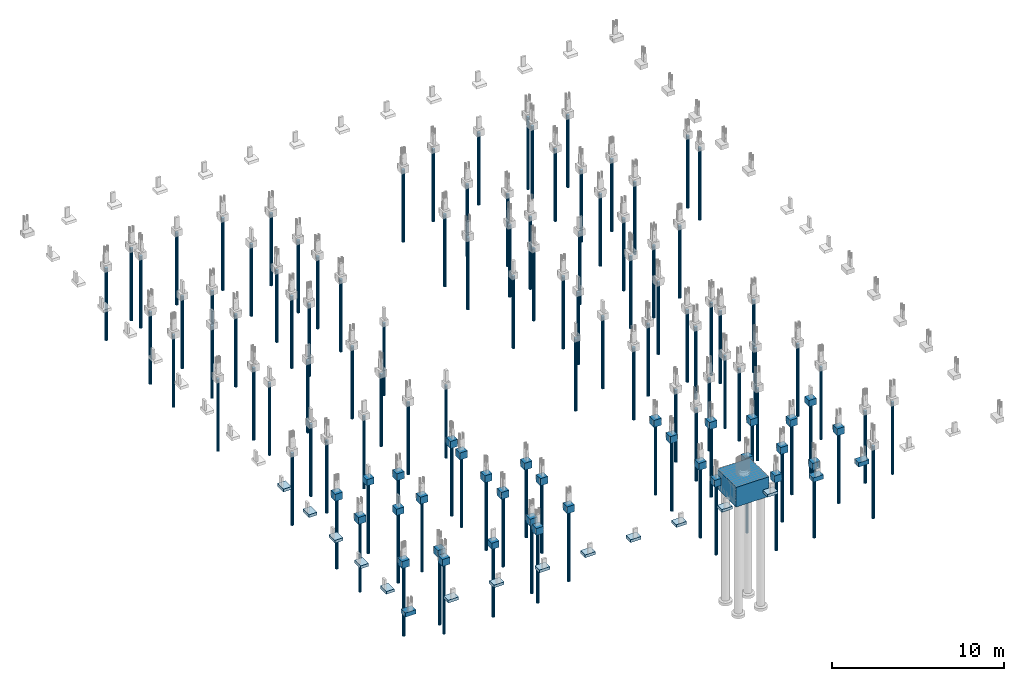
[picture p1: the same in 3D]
Properties of the parts of a building model (IFC4), part 9 of 9

# IfcReinforcingBar (17755)
Name | In | NominalDiameter (cm) | CrossSectionArea (m2)
13 x P116 - Estribo | COBERTURA | 0.5 | 0.000019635
4 x P116 - Longitudinal | COBERTURA | 1 | 0.0000785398
10 x P120 - Estribo | COBERTURA | 0.5 | 0.000019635
4 x P120 - Longitudinal | COBERTURA | 1.6 | 0.000201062
11 x P121 - Estribo | COBERTURA | 0.5 | 0.000019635
11 x P121 - Grampo | COBERTURA | 0.5 | 0.000019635
6 x P121 - Longitudinal | COBERTURA | 1 | 0.0000785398
13 x P124 - Estribo | COBERTURA | 0.5 | 0.000019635
4 x P124 - Longitudinal | COBERTURA | 1 | 0.0000785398
11 x P128 - Estribo | COBERTURA | 0.5 | 0.000019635
4 x P128 - Longitudinal | COBERTURA | 1 | 0.0000785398
11 x P135 - Estribo | COBERTURA | 0.5 | 0.000019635
4 x P135 - Longitudinal | COBERTURA | 1 | 0.0000785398
11 x P137 - Estribo | COBERTURA | 0.5 | 0.000019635
4 x P137 - Longitudinal | COBERTURA | 1 | 0.0000785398
11 x P138 - Estribo | COBERTURA | 0.5 | 0.000019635
4 x P138 - Longitudinal | COBERTURA | 1 | 0.0000785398
11 x P139 - Estribo | COBERTURA | 0.5 | 0.000019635
4 x P139 - Longitudinal | COBERTURA | 1 | 0.0000785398
11 x P140 - Estribo | COBERTURA | 0.5 | 0.000019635
4 x P140 - Longitudinal | COBERTURA | 1 | 0.0000785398
11 x P143 - Estribo | COBERTURA | 0.5 | 0.000019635
4 x P143 - Longitudinal | COBERTURA | 1 | 0.0000785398
11 x P145 - Estribo | COBERTURA | 0.5 | 0.000019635
4 x P145 - Longitudinal | COBERTURA | 1 | 0.0000785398
11 x P146 - Estribo | COBERTURA | 0.5 | 0.000019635
4 x P146 - Longitudinal | COBERTURA | 1 | 0.0000785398
11 x P147 - Estribo | COBERTURA | 0.5 | 0.000019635
4 x P147 - Longitudinal | COBERTURA | 1 | 0.0000785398
11 x P148 - Estribo | COBERTURA | 0.5 | 0.000019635
4 x P148 - Longitudinal | COBERTURA | 1 | 0.0000785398
11 x P169 - Estribo | COBERTURA | 0.5 | 0.000019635
4 x P169 - Longitudinal | COBERTURA | 1 | 0.0000785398
11 x P17 - Estribo | COBERTURA | 0.5 | 0.000019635
4 x P17 - Longitudinal | COBERTURA | 1 | 0.0000785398
11 x P170 - Estribo | COBERTURA | 0.5 | 0.000019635
4 x P170 - Longitudinal | COBERTURA | 1 | 0.0000785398
10 x P171 - Estribo | COBERTURA | 0.5 | 0.000019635
4 x P171 - Longitudinal | COBERTURA | 1 | 0.0000785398
10 x P172 - Estribo | COBERTURA | 0.5 | 0.000019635
4 x P172 - Longitudinal | COBERTURA | 1 | 0.0000785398
10 x P173 - Estribo | COBERTURA | 0.5 | 0.000019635
4 x P173 - Longitudinal | COBERTURA | 1 | 0.0000785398
10 x P174 - Estribo | COBERTURA | 0.5 | 0.000019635
4 x P174 - Longitudinal | COBERTURA | 1 | 0.0000785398
11 x P19 - Estribo | COBERTURA | 0.5 | 0.000019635
4 x P19 - Longitudinal | COBERTURA | 1 | 0.0000785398
11 x P20 - Estribo | COBERTURA | 0.5 | 0.000019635
11 x P20 - Grampo | COBERTURA | 0.5 | 0.000019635
6 x P20 - Longitudinal | COBERTURA | 1 | 0.0000785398
11 x P22 - Estribo | COBERTURA | 0.5 | 0.000019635
4 x P22 - Longitudinal | COBERTURA | 1 | 0.0000785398
11 x P23 - Estribo | COBERTURA | 0.5 | 0.000019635
4 x P23 - Longitudinal | COBERTURA | 1 | 0.0000785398
11 x P25 - Estribo | COBERTURA | 0.5 | 0.000019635
4 x P25 - Longitudinal | COBERTURA | 1 | 0.0000785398
11 x P26 - Estribo | COBERTURA | 0.5 | 0.000019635
4 x P26 - Longitudinal | COBERTURA | 1 | 0.0000785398
11 x P28 - Estribo | COBERTURA | 0.5 | 0.000019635
4 x P28 - Longitudinal | COBERTURA | 1 | 0.0000785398
11 x P33 - Estribo | COBERTURA | 0.5 | 0.000019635
4 x P33 - Longitudinal | COBERTURA | 1 | 0.0000785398
13 x P36 - Estribo | COBERTURA | 0.5 | 0.000019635
4 x P36 - Longitudinal | COBERTURA | 1 | 0.0000785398
13 x P41 - Estribo | COBERTURA | 0.5 | 0.000019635
4 x P41 - Longitudinal | COBERTURA | 1 | 0.0000785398
13 x P42 - Estribo | COBERTURA | 0.5 | 0.000019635
4 x P42 - Longitudinal | COBERTURA | 1 | 0.0000785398
13 x P45 - Estribo | COBERTURA | 0.5 | 0.000019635
4 x P45 - Longitudinal | COBERTURA | 1 | 0.0000785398
13 x P47 - Estribo | COBERTURA | 0.5 | 0.000019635
4 x P47 - Longitudinal | COBERTURA | 1 | 0.0000785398
13 x P51 - Estribo | COBERTURA | 0.5 | 0.000019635
4 x P51 - Longitudinal | COBERTURA | 1 | 0.0000785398
13 x P52 - Estribo | COBERTURA | 0.5 | 0.000019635
4 x P52 - Longitudinal | COBERTURA | 1 | 0.0000785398
13 x P56 - Estribo | COBERTURA | 0.5 | 0.000019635
4 x P56 - Longitudinal | COBERTURA | 1 | 0.0000785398
16 x P65 - Estribo | COBERTURA | 0.5 | 0.000019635
4 x P65 - Longitudinal | COBERTURA | 1 | 0.0000785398
16 x P66 - Estribo | COBERTURA | 0.5 | 0.000019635
4 x P66 - Longitudinal | COBERTURA | 1 | 0.0000785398
16 x P69 - Estribo | COBERTURA | 0.5 | 0.000019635
4 x P69 - Longitudinal | COBERTURA | 1 | 0.0000785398
16 x P74 - Estribo | COBERTURA | 0.5 | 0.000019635
4 x P74 - Longitudinal | COBERTURA | 1 | 0.0000785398
16 x P92 - Estribo | COBERTURA | 0.5 | 0.000019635
4 x P92 - Longitudinal | COBERTURA | 1 | 0.0000785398
16 x P94 - Estribo | COBERTURA | 0.5 | 0.000019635
4 x P94 - Longitudinal | COBERTURA | 1 | 0.0000785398
16 x P95 - Estribo | COBERTURA | 0.5 | 0.000019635
4 x P95 - Longitudinal | COBERTURA | 1 | 0.0000785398
16 x P96 - Estribo | COBERTURA | 0.5 | 0.000019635
4 x P96 - Longitudinal | COBERTURA | 1 | 0.0000785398
16 x P97 - Estribo | COBERTURA | 0.5 | 0.000019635
4 x P97 - Longitudinal | COBERTURA | 1 | 0.0000785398
26 x V301 - Estribo | COBERTURA | 0.5 | 0.000019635
4 x V301 - Grampo | COBERTURA | 0.5 | 0.000019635
2 x V301 - Longitudinal construtiva | COBERTURA | 0.5 | 0.000019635
2 x V301 - Longitudinal inferior | COBERTURA | 0.8 | 0.0000502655
4 x V301 - Longitudinal superior | COBERTURA | 0.8 | 0.0000502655
26 x V302 - Estribo | COBERTURA | 0.5 | 0.000019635
2 x V302 - Longitudinal construtiva | COBERTURA | 0.5 | 0.000019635
2 x V302 - Longitudinal inferior | COBERTURA | 0.8 | 0.0000502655
4 x V302 - Longitudinal superior | COBERTURA | 0.8 | 0.0000502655
11 x V303 - Estribo | COBERTURA | 0.5 | 0.000019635
4 x V303 - Grampo | COBERTURA | 0.5 | 0.000019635
2 x V303 - Longitudinal inferior | COBERTURA | 0.8 | 0.0000502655
2 x V303 - Longitudinal superior | COBERTURA | 0.8 | 0.0000502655
10 x V304 - Estribo | COBERTURA | 0.5 | 0.000019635
2 x V304 - Longitudinal inferior | COBERTURA | 0.8 | 0.0000502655
2 x V304 - Longitudinal superior | COBERTURA | 0.8 | 0.0000502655
12 x V305 - Estribo | COBERTURA | 0.5 | 0.000019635
2 x V305 - Longitudinal inferior | COBERTURA | 0.8 | 0.0000502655
2 x V305 - Longitudinal superior | COBERTURA | 0.8 | 0.0000502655
10 x V306 - Estribo | COBERTURA | 0.5 | 0.000019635
4 x V306 - Grampo | COBERTURA | 0.5 | 0.000019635
2 x V306 - Longitudinal inferior | COBERTURA | 0.8 | 0.0000502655
2 x V306 - Longitudinal superior | COBERTURA | 0.8 | 0.0000502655
V307 - Estribo | COBERTURA | 0.5 | 0.000019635
2 x V307 - Longitudinal inferior | COBERTURA | 0.8 | 0.0000502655
2 x V307 - Longitudinal superior | COBERTURA | 0.8 | 0.0000502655
2 x V308 - Estribo | COBERTURA | 0.5 | 0.000019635
4 x V308 - Grampo | COBERTURA | 0.5 | 0.000019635
2 x V308 - Longitudinal inferior | COBERTURA | 0.8 | 0.0000502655
2 x V308 - Longitudinal superior | COBERTURA | 1 | 0.0000785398
V309 - Estribo | COBERTURA | 0.5 | 0.000019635
2 x V309 - Longitudinal inferior | COBERTURA | 0.8 | 0.0000502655
2 x V309 - Longitudinal superior | COBERTURA | 0.8 | 0.0000502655
V310 - Estribo | COBERTURA | 0.5 | 0.000019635
2 x V310 - Longitudinal inferior | COBERTURA | 0.8 | 0.0000502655
2 x V310 - Longitudinal superior | COBERTURA | 0.8 | 0.0000502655
V311 - Estribo | COBERTURA | 0.5 | 0.000019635
2 x V311 - Longitudinal inferior | COBERTURA | 0.8 | 0.0000502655
2 x V311 - Longitudinal superior | COBERTURA | 0.8 | 0.0000502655
2 x V312 - Estribo | COBERTURA | 0.5 | 0.000019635
4 x V312 - Grampo | COBERTURA | 0.5 | 0.000019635
2 x V312 - Longitudinal inferior | COBERTURA | 0.8 | 0.0000502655
2 x V312 - Longitudinal superior | COBERTURA | 1 | 0.0000785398
V313 - Estribo | COBERTURA | 0.5 | 0.000019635
2 x V313 - Longitudinal inferior | COBERTURA | 0.8 | 0.0000502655
2 x V313 - Longitudinal superior | COBERTURA | 0.8 | 0.0000502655
V314 - Estribo | COBERTURA | 0.5 | 0.000019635
2 x V314 - Longitudinal inferior | COBERTURA | 0.8 | 0.0000502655
2 x V314 - Longitudinal superior | COBERTURA | 0.8 | 0.0000502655
13 x V315 - Estribo | COBERTURA | 0.5 | 0.000019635
V315 - Grampo | COBERTURA | 0.5 | 0.000019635
2 x V315 - Longitudinal inferior | COBERTURA | 0.8 | 0.0000502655
2 x V315 - Longitudinal superior | COBERTURA | 0.8 | 0.0000502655
11 x V316 - Estribo | COBERTURA | 0.5 | 0.000019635
2 x V316 - Longitudinal inferior | COBERTURA | 0.8 | 0.0000502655
2 x V316 - Longitudinal superior | COBERTURA | 0.8 | 0.0000502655
8 x V317 - Estribo | COBERTURA | 0.5 | 0.000019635
V317 - Grampo | COBERTURA | 0.5 | 0.000019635
2 x V317 - Longitudinal inferior | COBERTURA | 0.8 | 0.0000502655
2 x V317 - Longitudinal superior | COBERTURA | 0.8 | 0.0000502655
8 x V318 - Estribo | COBERTURA | 0.5 | 0.000019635
2 x V318 - Longitudinal inferior | COBERTURA | 0.8 | 0.0000502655
2 x V318 - Longitudinal superior | COBERTURA | 0.8 | 0.0000502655
12 x V319 - Estribo | COBERTURA | 0.5 | 0.000019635
V319 - Grampo | COBERTURA | 0.5 | 0.000019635
2 x V319 - Longitudinal inferior | COBERTURA | 0.8 | 0.0000502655
2 x V319 - Longitudinal superior | COBERTURA | 0.8 | 0.0000502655
12 x V320 - Estribo | COBERTURA | 0.5 | 0.000019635
4 x V320 - Grampo | COBERTURA | 0.5 | 0.000019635
2 x V320 - Longitudinal inferior | COBERTURA | 0.8 | 0.0000502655
2 x V320 - Longitudinal superior | COBERTURA | 1 | 0.0000785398
V321 - Estribo | COBERTURA | 0.5 | 0.000019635
2 x V321 - Longitudinal inferior | COBERTURA | 0.8 | 0.0000502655
2 x V321 - Longitudinal superior | COBERTURA | 0.8 | 0.0000502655
2 x V322 - Estribo | COBERTURA | 0.5 | 0.000019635
2 x V322 - Longitudinal inferior | COBERTURA | 0.8 | 0.0000502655
2 x V322 - Longitudinal superior | COBERTURA | 0.8 | 0.0000502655
2 x V323 - Estribo | COBERTURA | 0.5 | 0.000019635
2 x V323 - Longitudinal inferior | COBERTURA | 0.8 | 0.0000502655
2 x V323 - Longitudinal superior | COBERTURA | 0.8 | 0.0000502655
2 x V324 - Estribo | COBERTURA | 0.5 | 0.000019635
2 x V324 - Longitudinal inferior | COBERTURA | 0.8 | 0.0000502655
2 x V324 - Longitudinal superior | COBERTURA | 0.8 | 0.0000502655
10 x V325 - Estribo | COBERTURA | 0.5 | 0.000019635
4 x V325 - Grampo | COBERTURA | 0.5 | 0.000019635
2 x V325 - Longitudinal inferior | COBERTURA | 0.8 | 0.0000502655
2 x V325 - Longitudinal superior | COBERTURA | 0.8 | 0.0000502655
10 x V326 - Estribo | COBERTURA | 0.5 | 0.000019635
2 x V326 - Longitudinal inferior | COBERTURA | 0.8 | 0.0000502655
2 x V326 - Longitudinal superior | COBERTURA | 0.8 | 0.0000502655
10 x V327 - Estribo | COBERTURA | 0.5 | 0.000019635
2 x V327 - Longitudinal inferior | COBERTURA | 0.8 | 0.0000502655
2 x V327 - Longitudinal superior | COBERTURA | 0.8 | 0.0000502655
10 x V328 - Estribo | COBERTURA | 0.5 | 0.000019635
2 x V328 - Longitudinal inferior | COBERTURA | 0.8 | 0.0000502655
2 x V328 - Longitudinal superior | COBERTURA | 0.8 | 0.0000502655
27 x V329 - Estribo | COBERTURA | 0.5 | 0.000019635
2 x V329 - Longitudinal construtiva | COBERTURA | 0.5 | 0.000019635
2 x V329 - Longitudinal inferior | COBERTURA | 0.8 | 0.0000502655
4 x V329 - Longitudinal superior | COBERTURA | 0.8 | 0.0000502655
26 x V330 - Estribo | COBERTURA | 0.5 | 0.000019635
4 x V330 - Grampo | COBERTURA | 0.5 | 0.000019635
2 x V330 - Longitudinal inferior | COBERTURA | 0.8 | 0.0000502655
2 x V330 - Longitudinal superior | COBERTURA | 0.8 | 0.0000502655
22 x V331 - Estribo | COBERTURA | 0.5 | 0.000019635
2 x V331 - Longitudinal inferior | COBERTURA | 0.8 | 0.0000502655
2 x V331 - Longitudinal superior | COBERTURA | 0.8 | 0.0000502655
12 x V332 - Estribo | COBERTURA | 0.5 | 0.000019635
2 x V332 - Longitudinal inferior | COBERTURA | 0.8 | 0.0000502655
2 x V332 - Longitudinal superior | COBERTURA | 0.8 | 0.0000502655
22 x V333 - Estribo | COBERTURA | 0.5 | 0.000019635
2 x V333 - Longitudinal inferior | COBERTURA | 0.8 | 0.0000502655
2 x V333 - Longitudinal superior | COBERTURA | 0.8 | 0.0000502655
23 x V334 - Estribo | COBERTURA | 0.5 | 0.000019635
2 x V334 - Longitudinal inferior | COBERTURA | 0.8 | 0.0000502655
2 x V334 - Longitudinal superior | COBERTURA | 0.8 | 0.0000502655
12 x V335 - Estribo | COBERTURA | 0.5 | 0.000019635
2 x V335 - Longitudinal inferior | COBERTURA | 0.8 | 0.0000502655
2 x V335 - Longitudinal superior | COBERTURA | 0.8 | 0.0000502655
23 x V336 - Estribo | COBERTURA | 0.5 | 0.000019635
2 x V336 - Longitudinal inferior | COBERTURA | 0.8 | 0.0000502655
2 x V336 - Longitudinal superior | COBERTURA | 0.8 | 0.0000502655
5 x V337 - Estribo | COBERTURA | 0.5 | 0.000019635
2 x V337 - Longitudinal inferior | COBERTURA | 0.8 | 0.0000502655
2 x V337 - Longitudinal superior | COBERTURA | 0.8 | 0.0000502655
35 x V338 - Estribo | COBERTURA | 0.5 | 0.000019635
2 x V338 - Longitudinal inferior | COBERTURA | 0.8 | 0.0000502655
2 x V338 - Longitudinal superior | COBERTURA | 0.8 | 0.0000502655
5 x V339 - Estribo | COBERTURA | 0.5 | 0.000019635
2 x V339 - Longitudinal inferior | COBERTURA | 0.8 | 0.0000502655
2 x V339 - Longitudinal superior | COBERTURA | 0.8 | 0.0000502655
5 x V340 - Estribo | COBERTURA | 0.5 | 0.000019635
2 x V340 - Longitudinal inferior | COBERTURA | 0.8 | 0.0000502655
2 x V340 - Longitudinal superior | COBERTURA | 0.8 | 0.0000502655
5 x V341 - Estribo | COBERTURA | 0.5 | 0.000019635
2 x V341 - Longitudinal inferior | COBERTURA | 0.8 | 0.0000502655
2 x V341 - Longitudinal superior | COBERTURA | 0.8 | 0.0000502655
40 x V342 - Estribo | COBERTURA | 0.5 | 0.000019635
2 x V342 - Longitudinal inferior | COBERTURA | 0.8 | 0.0000502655
2 x V342 - Longitudinal superior | COBERTURA | 0.8 | 0.0000502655
36 x V343 - Estribo | COBERTURA | 0.5 | 0.000019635
2 x V343 - Longitudinal inferior | COBERTURA | 0.8 | 0.0000502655
2 x V343 - Longitudinal superior | COBERTURA | 0.8 | 0.0000502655
37 x V344 - Estribo | COBERTURA | 0.5 | 0.000019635
2 x V344 - Longitudinal inferior | COBERTURA | 0.8 | 0.0000502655
2 x V344 - Longitudinal superior | COBERTURA | 0.8 | 0.0000502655
13 x V345 - Estribo | COBERTURA | 0.5 | 0.000019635
2 x V345 - Grampo | COBERTURA | 0.5 | 0.000019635
2 x V345 - Longitudinal inferior | COBERTURA | 0.8 | 0.0000502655
2 x V345 - Longitudinal superior | COBERTURA | 0.8 | 0.0000502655
21 x V346 - Estribo | COBERTURA | 0.5 | 0.000019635
2 x V346 - Longitudinal inferior | COBERTURA | 0.8 | 0.0000502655
2 x V346 - Longitudinal superior | COBERTURA | 0.8 | 0.0000502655
42 x V347 - Estribo | COBERTURA | 0.5 | 0.000019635
2 x V347 - Longitudinal inferior | COBERTURA | 0.8 | 0.0000502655
2 x V347 - Longitudinal superior | COBERTURA | 0.8 | 0.0000502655
36 x V348 - Estribo | COBERTURA | 0.5 | 0.000019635
2 x V348 - Longitudinal inferior | COBERTURA | 0.8 | 0.0000502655
2 x V348 - Longitudinal superior | COBERTURA | 0.8 | 0.0000502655
37 x V349 - Estribo | COBERTURA | 0.5 | 0.000019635
2 x V349 - Longitudinal inferior | COBERTURA | 0.8 | 0.0000502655
2 x V349 - Longitudinal superior | COBERTURA | 0.8 | 0.0000502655
12 x V350 - Estribo | COBERTURA | 0.5 | 0.000019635
2 x V350 - Longitudinal inferior | COBERTURA | 0.8 | 0.0000502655
2 x V350 - Longitudinal superior | COBERTURA | 0.8 | 0.0000502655
22 x V351 - Estribo | COBERTURA | 0.5 | 0.000019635
2 x V351 - Longitudinal inferior | COBERTURA | 0.8 | 0.0000502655
2 x V351 - Longitudinal superior | COBERTURA | 0.8 | 0.0000502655
4 x V352 - Estribo | COBERTURA | 0.5 | 0.000019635
2 x V352 - Longitudinal inferior | COBERTURA | 0.8 | 0.0000502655
2 x V352 - Longitudinal superior | COBERTURA | 0.8 | 0.0000502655
4 x V353 - Estribo | COBERTURA | 0.5 | 0.000019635
2 x V353 - Longitudinal inferior | COBERTURA | 0.8 | 0.0000502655
2 x V353 - Longitudinal superior | COBERTURA | 0.8 | 0.0000502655
4 x V354 - Estribo | COBERTURA | 0.5 | 0.000019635
2 x V354 - Longitudinal construtiva | COBERTURA | 0.5 | 0.000019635
2 x V354 - Longitudinal inferior | COBERTURA | 0.8 | 0.0000502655
40 x V355 - Estribo | COBERTURA | 0.5 | 0.000019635
2 x V355 - Longitudinal construtiva | COBERTURA | 0.5 | 0.000019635
2 x V355 - Longitudinal inferior | COBERTURA | 0.8 | 0.0000502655
4 x V355 - Longitudinal superior | COBERTURA | 0.8 | 0.0000502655
5 x V356 - Estribo | COBERTURA | 0.5 | 0.000019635
2 x V356 - Longitudinal inferior | COBERTURA | 0.8 | 0.0000502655
2 x V356 - Longitudinal superior | COBERTURA | 0.8 | 0.0000502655
21 x V357 - Estribo | COBERTURA | 0.5 | 0.000019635
2 x V357 - Longitudinal inferior | COBERTURA | 0.8 | 0.0000502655
2 x V357 - Longitudinal superior | COBERTURA | 0.8 | 0.0000502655
12 x V358 - Estribo | COBERTURA | 0.5 | 0.000019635
2 x V358 - Longitudinal inferior | COBERTURA | 0.8 | 0.0000502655
2 x V358 - Longitudinal superior | COBERTURA | 0.8 | 0.0000502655
21 x V359 - Estribo | COBERTURA | 0.5 | 0.000019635
2 x V359 - Longitudinal inferior | COBERTURA | 0.8 | 0.0000502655
2 x V359 - Longitudinal superior | COBERTURA | 0.8 | 0.0000502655
22 x V360 - Estribo | COBERTURA | 0.5 | 0.000019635
2 x V360 - Longitudinal inferior | COBERTURA | 0.8 | 0.0000502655
2 x V360 - Longitudinal superior | COBERTURA | 0.8 | 0.0000502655
12 x V361 - Estribo | COBERTURA | 0.5 | 0.000019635
2 x V361 - Longitudinal inferior | COBERTURA | 0.8 | 0.0000502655
2 x V361 - Longitudinal superior | COBERTURA | 0.8 | 0.0000502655
22 x V362 - Estribo | COBERTURA | 0.5 | 0.000019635
2 x V362 - Longitudinal inferior | COBERTURA | 0.8 | 0.0000502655
2 x V362 - Longitudinal superior | COBERTURA | 0.8 | 0.0000502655

# IfcSlab (5)
PredefinedType: FLOOR; Material: Concreto
Pset_ConcreteElementGeneral - ConstructionMethod: InSitu; ExposureClass: 1; StrengthClass: C-30
AltoQi_Eberick_Elemento - Tipo: Maciça; Elevação: 0 cm
AltoQi_Eberick_Padrão - Ambiente: Contato com solo; Classe de concreto: C-30
AltoQi_Eberick-Item_01 - Status_01: Dimensionado
AltoQi_Eberick-Item_02 - Descrição_02: Forma - Estrutura - Concreto; Status_02: Dimensionado
AltoQi_Eberick-Item_03 - Status_03: Dimensionado
AltoQi_Eberick_Cargas - Adicional (G2): 0; Solo (S): 0; Água (A): 0; Subpressão (AS): 0
Pset_SlabCommon - LoadBearing: yes; IsExternal: yes; PitchAngle: 0 rad
Name | In | ConcreteCover (cm) = Cobrimento (cm) | Elemento | Espessura (cm) | Descrição_01 | Quantidade_01 (m3) | Quantidade_02 (m2) | Descrição_03 | Quantidade_03 (kg) | Revestimento (G2) | Acidental (Q) | Reference | Descrição_04 | Quantidade_04 (kg) | Status_04 = Status_05 | Descrição_05 | Quantidade_05 (kg)
LM1 | VIGA BALDRAME | 3 | Radier | 25 | Concreto - C-30 - Abatimento 12 cm | 0.289 | 0.975 | Armadura - Aço CA50 - ø 8.0 mm | 14.3629 | 200 | 400 | Laje de fundação C-30 - h=25cm
LM2 | VIGA BALDRAME | 3 | Radier | 25 | Concreto - C-30 - Abatimento 12 cm | 0.289 | 0.975 | Armadura - Aço CA50 - ø 8.0 mm | 14.3629 | 200 | 400 | Laje de fundação C-30 - h=25cm
L1 | TERREO | 2 | Laje | 12 | Concreto - C-30 - Abatimento 5 cm | 0.454241 | 4.14769 | Armadura - Aço CA60 - Ø 5.0 mm | 7.70956 | 100 | 200 | Laje Maciça - h=12cm | Armadura - Aço CA50 - Ø 6.3 mm | 0.260014 | Dimensionado | Armadura - Aço CA50 - Ø 10.0 mm | 6.07116
L2 | TERREO | 2 | Laje | 12 | Concreto - C-30 - Abatimento 5 cm | 0.257358 | 2.34994 | Armadura - Aço CA60 - Ø 5.0 mm | 4.36799 | 50 | 0 | Laje Maciça - h=12cm | Armadura - Aço CA50 - Ø 6.3 mm | 0.147315 | Dimensionado | Armadura - Aço CA50 - Ø 10.0 mm | 3.43972
L3 | TERREO | 2 | Laje | 12 | Concreto - C-30 - Abatimento 5 cm | 0.738401 | 6.74237 | Armadura - Aço CA60 - Ø 5.0 mm | 12.5325 | 100 | 200 | Laje Maciça - h=12cm | Armadura - Aço CA50 - Ø 6.3 mm | 0.422671 | Dimensionado | Armadura - Aço CA50 - Ø 10.0 mm | 9.86911
